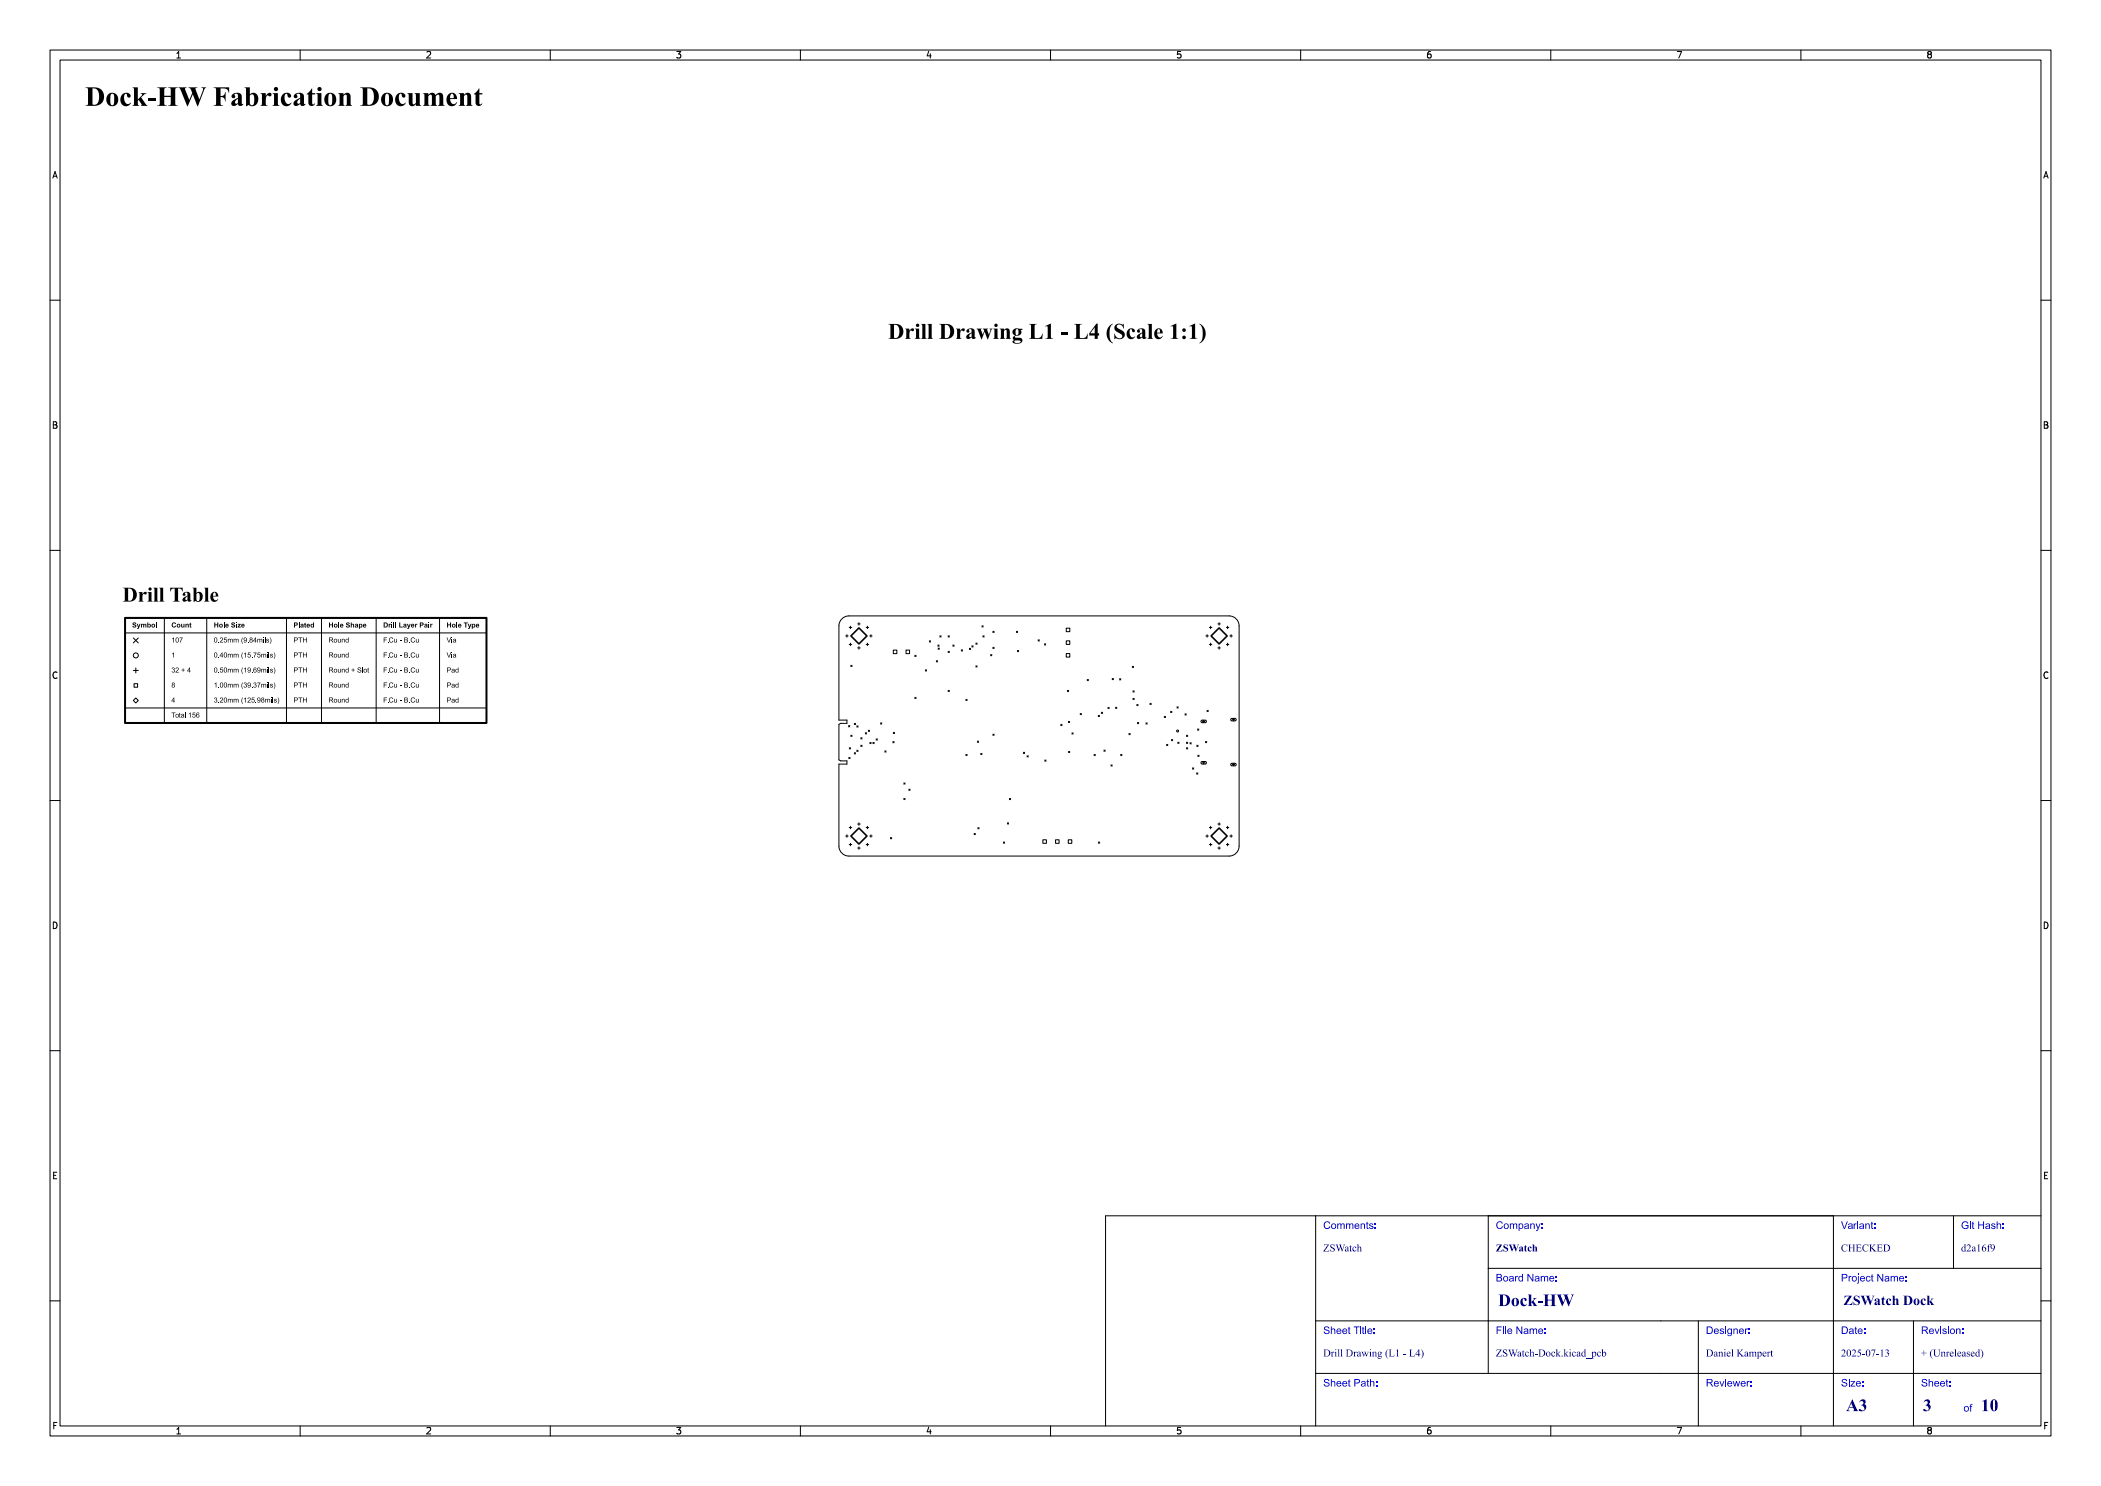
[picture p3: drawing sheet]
<svg xmlns="http://www.w3.org/2000/svg" width="420mm" height="297mm" viewBox="0 0 420 297" stroke-linecap="round" stroke-linejoin="round" font-family="sans-serif">
<defs><g id="words">
<text font-size="5.3" fill="#fff" x="17" y="21.5">Dock-HW Fabrication Document</text>
<text font-size="4.3" fill="#fff" x="166.6" y="68">Drill Drawing L1 - L4 (Scale 1:1)</text>
<g font-size="3.3" fill="#fff">
<text x="299.5" y="261.2">Dock-HW</text>
<text x="369" y="282.2">A3</text>
<text x="384.4" y="282.3">3</text>
<text x="396" y="282.3">10</text>
</g>
<text font-size="2.7" fill="#fff" x="368.5" y="261">ZSWatch Dock</text>
<g font-size="2" fill="#fff">
<text x="264.5" y="245.8">Comments:</text>
<text x="299" y="245.8">Company:</text>
<text x="368" y="245.8">Variant:</text>
<text x="392" y="245.8">Git Hash:</text>
<text x="264.5" y="250.2">ZSWatch</text>
<text x="299" y="250.2">ZSWatch</text>
<text x="368" y="250.2">CHECKED</text>
<text x="392" y="250.2">d2a16f9</text>
<text x="299" y="256.2">Board Name:</text>
<text x="368" y="256.2">Project Name:</text>
<text x="264.5" y="266.8">Sheet Title:</text>
<text x="299" y="266.8">File Name:</text>
<text x="341" y="266.8">Designer:</text>
<text x="368" y="266.8">Date:</text>
<text x="384" y="266.8">Revision:</text>
<text x="264.5" y="271.2">Drill Drawing (L1 - L4)</text>
<text x="299" y="271.2">ZSWatch-Dock.kicad_pcb</text>
<text x="341" y="271.2">Daniel Kampert</text>
<text x="368" y="271.2">2025-07-13</text>
<text x="384" y="271.2">+ (Unreleased)</text>
<text x="264.5" y="277.3">Sheet Path:</text>
<text x="341" y="277.2">Reviewer:</text>
<text x="368" y="277.3">Size:</text>
<text x="384" y="277.2">Sheet:</text>
<text x="392.5" y="282.3">of</text>
</g>
<g font-size="1.7" fill="#fff">
<text x="35" y="11.6">1</text>
<text x="85" y="11.6">2</text>
<text x="135" y="11.6">3</text>
<text x="185" y="11.6">4</text>
<text x="235" y="11.6">5</text>
<text x="285" y="11.6">6</text>
<text x="335" y="11.6">7</text>
<text x="385" y="11.6">8</text>
<text x="10.5" y="35.6">A</text>
<text x="408.5" y="35.6">A</text>
<text x="10.5" y="85.6">B</text>
<text x="408.5" y="85.6">B</text>
<text x="10.5" y="135.7">C</text>
<text x="408.5" y="135.7">C</text>
<text x="10.5" y="185.6">D</text>
<text x="408.5" y="185.6">D</text>
<text x="10.5" y="235.7">E</text>
<text x="408.5" y="235.7">E</text>
<text x="10.5" y="285.6">F</text>
<text x="35" y="286.7">1</text>
<text x="85" y="286.7">2</text>
<text x="135" y="286.7">3</text>
<text x="185" y="286.7">4</text>
<text x="235" y="286.7">5</text>
<text x="285" y="286.7">6</text>
<text x="335" y="286.7">7</text>
<text x="385" y="286.7">8</text>
<text x="408.5" y="285.6">F</text>
</g>
</g></defs>
<path d="M25 123.5h72.2v21h-72.2z" fill="none" stroke="#000" stroke-width=".4"/>
<g fill="none" stroke="#000" stroke-width=".2">
<path d="M10 10h400v277h-400zM12 12h396v273h-396zM35.3 11.6h.8M35.3 10.7l.4-.4v1.3M60 10v2M85.3 10.4l.5-.1 .3 .4-.8 .9h.8M110 10v2M135.3 10.3h.8l-.4 .5 .3 .1v.6l-.2 .1-.5-.1M160 10v2M185.7 10.2l-.4 1h.9M186 10.7v.9M210 10v2"/>
<path d="M236 10.3h-.6l-.1 .6 .2-.1 .5 .1 .1 .1-.1 .5-.2 .1-.5-.1M260 10v2M286 10.3l-.4 .1-.2 .2-.1 .7 .3 .3 .4-.1 .1-.5-.1-.1-.4-.1-.3 .2M310 10v2M335.3 10.3h.9l-.6 1.3M360 10v2M385.6 10.9l-.3 .2 .1 .4 .2 .1 .4-.1 .1-.2-.1-.3-.2-.1M385.6 10.9l-.3-.3 .3-.3h.2l.3 .2-.3 .4M385.6 10.9h.2M10.6 35.6l.4-1.3 .4 1.3M10.7 35.2h.6M408.6 35.6l.4-1.3 .4 1.3"/>
<path d="M408.7 35.2h.6M10 60h2M408 60h2M10.7 84.3h.4l.2 .2-.2 .4 .2 .1 .1 .3-.2 .3h-.5zM10.7 84.9h.4M408.6 84.3h.5l.2 .2-.2 .4 .2 .1 .1 .3-.3 .3h-.5zM408.6 84.9h.5M10 110h2M408 110h2M11.4 134.4a.62 .62 0 0 0-.9 .5 .62 .62 0 0 0 .7 .7l.2-.1M25 123.5h72.2M25 126.5h72.2"/>
<path d="M26.6 134h1.1M26.6 127.5l1.1 1M26.8 136.6h.7v.8h-.7zM27.2 133.5v1M27.7 127.5l-1.1 1M32.9 123.5v21M41.3 123.5v21M57.3 123.5v21M64.3 123.5v21M75.2 123.5v21M87.9 123.5v21M168.3 123.7l.9-.5 .5-.1h76a2 2 0 0 1 2 2v44a2 2 0 0 1-2 2h-76a2 2 0 0 1-2-2v-16.4h1.6v-.6h-1.2l-.4-.2v-7.1l.4-.2h1.2v-.7h-1.6v-18.8l.1-.5z"/>
<path d="M169 127.1h.5M169.3 126.8v.5M169.8 128.8h.5M169.8 125.4h.5M170 125.2v.5M170 128.5v.5M170.1 133l.2 .2M170.3 133l-.2 .2M171.4 129.5h.6M171.4 124.7h.6M171.7 124.5v.4M171.7 129.3v.5"/>
<path d="M173.1 128.8h.5M173.1 125.4h.5M173.4 125.2v.5M173.4 128.5v.5M173.9 127.1h.4M174.1 126.8v.5M178.6 129.9h.7v.7h-.7zM181.1 129.9h.7v.7h-.7zM182.9 139.4l.2 .2M182.9 131l.2 .2M183.1 131l-.2 .2M183.1 139.4l-.2 .2"/>
<path d="M185 133.9l.2 .2M185.2 133.9l-.2 .2M185.8 128.1l.2 .2M186 128.1l-.2 .2M187.2 132.1l.2 .2M187.4 132.1l-.2 .2M187.5 128.9l.2 .3M187.5 129.5l.3 .3M187.7 128.9l-.2 .3M187.8 129.5l-.3 .3M187.9 127.1l.2 .2M188.1 127.1l-.2 .2"/>
<path d="M189.5 138l.3 .2M189.5 130.2l.3 .2M189.5 127.1l.3 .2M189.8 138l-.3 .2M189.8 130.2l-.3 .2M189.8 127.1l-.3 .2M190.5 128.9l.2 .3M190.7 128.9l-.2 .3M192.2 129.9l.2 .2M192.4 129.9l-.2 .2M193.1 139.8l.2 .2M193.3 139.8l-.2 .2"/>
<path d="M193.8 129.6l.2 .2M194 129.6l-.2 .2M194.3 129.1l.2 .2M194.5 129.1l-.2 .2M195.1 133.1l.2 .2M195.1 128.5l.2 .3M195.3 128.5l-.2 .3M195.3 133.1l-.2 .2M196.3 125.1l.2 .2M196.5 127.1l.2 .2M196.5 125.1l-.2 .2M196.7 127.1l-.2 .2"/>
<path d="M198 130.8l.3 .3M198.3 130.8l-.3 .3M198.5 129.4l.2 .2M198.5 126.2l.2 .2M198.7 129.4l-.2 .2M198.7 126.2l-.2 .2M203.2 126.2l.2 .2M203.4 130l.2 .2M203.4 126.2l-.2 .2M203.6 130l-.2 .2M207.5 127.9l.3 .2M207.8 127.9l-.3 .2"/>
<path d="M208.8 128.7l.2 .2M209 128.7l-.2 .2M213.1 130.6h.8v.7h-.8zM213.1 128.1h.8v.7h-.8zM213.1 125.5h.8v.8h-.8zM213.4 138l.2 .2M213.6 138l-.2 .2M217.3 135.8l.3 .2M217.6 135.8l-.3 .2M222.3 135.6l.3 .2M222.6 135.6l-.3 .2M223.8 135.7l.2 .2"/>
<path d="M224 135.7l-.2 .2M226.3 133.2l.3 .2M226.5 139.6l.2 .2M226.5 138.1l.2 .2M226.6 133.2l-.3 .2M226.7 139.6l-.2 .2M226.7 138.1l-.2 .2M241.1 127.1h.4M241.3 126.8v.5M241.8 128.8h.5M241.8 125.4h.5M242 125.2v.5"/>
<path d="M242 128.5v.5M243.4 129.5h.6M243.4 124.7h.6M243.7 124.5v.4M243.7 129.3v.5M245.1 128.8h.5M245.1 125.4h.5M245.4 125.2v.5M245.4 128.5v.5M245.9 127.1h.5M246.1 126.8v.5M409.4 134.4a.62 .62 0 0 0-.9 .5 .62 .62 0 0 0 .6 .7l.3-.1"/>
<path d="M10 160h2M25 144.5h72.2M25 141.5h72.2M26.6 140l.6-.5 .5 .5-.5 .5zM169.6 145l.3 .3M169.7 151.4l.2 .2M169.8 149.4l.2 .3M169.9 145l-.3 .3M169.9 151.4l-.2 .2M170 149.4l-.2 .3M170.1 146.9l.2 .3M170.3 146.9l-.2 .3"/>
<path d="M170.8 150.4l.2 .3M170.8 144.6l.2 .2M171 150.4l-.2 .3M171 144.6l-.2 .2M171.3 149.9l.2 .3M171.3 145.1l.2 .2M171.5 149.9l-.2 .3M171.5 145.1l-.2 .2M172.1 148.9l.2 .3M172.1 147.4l.2 .3M172.3 147.4l-.2 .3M172.3 148.9l-.2 .3"/>
<path d="M173 146.4l.2 .3M173.2 146.4l-.2 .3M173.6 145.9l.2 .3M173.8 145.9l-.2 .3M173.9 148.4l.2 .2M174.1 148.4l-.2 .2M174.5 148.4l.2 .2M174.7 148.4l-.2 .2M175.1 147.7l.3 .2M175.4 147.7l-.3 .2M176 144.5l.3 .2M176.3 144.5l-.3 .2"/>
<path d="M176.9 150.1l.2 .2M177.1 150.1l-.2 .2M178.5 148.2l.2 .3M178.6 146.4l.2 .2M178.7 148.2l-.2 .3M178.8 146.4l-.2 .2M180.7 159.6l.2 .2M180.7 156.5l.2 .2M180.9 159.6l-.2 .2M180.9 156.5l-.2 .2M181.7 157.7l.2 .3M181.9 157.7l-.2 .3"/>
<path d="M193.1 150.8l.2 .2M193.3 150.8l-.2 .2M195.4 148.1l.2 .3M195.6 148.1l-.2 .3M196 150.6l.3 .2M196.3 150.6l-.3 .2M198.5 146.7l.2 .3M198.7 146.7l-.2 .3M201.8 159.6l.2 .2M202 159.6l-.2 .2M204.6 150.3l.2 .3M204.8 150.3l-.2 .3"/>
<path d="M205.3 151l.2 .3M205.5 151l-.2 .3M208.9 151.9l.2 .3M209.1 151.9l-.2 .3M212 144.8l.3 .2M212.3 144.8l-.3 .2M213.6 144.2l.2 .2M213.6 150.2l.2 .2M213.8 144.2l-.2 .2M213.8 150.2l-.2 .2M214.3 146.5l.2 .2M214.5 146.5l-.2 .2"/>
<path d="M215.9 142.6l.3 .3M216.2 142.6l-.3 .3M218.7 150.8l.2 .2M218.9 150.8l-.2 .2M219.5 143l.3 .2M219.8 143l-.3 .2M220.2 142.3l.2 .3M220.4 142.3l-.2 .3M220.7 149.9l.2 .3M220.9 149.9l-.2 .3M221.5 141.4l.2 .2M221.7 141.4l-.2 .2"/>
<path d="M222.1 152.9l.2 .2M222.3 152.9l-.2 .2M223 141.3l.3 .3M223.3 141.3l-.3 .3M224 150.8l.3 .2M224.3 150.8l-.3 .2M225.7 146.6l.2 .3M225.9 146.6l-.2 .3M227.2 140.8l.3 .3M227.4 144.4l.2 .2M227.5 140.8l-.3 .3M227.6 144.4l-.2 .2"/>
<path d="M229.1 144.5l.2 .2M229.3 144.5l-.2 .2M229.9 140.6l.2 .2M230.1 140.6l-.2 .2M232.7 143.2l.3 .2M233 143.2l-.3 .2M233.2 148.8l.2 .2M233.4 148.8l-.2 .2M234 142.2l.3 .2M234.2 147.8l.2 .2M234.3 142.2l-.3 .2M234.4 147.8l-.2 .2"/>
<path d="M235.3 141.3l.2 .2M235.4 148.3l.3 .3M235.5 141.3l-.2 .2M235.7 148.3l-.3 .3M236.9 142.7l.2 .2M237.1 142.7l-.2 .2M237.2 149.4l.2 .3M237.2 148.3l.2 .3M237.2 146.9l.2 .3M237.4 149.4l-.2 .3M237.4 148.3l-.2 .3M237.4 146.9l-.2 .3"/>
<path d="M237.9 148.4l.2 .3M238.1 148.4l-.2 .3M238.4 153.5l.2 .2M238.6 153.5l-.2 .2M239.2 154.5l.3 .2M239.2 148.9l.3 .3M239.4 145.7l.2 .2M239.4 150.9l.3 .3M239.5 154.5l-.3 .2M239.5 148.9l-.3 .3M239.6 145.7l-.2 .2M239.7 150.9l-.3 .3"/>
<path d="M240.1 152.3l.8-.1 .3 .2-.3 .3h-.6l-.2-.1zM240.1 144l.8-.1 .3 .3-.3 .2h-.6h-.2zM240.4 152.4h.5M240.4 144.2h.5M240.6 143.9v.5M240.6 152.2v.5M241 148.2l.2 .2M241.2 148.2l-.2 .2M241.3 142l.2 .2M241.5 142l-.2 .2M246.1 152.6h.8l.2 .2-.2 .3h-.6l-.3-.3zM246.1 143.7l.8-.1 .2 .2-.2 .3h-.6l-.3-.3z"/>
<path d="M246.3 152.8h.5M246.3 143.8h.5M246.6 143.6v.5M246.6 152.6v.5M408 160h2M169 167.1h.5M169.3 166.9v.5M169.8 168.8h.5M169.8 165.4h.5M170 165.2v.5M170 168.5v.5M171.4 169.5h.6"/>
<path d="M171.4 164.7h.6M171.7 164.4v.5M171.7 169.3v.4M173.1 168.8h.5M173.1 165.4h.5M173.4 165.2v.5M173.4 168.5v.5M173.9 167.1h.4M174.1 166.9v.5M178 167.4l.3 .2M178.3 167.4l-.3 .2M194.7 166.6l.3 .2"/>
<path d="M195 166.6l-.3 .2M195.5 165.4l.2 .3M195.7 165.4l-.2 .3M200.6 168.3l.2 .2M200.8 168.3l-.2 .2M201.4 164.4l.2 .3M201.6 164.4l-.2 .3M208.5 167.8h.7v.8h-.7zM211 167.8h.7v.8h-.7zM213.5 167.8h.8v.8h-.8zM219.6 168.3l.2 .2M219.8 168.3l-.2 .2"/>
<path d="M241.1 167.1h.4M241.3 166.9v.5M241.8 168.8h.5M241.8 165.4h.5M242 165.2v.5M242 168.5v.5M243.4 169.5h.6M243.4 164.7h.6M243.7 164.4v.5M243.7 169.3v.4M245.1 168.8h.5M245.1 165.4h.5"/>
<path d="M245.4 165.2v.5M245.4 168.5v.5M245.9 167.1h.5M246.1 166.9v.5M10.7 184.3a.66 .66 0 0 1 .7 .6 .66 .66 0 0 1-.7 .7zM408.6 184.3a.66 .66 0 0 1 .8 .6 .66 .66 0 0 1-.8 .7zM10 210h2M408 210h2M10.7 234.9h.5M11.3 234.3h-.6v1.3h.6M408.7 234.9h.4M409.3 234.3h-.6v1.3h.6"/>
<path d="M10 260h2M408 260h2M10.8 284.9h.4M11.4 284.3h-.6v1.3M35.3 285.7l.4-.4v1.3M35.3 286.6h.8M60 285v2M85.3 285.4l.5-.1 .3 .4-.8 .9h.8M110 285v2M135.3 285.3h.8l-.4 .5 .3 .1v.6l-.2 .1-.5-.1M160 285v2M185.7 285.2l-.4 1h.9"/>
<path d="M186 285.7v.9M210 285v2M236 285.3h-.6l-.1 .6 .2-.1 .5 .1 .1 .1-.1 .5-.2 .1-.5-.1M260 285v2M286 285.3l-.4 .1-.2 .2-.1 .7 .3 .3 .4-.1 .1-.5-.1-.1-.4-.1-.3 .2M310 285v2M335.3 285.3h.9l-.6 1.3M360 285v2M385.6 285.9l-.3-.3 .3-.3h.2l.3 .2-.3 .4M385.6 285.9l-.3 .2v.2l.3 .3 .4-.1 .1-.2v-.2l-.3-.2M385.6 285.9h.2M408.7 284.9h.5"/>
<path d="M409.4 284.3h-.7v1.3"/>
<circle cx="27.2" cy="131" r=".5"/>
<circle cx="235.4" cy="146.1" r=".2"/>
</g>
<g fill="#000">
<path d="M24.6 117.5h1.2a1.4 1.4 0 0 1 1.6 1.4 1.4 1.4 0 0 1-1.6 1.3h-1.2l.3-.1v-.3h.7v.1a.54 .54 0 0 0 .7 .2 .54 .54 0 0 0 .2-.6 1.32 1.32 0 0 0-.7-1.9h-.2v2.2h-.7v-2.1z" fill-rule="evenodd"/>
<path d="M27.7 118.3h.8v.5a.46 .46 0 0 1 .3-.5 .46 .46 0 0 1 .5 .2 .33 .33 0 0 1-.2 .3 .33 .33 0 0 1-.4-.1l-.2 .4v.7v.3l.2 .1h-1l.2-.4v-1.2z" fill-rule="evenodd"/>
<path d="M29.5 118.3h.8v1.7l.2 .2h-1l.2-.4v-1.3z" fill-rule="evenodd"/>
<path d="M30.6 117.5h.9v2.5l.2 .2h-1.1l.3-.4v-2.1z" fill-rule="evenodd"/>
<path d="M31.8 117.5h.8v2.5l.3 .2h-1.1l.2-.4v-2.1z" fill-rule="evenodd"/>
<path d="M34 117.5h2.5v.7a.76 .76 0 0 0-.9-.6v2.4l.4 .2h-1.5l.4-.2v-2.4a.75 .75 0 0 0-.9 .6z" fill-rule="evenodd"/>
<path d="M36.6 118.6a.79 .79 0 0 1 .9-.3 .79 .79 0 0 1 .6 .7v.9h.2a.39 .39 0 0 1-.4 .4 .39 .39 0 0 1-.4-.3 .51 .51 0 0 1-.6 .3 .51 .51 0 0 1-.4-.5l.5-.1 .2 .2 .3-.1v-.6l-.5 .5h-.5l1-.7v-.4a.25 .25 0 0 0-.4-.2 .25 .25 0 0 0 0 .4 .3 .3 0 0 1-.5 .2 .3 .3 0 0 1 0-.4z" fill-rule="evenodd"/>
<path d="M38.5 117.5h.8v1a.78 .78 0 0 1 1 0 .78 .78 0 0 1 .2 .9 .88 .88 0 0 1-.5 .8 .88 .88 0 0 1-.9-.1l-.4 .2v-1.6h.6a1.58 1.58 0 0 0 .1 1.4h.3a1.43 1.43 0 0 0 0-1.6l-.4 .2h-.6v-1z" fill-rule="evenodd"/>
<path d="M40.8 117.5h.8v2.5l.2 .2h-1l.2-.4v-2.1z" fill-rule="evenodd"/>
<path d="M42.3 118.6a.77 .77 0 0 1 .9-.2 .77 .77 0 0 1 .4 .8h-1a.54 .54 0 0 0 .3 .7 .54 .54 0 0 0 .7-.2 .82 .82 0 0 1-1.1 .5 .82 .82 0 0 1-.4-1.1h1l-.1-.6a.37 .37 0 0 0-.4 .1 .37 .37 0 0 0 0 .4h-.5z" fill-rule="evenodd"/>
<path d="M26.6 124.5l.3-.1 .3 .2v.1h-.2l-.3-.1 .1 .2a.38 .38 0 0 1 .4 .3 .38 .38 0 0 1-.2 .4 .38 .38 0 0 1-.5-.3v-.1h.1a.19 .19 0 0 0 .3 .2 .19 .19 0 0 0 .1-.3l-.5-.2z" fill-rule="evenodd"/>
<path d="M27.3 124.7h.2l.2 .5 .2-.5h.2l-.5 1h-.2v-.1l.2-.2z" fill-rule="evenodd"/>
<path d="M28.2 124.7h1l.1 .7h-.2l-.1-.6-.2 .1v.5h-.2l-.1-.6-.1 .1v.5h-.2z" fill-rule="evenodd"/>
<path d="M29.4 124.4h.2v.4a.33 .33 0 0 1 .5 0 .33 .33 0 0 1 0 .5 .33 .33 0 0 1-.5 0l-.2 .1v-.4h.2l.1 .2a.18 .18 0 0 0 .3 0 .18 .18 0 0 0-.1-.3 .18 .18 0 0 0-.3 .1h-.2z" fill-rule="evenodd"/>
<path d="M30.4 124.8a.38 .38 0 0 1 .6 .1 .38 .38 0 0 1-.3 .5 .38 .38 0 0 1-.4-.3h.2a.19 .19 0 0 0 .2 .1 .19 .19 0 0 0 .1-.3 .19 .19 0 0 0-.3 .1l-.2 .1z" fill-rule="evenodd"/>
<path d="M31.2 124.4h.2v1h-.2z" fill-rule="evenodd"/>
<path d="M34.4 133.5a.27 .27 0 0 1 .4-.1 .27 .27 0 0 1 0 .5 .31 .31 0 0 1 0 .5 .31 .31 0 0 1-.5-.3h.1a.2 .2 0 0 0 .3 .2 .2 .2 0 0 0 .1-.2 .2 .2 0 0 0-.2-.2v-.1a.17 .17 0 0 0 .2-.1 .17 .17 0 0 0-.2-.2 .17 .17 0 0 0-.2 .2h-.1z" fill-rule="evenodd"/>
<path d="M34.4 136.5a.27 .27 0 0 1 .4 0 .27 .27 0 0 1 0 .4 .32 .32 0 0 1 0 .5 .32 .32 0 0 1-.5-.3h.1a.21 .21 0 0 0 .3 .2 .21 .21 0 0 0 .1-.3 .21 .21 0 0 0-.4 .1h-.1l.2-.2-.1-.2h.1a.16 .16 0 0 0 .2 .1 .16 .16 0 0 0 0-.3 .16 .16 0 0 0-.2 .1l-.1 .1z" fill-rule="evenodd"/>
<path d="M34.4 130.7l.4-.3v1h-.1v-.8l-.3 .2z" fill-rule="evenodd"/>
<path d="M34.4 127.7l.4-.3v1h-.1v-.8l-.3 .2z" fill-rule="evenodd"/>
<path d="M34.4 124.5l.6-.1 .2 .3h-.2a.27 .27 0 0 0-.4 0 .27 .27 0 0 0 0 .4 .27 .27 0 0 0 .4 0h.2a.49 .49 0 0 1-.8 .2 .49 .49 0 0 1 0-.8z" fill-rule="evenodd"/>
<path d="M35.2 127.5l.1-.1a.49 .49 0 0 1 .5 .5 .49 .49 0 0 1-.5 .5l-.2-.3v-.2h.1a.25 .25 0 0 0 0 .4 .25 .25 0 0 0 .4 0 .25 .25 0 0 0 0-.4 .25 .25 0 0 0 0-.3 .25 .25 0 0 0-.4 0 .25 .25 0 0 0 0 .3h-.1z" fill-rule="evenodd"/>
<path d="M35.2 133.5a.35 .35 0 0 1 .5 .1 .35 .35 0 0 1-.3 .5l-.2 .2h.5v.1h-.6l.3-.4a.21 .21 0 0 0 .3-.3 .21 .21 0 0 0-.2-.2 .21 .21 0 0 0-.3 .2h-.1z" fill-rule="evenodd"/>
<path d="M35.4 124.8a.38 .38 0 0 1 .6 .1 .38 .38 0 0 1-.2 .5 .38 .38 0 0 1-.5-.3h.2a.19 .19 0 0 0 .3 .1 .19 .19 0 0 0 0-.3 .19 .19 0 0 0-.3 .1l-.2 .1z" fill-rule="evenodd"/>
<path d="M35.9 127.4h.6l-.4 1h-.1l.1-.3 .3-.6h-.5z" fill-rule="evenodd"/>
<path d="M36.5 133.6h.2v.3h.2v.1h-.2v.3h-.2v-.3h-.2v-.1h.2z" fill-rule="evenodd"/>
<path d="M36.2 124.7h.2l.1 .6 .2-.1v-.5h.2v.7h-.6z" fill-rule="evenodd"/>
<path d="M37.1 124.7l.6 .1v.6h-.2l-.1-.6-.1 .1v.5h-.2z" fill-rule="evenodd"/>
<path d="M37.9 133.4l.1 .7h.1l-.1 .3h-.1v-.2h-.5v-.1h.5v-.5l-.5 .5z" fill-rule="evenodd"/>
<path d="M37.9 124.5l.2-.1v.3h.2l-.2 .4 .2 .3-.3-.1z" fill-rule="evenodd"/>
<path d="M42.8 124.4h.2v.4h.4v-.4h.2v1h-.2v-.4h-.4v.4h-.2z" fill-rule="evenodd"/>
<path d="M42.9 133.5l.1-.1a.49 .49 0 0 1 .5 .5 .49 .49 0 0 1-.5 .5l-.2-.3v-.2h.1a.25 .25 0 0 0 0 .4 .25 .25 0 0 0 .4 0 .25 .25 0 0 0 0-.4 .25 .25 0 0 0 0-.3 .25 .25 0 0 0-.4 0 .25 .25 0 0 0 0 .3l-.1-.1z" fill-rule="evenodd"/>
<path d="M42.9 130.5l.1-.1a.49 .49 0 0 1 .5 .5 .49 .49 0 0 1-.5 .5l-.2-.3v-.2h.1a.25 .25 0 0 0 0 .4 .25 .25 0 0 0 .4 0 .25 .25 0 0 0 0-.4 .25 .25 0 0 0 0-.3 .25 .25 0 0 0-.4 0 .25 .25 0 0 0 0 .3l-.1-.1z" fill-rule="evenodd"/>
<path d="M42.9 127.5l.1-.1a.49 .49 0 0 1 .5 .5 .49 .49 0 0 1-.5 .5l-.2-.3v-.2h.1a.25 .25 0 0 0 0 .4 .25 .25 0 0 0 .4 0 .25 .25 0 0 0 0-.4 .25 .25 0 0 0 0-.3 .25 .25 0 0 0-.4 0 .25 .25 0 0 0 0 .3l-.1-.1z" fill-rule="evenodd"/>
<path d="M42.9 136.7l.4-.3v1h-.2v-.8l-.2 .2z" fill-rule="evenodd"/>
<path d="M43.6 137.3l.2 .1z" fill-rule="evenodd"/>
<path d="M43.6 134.3l.2 .1z" fill-rule="evenodd"/>
<path d="M43.6 131.3l.2 .1z" fill-rule="evenodd"/>
<path d="M43.6 128.3l.2 .1z" fill-rule="evenodd"/>
<path d="M44.1 133.4h.5v.1h-.4l-.1 .3a.33 .33 0 0 1 .5 .2 .33 .33 0 0 1-.2 .4 .33 .33 0 0 1-.4-.3h.1a.22 .22 0 0 0 .3 .1 .22 .22 0 0 0 0-.3 .22 .22 0 0 0-.3 .1l-.1-.1z" fill-rule="evenodd"/>
<path d="M43.9 124.8a.38 .38 0 0 1 .6 .1 .38 .38 0 0 1-.2 .5 .38 .38 0 0 1-.5-.3h.2a.19 .19 0 0 0 .3 .1 .19 .19 0 0 0 0-.3 .19 .19 0 0 0-.3 .1l-.2 .1z" fill-rule="evenodd"/>
<path d="M44.1 136.5l.1-.1a.49 .49 0 0 1 .4 .5 .49 .49 0 0 1-.4 .5l-.2-.3v-.2h.1a.25 .25 0 0 0 0 .4 .25 .25 0 0 0 .4 0 .25 .25 0 0 0 0-.4 .25 .25 0 0 0 0-.3 .25 .25 0 0 0-.4 0 .25 .25 0 0 0 0 .3h-.1z" fill-rule="evenodd"/>
<path d="M44.4 130.4l.1 .7h.1l-.1 .3h-.2v-.2h-.4v-.1h.4v-.5l-.4 .5z" fill-rule="evenodd"/>
<path d="M44.1 127.5a.35 .35 0 0 1 .5 .1 .35 .35 0 0 1-.3 .5l-.2 .2h.5v.1h-.7l.4-.4a.21 .21 0 0 0 .2-.3 .21 .21 0 0 0-.2-.2 .21 .21 0 0 0-.2 .2h-.1z" fill-rule="evenodd"/>
<path d="M44.7 124.4h.2v1h-.2z" fill-rule="evenodd"/>
<path d="M44.9 127.4h.4v.1h-.4v.3a.33 .33 0 0 1 .5 .2 .33 .33 0 0 1-.2 .4 .33 .33 0 0 1-.5-.3h.2a.22 .22 0 0 0 .3 .1 .22 .22 0 0 0 0-.3 .22 .22 0 0 0-.3 .1l-.1-.1z" fill-rule="evenodd"/>
<path d="M44.8 139.5l.1-.1a.49 .49 0 0 1 .5 .5 .49 .49 0 0 1-.5 .5l-.2-.4 .2-.1a.25 .25 0 0 0 0 .4 .25 .25 0 0 0 .3 0 .25 .25 0 0 0 .1-.4 .25 .25 0 0 0-.1-.3 .25 .25 0 0 0-.3 0 .25 .25 0 0 0 0 .3h-.2z" fill-rule="evenodd"/>
<path d="M44.8 136.5l.1-.1a.49 .49 0 0 1 .5 .5 .49 .49 0 0 1-.5 .5l-.2-.4 .2-.1a.25 .25 0 0 0 0 .4 .25 .25 0 0 0 .3 0 .25 .25 0 0 0 .1-.4 .25 .25 0 0 0-.1-.3 .25 .25 0 0 0-.3 0 .25 .25 0 0 0 0 .3h-.2z" fill-rule="evenodd"/>
<path d="M44.8 133.5l.1-.1a.49 .49 0 0 1 .5 .5 .49 .49 0 0 1-.5 .5l-.2-.4 .2-.1a.25 .25 0 0 0 0 .4 .25 .25 0 0 0 .3 0 .25 .25 0 0 0 .1-.4 .25 .25 0 0 0-.1-.3 .25 .25 0 0 0-.3 0 .25 .25 0 0 0 0 .3h-.2z" fill-rule="evenodd"/>
<path d="M44.8 130.5l.1-.1a.49 .49 0 0 1 .5 .5 .49 .49 0 0 1-.5 .5l-.2-.4 .2-.1a.25 .25 0 0 0 0 .4 .25 .25 0 0 0 .3 0 .25 .25 0 0 0 .1-.4 .25 .25 0 0 0-.1-.3 .25 .25 0 0 0-.3 0 .25 .25 0 0 0 0 .3h-.2z" fill-rule="evenodd"/>
<path d="M45.1 124.8l.5-.1 .1 .4-.5 .1 .2 .1 .3-.1a.35 .35 0 0 1-.4 .2 .35 .35 0 0 1-.3-.4h.5l-.1-.2-.4 .2z" fill-rule="evenodd"/>
<path d="M45.5 136.7h.9l.1 .7h-.1v-.5l-.1-.1-.2 .1v.5h-.1l-.2-.6-.1 .1v.5h-.2z" fill-rule="evenodd"/>
<path d="M45.5 133.7h.9l.1 .7h-.1v-.5l-.1-.1-.2 .1v.5h-.1l-.2-.6-.1 .1v.5h-.2z" fill-rule="evenodd"/>
<path d="M45.5 130.7l.6 .1 .3-.1 .1 .7h-.1v-.5l-.1-.1-.2 .1v.5h-.1l-.2-.6-.1 .1v.5h-.2z" fill-rule="evenodd"/>
<path d="M45.5 127.7l.6 .1 .3-.1 .1 .7h-.1v-.5l-.1-.1-.2 .1v.5h-.1l-.2-.6-.1 .1v.5h-.2z" fill-rule="evenodd"/>
<path d="M46.3 124.5l.4-.1 .3 .2v.1h-.2l-.3-.1v.2a.38 .38 0 0 1 .5 .3 .38 .38 0 0 1-.3 .4 .38 .38 0 0 1-.5-.3v-.1h.2a.19 .19 0 0 0 .2 .2 .19 .19 0 0 0 .1-.3l-.4-.2z" fill-rule="evenodd"/>
<path d="M46.7 136.7h.9l.1 .7h-.1v-.5l-.2-.1-.1 .1v.5h-.2v-.5l-.1-.1-.1 .1-.1 .5h-.1z" fill-rule="evenodd"/>
<path d="M46.7 133.7h.9l.1 .7h-.1v-.5l-.2-.1-.1 .1v.5h-.2v-.5l-.1-.1-.1 .1-.1 .5h-.1z" fill-rule="evenodd"/>
<path d="M46.7 130.7l.5 .1 .4-.1 .1 .7h-.1v-.5l-.2-.1-.1 .1v.5h-.2v-.5l-.1-.1-.1 .1-.1 .5h-.1z" fill-rule="evenodd"/>
<path d="M46.7 127.7l.5 .1 .4-.1 .1 .7h-.1v-.5l-.2-.1-.1 .1v.5h-.2v-.5l-.1-.1-.1 .1-.1 .5h-.1z" fill-rule="evenodd"/>
<path d="M47.2 124.4h.2v.2h-.2z" fill-rule="evenodd"/>
<path d="M47.2 124.7h.2v.7h-.2z" fill-rule="evenodd"/>
<path d="M47.5 124.7h.6l-.4 .6 .4-.1v.2h-.6l.4-.6h-.4z" fill-rule="evenodd"/>
<path d="M48.5 136.4l-.1 .8 .2 .5-.3-.6z" fill-rule="evenodd"/>
<path d="M48.5 133.4l-.1 .8 .2 .5-.3-.6z" fill-rule="evenodd"/>
<path d="M48.5 130.4l-.1 .8 .2 .5-.3-.6z" fill-rule="evenodd"/>
<path d="M48.5 127.4l-.1 .8 .2 .5-.3-.6z" fill-rule="evenodd"/>
<path d="M48.3 124.8l.5-.1 .1 .4-.5 .1 .2 .1 .3-.1a.35 .35 0 0 1-.5 .2 .35 .35 0 0 1-.2-.4h.5l-.1-.2-.4 .2z" fill-rule="evenodd"/>
<path d="M48.8 136.5a.27 .27 0 0 1 .4 0 .27 .27 0 0 1 0 .4 .31 .31 0 0 1 0 .5 .31 .31 0 0 1-.5-.3h.1a.2 .2 0 0 0 .3 .2 .2 .2 0 0 0 .1-.2 .2 .2 0 0 0-.3-.2l.1-.1a.17 .17 0 0 0 .2-.1 .17 .17 0 0 0-.2-.2 .17 .17 0 0 0-.2 .2h-.1z" fill-rule="evenodd"/>
<path d="M48.8 127.5a.46 .46 0 0 1 .6 .4 .46 .46 0 0 1-.6 .5l-.1-.2 .4 .1 .1-.4-.3 .2-.2-.3 .1-.1a.2 .2 0 0 0 .3 .2 .2 .2 0 0 0 0-.3 .2 .2 0 0 0-.3 .1h-.1z" fill-rule="evenodd"/>
<path d="M48.8 133.7l.4-.3v1h-.2v-.8l-.2 .2z" fill-rule="evenodd"/>
<path d="M48.8 130.7l.4-.3v1h-.2v-.8l-.2 .2z" fill-rule="evenodd"/>
<path d="M49.6 130.4h.5v.1h-.4l-.1 .3a.33 .33 0 0 1 .5 .2 .33 .33 0 0 1-.2 .4 .33 .33 0 0 1-.4-.3h.1a.22 .22 0 0 0 .3 .1 .22 .22 0 0 0 .1-.3 .22 .22 0 0 0-.4 .1l-.1-.1z" fill-rule="evenodd"/>
<path d="M49.5 128.3l.2 .1z" fill-rule="evenodd"/>
<path d="M49.6 136.5a.46 .46 0 0 1 .6 .4 .46 .46 0 0 1-.6 .5l-.1-.2 .3 .1 .2-.3-.3 .1-.2-.3 .1-.1a.2 .2 0 0 0 .3 .2 .2 .2 0 0 0 0-.3 .2 .2 0 0 0-.3 .1h-.1z" fill-rule="evenodd"/>
<path d="M49.6 133.5a.46 .46 0 0 1 .6 .4 .46 .46 0 0 1-.6 .5l-.1-.2 .3 .1 .2-.3-.3 .1-.2-.3 .1-.1a.2 .2 0 0 0 .3 .2 .2 .2 0 0 0 0-.3 .2 .2 0 0 0-.3 .1h-.1z" fill-rule="evenodd"/>
<path d="M50 127.5a.27 .27 0 0 1 .4 0 .27 .27 0 0 1-.1 .4 .32 .32 0 0 1 0 .5 .32 .32 0 0 1-.4-.3h.1a.21 .21 0 0 0 .3 .2 .21 .21 0 0 0 0-.3 .21 .21 0 0 0-.3 .1h-.1l.2-.2-.2-.2h.1a.16 .16 0 0 0 .3 .1 .16 .16 0 0 0 0-.3 .16 .16 0 0 0-.3 .1l-.1 .1z" fill-rule="evenodd"/>
<path d="M50.3 137.3l.2 .1z" fill-rule="evenodd"/>
<path d="M50.3 134.3l.2 .1z" fill-rule="evenodd"/>
<path d="M50.3 131.3l.2 .1z" fill-rule="evenodd"/>
<path d="M50.7 136.5a.27 .27 0 0 1 .4-.1 .27 .27 0 0 1 0 .5 .31 .31 0 0 1 0 .5 .31 .31 0 0 1-.5-.3h.2a.2 .2 0 0 0 .2 .2 .2 .2 0 0 0 .2-.2 .2 .2 0 0 0-.3-.2v-.1a.17 .17 0 0 0 .2-.1 .17 .17 0 0 0-.2-.2 .17 .17 0 0 0-.1 .2h-.1z" fill-rule="evenodd"/>
<path d="M50.6 130.4h.7l-.4 1h-.1v-.3l.3-.6h-.5z" fill-rule="evenodd"/>
<path d="M50.8 133.5l.3-.1 .2 .3-.3-.2a.19 .19 0 0 0-.3 .1 .19 .19 0 0 0 .1 .2 .19 .19 0 0 0 .3 0 .33 .33 0 0 1 .2 .3 .33 .33 0 0 1-.4 .3 .33 .33 0 0 1-.3-.3h.2a.2 .2 0 0 0 .3 .2 .2 .2 0 0 0 0-.4 .2 .2 0 0 0-.3 .1l-.2 .1z" fill-rule="evenodd"/>
<path d="M51.1 127.4l.1 .7h.1l-.1 .3h-.2v-.2h-.4v-.1h.4v-.5l-.4 .5z" fill-rule="evenodd"/>
<path d="M51.5 130.4h.5v.1h-.4v.3a.33 .33 0 0 1 .5 .2 .33 .33 0 0 1-.3 .4 .33 .33 0 0 1-.4-.3h.1a.22 .22 0 0 0 .4 .1 .22 .22 0 0 0 0-.3 .22 .22 0 0 0-.3 .1l-.2-.1z" fill-rule="evenodd"/>
<path d="M51.4 136.4h.7l-.4 1h-.1v-.3l.3-.6h-.5z" fill-rule="evenodd"/>
<path d="M51.5 127.7l.5 .1 .3-.1 .1 .7h-.1v-.5l-.1-.1-.2 .1v.5h-.1v-.5l-.1-.1-.2 .1v.5h-.1z" fill-rule="evenodd"/>
<path d="M51.5 139.5a.46 .46 0 0 1 .6 .4 .46 .46 0 0 1-.5 .5l-.2-.2 .4 .1 .2-.4-.4 .2-.2-.3 .1-.1a.2 .2 0 0 0 .3 .2 .2 .2 0 0 0 .1-.3 .2 .2 0 0 0-.3 .1h-.2z" fill-rule="evenodd"/>
<path d="M51.5 133.5a.46 .46 0 0 1 .6 .4 .46 .46 0 0 1-.5 .5l-.2-.2 .4 .1 .2-.4-.4 .2-.2-.3 .1-.1a.2 .2 0 0 0 .3 .2 .2 .2 0 0 0 .1-.3 .2 .2 0 0 0-.3 .1h-.2z" fill-rule="evenodd"/>
<path d="M52.2 136.7h.9l.1 .7h-.1v-.5l-.1-.1-.2 .1v.5h-.1v-.5l-.2-.1-.1 .1v.5h-.2z" fill-rule="evenodd"/>
<path d="M52.2 133.7h.9l.1 .7h-.1v-.5l-.1-.1-.2 .1v.5h-.1v-.5l-.2-.1-.1 .1v.5h-.2z" fill-rule="evenodd"/>
<path d="M52.2 130.7l.6 .1 .3-.1 .1 .7h-.1v-.5l-.1-.1-.2 .1v.5h-.1v-.5l-.2-.1-.1 .1v.5h-.2z" fill-rule="evenodd"/>
<path d="M52.3 139.5a.27 .27 0 0 1 .4 0 .27 .27 0 0 1 0 .4 .32 .32 0 0 1 0 .5 .32 .32 0 0 1-.5-.3h.1a.21 .21 0 0 0 .3 .2 .21 .21 0 0 0 .1-.3 .21 .21 0 0 0-.4 .1h-.1l.2-.2-.2-.2h.2a.16 .16 0 0 0 .2 .1 .16 .16 0 0 0 0-.3 .16 .16 0 0 0-.2 .1l-.2 .1z" fill-rule="evenodd"/>
<path d="M52.6 127.4l.1 .1z" fill-rule="evenodd"/>
<path d="M52.6 127.7h.1v.7h-.1z" fill-rule="evenodd"/>
<path d="M52.9 127.4h.1v1h-.1z" fill-rule="evenodd"/>
<path d="M53.3 127.8l.4-.1 .1 .2-.5-.1 .2 .2a.27 .27 0 0 1 .2 .3 .27 .27 0 0 1-.3 .2 .27 .27 0 0 1-.2-.3h.1a.16 .16 0 0 0 .2 .2 .16 .16 0 0 0 .1-.3l-.3-.1z" fill-rule="evenodd"/>
<path d="M53.4 136.4l.1 .1z" fill-rule="evenodd"/>
<path d="M53.4 136.7h.1v.7h-.1z" fill-rule="evenodd"/>
<path d="M53.4 133.4l.1 .1z" fill-rule="evenodd"/>
<path d="M53.4 133.7h.1v.7h-.1z" fill-rule="evenodd"/>
<path d="M53.4 130.4l.1 .1z" fill-rule="evenodd"/>
<path d="M53.4 130.7h.1v.7h-.1z" fill-rule="evenodd"/>
<path d="M53.7 136.4h.1v1h-.1z" fill-rule="evenodd"/>
<path d="M53.7 133.4h.1v1h-.1z" fill-rule="evenodd"/>
<path d="M53.7 130.4h.1v1h-.1z" fill-rule="evenodd"/>
<path d="M54 136.8l.5-.1v.2l-.4-.1 .2 .2a.27 .27 0 0 1 .2 .3 .27 .27 0 0 1-.3 .2 .27 .27 0 0 1-.2-.3h.1a.16 .16 0 0 0 .2 .2 .16 .16 0 0 0 .1-.3l-.4-.1z" fill-rule="evenodd"/>
<path d="M54 133.8l.5-.1v.2l-.4-.1 .2 .2a.27 .27 0 0 1 .2 .3 .27 .27 0 0 1-.3 .2 .27 .27 0 0 1-.2-.3h.1a.16 .16 0 0 0 .2 .2 .16 .16 0 0 0 .1-.3l-.4-.1z" fill-rule="evenodd"/>
<path d="M54 130.8l.5-.1v.2l-.4-.1 .2 .2a.27 .27 0 0 1 .2 .3 .27 .27 0 0 1-.3 .2 .27 .27 0 0 1-.2-.3h.1a.16 .16 0 0 0 .2 .2 .16 .16 0 0 0 .1-.3l-.4-.1z" fill-rule="evenodd"/>
<path d="M53.9 127.4l.4 .5-.3 .8 .1-.8z" fill-rule="evenodd"/>
<path d="M54.2 139.4l.1 .1z" fill-rule="evenodd"/>
<path d="M54.2 139.7h.1v.7h-.1z" fill-rule="evenodd"/>
<path d="M54.5 139.4h.1v1h-.1z" fill-rule="evenodd"/>
<path d="M54.7 136.4l.3 .5-.2 .8 .1-.8z" fill-rule="evenodd"/>
<path d="M54.7 133.4l.3 .5-.2 .8 .1-.8z" fill-rule="evenodd"/>
<path d="M54.7 130.4l.3 .5-.2 .8 .1-.8z" fill-rule="evenodd"/>
<path d="M58.8 139.4h.4a.31 .31 0 0 1 .3 .3 .31 .31 0 0 1-.3 .3h-.3v.4h-.1v-.5h.5l.1-.2-.1-.2h-.4v.4h-.1z" fill-rule="evenodd"/>
<path d="M58.8 136.4h.4a.31 .31 0 0 1 .3 .3 .31 .31 0 0 1-.3 .3h-.3v.4h-.1v-.5h.5l.1-.2-.1-.2h-.4v.4h-.1z" fill-rule="evenodd"/>
<path d="M58.8 133.4h.4a.31 .31 0 0 1 .3 .3 .31 .31 0 0 1-.3 .3h-.3v.4h-.1v-.5h.5l.1-.2-.1-.2h-.4v.4h-.1z" fill-rule="evenodd"/>
<path d="M58.8 130.4h.4a.31 .31 0 0 1 .3 .3 .31 .31 0 0 1-.3 .3h-.3v.4h-.1v-.5h.5l.1-.2-.1-.2h-.4v.4h-.1z" fill-rule="evenodd"/>
<path d="M58.8 127.4h.4a.31 .31 0 0 1 .3 .3 .31 .31 0 0 1-.3 .3h-.3v.4h-.1v-.5h.5l.1-.2-.1-.2h-.4v.4h-.1z" fill-rule="evenodd"/>
<path d="M58.8 124.4h.5a.35 .35 0 0 1 .2 .5 .35 .35 0 0 1-.5 .1v.4h-.2v-.5h.4l.1-.2-.3-.1v.3h-.2z" fill-rule="evenodd"/>
<path d="M59.7 124.4h.2v1h-.2z" fill-rule="evenodd"/>
<path d="M59.6 136.4h.8v.1h-.3v.9h-.1v-.9h-.4z" fill-rule="evenodd"/>
<path d="M59.6 133.4h.8v.1h-.3v.9h-.1v-.9h-.4z" fill-rule="evenodd"/>
<path d="M59.6 130.4h.8v.1h-.3v.9h-.1v-.9h-.4z" fill-rule="evenodd"/>
<path d="M59.6 127.4h.8v.1h-.3v.9h-.1v-.9h-.4z" fill-rule="evenodd"/>
<path d="M60.1 124.8l.5-.1 .1 .7h-.6l-.1-.2 .4 .1 .1-.2-.5 .1 .5-.3-.1-.1-.3 .1z" fill-rule="evenodd"/>
<path d="M60.6 136.4h.1v.4h.5v-.4h.2v1h-.2v-.5h-.5v.5h-.1z" fill-rule="evenodd"/>
<path d="M60.6 133.4h.1v.4h.5v-.4h.2v1h-.2v-.5h-.5v.5h-.1z" fill-rule="evenodd"/>
<path d="M60.6 130.4h.1v.4h.5v-.4h.2v1h-.2v-.5h-.5v.5h-.1z" fill-rule="evenodd"/>
<path d="M60.6 127.4h.1v.4h.5v-.4h.2v1h-.2v-.5h-.5v.5h-.1z" fill-rule="evenodd"/>
<path d="M60.9 124.5l.2-.1v.3h.1l-.1 .4 .1 .3-.3-.1z" fill-rule="evenodd"/>
<path d="M61.4 124.8l.4-.1 .2 .4-.5 .1 .1 .1 .3-.1a.35 .35 0 0 1-.4 .2 .35 .35 0 0 1-.2-.4h.5l-.2-.2-.3 .2z" fill-rule="evenodd"/>
<path d="M62.2 124.8h.4v-.4h.2v1l-.2-.1-.3 .1-.2-.4h.2v.2a.17 .17 0 0 0 .2 0 .17 .17 0 0 0 0-.3 .17 .17 0 0 0-.2 .1h-.2z" fill-rule="evenodd"/>
<path d="M65.8 124.4h.2v.4h.4v-.4h.2v1h-.2v-.4h-.4v.4h-.2z" fill-rule="evenodd"/>
<path d="M65.8 139.4h.4a.28 .28 0 0 1 .4 .2 .28 .28 0 0 1-.3 .4l.4 .4-.6-.4h-.2v.4h-.1v-.5l.5-.1 .1-.1-.1-.2h-.4v.4h-.1z" fill-rule="evenodd"/>
<path d="M65.8 136.4h.4a.28 .28 0 0 1 .4 .2 .28 .28 0 0 1-.3 .4l.4 .4-.6-.4h-.2v.4h-.1v-.5l.5-.1 .1-.1-.1-.2h-.4v.4h-.1z" fill-rule="evenodd"/>
<path d="M65.8 133.4h.4a.28 .28 0 0 1 .4 .2 .28 .28 0 0 1-.3 .4l.4 .4-.6-.4h-.2v.4h-.1v-.5l.5-.1 .1-.1-.1-.2h-.4v.4h-.1z" fill-rule="evenodd"/>
<path d="M65.8 130.4h.4a.28 .28 0 0 1 .4 .2 .28 .28 0 0 1-.3 .4l.4 .4-.6-.4h-.2v.4h-.1v-.5l.5-.1 .1-.1-.1-.2h-.4v.4h-.1z" fill-rule="evenodd"/>
<path d="M65.8 127.4h.4a.28 .28 0 0 1 .4 .2 .28 .28 0 0 1-.3 .4l.4 .4-.6-.4h-.2v.4h-.1v-.5l.5-.1 .1-.1-.1-.2h-.4v.4h-.1z" fill-rule="evenodd"/>
<path d="M66.8 139.8a.36 .36 0 0 1 .6 0 .36 .36 0 0 1-.2 .6 .36 .36 0 0 1-.5-.3h.1a.22 .22 0 0 0 .4 .1 .22 .22 0 0 0 0-.3 .22 .22 0 0 0-.3 .1l-.2 .1z" fill-rule="evenodd"/>
<path d="M66.8 136.8a.36 .36 0 0 1 .6 0 .36 .36 0 0 1-.2 .6 .36 .36 0 0 1-.5-.3h.1a.22 .22 0 0 0 .4 .1 .22 .22 0 0 0 0-.3 .22 .22 0 0 0-.3 .1l-.2 .1z" fill-rule="evenodd"/>
<path d="M66.8 133.8a.36 .36 0 0 1 .6 0 .36 .36 0 0 1-.2 .6 .36 .36 0 0 1-.5-.3h.1a.22 .22 0 0 0 .4 .1 .22 .22 0 0 0 0-.3 .22 .22 0 0 0-.3 .1l-.2 .1z" fill-rule="evenodd"/>
<path d="M66.8 130.8a.36 .36 0 0 1 .6 0 .36 .36 0 0 1-.2 .6 .36 .36 0 0 1-.5-.3h.1a.22 .22 0 0 0 .4 .1 .22 .22 0 0 0 0-.3 .22 .22 0 0 0-.3 .1l-.2 .1z" fill-rule="evenodd"/>
<path d="M66.8 127.8a.36 .36 0 0 1 .6 0 .36 .36 0 0 1-.2 .6 .36 .36 0 0 1-.5-.3h.1a.22 .22 0 0 0 .4 .1 .22 .22 0 0 0 0-.3 .22 .22 0 0 0-.3 .1l-.2 .1z" fill-rule="evenodd"/>
<path d="M66.9 124.8a.38 .38 0 0 1 .5 .1 .38 .38 0 0 1-.2 .5 .38 .38 0 0 1-.5-.3h.2a.19 .19 0 0 0 .3 .1 .19 .19 0 0 0 0-.3 .19 .19 0 0 0-.3 .1l-.2 .1z" fill-rule="evenodd"/>
<path d="M67.6 124.4h.2v1h-.2z" fill-rule="evenodd"/>
<path d="M67.5 136.7h.2v.5l.1 .1 .2-.1v-.5h.1v.7l-.5-.1z" fill-rule="evenodd"/>
<path d="M67.5 133.7h.2v.5l.1 .1 .2-.1v-.5h.1v.7l-.5-.1z" fill-rule="evenodd"/>
<path d="M67.5 130.7h.2v.5l.1 .1 .2-.1v-.5h.1v.7l-.5-.1z" fill-rule="evenodd"/>
<path d="M67.5 127.7h.2v.5l.1 .1 .2-.1v-.5h.1v.7l-.5-.1z" fill-rule="evenodd"/>
<path d="M68.3 136.7l.6 .1v.6h-.1v-.5l-.2-.1-.1 .1-.1 .5h-.1z" fill-rule="evenodd"/>
<path d="M68.3 133.7l.6 .1v.6h-.1v-.5l-.2-.1-.1 .1-.1 .5h-.1z" fill-rule="evenodd"/>
<path d="M68.3 130.7l.6 .1v.6h-.1v-.5l-.2-.1-.1 .1-.1 .5h-.1z" fill-rule="evenodd"/>
<path d="M68.3 127.7l.6 .1v.6h-.1v-.5l-.2-.1-.1 .1-.1 .5h-.1z" fill-rule="evenodd"/>
<path d="M68.1 124.8l.4-.1 .1 .4-.4 .1 .1 .1 .3-.1a.35 .35 0 0 1-.4 .2 .35 .35 0 0 1-.2-.4h.5l-.2-.2-.3 .2z" fill-rule="evenodd"/>
<path d="M69.2 124.5l.4-.1 .3 .2v.1h-.2l-.3-.1 .1 .2a.38 .38 0 0 1 .4 .3 .38 .38 0 0 1-.3 .4 .38 .38 0 0 1-.4-.3l-.1-.1h.2a.19 .19 0 0 0 .2 .2 .19 .19 0 0 0 .2-.3l-.5-.2z" fill-rule="evenodd"/>
<path d="M69.2 136.8h.4v-.4h.1v1h-.5l-.1-.3h.1a.24 .24 0 0 0 .3 .1 .24 .24 0 0 0 .1-.3 .24 .24 0 0 0-.3-.1l-.2 .3z" fill-rule="evenodd"/>
<path d="M69.2 133.8h.4v-.4h.1v1h-.5l-.1-.3h.1a.24 .24 0 0 0 .3 .1 .24 .24 0 0 0 .1-.3 .24 .24 0 0 0-.3-.1l-.2 .3z" fill-rule="evenodd"/>
<path d="M69.2 130.8h.4v-.4h.1v1h-.5l-.1-.3h.1a.24 .24 0 0 0 .3 .1 .24 .24 0 0 0 .1-.3 .24 .24 0 0 0-.3-.1l-.2 .3z" fill-rule="evenodd"/>
<path d="M69.2 127.8h.4v-.4h.1v1h-.5l-.1-.3h.1a.24 .24 0 0 0 .3 .1 .24 .24 0 0 0 .1-.3 .24 .24 0 0 0-.3-.1l-.2 .3z" fill-rule="evenodd"/>
<path d="M70.1 124.4h.2v.4h.4l.1 .6h-.2l-.1-.6-.2 .1v.5h-.2z" fill-rule="evenodd"/>
<path d="M70.5 133.6h.1v.3h.3v.1h-.3v.3h-.1v-.3h-.2v-.1h.2z" fill-rule="evenodd"/>
<path d="M71 124.8l.5-.1 .1 .7h-.6l-.1-.2 .4 .1 .1-.2-.5 .1 .5-.3-.1-.1-.4 .1z" fill-rule="evenodd"/>
<path d="M71.6 133.5l.4-.1 .2 .2-.1 .1a.21 .21 0 0 0-.3-.3 .21 .21 0 0 0-.1 .4h.1a.36 .36 0 0 1 .4 .6 .35 .35 0 0 1-.7-.1l-.1-.2h.2a.23 .23 0 0 0 .2 .3 .23 .23 0 0 0 .2-.4l-.5-.2z" fill-rule="evenodd"/>
<path d="M71.7 124.7l.2 .1a.33 .33 0 0 1 .5 0 .33 .33 0 0 1 0 .5 .33 .33 0 0 1-.5 0v.4h-.2v-.7h.2l.1 .2a.18 .18 0 0 0 .2 0 .18 .18 0 0 0 0-.3 .18 .18 0 0 0-.3 .1h-.2z" fill-rule="evenodd"/>
<path d="M72.4 133.4h.1v1h-.1z" fill-rule="evenodd"/>
<path d="M72.6 124.8l.5-.1 .1 .4-.4 .1 .1 .1 .3-.1a.35 .35 0 0 1-.4 .2 .35 .35 0 0 1-.2-.4h.4l-.1-.2-.3 .2z" fill-rule="evenodd"/>
<path d="M72.8 133.8a.36 .36 0 0 1 .5 0 .36 .36 0 0 1-.2 .6 .36 .36 0 0 1-.4-.3h.1a.22 .22 0 0 0 .3 .1 .22 .22 0 0 0 0-.3 .22 .22 0 0 0-.3 .1l-.1 .1z" fill-rule="evenodd"/>
<path d="M73.5 133.5l.1-.1v.3h.2l-.2 .5 .2 .2-.3-.1z" fill-rule="evenodd"/>
<path d="M76.7 136.4h.7v.1h-.6v.3h.5v.2h-.5v.4h-.1z" fill-rule="evenodd"/>
<path d="M76.7 133.4h.7v.1h-.6v.3h.5v.2h-.5v.4h-.1z" fill-rule="evenodd"/>
<path d="M76.7 130.4h.7v.1h-.6v.3h.5v.2h-.5v.4h-.1z" fill-rule="evenodd"/>
<path d="M76.7 127.4h.7v.1h-.6v.3h.5v.2h-.5v.4h-.1z" fill-rule="evenodd"/>
<path d="M76.7 124.4h.4a.5 .5 0 0 1 .4 .5 .5 .5 0 0 1-.4 .5h-.4v-.2h.3a.34 .34 0 0 0 .3-.4 .34 .34 0 0 0-.4-.2v.6h-.2z" fill-rule="evenodd"/>
<path d="M77.5 137.3l.1 .1z" fill-rule="evenodd"/>
<path d="M77.5 134.3l.1 .1z" fill-rule="evenodd"/>
<path d="M77.5 131.3l.1 .1z" fill-rule="evenodd"/>
<path d="M77.5 128.3l.1 .1z" fill-rule="evenodd"/>
<path d="M77.7 124.7h.5l-.3 .2v.5h-.2z" fill-rule="evenodd"/>
<path d="M78.2 124.4h.2v.2h-.2z" fill-rule="evenodd"/>
<path d="M78.2 124.7h.2v.7h-.2z" fill-rule="evenodd"/>
<path d="M77.9 136.5l.5-.1 .2 .2-.1 .1a.33 .33 0 0 0-.5 0 .33 .33 0 0 0 0 .5 .33 .33 0 0 0 .5-.1h.1a.49 .49 0 0 1-.7 .2 .49 .49 0 0 1 0-.8z" fill-rule="evenodd"/>
<path d="M77.9 133.5l.5-.1 .2 .2-.1 .1a.33 .33 0 0 0-.5 0 .33 .33 0 0 0 0 .5 .33 .33 0 0 0 .5-.1h.1a.49 .49 0 0 1-.7 .2 .49 .49 0 0 1 0-.8z" fill-rule="evenodd"/>
<path d="M77.9 130.5l.5-.1 .2 .2-.1 .1a.33 .33 0 0 0-.5 0 .33 .33 0 0 0 0 .5 .33 .33 0 0 0 .5-.1h.1a.49 .49 0 0 1-.7 .2 .49 .49 0 0 1 0-.8z" fill-rule="evenodd"/>
<path d="M77.9 127.5l.5-.1 .2 .2-.1 .1a.33 .33 0 0 0-.5 0 .33 .33 0 0 0 0 .5 .33 .33 0 0 0 .5-.1h.1a.49 .49 0 0 1-.7 .2 .49 .49 0 0 1 0-.8z" fill-rule="evenodd"/>
<path d="M78.6 124.4h.2v1h-.2z" fill-rule="evenodd"/>
<path d="M79 124.4h.2v1h-.2z" fill-rule="evenodd"/>
<path d="M78.8 136.7h.1v.5l.1 .1 .2-.1v-.5h.2v.7l-.6-.1z" fill-rule="evenodd"/>
<path d="M78.8 133.7h.1v.5l.1 .1 .2-.1v-.5h.2v.7l-.6-.1z" fill-rule="evenodd"/>
<path d="M78.8 130.7h.1v.5l.1 .1 .2-.1v-.5h.2v.7l-.6-.1z" fill-rule="evenodd"/>
<path d="M78.8 127.7h.1v.5l.1 .1 .2-.1v-.5h.2v.7l-.6-.1z" fill-rule="evenodd"/>
<path d="M79.8 124.4h.2v.8h.5v.2h-.7z" fill-rule="evenodd"/>
<path d="M79.9 140h.4v.1h-.4z" fill-rule="evenodd"/>
<path d="M79.9 137h.4v.1h-.4z" fill-rule="evenodd"/>
<path d="M79.9 134h.4v.1h-.4z" fill-rule="evenodd"/>
<path d="M79.9 131h.4v.1h-.4z" fill-rule="evenodd"/>
<path d="M79.9 128h.4v.1h-.4z" fill-rule="evenodd"/>
<path d="M80.7 124.8l.5-.1 .1 .7h-.6l-.1-.2 .3 .1 .2-.2-.5 .1 .5-.3-.1-.1-.4 .1z" fill-rule="evenodd"/>
<path d="M80.8 139.4l.7 .1v.8l-.7 .1v-.1h.5l.1-.2-.1-.1-.4-.1v.4h-.1v-.5h.5l.1-.1-.1-.2h-.4v.3h-.1z" fill-rule="evenodd"/>
<path d="M80.8 136.4l.7 .1v.8l-.7 .1v-.1h.5l.1-.2-.1-.1-.4-.1v.4h-.1v-.5h.5l.1-.1-.1-.2h-.4v.3h-.1z" fill-rule="evenodd"/>
<path d="M80.8 133.4l.7 .1v.8l-.7 .1v-.1h.5l.1-.2-.1-.1-.4-.1v.4h-.1v-.5h.5l.1-.1-.1-.2h-.4v.3h-.1z" fill-rule="evenodd"/>
<path d="M80.8 130.4l.7 .1v.8l-.7 .1v-.1h.5l.1-.2-.1-.1-.4-.1v.4h-.1v-.5h.5l.1-.1-.1-.2h-.4v.3h-.1z" fill-rule="evenodd"/>
<path d="M80.8 127.4l.7 .1v.8l-.7 .1v-.1h.5l.1-.2-.1-.1-.4-.1v.4h-.1v-.5h.5l.1-.1-.1-.2h-.4v.3h-.1z" fill-rule="evenodd"/>
<path d="M81.3 124.7h.2l.2 .5 .2-.5h.2l-.5 1h-.2v-.1l.2-.2z" fill-rule="evenodd"/>
<path d="M81.8 137.3l.1 .1z" fill-rule="evenodd"/>
<path d="M81.8 134.3l.1 .1z" fill-rule="evenodd"/>
<path d="M81.8 131.3l.1 .1z" fill-rule="evenodd"/>
<path d="M81.8 128.3l.1 .1z" fill-rule="evenodd"/>
<path d="M82.2 124.8l.5-.1 .1 .4-.4 .1 .1 .1 .3-.1a.35 .35 0 0 1-.4 .2 .35 .35 0 0 1-.2-.4h.4l-.1-.2-.3 .2z" fill-rule="evenodd"/>
<path d="M82.2 136.5l.5-.1 .2 .2-.1 .1a.33 .33 0 0 0-.5 0 .33 .33 0 0 0 .1 .5 .33 .33 0 0 0 .5-.1h.1a.49 .49 0 0 1-.8 .2 .49 .49 0 0 1 0-.8z" fill-rule="evenodd"/>
<path d="M82.2 133.5l.5-.1 .2 .2-.1 .1a.33 .33 0 0 0-.5 0 .33 .33 0 0 0 .1 .5 .33 .33 0 0 0 .5-.1h.1a.49 .49 0 0 1-.8 .2 .49 .49 0 0 1 0-.8z" fill-rule="evenodd"/>
<path d="M82.2 130.5l.5-.1 .2 .2-.1 .1a.33 .33 0 0 0-.5 0 .33 .33 0 0 0 .1 .5 .33 .33 0 0 0 .5-.1h.1a.49 .49 0 0 1-.8 .2 .49 .49 0 0 1 0-.8z" fill-rule="evenodd"/>
<path d="M82.2 127.5l.5-.1 .2 .2-.1 .1a.33 .33 0 0 0-.5 0 .33 .33 0 0 0 .1 .5 .33 .33 0 0 0 .5-.1h.1a.49 .49 0 0 1-.8 .2 .49 .49 0 0 1 0-.8z" fill-rule="evenodd"/>
<path d="M83 124.7h.4l-.2 .2v.5h-.2z" fill-rule="evenodd"/>
<path d="M83.1 136.7h.2v.5l.1 .1 .2-.1v-.5h.1v.7l-.5-.1z" fill-rule="evenodd"/>
<path d="M83.1 133.7h.2v.5l.1 .1 .2-.1v-.5h.1v.7l-.5-.1z" fill-rule="evenodd"/>
<path d="M83.1 130.7h.2v.5l.1 .1 .2-.1v-.5h.1v.7l-.5-.1z" fill-rule="evenodd"/>
<path d="M83.1 127.7h.2v.5l.1 .1 .2-.1v-.5h.1v.7l-.5-.1z" fill-rule="evenodd"/>
<path d="M83.9 124.4h.5a.35 .35 0 0 1 .3 .5 .35 .35 0 0 1-.6 .1v.4h-.2v-.5h.5l.1-.2-.4-.1v.3h-.2z" fill-rule="evenodd"/>
<path d="M84.9 124.8l.5-.1 .1 .7h-.6l-.1-.2 .3 .1 .2-.2-.5 .1 .5-.3-.1-.1-.4 .1z" fill-rule="evenodd"/>
<path d="M85.6 124.4h.2v.2h-.2z" fill-rule="evenodd"/>
<path d="M85.6 124.7h.2v.7h-.2z" fill-rule="evenodd"/>
<path d="M86 124.7h.5l-.3 .2v.5h-.2z" fill-rule="evenodd"/>
<path d="M89.4 124.4h.2v.4h.4v-.4h.2v1h-.2v-.4h-.4v.4h-.2z" fill-rule="evenodd"/>
<path d="M89.3 130.4h.1l.3 .9 .4-.9h.1l-.4 1h-.1z" fill-rule="evenodd"/>
<path d="M89.3 127.4h.1l.3 .9 .4-.9h.1l-.4 1h-.1z" fill-rule="evenodd"/>
<path d="M89.4 139.4h.4a.31 .31 0 0 1 .3 .3 .31 .31 0 0 1-.3 .3h-.3v.4h-.1v-.5h.5l.1-.2-.1-.2h-.4v.4h-.1z" fill-rule="evenodd"/>
<path d="M89.4 136.4h.4a.31 .31 0 0 1 .3 .3 .31 .31 0 0 1-.3 .3h-.3v.4h-.1v-.5h.5l.1-.2-.1-.2h-.4v.4h-.1z" fill-rule="evenodd"/>
<path d="M89.4 133.4h.4a.31 .31 0 0 1 .3 .3 .31 .31 0 0 1-.3 .3h-.3v.4h-.1v-.5h.5l.1-.2-.1-.2h-.4v.4h-.1z" fill-rule="evenodd"/>
<path d="M90.3 130.4l.1 .1z" fill-rule="evenodd"/>
<path d="M90.3 130.7h.1v.7h-.1z" fill-rule="evenodd"/>
<path d="M90.3 127.4l.1 .1z" fill-rule="evenodd"/>
<path d="M90.3 127.7h.1v.7h-.1z" fill-rule="evenodd"/>
<path d="M90.3 139.8l.5-.1 .1 .7h-.5l-.2-.2a.27 .27 0 0 0 .4 .1 .27 .27 0 0 0 .2-.2l-.6 .1 .2-.2h.4l-.2-.2-.3 .1z" fill-rule="evenodd"/>
<path d="M90.3 136.8l.5-.1 .1 .7h-.5l-.2-.2a.27 .27 0 0 0 .4 .1 .27 .27 0 0 0 .2-.2l-.6 .1 .2-.2h.4l-.2-.2-.3 .1z" fill-rule="evenodd"/>
<path d="M90.3 133.8l.5-.1 .1 .7h-.5l-.2-.2a.27 .27 0 0 0 .4 .1 .27 .27 0 0 0 .2-.2l-.6 .1 .2-.2h.4l-.2-.2-.3 .1z" fill-rule="evenodd"/>
<path d="M90.5 124.8a.38 .38 0 0 1 .5 .1 .38 .38 0 0 1-.2 .5 .38 .38 0 0 1-.5-.3h.2a.19 .19 0 0 0 .3 .1 .19 .19 0 0 0 0-.3 .19 .19 0 0 0-.3 .1l-.2 .1z" fill-rule="evenodd"/>
<path d="M90.6 130.7h.5l.1 .7h-.5l-.2-.2a.27 .27 0 0 0 .4 .1 .27 .27 0 0 0 .1-.2l-.5 .1 .2-.2h.3l-.1-.2-.3 .1z" fill-rule="evenodd"/>
<path d="M90.6 127.7h.5l.1 .7h-.5l-.2-.2a.27 .27 0 0 0 .4 .1 .27 .27 0 0 0 .1-.2l-.5 .1 .2-.2h.3l-.1-.2-.3 .1z" fill-rule="evenodd"/>
<path d="M91.2 124.4h.2v1h-.2z" fill-rule="evenodd"/>
<path d="M91.1 136.8h.4v-.4h.2v1h-.5l-.2-.3h.2a.24 .24 0 0 0 .3 .1 .24 .24 0 0 0 .1-.3 .24 .24 0 0 0-.4-.1l-.2 .3z" fill-rule="evenodd"/>
<path d="M91.1 133.8h.4v-.4h.2v1h-.5l-.2-.3h.2a.24 .24 0 0 0 .3 .1 .24 .24 0 0 0 .1-.3 .24 .24 0 0 0-.4-.1l-.2 .3z" fill-rule="evenodd"/>
<path d="M91.7 124.8l.4-.1 .1 .4-.4 .1 .1 .1 .3-.1a.35 .35 0 0 1-.4 .2 .35 .35 0 0 1-.2-.4h.5l-.2-.2-.3 .2z" fill-rule="evenodd"/>
<path d="M92.7 124.4h.8v.2h-.3v.8h-.2v-.8h-.3z" fill-rule="evenodd"/>
<path d="M93.5 124.7h.2l.2 .5 .1-.5h.2l-.4 1h-.2l-.1-.1 .3-.2z" fill-rule="evenodd"/>
<path d="M94.3 124.7l.2 .1a.33 .33 0 0 1 .4 0 .33 .33 0 0 1 0 .5 .33 .33 0 0 1-.4 0v.4h-.2v-.7h.2v.2a.18 .18 0 0 0 .3 0 .18 .18 0 0 0 0-.3 .18 .18 0 0 0-.3 .1h-.2z" fill-rule="evenodd"/>
<path d="M95.2 124.8l.5-.1 .1 .4-.5 .1 .2 .1 .3-.1a.35 .35 0 0 1-.5 .2 .35 .35 0 0 1-.2-.4h.5l-.1-.2-.4 .2z" fill-rule="evenodd"/>
<path d="M34.3 142.4h.8v.1h-.4v.9h-.1v-.9h-.3z" fill-rule="evenodd"/>
<path d="M34.7 139.4l.1 .7h.2l-.2 .3h-.1v-.2h-.4v-.1h.4v-.5l-.4 .5z" fill-rule="evenodd"/>
<path d="M35.2 142.8a.36 .36 0 0 1 .5 0 .36 .36 0 0 1-.2 .6 .36 .36 0 0 1-.4-.3h.1a.22 .22 0 0 0 .3 .1 .22 .22 0 0 0 .1-.3 .22 .22 0 0 0-.4 .1l-.1 .1z" fill-rule="evenodd"/>
<path d="M35.8 142.5l.2-.1v.3h.1l-.1 .5 .1 .2-.2-.1z" fill-rule="evenodd"/>
<path d="M36.3 142.7h.5v.7h-.5l-.1-.2a.27 .27 0 0 0 .3 .1 .27 .27 0 0 0 .2-.2l-.5 .1 .1-.2h.4l-.1-.2-.4 .1z" fill-rule="evenodd"/>
<path d="M37 142.4h.1v1h-.1z" fill-rule="evenodd"/>
<path d="M37.8 142.7l.3-.3v1h-.1v-.8l-.2 .2z" fill-rule="evenodd"/>
<path d="M38.6 142.4h.4v.1h-.4v.3a.33 .33 0 0 1 .5 .2 .33 .33 0 0 1-.3 .4 .33 .33 0 0 1-.4-.3h.2a.22 .22 0 0 0 .3 .1 .22 .22 0 0 0 0-.3 .22 .22 0 0 0-.3 .1l-.1-.1z" fill-rule="evenodd"/>
<path d="M39.4 142.5l.3-.1 .1 .3-.2-.2a.19 .19 0 0 0-.3 .1 .19 .19 0 0 0 .1 .2 .19 .19 0 0 0 .2 0 .33 .33 0 0 1 .3 .3 .33 .33 0 0 1-.4 .3 .33 .33 0 0 1-.3-.3h.1a.2 .2 0 0 0 .3 .2 .21 .21 0 0 0 .1-.4 .2 .2 0 0 0-.3 .1l-.2 .1z" fill-rule="evenodd"/>
<path d="M42.9 139.5a.27 .27 0 0 1 .4 0 .27 .27 0 0 1 0 .4 .31 .31 0 0 1 0 .5 .31 .31 0 0 1-.5-.3h.1a.2 .2 0 0 0 .2 .2 .2 .2 0 0 0 .2-.2 .2 .2 0 0 0-.3-.2v-.1a.17 .17 0 0 0 .3-.1 .17 .17 0 0 0-.2-.2 .17 .17 0 0 0-.2 .2h-.1z" fill-rule="evenodd"/>
<path d="M43.6 140.3l.2 .1z" fill-rule="evenodd"/>
<path d="M44.1 139.5a.35 .35 0 0 1 .5 .1 .35 .35 0 0 1-.3 .5l-.2 .2h.5v.1h-.7l.4-.4a.21 .21 0 0 0 .2-.3 .21 .21 0 0 0-.2-.2 .21 .21 0 0 0-.2 .2h-.1z" fill-rule="evenodd"/>
<path d="M45.5 139.7h.9l.1 .7h-.1v-.5l-.1-.1-.2 .1v.5h-.1l-.2-.6-.1 .1v.5h-.2z" fill-rule="evenodd"/>
<path d="M46.7 139.7h.9l.1 .7h-.1v-.5l-.2-.1-.1 .1v.5h-.2v-.5l-.1-.1-.1 .1-.1 .5h-.1z" fill-rule="evenodd"/>
<path d="M48.5 139.4l-.1 .8 .2 .5-.3-.6z" fill-rule="evenodd"/>
<path d="M48.8 139.7l.4-.3v1h-.2v-.8l-.2 .2z" fill-rule="evenodd"/>
<path d="M49.6 139.5a.35 .35 0 0 1 .5 .1 .35 .35 0 0 1-.3 .5l-.2 .2h.5v.1h-.6l.3-.4a.21 .21 0 0 0 .2-.3 .21 .21 0 0 0-.2-.2 .21 .21 0 0 0-.2 .2h-.1z" fill-rule="evenodd"/>
<path d="M50.4 139.4h.5v.1h-.4l-.1 .3a.33 .33 0 0 1 .5 .2 .33 .33 0 0 1-.2 .4 .33 .33 0 0 1-.4-.3h.1a.22 .22 0 0 0 .3 .1 .22 .22 0 0 0 0-.3 .22 .22 0 0 0-.3 .1l-.1-.1z" fill-rule="evenodd"/>
<path d="M51.1 140.3l.1 .1z" fill-rule="evenodd"/>
<path d="M53 139.7h.9l.1 .7h-.1v-.5l-.2-.1-.1 .1v.5h-.2v-.5l-.1-.1-.2 .1v.5h-.1z" fill-rule="evenodd"/>
<path d="M54.8 139.8l.5-.1v.2l-.4-.1 .2 .2a.27 .27 0 0 1 .2 .3 .27 .27 0 0 1-.3 .2 .27 .27 0 0 1-.3-.3h.2a.16 .16 0 0 0 .1 .2 .18 .18 0 0 0 .2-.3l-.4-.1z" fill-rule="evenodd"/>
<path d="M55.5 139.4l.3 .5-.2 .8 .1-.8z" fill-rule="evenodd"/>
<path d="M59.6 139.4h.8v.1h-.3v.9h-.1v-.9h-.4z" fill-rule="evenodd"/>
<path d="M60.6 139.4h.1v.4h.5v-.4h.2v1h-.2v-.5h-.5v.5h-.1z" fill-rule="evenodd"/>
<path d="M67.5 139.7h.2v.5l.1 .1 .2-.1v-.5h.1v.7l-.5-.1z" fill-rule="evenodd"/>
<path d="M68.3 139.7l.6 .1v.6h-.1v-.5l-.2-.1-.1 .1-.1 .5h-.1z" fill-rule="evenodd"/>
<path d="M69.2 139.8h.4v-.4h.1v1h-.5l-.1-.3h.1a.24 .24 0 0 0 .3 .1 .24 .24 0 0 0 .1-.3 .24 .24 0 0 0-.3-.1l-.2 .3z" fill-rule="evenodd"/>
<path d="M76.7 139.4h.7v.1h-.6v.3h.5v.2h-.5v.4h-.1z" fill-rule="evenodd"/>
<path d="M77.5 140.3l.1 .1z" fill-rule="evenodd"/>
<path d="M77.9 139.5l.5-.1 .2 .2-.1 .1a.33 .33 0 0 0-.5 0 .33 .33 0 0 0 0 .5 .33 .33 0 0 0 .5-.1h.1a.49 .49 0 0 1-.7 .2 .49 .49 0 0 1 0-.8z" fill-rule="evenodd"/>
<path d="M78.8 139.7h.1v.5l.1 .1 .2-.1v-.5h.2v.7l-.6-.1z" fill-rule="evenodd"/>
<path d="M81.8 140.3l.1 .1z" fill-rule="evenodd"/>
<path d="M82.2 139.5l.5-.1 .2 .2-.1 .1a.33 .33 0 0 0-.5 0 .33 .33 0 0 0 .1 .5 .33 .33 0 0 0 .5-.1h.1a.49 .49 0 0 1-.8 .2 .49 .49 0 0 1 0-.8z" fill-rule="evenodd"/>
<path d="M83.1 139.7h.2v.5l.1 .1 .2-.1v-.5h.1v.7l-.5-.1z" fill-rule="evenodd"/>
<path d="M91.1 139.8h.4v-.4h.2v1h-.5l-.2-.3h.2a.24 .24 0 0 0 .3 .1 .24 .24 0 0 0 .1-.3 .24 .24 0 0 0-.4-.1l-.2 .3z" fill-rule="evenodd"/>
<circle cx="30" cy="117.7" r=".32"/>
</g>
<path d="M171.7 125.5l1.6 1.6-1.6 1.6-1.6-1.6zM243.7 125.5l1.6 1.6-1.6 1.6-1.6-1.6zM171.7 165.5l1.6 1.6-1.6 1.6-1.6-1.6zM243.7 165.5l1.6 1.6-1.6 1.6-1.6-1.6z" fill="none" stroke="#000" stroke-width=".32"/>
<path d="M384.7 279.9a.55 .55 0 0 1 .9-.2 .55 .55 0 0 1-.1 .9 .81 .81 0 0 1 .2 1.2 .81 .81 0 0 1-1.3 0l.3-.2a.54 .54 0 0 0 .8 .2 .72 .72 0 0 0-.6-1 .41 .41 0 0 0 .5-.3 .41 .41 0 0 0-.3-.5 .41 .41 0 0 0-.5 .3z" fill-rule="evenodd" fill="#00007f"/>
<g fill="#00f">
<path d="M384.3 275.7l.7-.1 .2 .4-.1 .1a.32 .32 0 0 0-.4-.4 .32 .32 0 0 0-.3 .5h.3a.5 .5 0 0 1 .6 .6 .5 .5 0 0 1-.8 .3l-.4-.3v-.2h.2a.39 .39 0 0 0 .4 .4 .39 .39 0 0 0 .4-.4l-.9-.4v-.2z" fill-rule="evenodd"/>
<path d="M385.5 275.6h.2v.6l.3-.2 .4 .2v.9h-.2v-.7a.27 .27 0 0 0-.3-.2 .27 .27 0 0 0-.2 .3v.6h-.2z" fill-rule="evenodd"/>
<path d="M386.8 276.2a.51 .51 0 0 1 .6-.1 .51 .51 0 0 1 .2 .5h-.8l.3 .4 .5-.2a.52 .52 0 0 1-.6 .3 .52 .52 0 0 1-.3-.6h.8l-.3-.3-.4 .3h-.1z" fill-rule="evenodd"/>
<path d="M388 276.2a.51 .51 0 0 1 .6-.1 .51 .51 0 0 1 .2 .5h-.8l.2 .4 .6-.2a.52 .52 0 0 1-.6 .3 .52 .52 0 0 1-.4-.6h.8l-.3-.3-.3 .3h-.2z" fill-rule="evenodd"/>
<path d="M389.1 275.8l.2-.1v.3h.1v.2h-.1v.6l.2 .3a.27 .27 0 0 1-.3 0 .27 .27 0 0 1-.1-.3v-.6h-.2z" fill-rule="evenodd"/>
<path d="M389.7 276h.2v.2h-.2z" fill-rule="evenodd"/>
<path d="M389.7 276.9h.2v.2h-.2z" fill-rule="evenodd"/>
<path d="M392.7 281.1a.54 .54 0 0 1 .9 .1 .54 .54 0 0 1-.3 .8 .54 .54 0 0 1-.7-.4h.2a.37 .37 0 0 0 .5 .4 .37 .37 0 0 0 0-.7l-.3-.1-.2 .4h-.2z" fill-rule="evenodd"/>
<path d="M393.9 280.7l.4-.1v.2l-.3 .1 .2 .3h-.2v.9h-.2v-.9h-.1z" fill-rule="evenodd"/>
</g>
<g fill="#00007f">
<path d="M396.2 280.1l.9-.4v2.1l.4 .2h-1.2l.3-.1v-1.5v-.3z" fill-rule="evenodd"/>
<path d="M398.1 279.9a.73 .73 0 0 1 .9-.1 .73 .73 0 0 1 .3 .8 1.04 1.04 0 0 1-.8 1.5 .95 .95 0 0 1-.6-1h.5v.7a.2 .2 0 0 0 .2 .2 .2 .2 0 0 0 .2-.3v-1.7a.2 .2 0 0 0-.2-.2 .2 .2 0 0 0-.2 .2v1.1h-.5v-.7z" fill-rule="evenodd"/>
</g>
<g fill="#00f">
<path d="M368.3 275.7l.7-.1 .2 .4-.1 .1a.32 .32 0 0 0-.4-.4 .32 .32 0 0 0-.3 .5h.3a.5 .5 0 0 1 .6 .6 .5 .5 0 0 1-.8 .3l-.4-.3v-.2h.2a.39 .39 0 0 0 .4 .4 .39 .39 0 0 0 .4-.4l-.9-.4v-.2z" fill-rule="evenodd"/>
<path d="M369.5 275.6h.2v.2h-.2z" fill-rule="evenodd"/>
<path d="M369.5 276h.2v1.1h-.2z" fill-rule="evenodd"/>
<path d="M369.9 276h.9l-.7 1h.8v.1h-1l.7-.9h-.7z" fill-rule="evenodd"/>
<path d="M371.1 276.2a.51 .51 0 0 1 .6-.1 .51 .51 0 0 1 .3 .5h-.8l.2 .4 .6-.2a.52 .52 0 0 1-.7 .3 .52 .52 0 0 1-.3-.6h.8l-.3-.3-.3 .3h-.2z" fill-rule="evenodd"/>
<path d="M372.3 276h.2v.2h-.2z" fill-rule="evenodd"/>
<path d="M372.3 276.9h.2v.2h-.2z" fill-rule="evenodd"/>
</g>
<g fill="#00007f">
<path d="M370.3 279.7l.9 2.1 .3 .2h-1.1l.2-.1-.1-.5h-.9l-.1 .5 .3 .1h-.8l.6-.8h.8l-.3-.7-.4 .7h-.1z" fill-rule="evenodd"/>
<path d="M371.9 279.9a.55 .55 0 0 1 .8-.2 .55 .55 0 0 1 0 .9 .81 .81 0 0 1 .1 1.2 .81 .81 0 0 1-1.2 0l.2-.2a.54 .54 0 0 0 .8 .2 .72 .72 0 0 0-.6-1 .41 .41 0 0 0 .5-.3 .41 .41 0 0 0-.3-.5 .41 .41 0 0 0-.5 .3z" fill-rule="evenodd"/>
</g>
<path d="M366.5 274.5h41.5M382.5 274.5v10.5M408 264h-41.5v21" fill="none" stroke="#000" stroke-width=".2"/>
<g fill="#00f">
<path d="M384.2 265.1h.6a.42 .42 0 0 1 .6 .4 .42 .42 0 0 1-.5 .4l.6 .7h-.3l-.4-.6h-.2h-.2v.6h-.2v-.8l.9-.1a.25 .25 0 0 0 0-.3 .25 .25 0 0 0-.3-.1h-.4v.5h-.2z" fill-rule="evenodd"/>
<path d="M385.7 265.7l.1-.1a.51 .51 0 0 1 .6 0 .51 .51 0 0 1 .2 .5h-.8l.2 .4 .6-.2a.52 .52 0 0 1-.7 .3 .52 .52 0 0 1-.3-.6h.8l-.3-.3-.3 .3h-.2z" fill-rule="evenodd"/>
<path d="M386.7 265.5h.2l.3 .9 .3-.9h.2l-.4 1.1h-.2z" fill-rule="evenodd"/>
<path d="M387.9 265.1h.2v.2h-.2z" fill-rule="evenodd"/>
<path d="M387.9 265.5h.2v1.1h-.2z" fill-rule="evenodd"/>
<path d="M388.4 265.6l.5-.1 .2 .3h-.2a.21 .21 0 0 0-.2-.2 .21 .21 0 0 0-.1 .3 .43 .43 0 0 1 .4 .1 .43 .43 0 0 1 .1 .4l-.2 .2h-.4l-.2-.3h.1a.24 .24 0 0 0 .3 .3 .24 .24 0 0 0 .2-.4 .43 .43 0 0 1-.6-.5z" fill-rule="evenodd"/>
<path d="M389.4 265.1h.2v.2h-.2z" fill-rule="evenodd"/>
<path d="M389.4 265.5h.2v1.1h-.2z" fill-rule="evenodd"/>
<path d="M390 265.6a.54 .54 0 0 1 .8 .1 .54 .54 0 0 1-.3 .8 .54 .54 0 0 1-.7-.4h.2a.37 .37 0 0 0 .5 .4 .37 .37 0 0 0 .1-.7l-.4-.1-.2 .4h-.2z" fill-rule="evenodd"/>
<path d="M391 265.5h.2v.2l.3-.2a.35 .35 0 0 1 .4 .5v.6h-.2v-.6a.27 .27 0 0 0-.3-.3 .27 .27 0 0 0-.2 .3v.6h-.2z" fill-rule="evenodd"/>
<path d="M392.2 265.5h.2v.2h-.2z" fill-rule="evenodd"/>
<path d="M392.2 266.4h.2v.2h-.2z" fill-rule="evenodd"/>
</g>
<g fill="#00007f">
<path d="M384 270.4h.5l.1-.5v.5l.5 .1h-.5l-.1 .5v-.5z" fill-rule="evenodd"/>
<path d="M386.1 269.8l.3-.1a1.42 1.42 0 0 0 0 1.9l-.5-.6a1.13 1.13 0 0 1 .2-1.2z" fill-rule="evenodd"/>
<path d="M386.4 269.7h.6l-.2 .2v.7a.41 .41 0 0 0 .4 .5 .41 .41 0 0 0 .4-.6v-.7l-.2-.1h.5l-.2 .2v.6a.55 .55 0 0 1-.6 .7 .55 .55 0 0 1-.5-.7v-.7z" fill-rule="evenodd"/>
<path d="M387.9 270.3l.4-.1v.2a.29 .29 0 0 1 .3-.2 .29 .29 0 0 1 .2 .3v.5l.2 .1h-.5l.2-.2-.1-.5-.1-.1-.2 .1v.6l.1 .1h-.4l.1-.1v-.6z" fill-rule="evenodd"/>
<path d="M389 270.3l.3-.1v.2l.2-.2h.2l-.4 .3v.5l.2 .1h-.5l.1-.1v-.6z" fill-rule="evenodd"/>
<path d="M389.9 270.3l.4-.1 .2 .2v.1h-.6l.2 .4 .3 .1 .1-.2a.41 .41 0 0 1-.6 .3 .41 .41 0 0 1-.1-.6h.5l-.2-.3-.3 .3z" fill-rule="evenodd"/>
<path d="M390.7 269.8l.3-.1v1.3l.1 .1h-.4l.1-.1v-.9v-.3z" fill-rule="evenodd"/>
<path d="M391.4 270.3l.4-.1 .2 .2 .1 .1h-.7l.2 .4 .3 .1 .1-.2a.41 .41 0 0 1-.5 .3 .41 .41 0 0 1-.2-.6h.5l-.2-.3-.3 .3z" fill-rule="evenodd"/>
<path d="M392.3 270.2l.5 .1 .1 .7 .1-.1-.1 .2-.2-.1-.2 .1h-.2l-.1-.2 .3 .1 .2-.1v-.3l-.5 .3 .5-.4-.2-.3-.2 .3z" fill-rule="evenodd"/>
<path d="M393.2 270.2h.5v.3l-.2-.3-.2 .1 .1 .2a.34 .34 0 0 1 .4 .5 .34 .34 0 0 1-.6 .1v-.3l.2 .3 .2-.2-.4-.4z" fill-rule="evenodd"/>
<path d="M394.1 270.3l.4-.1 .2 .2v.1h-.6l.1 .4 .3 .1 .2-.2a.41 .41 0 0 1-.6 .3 .41 .41 0 0 1-.1-.6h.5l-.2-.3-.3 .3z" fill-rule="evenodd"/>
<path d="M395.4 269.8l.3-.1v1.3h.2l-.6 .2-.4-.2v-.4h.2l.1 .4 .3-.1-.1-.7-.3 .1v.3h-.2v-.1a.41 .41 0 0 1 .6-.3v-.4z" fill-rule="evenodd"/>
<path d="M395.9 269.7a1.08 1.08 0 0 1 0 1.9 1.42 1.42 0 0 0 0-1.9z" fill-rule="evenodd"/>
</g>
<path d="M382.5 264v10.5" fill="none" stroke="#000" stroke-width=".2"/>
<g fill="#00f">
<path d="M368.2 265.1h.5a.75 .75 0 0 1 .7 .8 .75 .75 0 0 1-.7 .7h-.5v-.2h.5a.58 .58 0 0 0 .5-.5 .58 .58 0 0 0-.5-.6h-.3v1.1h-.2z" fill-rule="evenodd"/>
<path d="M369.7 265.6l.2-.1a.47 .47 0 0 1 .5 .1 .47 .47 0 0 1 .1 .6l.1 .4-.2-.1-.5 .1-.3-.1v-.2l.6 .2 .1-.4-.7 .2a.57 .57 0 0 1 .7-.4l-.1-.2-.6 .1z" fill-rule="evenodd"/>
<path d="M370.9 265.3l.1-.1v.3h.2v.2h-.2v.6l.2 .3a.27 .27 0 0 1-.3 0 .27 .27 0 0 1 0-.3v-.6h-.2z" fill-rule="evenodd"/>
<path d="M371.5 265.7l.1-.1a.51 .51 0 0 1 .5 0 .51 .51 0 0 1 .2 .5h-.8l.3 .4 .5-.2a.52 .52 0 0 1-.6 .3 .52 .52 0 0 1-.4-.6h.9l-.3-.3-.4 .3h-.2z" fill-rule="evenodd"/>
<path d="M372.6 265.5h.2v.2h-.2z" fill-rule="evenodd"/>
<path d="M372.6 266.4h.2v.2h-.2z" fill-rule="evenodd"/>
</g>
<path d="M408 253.5h-41.5v10.5" fill="none" stroke="#000" stroke-width=".2"/>
<g fill="#00f">
<path d="M368.2 254.6h.5a.46 .46 0 0 1 .6 .5 .46 .46 0 0 1-.6 .4h-.3v.6h-.2v-.8h.7l.2-.2-.2-.3h-.5v.5h-.2z" fill-rule="evenodd"/>
<path d="M369.5 255h.2v.2l.4-.2v.2a.24 .24 0 0 0-.3 .1 .24 .24 0 0 0-.1 .3v.5h-.2z" fill-rule="evenodd"/>
<path d="M370.3 255.1a.55 .55 0 0 1 .9 .1 .55 .55 0 0 1-.3 .8 .55 .55 0 0 1-.7-.4h.2a.37 .37 0 0 0 .5 .4 .37 .37 0 0 0 0-.7l-.3-.1-.2 .4h-.2z" fill-rule="evenodd"/>
<path d="M371.4 254.6h.2v.2h-.2z" fill-rule="evenodd"/>
<path d="M371.4 255h.2v1.2a.3 .3 0 0 1-.1 .3 .3 .3 0 0 1-.3 0l.2-.2z" fill-rule="evenodd"/>
<path d="M371.9 255.2a.51 .51 0 0 1 .7-.1 .51 .51 0 0 1 .2 .5h-.8l.2 .4 .6-.2a.52 .52 0 0 1-.6 .3 .52 .52 0 0 1-.4-.6h.8l-.3-.3-.3 .3h-.2z" fill-rule="evenodd"/>
<path d="M373.1 255.1h.6l.2 .3h-.2a.34 .34 0 0 0-.5-.2 .34 .34 0 0 0 0 .6l.3 .2 .2-.3h.2a.53 .53 0 0 1-.8 .3 .53 .53 0 0 1 0-.8z" fill-rule="evenodd"/>
<path d="M374.1 254.8l.2-.1v.3h.2v.2h-.2v.6l.2 .3a.27 .27 0 0 1-.3 0 .27 .27 0 0 1-.1-.3v-.6h-.1z" fill-rule="evenodd"/>
<path d="M375.3 254.6h.2l.8 1.2v-1.2h.2v1.5h-.2l-.8-1.2v1.2h-.2z" fill-rule="evenodd"/>
<path d="M376.9 255.1l.1-.1a.47 .47 0 0 1 .6 .1 .47 .47 0 0 1 0 .6l.1 .4-.2-.1-.5 .1-.3-.1v-.2l.6 .2 .2-.4-.8 .2a.57 .57 0 0 1 .8-.4l-.2-.2-.6 .1z" fill-rule="evenodd"/>
<path d="M377.9 255h.2v.2l.3-.2 .3 .2 .3-.2 .3 .1 .1 1h-.2l-.1-.9a.26 .26 0 0 0-.2 0 .26 .26 0 0 0-.1 .3v.6h-.2v-.8l-.4-.1-.1 .9h-.2z" fill-rule="evenodd"/>
<path d="M379.8 255.2a.51 .51 0 0 1 .6-.1 .51 .51 0 0 1 .2 .5h-.8l.3 .4 .5-.2a.52 .52 0 0 1-.6 .3 .52 .52 0 0 1-.4-.6h.8l-.3-.3-.3 .3h-.2z" fill-rule="evenodd"/>
<path d="M380.9 255h.2v.2h-.2z" fill-rule="evenodd"/>
<path d="M380.9 255.9h.2v.2h-.2z" fill-rule="evenodd"/>
</g>
<g fill="#00007f">
<path d="M368.2 269.8a.42 .42 0 0 1 .6 .1 .42 .42 0 0 1-.1 .6l-.4 .5 .7-.1-.1 .2h-.9a.88 .88 0 0 0 .6-1.2h-.2l-.3 .2z" fill-rule="evenodd"/>
<path d="M369.3 269.8l.2-.1a.7 .7 0 0 1 .5 .7 .7 .7 0 0 1-.6 .7l-.3-.5 .2-.1a.36 .36 0 0 0 0 .4 .36 .36 0 0 0 .4 .1l.1-.8-.2-.4a.42 .42 0 0 0-.3 .7l-.2-.1z" fill-rule="evenodd"/>
<path d="M370.3 269.8a.42 .42 0 0 1 .6 .1 .42 .42 0 0 1-.1 .6l-.4 .5 .7-.1-.1 .2h-.9a.88 .88 0 0 0 .6-1.2h-.2l-.3 .2z" fill-rule="evenodd"/>
<path d="M371.6 269.7h.5l-.1 .2h-.4l-.1 .2a.5 .5 0 0 1 .5 .6 .5 .5 0 0 1-.7 .3 .4 .4 0 0 0 .6-.2 .4 .4 0 0 0-.5-.5h-.1z" fill-rule="evenodd"/>
<path d="M372.3 270.6h.5v.1h-.5z" fill-rule="evenodd"/>
<path d="M373.2 269.8l.1-.1a.7 .7 0 0 1 .6 .7 .7 .7 0 0 1-.6 .7l-.3-.5 .2-.1a.36 .36 0 0 0-.1 .4 .36 .36 0 0 0 .4 .1l.2-.6-.2-.6a.42 .42 0 0 0-.3 .7l-.2-.1z" fill-rule="evenodd"/>
<path d="M374.2 269.7h.7l-.5 1.4h-.1l.4-1.2h-.5l-.1 .2z" fill-rule="evenodd"/>
<path d="M375.1 270.6h.5v.1h-.5z" fill-rule="evenodd"/>
<path d="M375.9 269.9l.4-.2v1.3l.2 .1h-.5l.1-.1v-1z" fill-rule="evenodd"/>
<path d="M377 269.8h.4a.31 .31 0 0 1 0 .5 .44 .44 0 0 1 .1 .7 .44 .44 0 0 1-.6 0 .35 .35 0 0 0 .5-.1 .35 .35 0 0 0-.3-.5 .28 .28 0 0 0 .3-.2 .28 .28 0 0 0-.2-.3 .28 .28 0 0 0-.3 .1z" fill-rule="evenodd"/>
</g>
<g fill="#00f">
<path d="M341.2 275.6h.6a.42 .42 0 0 1 .6 .4 .42 .42 0 0 1-.5 .4l.6 .7h-.3a.74 .74 0 0 0-.8-.6v.6h-.2v-.8l.9-.1a.25 .25 0 0 0 0-.3 .25 .25 0 0 0-.3-.1h-.4v.5h-.2z" fill-rule="evenodd"/>
<path d="M342.7 276.2a.51 .51 0 0 1 .6-.1 .51 .51 0 0 1 .3 .5h-.8l.2 .4 .6-.2a.52 .52 0 0 1-.7 .3 .52 .52 0 0 1-.3-.6h.8l-.3-.3-.3 .3h-.2z" fill-rule="evenodd"/>
<path d="M343.7 276h.2l.3 .9 .3-.9h.2l-.4 1.1h-.2z" fill-rule="evenodd"/>
<path d="M344.9 275.6h.2v.2h-.2z" fill-rule="evenodd"/>
<path d="M344.9 276h.2v1.1h-.2z" fill-rule="evenodd"/>
<path d="M345.4 276.2a.51 .51 0 0 1 .6-.1 .51 .51 0 0 1 .3 .5h-.8l.2 .4 .6-.2a.52 .52 0 0 1-.7 .3 .52 .52 0 0 1-.3-.6h.8l-.3-.3-.3 .3h-.2z" fill-rule="evenodd"/>
<path d="M346.4 276h.2l.2 .9 .2-.9h.2l.2 .9 .3-.9h.2l-.4 1.1h-.2l-.2-.8-.2 .8h-.2z" fill-rule="evenodd"/>
<path d="M348.1 276.2a.51 .51 0 0 1 .6-.1 .51 .51 0 0 1 .3 .5h-.9l.3 .4 .6-.2a.52 .52 0 0 1-.7 .3 .52 .52 0 0 1-.3-.6h.8l-.3-.3-.3 .3h-.2z" fill-rule="evenodd"/>
<path d="M349.2 276h.1v.2l.4-.2v.2a.24 .24 0 0 0-.3 .1 .24 .24 0 0 0 0 .3v.5h-.2z" fill-rule="evenodd"/>
<path d="M349.9 276h.2v.2h-.2z" fill-rule="evenodd"/>
<path d="M349.9 276.9h.2v.2h-.2z" fill-rule="evenodd"/>
</g>
<path d="M332 274.5h34.5M339.5 274.5v10.5" fill="none" stroke="#000" stroke-width=".2"/>
<g fill="#00f">
<path d="M341.2 265.1h.5a.75 .75 0 0 1 .7 .8 .75 .75 0 0 1-.7 .7h-.5v-.2h.5a.58 .58 0 0 0 .5-.5 .58 .58 0 0 0-.5-.6h-.3v1.1h-.2z" fill-rule="evenodd"/>
<path d="M342.7 265.7l.1-.1a.51 .51 0 0 1 .6 0 .51 .51 0 0 1 .2 .5h-.8l.2 .4 .6-.2a.52 .52 0 0 1-.7 .3 .52 .52 0 0 1-.3-.6h.8l-.3-.3-.3 .3h-.2z" fill-rule="evenodd"/>
<path d="M343.8 265.6l.6-.1 .2 .3h-.2a.21 .21 0 0 0-.2-.2 .21 .21 0 0 0-.2 .3 .43 .43 0 0 1 .5 .1 .43 .43 0 0 1 .1 .4l-.2 .2h-.4l-.3-.3h.2a.24 .24 0 0 0 .3 .3 .24 .24 0 0 0 .2-.4 .43 .43 0 0 1-.6-.5z" fill-rule="evenodd"/>
<path d="M344.9 265.1h.2v.2h-.2z" fill-rule="evenodd"/>
<path d="M344.9 265.5h.2v1.1h-.2z" fill-rule="evenodd"/>
<path d="M345.4 265.6l.3-.1 .4 .2v-.2h.1v1a.48 .48 0 0 1-.3 .5 .48 .48 0 0 1-.6-.3l.5 .2 .2-.1v-.3a.47 .47 0 0 1-.5 0 .47 .47 0 0 1-.2-.4h.2a.34 .34 0 0 0 .4 .3 .34 .34 0 0 0 .1-.5 .3 .3 0 0 0-.3-.2 .3 .3 0 0 0-.2 .4h-.2z" fill-rule="evenodd"/>
<path d="M346.5 265.5h.2v.2l.3-.2a.35 .35 0 0 1 .4 .5v.6h-.2v-.6a.27 .27 0 0 0-.3-.3 .27 .27 0 0 0-.2 .3v.6h-.2z" fill-rule="evenodd"/>
<path d="M347.7 265.7l.1-.1a.51 .51 0 0 1 .6 0 .51 .51 0 0 1 .2 .5h-.8l.2 .4 .6-.2a.52 .52 0 0 1-.6 .3 .52 .52 0 0 1-.4-.6h.8l-.3-.3-.3 .3h-.2z" fill-rule="evenodd"/>
<path d="M348.8 265.5h.2v.2l.4-.2v.2a.24 .24 0 0 0-.3 .1 .24 .24 0 0 0-.1 .3v.5h-.2z" fill-rule="evenodd"/>
<path d="M349.6 265.5h.2v.2h-.2z" fill-rule="evenodd"/>
<path d="M349.6 266.4h.2v.2h-.2z" fill-rule="evenodd"/>
</g>
<path d="M332 264h34.5M339.5 264v10.5" fill="none" stroke="#000" stroke-width=".2"/>
<g fill="#00007f">
<path d="M341 269.7h.6a.7 .7 0 0 1 .8 .7 .7 .7 0 0 1-.7 .7h-.7l.2-.1v-1.2h.2v1.2a.65 .65 0 0 0 .8-.7 .65 .65 0 0 0-1-.5z" fill-rule="evenodd"/>
<path d="M342.7 270.2l.5 .1 .1 .7 .1-.1-.1 .2-.7-.1v-.1l.3 .1 .2-.1v-.3l-.5 .3 .5-.4-.2-.3-.3 .3z" fill-rule="evenodd"/>
<path d="M343.5 270.3l.3-.1v.2a.29 .29 0 0 1 .3-.2 .29 .29 0 0 1 .2 .3v.5l.2 .1h-.5l.2-.2v-.5l-.2-.1-.2 .1v.6l.1 .1h-.4l.1-.1v-.6z" fill-rule="evenodd"/>
<path d="M344.6 270.3l.3-.1v.8l.1 .1h-.4l.1-.1v-.5z" fill-rule="evenodd"/>
<path d="M345.3 270.3l.4-.1 .2 .2 .1 .1h-.7l.2 .4 .3 .1 .1-.2a.41 .41 0 0 1-.5 .3 .41 .41 0 0 1-.2-.6h.5l-.2-.3-.3 .3z" fill-rule="evenodd"/>
<path d="M346.1 269.8l.3-.1v1.3l.2 .1h-.5l.1-.1v-1.1z" fill-rule="evenodd"/>
<path d="M347.2 269.7h.5l-.1 .1-.1 .6 .6-.5-.1-.2h.5l-.8 .7 1 .7h-.7l.1-.1-.6-.6 .1 .6 .1 .1h-.5l.2-.2-.1-1z" fill-rule="evenodd"/>
<path d="M348.8 270.2l.6 .1v.7l.2-.1-.2 .2-.7-.1v-.1l.3 .1 .2-.1v-.3l-.5 .3 .5-.4-.1-.3-.3 .3z" fill-rule="evenodd"/>
<path d="M349.6 270.3l.3-.1v.2l.3-.2 .3 .2a.3 .3 0 0 1 .3-.2 .3 .3 0 0 1 .2 .3l.1 .5 .1 .1h-.5l.2-.1v-.5a.2 .2 0 0 0-.2-.2 .2 .2 0 0 0-.2 .2v.5l.1 .1h-.4l.1-.1v-.5l-.1-.2-.3 .1v.6l.2 .1h-.5l.1-.1v-.5z" fill-rule="evenodd"/>
<path d="M351.2 270.3l.3-.1v.2a.39 .39 0 0 1 .6-.1 .39 .39 0 0 1 0 .5l-.2 .3h-.4v.4l.2 .1h-.5l.2-.2v-1h.1l.1 .6a.33 .33 0 0 0 .4-.3 .33 .33 0 0 0-.4-.3h-.2z" fill-rule="evenodd"/>
<path d="M352.4 270.3l.4-.1 .3 .2v.1h-.6l.1 .4 .3 .1 .2-.2a.41 .41 0 0 1-.6 .3 .41 .41 0 0 1-.1-.6h.5l-.2-.3-.3 .3z" fill-rule="evenodd"/>
<path d="M353.2 270.3l.3-.1v.2l.2-.2h.2l-.4 .3v.5l.2 .1h-.5l.1-.1 .1-.5z" fill-rule="evenodd"/>
<path d="M354.2 269.9v.3h.2h-.2v.7h.3l-.3 .2-.1-.1-.1-.8h-.1z" fill-rule="evenodd"/>
<circle cx="344.8" cy="269.8" r=".1"/>
</g>
<path d="M332 264h-34.5v10.5h34.5" fill="none" stroke="#000" stroke-width=".2"/>
<g fill="#00007f">
<path d="M299.2 269.7h1l-.9 1.3h.7l.2-.3v.4h-1.2l.9-1.3h-.6l-.2 .3z" fill-rule="evenodd"/>
<path d="M300.5 269.8l.7-.1v.5a.29 .29 0 0 0-.3-.4 .29 .29 0 0 0-.2 .4h.1a.49 .49 0 0 1 .5 .3 .49 .49 0 0 1-.2 .6l-.7 .1 .1-.5a.33 .33 0 0 0 .3 .4 .33 .33 0 0 0 .3-.4l-.1-.1a.51 .51 0 0 1-.5-.2 .51 .51 0 0 1 0-.6z" fill-rule="evenodd"/>
<path d="M301.5 269.7h.5l-.1 .2 .3 .9 .2-.7-.3-.4h.6l-.2 .2 .3 .9 .3-.9-.1-.2h.4l-.6 1.5-.3-.9-.4 .9z" fill-rule="evenodd"/>
<path d="M303.5 270.2l.5 .1v.7l.2-.1-.1 .2-.7-.1-.1-.1 .4 .1 .2-.1v-.3l-.6 .3 .6-.4-.2-.3-.3 .3z" fill-rule="evenodd"/>
<path d="M304.5 269.9v.3h.3h-.3v.7h.3l-.3 .2-.1-.1v-.8h-.2z" fill-rule="evenodd"/>
<path d="M305 270.3l.4-.1 .2 .1-.1 .2a.28 .28 0 0 0-.4-.3 .28 .28 0 0 0-.1 .5l.3 .3 .3-.2a.43 .43 0 0 1-.6 .3 .43 .43 0 0 1-.1-.7z" fill-rule="evenodd"/>
<path d="M305.7 269.8l.3-.1v.7l.3-.2h.2l.1 .8 .1 .1h-.4l.1-.2v-.5l-.1-.1-.3 .1 .1 .6 .1 .1h-.5l.2-.1v-.9z" fill-rule="evenodd"/>
<path d="M306.8 270.6h.6v.1h-.6z" fill-rule="evenodd"/>
<path d="M307.5 269.7h.6a.7 .7 0 0 1 .8 .7 .7 .7 0 0 1-.8 .7h-.6l.2-.1v-1.2h.2v1.2a.65 .65 0 0 0 .7-.7 .65 .65 0 0 0-.9-.5z" fill-rule="evenodd"/>
<path d="M309.2 270.3a.46 .46 0 0 1 .7 .1 .46 .46 0 0 1-.3 .7 .46 .46 0 0 1-.6-.5h.2a.34 .34 0 0 0 .1 .4 .34 .34 0 0 0 .5-.1 .34 .34 0 0 0-.1-.4l-.2-.3-.3 .4h-.2z" fill-rule="evenodd"/>
<path d="M310.2 270.3l.4-.1 .2 .1v.2a.28 .28 0 0 0-.4-.3 .28 .28 0 0 0-.1 .5l.2 .3 .4-.2a.43 .43 0 0 1-.7 .3 .43 .43 0 0 1 0-.7z" fill-rule="evenodd"/>
<path d="M311 269.8l.3-.1v.9l.3-.3v-.1h.4l-.5 .3 .5 .6h-.4l-.3-.5v.4l.1 .1h-.4l.1-.2v-1z" fill-rule="evenodd"/>
<path d="M312.5 269.8l.4-.1v.9l.3-.3-.1-.1h.4l-.5 .3 .6 .6h-.5l-.2-.5v.4l.1 .1h-.5l.2-.2v-1z" fill-rule="evenodd"/>
<path d="M313.6 270.3l.4-.1v.8l.1 .1h-.4l.1-.1v-.5z" fill-rule="evenodd"/>
<path d="M314.4 270.3l.4-.1 .2 .1-.1 .2a.28 .28 0 0 0-.4-.3 .28 .28 0 0 0-.1 .5l.2 .3 .4-.2a.43 .43 0 0 1-.6 .3 .43 .43 0 0 1-.1-.7z" fill-rule="evenodd"/>
<path d="M315.3 270.2l.5 .1 .1 .7 .1-.1-.1 .2-.7-.1v-.1l.3 .1 .2-.1v-.3l-.5 .3 .5-.4-.2-.3-.3 .3z" fill-rule="evenodd"/>
<path d="M316.6 269.8l.3-.1v1.3h.2l-.6 .2-.3-.2-.1-.4h.2l.2 .4 .3-.1-.2-.7-.2 .1-.1 .3h-.2v-.1a.41 .41 0 0 1 .7-.3l-.1-.4z" fill-rule="evenodd"/>
<path d="M317.1 271.5l1 .1z" fill-rule="evenodd"/>
<path d="M318.1 270.3l.3-.1v.2a.39 .39 0 0 1 .6-.1 .39 .39 0 0 1 .1 .5l-.3 .3h-.4l.1 .4 .1 .1h-.5l.2-.2v-1h.1l.1 .6a.33 .33 0 0 0 .4-.3 .33 .33 0 0 0-.4-.3h-.2z" fill-rule="evenodd"/>
<path d="M319.4 270.3l.4-.1 .2 .1-.1 .2a.28 .28 0 0 0-.4-.3 .28 .28 0 0 0-.1 .5l.2 .3 .4-.2a.43 .43 0 0 1-.6 .3 .43 .43 0 0 1-.1-.7z" fill-rule="evenodd"/>
<path d="M320.1 269.8l.3-.1v.6a.45 .45 0 0 1 .7 .3 .45 .45 0 0 1-.5 .6l-.3-.2v-.6h.1v.6a.32 .32 0 0 0 .5-.3 .32 .32 0 0 0-.5-.3h-.1v-.5z" fill-rule="evenodd"/>
<circle cx="312.3" cy="271" r=".11"/>
<circle cx="313.9" cy="269.8" r=".1"/>
</g>
<path d="M366.5 253.5h-69v10.5" fill="none" stroke="#000" stroke-width=".2"/>
<g fill="#00f">
<path d="M299.2 254.6l.9 .1 .1 .3-.2 .3a.42 .42 0 0 1 .3 .6 .42 .42 0 0 1-.6 .2h-.5v-.2l.9-.1-.1-.3-.6-.1v.5h-.2v-.7h.5a.24 .24 0 0 0 .3-.1 .24 .24 0 0 0-.2-.3h-.4v.4h-.2z" fill-rule="evenodd"/>
<path d="M300.6 255.1a.55 .55 0 0 1 .9 .1 .55 .55 0 0 1-.3 .8 .55 .55 0 0 1-.7-.4h.2a.37 .37 0 0 0 .5 .4 .37 .37 0 0 0 0-.7l-.3-.1-.2 .4h-.2z" fill-rule="evenodd"/>
<path d="M301.8 255.2l.1-.2a.47 .47 0 0 1 .6 .1 .47 .47 0 0 1 .1 .6v.4l-.2-.1-.5 .1-.2-.1-.1-.2 .6 .2 .2-.4-.8 .2a.57 .57 0 0 1 .8-.4l-.2-.2-.5 .1z" fill-rule="evenodd"/>
<path d="M302.9 255h.1v.2l.4-.2v.2a.25 .25 0 0 0-.3 .1 .25 .25 0 0 0 0 .3v.5h-.2z" fill-rule="evenodd"/>
<path d="M303.7 255.1l.3-.1 .3 .2v-.6h.1v1.5h-.1v-.1l-.2 .1h-.4l-.2-.4 .2-.1a.34 .34 0 0 0 .4 .4 .34 .34 0 0 0 .2-.6l-.4-.2-.2 .4h-.2z" fill-rule="evenodd"/>
<path d="M305.3 254.6h.2l.8 1.2v-1.2h.2v1.5h-.2l-.8-1.2v1.2h-.2z" fill-rule="evenodd"/>
<path d="M306.9 255.2l.1-.2a.47 .47 0 0 1 .6 .1 .47 .47 0 0 1 .1 .6l.1 .4-.3-.1-.4 .1-.3-.1v-.2l.6 .2 .1-.4-.7 .2a.57 .57 0 0 1 .7-.4l-.1-.2-.6 .1z" fill-rule="evenodd"/>
<path d="M308 255h.2v.2l.2-.2 .4 .2 .3-.2 .2 .1 .2 1h-.2l-.1-.9a.26 .26 0 0 0-.3 0 .26 .26 0 0 0-.1 .3v.6h-.2v-.8l-.3-.1-.1 .9h-.2z" fill-rule="evenodd"/>
<path d="M309.8 255.2a.51 .51 0 0 1 .6-.1 .51 .51 0 0 1 .3 .5h-.8l.2 .4 .6-.2a.52 .52 0 0 1-.7 .3 .52 .52 0 0 1-.3-.6h.8l-.3-.3-.3 .3h-.2z" fill-rule="evenodd"/>
<path d="M311 255h.2v.2h-.2z" fill-rule="evenodd"/>
<path d="M311 255.9h.2v.2h-.2z" fill-rule="evenodd"/>
<path d="M368 244.1h.2l.5 1.4 .5-1.4h.2l-.6 1.5h-.2z" fill-rule="evenodd"/>
<path d="M369.6 244.6l.1-.1a.47 .47 0 0 1 .5 .1 .47 .47 0 0 1 .1 .6l.1 .4-.2-.1-.5 .1-.3-.1v-.2l.6 .2 .2-.4-.8 .2a.57 .57 0 0 1 .8-.4l-.2-.2-.6 .1z" fill-rule="evenodd"/>
<path d="M370.5 244.5h.2v.2l.4-.2v.2a.25 .25 0 0 0-.3 .1 .25 .25 0 0 0-.1 .3v.5h-.2z" fill-rule="evenodd"/>
<path d="M371.2 244.1h.2v.2h-.2z" fill-rule="evenodd"/>
<path d="M371.2 244.5h.2v1.1h-.2z" fill-rule="evenodd"/>
<path d="M371.8 244.6l.1-.1a.47 .47 0 0 1 .6 .1 .47 .47 0 0 1 .1 .6l.1 .4-.3-.1-.5 .1-.2-.1v-.2l.6 .2 .1-.4-.7 .2a.57 .57 0 0 1 .7-.4l-.2-.2-.5 .1z" fill-rule="evenodd"/>
<path d="M372.9 244.5h.1v.2l.4-.2a.35 .35 0 0 1 .4 .5v.6h-.2v-.6a.27 .27 0 0 0-.3-.3 .27 .27 0 0 0-.2 .3v.6h-.2z" fill-rule="evenodd"/>
<path d="M374.1 244.3l.2-.1v.3h.2v.2h-.2v.6l.2 .3a.27 .27 0 0 1-.3 0 .27 .27 0 0 1-.1-.3v-.6h-.2z" fill-rule="evenodd"/>
<path d="M374.7 244.5h.2v.2h-.2z" fill-rule="evenodd"/>
<path d="M374.7 245.4h.2v.2h-.2z" fill-rule="evenodd"/>
</g>
<path d="M408 243h-41.5v10.5" fill="none" stroke="#000" stroke-width=".2"/>
<g fill="#00007f">
<path d="M368.3 248.9l1-.2v.5a.53 .53 0 0 0-.7-.4 .53 .53 0 0 0-.3 .8l.1 .3 .3 .2 .4-.1 .2-.2a.6 .6 0 0 1-1 .2 .78 .78 0 0 1 0-1.1z" fill-rule="evenodd"/>
<path d="M369.4 248.7h.6l-.2 .1v.6h.7v-.6l-.2-.1h.6l-.2 .3v1l.2 .1h-.6l.2-.1v-.5h-.7v.5l.2 .1h-.6l.2-.2v-1z" fill-rule="evenodd"/>
<path d="M371 248.7h1v.3l-.1-.2h-.5v.6l.4-.1 .1-.1v.4l-.1-.1-.4-.1v.6a.51 .51 0 0 0 .7-.2l-.1 .3h-1l.2-.2v-1z" fill-rule="evenodd"/>
<path d="M372.5 248.9l1-.2v.5a.53 .53 0 0 0-.7-.4 .53 .53 0 0 0-.3 .8l.1 .3 .3 .2 .4-.1 .2-.2a.6 .6 0 0 1-1 .2 .78 .78 0 0 1 0-1.1z" fill-rule="evenodd"/>
<path d="M373.6 248.7h.6l-.2 .1v.6l.5-.5-.1-.2h.5l-.7 .7 .9 .7h-.6l.1-.1-.6-.6v.6l.2 .1h-.6l.2-.2v-1z" fill-rule="evenodd"/>
<path d="M375.2 248.7h1v.3l-.1-.2h-.6v.6l.5-.1 .1-.1v.4l-.1-.1-.5-.1 .1 .6a.51 .51 0 0 0 .7-.2l-.1 .3h-1l.2-.2-.1-1z" fill-rule="evenodd"/>
<path d="M376.4 248.7h.6a.7 .7 0 0 1 .8 .7 .7 .7 0 0 1-.7 .7h-.7l.2-.1v-1.2h.2v1.2a.65 .65 0 0 0 .8-.7 .65 .65 0 0 0-1-.5z" fill-rule="evenodd"/>
</g>
<path d="M366.5 243h-69v10.5" fill="none" stroke="#000" stroke-width=".2"/>
<g fill="#00f">
<path d="M299.3 244.3l.7-.2 .4 .3-.2 .2a.53 .53 0 0 0-.8-.2 .53 .53 0 0 0 0 .8l.4 .3 .3-.1 .1-.3h.2a.74 .74 0 0 1-1.1 .4 .74 .74 0 0 1 0-1.2z" fill-rule="evenodd"/>
<path d="M300.8 244.6a.54 .54 0 0 1 .8 .1 .54 .54 0 0 1-.3 .8 .54 .54 0 0 1-.7-.4h.2a.37 .37 0 0 0 .5 .4 .37 .37 0 0 0 .1-.7l-.4-.1-.2 .4h-.2z" fill-rule="evenodd"/>
<path d="M301.8 244.5h.2v.2l.4-.2 .2 .2 .3-.2 .3 .1 .1 1h-.2l-.1-.9a.26 .26 0 0 0-.3 0 .26 .26 0 0 0 0 .3v.6h-.2l-.1-.8-.3-.1-.1 .9h-.2z" fill-rule="evenodd"/>
<path d="M303.6 244.5h.1v.2a.5 .5 0 0 1 .8 .4 .5 .5 0 0 1-.7 .4v.5h-.2v-.9h.1a.33 .33 0 0 0 .4 .4 .33 .33 0 0 0 .2-.5l-.1-.3h-.2l-.3 .4h-.1z" fill-rule="evenodd"/>
<path d="M304.8 244.6l.1-.1a.47 .47 0 0 1 .6 .1 .47 .47 0 0 1 .1 .6l.1 .4-.3-.1-.4 .1-.3-.1v-.2l.6 .2 .1-.4-.7 .2a.57 .57 0 0 1 .7-.4l-.1-.2-.6 .1z" fill-rule="evenodd"/>
<path d="M305.9 244.5h.2v.2l.3-.2a.35 .35 0 0 1 .4 .5v.6h-.2v-.6a.27 .27 0 0 0-.3-.3 .27 .27 0 0 0-.2 .3v.6h-.2z" fill-rule="evenodd"/>
<path d="M307 244.5h.2l.3 .9 .3-.9h.2l-.6 1.4-.2 .2-.1-.1-.1-.1 .3-.1 .1-.2z" fill-rule="evenodd"/>
<path d="M308.2 244.5h.2v.2h-.2z" fill-rule="evenodd"/>
<path d="M308.2 245.4h.2v.2h-.2z" fill-rule="evenodd"/>
</g>
<g fill="#00007f">
<path d="M299.2 248.7h1.1l-.8 1.3a.68 .68 0 0 0 .9-.4l-.1 .5h-1.3l.9-1.3a.54 .54 0 0 0-.8 .3z" fill-rule="evenodd"/>
<path d="M300.6 248.8l.8-.1v.5l-.4-.4-.3 .2 .2 .2a.52 .52 0 0 1 .5 .7 .52 .52 0 0 1-.8 .2l-.1 .1v-.6a.35 .35 0 0 0 .3 .5 .35 .35 0 0 0 .4-.3l-.6-.5z" fill-rule="evenodd"/>
<path d="M301.6 248.7h.6l-.1 .2 .3 .8 .2-.5-.3-.5h.7l-.2 .1 .3 .8 .3-.7-.1-.2 .3 .1-.6 1.4-.4-.9-.4 .9z" fill-rule="evenodd"/>
<path d="M303.7 249.3l.4-.2 .3 .1v.8h.2l-.1 .1-.4-.1-.2 .1-.2-.1v-.1h.4v-.3l-.2 .3h-.2l.4-.4v-.2h-.2a.15 .15 0 0 1 0 .2 .15 .15 0 0 1-.2 0 .15 .15 0 0 1 0-.2z" fill-rule="evenodd"/>
<path d="M305 248.8v.4h.3l-.3 .1 .1 .7 .2-.1-.3 .2-.2-.1v-.7l-.2-.1z" fill-rule="evenodd"/>
<path d="M305.5 249.3l.5-.1 .1 .3h-.2l-.1-.3a.37 .37 0 0 0-.1 .5 .37 .37 0 0 0 .5 .2 .47 .47 0 0 1-.8 .1 .47 .47 0 0 1 .1-.7z" fill-rule="evenodd"/>
<path d="M306.3 248.7h.4v.6l.2-.2a.29 .29 0 0 1 .3 .4l.1 .6h-.4v-.8l-.2 .1 .1 .7h-.5l.1-.2z" fill-rule="evenodd"/>
<path d="M368.7 259h1.5l-1.1 1.7a.91 .91 0 0 0 1.2-.5l-.1 .6h-1.7l1.1-1.7a.73 .73 0 0 0-.9 .4z" fill-rule="evenodd"/>
<path d="M370.7 259.1l.4-.2 .4 .2 .2-.2-.1 .7a.41 .41 0 0 0-.3-.6 .41 .41 0 0 0-.5 .4l.2 .1a.82 .82 0 0 1 .8 1l-.4 .3h-.7l-.2 .1 .1-.7a.48 .48 0 0 0 .3 .5 .48 .48 0 0 0 .6-.3l-.2-.2a.72 .72 0 0 1-.7-1z" fill-rule="evenodd"/>
<path d="M371.9 259h.8l-.1 .2 .4 1 .3-.7-.4-.5h.9l-.2 .1 .4 1.1 .4-1-.2-.2h.5l-.8 1.9-.5-1.2-.6 1.2z" fill-rule="evenodd"/>
<path d="M374.8 259.7l.2-.1a.47 .47 0 0 1 .5-.1 .47 .47 0 0 1 .2 .5l.1 .6h.1l-.4 .2a.35 .35 0 0 0-.6 0l-.2-.1v-.2h.7v-.4l-.3 .4h-.4l.7-.5-.1-.3h-.3a.2 .2 0 0 1 .1 .3 .2 .2 0 0 1-.3 0 .2 .2 0 0 1 0-.3z" fill-rule="evenodd"/>
<path d="M376.5 259.1l.1 .5h.3v.1h-.3v.9h.3l-.1 .2a.35 .35 0 0 1-.5 0 .35 .35 0 0 1-.1-.4v-.7l-.2-.1z" fill-rule="evenodd"/>
<path d="M377.2 259.7a.4 .4 0 0 1 .5-.2 .4 .4 0 0 1 .2 .5h-.2l-.1-.4a.5 .5 0 0 0-.2 .6 .5 .5 0 0 0 .6 .4v-.1a.58 .58 0 0 1-.8 .2 .58 .58 0 0 1-.1-.8z" fill-rule="evenodd"/>
<path d="M378.2 259h.6v.7a.4 .4 0 0 1 .5-.2 .4 .4 0 0 1 .2 .6v.6l.1 .1h-.6l.1-.2-.1-.9-.2 .2 .1 .9h-.7l.2-.2v-1.5z" fill-rule="evenodd"/>
<path d="M380.4 259h.9a.93 .93 0 0 1 1 .9 .93 .93 0 0 1-1 .9h-.9l.3-.1v-.2h.4l.1 .2a.57 .57 0 0 0 .6-.8 .64 .64 0 0 0-.7-.8v1.4h-.4v-1.3z" fill-rule="evenodd"/>
<path d="M382.8 259.6a.62 .62 0 0 1 .8 .2 .62 .62 0 0 1-.2 .9 .62 .62 0 0 1-.8-.2l-.1-.2h.4v.3a.18 .18 0 0 0 .2 .2 .18 .18 0 0 0 .2-.2v-.8a.19 .19 0 0 0-.3-.2 .19 .19 0 0 0-.1 .3v.4h-.4z" fill-rule="evenodd"/>
<path d="M384.1 259.7a.4 .4 0 0 1 .5-.2 .4 .4 0 0 1 .3 .5h-.2l-.2-.4a.5 .5 0 0 0-.2 .6 .5 .5 0 0 0 .6 .4v-.1a.58 .58 0 0 1-.8 .2 .58 .58 0 0 1-.1-.8z" fill-rule="evenodd"/>
<path d="M385.1 259h.6v1.2l.4-.5-.1-.1h.5l-.5 .4 .6 .8h-.6l.1-.1-.3-.5-.1 .5 .1 .1h-.7l.2-.2v-1.5z" fill-rule="evenodd"/>
<path d="M299.5 258.7h1.1a1.17 1.17 0 0 1 1.3 1.2 1.17 1.17 0 0 1-1.3 1.1h-1.1l.3-.1 .1-.2h.5v.1a.53 .53 0 0 0 .7 0 .53 .53 0 0 0 .1-.6 .93 .93 0 0 0-.8-1.4v1.9h-.5v-1.7z" fill-rule="evenodd"/>
<path d="M302.5 259.5a.79 .79 0 0 1 1.1 .8 .79 .79 0 0 1-1.3 .5l-.1-.4h.5v.3a.22 .22 0 0 0 .2 .3 .22 .22 0 0 0 .2-.2v-1.1a.23 .23 0 0 0-.3-.2 .23 .23 0 0 0-.1 .3v.6h-.5v-.5z" fill-rule="evenodd"/>
<path d="M304.2 259.6a.5 .5 0 0 1 .6-.2 .5 .5 0 0 1 .3 .6 .36 .36 0 0 1-.4-.4l-.1-.1a.42 .42 0 0 0-.2 .7 .51 .51 0 0 0 .3 .6 .51 .51 0 0 0 .5-.1 .77 .77 0 0 1-1.1 .2 .77 .77 0 0 1 0-1.2z" fill-rule="evenodd"/>
<path d="M305.4 258.7h.7v1.5l.5-.5-.1-.3h.7l-.7 .6 .8 1h-.8l.1-.1-.4-.6-.1 .6 .2 .1h-.9l.2-.3v-1.8z" fill-rule="evenodd"/>
<path d="M307.4 260.1h1v.3h-1z" fill-rule="evenodd"/>
<path d="M308.5 258.7h1.2l-.3 .2v.9h.8v-.9l-.3-.2h1.2l-.3 .1v.3v1.7l.3 .2h-1.2l.3-.1v-1h-.8v1l.3 .1h-1.2l.3-.1v-.3v-1.6z" fill-rule="evenodd"/>
<path d="M311.2 258.7h1l-.2 .3 .5 1.3 .4-.9-.2-.5-.3-.2h1.1l-.2 .2 .5 1.3 .4-1.2-.2-.3 .6 .1-.2 .1-.8 2.2-.6-1.5-.7 1.5z" fill-rule="evenodd"/>
</g>
<path d="M263 274.5h34.5M297.5 264h-34.5v21" fill="none" stroke="#000" stroke-width=".2"/>
<g fill="#00f">
<path d="M299.2 265.1h1v.2h-.8v.5h.7v.1h-.7v.7h-.2z" fill-rule="evenodd"/>
<path d="M300.4 265.1h.2v.2h-.2z" fill-rule="evenodd"/>
<path d="M300.4 265.5h.2v1.1h-.2z" fill-rule="evenodd"/>
<path d="M300.9 265.1h.2v1.5h-.2z" fill-rule="evenodd"/>
<path d="M301.4 265.7l.1-.1a.51 .51 0 0 1 .6 0 .51 .51 0 0 1 .2 .5h-.8l.2 .4 .6-.2a.52 .52 0 0 1-.7 .3 .52 .52 0 0 1-.3-.6h.8l-.3-.3-.3 .3h-.2z" fill-rule="evenodd"/>
<path d="M303.1 265.1h.2l.8 1.2v-1.2h.2v1.5h-.2l-.8-1.2v1.2h-.2z" fill-rule="evenodd"/>
<path d="M304.7 265.6l.1-.1a.47 .47 0 0 1 .6 .1 .47 .47 0 0 1 .1 .6l.1 .4-.3-.1-.5 .1-.2-.1v-.2l.6 .2 .1-.4-.7 .2a.57 .57 0 0 1 .7-.4l-.2-.2-.5 .1z" fill-rule="evenodd"/>
<path d="M305.8 265.5h.1v.2l.5-.2 .2 .2 .2-.2 .3 .1 .2 1h-.2l-.1-.9a.26 .26 0 0 0-.3 0 .26 .26 0 0 0-.1 .3v.6h-.2v-.8l-.3-.1-.1 .9h-.2z" fill-rule="evenodd"/>
<path d="M307.6 265.7l.1-.1a.51 .51 0 0 1 .6 0 .51 .51 0 0 1 .2 .5h-.8l.2 .4 .6-.2a.52 .52 0 0 1-.7 .3 .52 .52 0 0 1-.3-.6h.8l-.3-.3-.3 .3h-.2z" fill-rule="evenodd"/>
<path d="M308.8 265.5h.2v.2h-.2z" fill-rule="evenodd"/>
<path d="M308.8 266.4h.2v.2h-.2z" fill-rule="evenodd"/>
<path d="M264.8 265.2l.7-.1 .2 .4-.1 .1a.32 .32 0 0 0-.4-.4 .32 .32 0 0 0-.3 .5h.3a.5 .5 0 0 1 .6 .6 .5 .5 0 0 1-.8 .3l-.4-.3v-.2h.2a.39 .39 0 0 0 .4 .4 .39 .39 0 0 0 .4-.4l-.9-.4v-.2z" fill-rule="evenodd"/>
<path d="M266 265.1h.2v.6l.3-.2 .4 .2v.9h-.2v-.7a.27 .27 0 0 0-.3-.2 .27 .27 0 0 0-.2 .3v.6h-.2z" fill-rule="evenodd"/>
<path d="M267.3 265.7l.1-.1a.51 .51 0 0 1 .5 0 .51 .51 0 0 1 .2 .5h-.8l.3 .4 .5-.2a.52 .52 0 0 1-.6 .3 .52 .52 0 0 1-.3-.6h.8l-.3-.3-.4 .3h-.1z" fill-rule="evenodd"/>
<path d="M268.5 265.7v-.1a.51 .51 0 0 1 .6 0 .51 .51 0 0 1 .2 .5h-.8l.2 .4 .6-.2a.52 .52 0 0 1-.6 .3 .52 .52 0 0 1-.4-.6h.8l-.3-.3-.3 .3h-.2z" fill-rule="evenodd"/>
<path d="M269.6 265.3l.2-.1v.3h.1v.2h-.1v.6l.2 .3a.27 .27 0 0 1-.3 0 .27 .27 0 0 1-.1-.3v-.6h-.2z" fill-rule="evenodd"/>
<path d="M270.6 265.1h1.2v.2h-.5v1.3h-.2v-1.3h-.5z" fill-rule="evenodd"/>
<path d="M271.9 265.1h.2v.2h-.2z" fill-rule="evenodd"/>
<path d="M271.9 265.5h.2v1.1h-.2z" fill-rule="evenodd"/>
<path d="M272.4 265.3l.2-.1v.3h.1v.2h-.1v.6l.2 .3a.27 .27 0 0 1-.3 0 .27 .27 0 0 1-.1-.3v-.6h-.2z" fill-rule="evenodd"/>
<path d="M272.9 265.1h.2v1.5h-.2z" fill-rule="evenodd"/>
<path d="M273.5 265.7v-.1a.51 .51 0 0 1 .6 0 .51 .51 0 0 1 .2 .5h-.8l.3 .4 .5-.2a.52 .52 0 0 1-.6 .3 .52 .52 0 0 1-.4-.6h.8l-.3-.3-.3 .3h-.2z" fill-rule="evenodd"/>
<path d="M274.6 265.5h.2v.2h-.2z" fill-rule="evenodd"/>
<path d="M274.6 266.4h.2v.2h-.2z" fill-rule="evenodd"/>
<path d="M264.8 275.7l.7-.1 .2 .4-.1 .1a.32 .32 0 0 0-.4-.4 .32 .32 0 0 0-.3 .5h.3a.5 .5 0 0 1 .6 .6 .5 .5 0 0 1-.8 .3l-.4-.3v-.2h.2a.39 .39 0 0 0 .4 .4 .39 .39 0 0 0 .4-.4l-.9-.4v-.2z" fill-rule="evenodd"/>
<path d="M266 275.6h.2v.6l.3-.2 .4 .2v.9h-.2v-.7a.27 .27 0 0 0-.3-.2 .27 .27 0 0 0-.2 .3v.6h-.2z" fill-rule="evenodd"/>
<path d="M267.3 276.2a.51 .51 0 0 1 .6-.1 .51 .51 0 0 1 .2 .5h-.8l.3 .4 .5-.2a.52 .52 0 0 1-.6 .3 .52 .52 0 0 1-.3-.6h.8l-.3-.3-.4 .3h-.1z" fill-rule="evenodd"/>
<path d="M268.5 276.2a.51 .51 0 0 1 .6-.1 .51 .51 0 0 1 .2 .5h-.8l.2 .4 .6-.2a.52 .52 0 0 1-.6 .3 .52 .52 0 0 1-.4-.6h.8l-.3-.3-.3 .3h-.2z" fill-rule="evenodd"/>
<path d="M269.6 275.8l.2-.1v.3h.1v.2h-.1v.6l.2 .3a.27 .27 0 0 1-.3 0 .27 .27 0 0 1-.1-.3v-.6h-.2z" fill-rule="evenodd"/>
<path d="M270.7 275.6h.6a.46 .46 0 0 1 .6 .5 .46 .46 0 0 1-.6 .4h-.4v.6h-.2v-.8h.8l.2-.2-.2-.3h-.6v.5h-.2z" fill-rule="evenodd"/>
<path d="M272.2 276.2l.1-.2a.47 .47 0 0 1 .6 .1 .47 .47 0 0 1 .1 .6v.4l-.2-.1-.5 .1-.2-.1-.1-.2 .6 .2 .2-.4-.8 .2a.57 .57 0 0 1 .8-.4l-.2-.2-.5 .1z" fill-rule="evenodd"/>
<path d="M273.3 275.8l.2-.1v.3h.2v.2h-.2v.6l.2 .3a.27 .27 0 0 1-.3 0 .27 .27 0 0 1-.1-.3v-.6h-.1z" fill-rule="evenodd"/>
<path d="M273.9 275.6h.1v.6l.4-.2 .3 .1v1h-.1v-.7a.27 .27 0 0 0-.4-.2 .27 .27 0 0 0-.2 .3v.6h-.1z" fill-rule="evenodd"/>
<path d="M275.1 276h.2v.2h-.2z" fill-rule="evenodd"/>
<path d="M275.1 276.9h.2v.2h-.2z" fill-rule="evenodd"/>
</g>
<g fill="#00007f">
<path d="M264.5 269.7h.6a.7 .7 0 0 1 .8 .7 .7 .7 0 0 1-.7 .7h-.7l.2-.1v-1.2h.2v1.2a.65 .65 0 0 0 .8-.7 .65 .65 0 0 0-1-.5z" fill-rule="evenodd"/>
<path d="M266 270.3l.4-.1v.2l.1-.2h.2l-.3 .3v.5l.1 .1h-.5l.2-.1v-.6z" fill-rule="evenodd"/>
<path d="M266.8 270.3l.3-.1v.8l.1 .1h-.4l.1-.1v-.5z" fill-rule="evenodd"/>
<path d="M267.4 269.8l.3-.1v1.3l.1 .1h-.4l.1-.1v-.9z" fill-rule="evenodd"/>
<path d="M267.9 269.8l.4-.1v1.3l.1 .1h-.4l.1-.1v-.9v-.3z" fill-rule="evenodd"/>
<path d="M269 269.7h.6a.7 .7 0 0 1 .8 .7 .7 .7 0 0 1-.8 .7h-.6l.2-.1v-1.2h.2v1.2a.65 .65 0 0 0 .8-.7 .65 .65 0 0 0-1-.5z" fill-rule="evenodd"/>
<path d="M270.5 270.3l.3-.1v.2l.2-.2h.2l-.4 .3v.5l.2 .1h-.5l.2-.1v-.5z" fill-rule="evenodd"/>
<path d="M271.4 270.2l.5 .1 .1 .7 .1-.1-.1 .2-.7-.1v-.1l.3 .1 .2-.1v-.3l-.5 .3 .5-.4-.2-.3-.3 .3z" fill-rule="evenodd"/>
<path d="M272.1 270.2h.4v.1l.2 .6 .2-.4-.2-.3h.4l-.1 .1 .2 .6 .2-.6-.1-.1h.3l-.4 1-.3-.6-.3 .6z" fill-rule="evenodd"/>
<path d="M273.7 270.3l.3-.1v.8l.2 .1h-.5l.2-.1v-.5v-.2z" fill-rule="evenodd"/>
<path d="M274.2 270.3l.4-.1v.2a.29 .29 0 0 1 .3-.2 .29 .29 0 0 1 .2 .3v.5l.2 .1h-.5l.2-.2-.1-.5-.1-.1-.2 .1v.6l.1 .1h-.4l.1-.1v-.4v-.3z" fill-rule="evenodd"/>
<path d="M275.5 270.3l.8-.1-.2 .1v.4l-.5 .2 .6 .1a.43 .43 0 0 1-.3 .6 .43 .43 0 0 1-.5-.3 .43 .43 0 0 0 .4 .2 .43 .43 0 0 0 .4-.3l-.6-.1-.2 .2 .2-.5-.2-.3h.2l.1 .2a.22 .22 0 0 0 .3-.1 .22 .22 0 0 0-.1-.3 .22 .22 0 0 0-.3 .1l-.2 .1z" fill-rule="evenodd"/>
<path d="M277.3 269.8l.2-.1a1.42 1.42 0 0 0 0 1.9l-.5-.6a1.12 1.12 0 0 1 .3-1.2z" fill-rule="evenodd"/>
<path d="M277.6 269.7h.6l-.2 .2v1a.48 .48 0 0 0 .8-.2l-.1 .4h-1.1l.2-.2v-1z" fill-rule="evenodd"/>
<path d="M279.1 269.9l.4-.2v1.3l.1 .1h-.5l.2-.1v-.9v-.2z" fill-rule="evenodd"/>
<path d="M280.5 270.6h.5v.1h-.5z" fill-rule="evenodd"/>
<path d="M281.7 269.7h.6l-.2 .2v1a.48 .48 0 0 0 .8-.2l-.1 .4h-1.1l.2-.2v-1z" fill-rule="evenodd"/>
<path d="M283.6 269.7h.1v.9h.2v.2h-.2v.3h-.2v-.3h-.5v-.2h.5v-.7l-.5 .7z" fill-rule="evenodd"/>
<path d="M284 269.7a1.08 1.08 0 0 1 0 1.9 1.42 1.42 0 0 0 0-1.9z" fill-rule="evenodd"/>
<circle cx="267" cy="269.8" r=".1"/>
<circle cx="274" cy="269.8" r=".1"/>
</g>
<path d="M297.5 243h-34.5v21" fill="none" stroke="#000" stroke-width=".2"/>
<g fill="#00f">
<path d="M264.8 244.3l.7-.2 .4 .3-.2 .2a.53 .53 0 0 0-.8-.2 .53 .53 0 0 0 0 .8l.4 .3 .3-.1 .1-.3h.2a.74 .74 0 0 1-1.1 .4 .74 .74 0 0 1 0-1.2z" fill-rule="evenodd"/>
<path d="M266.3 244.6a.54 .54 0 0 1 .8 .1 .54 .54 0 0 1-.3 .8 .54 .54 0 0 1-.7-.4h.2a.37 .37 0 0 0 .5 .4 .37 .37 0 0 0 .1-.7l-.4-.1-.2 .4h-.2z" fill-rule="evenodd"/>
<path d="M267.3 244.5h.2v.2l.4-.2 .2 .2 .3-.2 .3 .1 .1 1h-.2l-.1-.9a.26 .26 0 0 0-.3 0 .26 .26 0 0 0 0 .3v.6h-.2l-.1-.8-.3-.1-.1 .9h-.2z" fill-rule="evenodd"/>
<path d="M269.1 244.5h.1v.2l.4-.2 .3 .2 .2-.2 .3 .1 .1 1h-.1l-.1-.9a.26 .26 0 0 0-.3 0 .26 .26 0 0 0-.1 .3v.6h-.2v-.8l-.3-.1-.1 .9h-.2z" fill-rule="evenodd"/>
<path d="M270.9 244.7l.1-.1a.51 .51 0 0 1 .5 0 .51 .51 0 0 1 .3 .5h-.9l.3 .4 .6-.2a.52 .52 0 0 1-.7 .3 .52 .52 0 0 1-.3-.6h.8l-.3-.3-.3 .3h-.2z" fill-rule="evenodd"/>
<path d="M272 244.5h.1v.2l.4-.2a.35 .35 0 0 1 .4 .5v.6h-.2v-.6a.27 .27 0 0 0-.3-.3 .27 .27 0 0 0-.2 .3v.6h-.2z" fill-rule="evenodd"/>
<path d="M273.2 244.3l.2-.1v.3h.2v.2h-.2v.6l.2 .3a.27 .27 0 0 1-.3 0 .27 .27 0 0 1-.1-.3v-.6h-.2z" fill-rule="evenodd"/>
<path d="M273.8 244.6l.5-.1 .2 .3h-.2a.21 .21 0 0 0-.2-.2 .21 .21 0 0 0-.1 .3 .43 .43 0 0 1 .4 .1 .43 .43 0 0 1 .1 .4l-.2 .2h-.4l-.2-.3h.1a.24 .24 0 0 0 .3 .3 .24 .24 0 0 0 .2-.4 .43 .43 0 0 1-.6-.5z" fill-rule="evenodd"/>
<path d="M274.8 244.5h.2v.2h-.2z" fill-rule="evenodd"/>
<path d="M274.8 245.4h.2v.2h-.2z" fill-rule="evenodd"/>
</g>
<g fill="#00007f">
<path d="M264.7 248.7h1l-.9 1.3h.7l.2-.3v.4h-1.2l.9-1.3h-.6l-.1 .3z" fill-rule="evenodd"/>
<path d="M266 248.8l.7-.1v.5a.29 .29 0 0 0-.3-.4 .29 .29 0 0 0-.2 .4h.1a.49 .49 0 0 1 .5 .3 .49 .49 0 0 1-.1 .6l-.8 .1 .1-.5a.33 .33 0 0 0 .3 .4 .33 .33 0 0 0 .2-.4v-.1a.51 .51 0 0 1-.5-.2 .51 .51 0 0 1 0-.6z" fill-rule="evenodd"/>
<path d="M267 248.7h.5l-.1 .1 .3 1 .2-.7-.3-.4h.6l-.2 .2 .3 .9 .3-.9-.1-.2h.4l-.6 1.5-.3-.9-.4 .9z" fill-rule="evenodd"/>
<path d="M269 249.2l.5 .1v.7l.2-.1-.1 .2-.7-.1-.1-.1 .4 .1 .2-.1v-.3l-.6 .3 .6-.4-.2-.3-.3 .3z" fill-rule="evenodd"/>
<path d="M270 248.9v.3h.3h-.3v.7h.3l-.3 .2-.1-.1v-.8h-.2z" fill-rule="evenodd"/>
<path d="M270.5 249.3l.4-.1 .2 .1-.1 .2a.28 .28 0 0 0-.4-.3 .28 .28 0 0 0-.1 .5l.3 .3 .3-.2a.43 .43 0 0 1-.6 .3 .43 .43 0 0 1-.1-.7z" fill-rule="evenodd"/>
<path d="M271.2 248.8l.3-.1v.7l.3-.2h.2l.1 .8 .1 .1h-.4l.1-.2v-.5l-.1-.1-.3 .1 .1 .6 .1 .1h-.5l.2-.1v-.9v-.3z" fill-rule="evenodd"/>
</g>
<path d="M263 243h-42v42M297.5 243h69" fill="none" stroke="#000" stroke-width=".2"/>
<g fill="#000">
<path d="M17.1 17.5a5.9 5.9 0 0 1 2.7 .1 1.87 1.87 0 0 1 .9 2.2 1.87 1.87 0 0 1-2 1.4h-1.6l.4-.2 .1-.4h.9v.2a.65 .65 0 0 0 .7 .2 .65 .65 0 0 0 .4-.6 2.07 2.07 0 0 0-.6-2.7h-.5v2.9h-.9v-2.8z" fill-rule="evenodd"/>
<path d="M21.7 18.8a1.29 1.29 0 0 1 1.9 1.1 1.29 1.29 0 0 1-1.9 1.1l-.4-.9h.7l.1 .6a.35 .35 0 0 0 .3 .3 .35 .35 0 0 0 .4-.3v-1.7a.37 .37 0 0 0-.5-.3 .37 .37 0 0 0-.2 .5l-.1 .9h-.7v-.7z" fill-rule="evenodd"/>
<path d="M26.5 17.5h1.1v2.4l.8-.9v-.2l-.3-.2h1.2l-1.1 .9 1.3 1.7h-1.3l.1-.3-.6-.9-.1 .1v.8l.2 .3h-1.3l.2-.2 .1-.4v-2.9z" fill-rule="evenodd"/>
<path d="M29.6 19.6h1.6v.6h-1.6z" fill-rule="evenodd"/>
<path d="M31.4 17.5h2l-.5 .2-.1 1.4h1.3v-1a.53 .53 0 0 0-.5-.6h2l-.5 .2-.1 .4v2.7l.6 .4h-2l.5-.3v-1.5h-1.3l.1 1.5 .5 .3h-2l.5-.2v-.5v-2.7z" fill-rule="evenodd"/>
<path d="M35.7 17.5h1.6l-.3 .2v.2l.8 2.1 .6-1.4a1.18 1.18 0 0 0-.7-1.1h1.8l-.4 .2 .8 2.2 .7-1.9v-.3l-.4-.2h1l-.3 .3-1.3 3.4-1.1-2.3-1.1 2.3-1.4-3.4z" fill-rule="evenodd"/>
<path d="M42.7 17.5h3.1v1h-.1a.94 .94 0 0 0-1.3-.8h-.3v1.5a.9 .9 0 0 0 1-.8v1.9a.95 .95 0 0 0-1-.9v1.5l.5 .3h-1.9l.4-.2 .1-.5v-2.7z" fill-rule="evenodd"/>
<path d="M46.4 18.9a1.05 1.05 0 0 1 1.2-.4 1.05 1.05 0 0 1 .7 1v1.2h.3a.52 .52 0 0 1-.5 .5 .52 .52 0 0 1-.5-.4 .75 .75 0 0 1-.7 .4 .75 .75 0 0 1-.7-.4l.1-.4h.7l.3 .3 .3-.1v-.9l-.5 .4-.1 .3h-.7l.4-.4 .9-.4v-.6a.33 .33 0 0 0-.5-.3 .33 .33 0 0 0-.1 .6 .39 .39 0 0 1-.6 .3 .39 .39 0 0 1 0-.7z" fill-rule="evenodd"/>
<path d="M48.9 17.5h1v1.4a1.05 1.05 0 0 1 1.4-.1 1.05 1.05 0 0 1 .3 1.3 1.17 1.17 0 0 1-.7 1 1.17 1.17 0 0 1-1.2-.1l-.5 .2v-2.1h.7l.1 1.6a.4 .4 0 0 0 .4 .4 .4 .4 0 0 0 .4-.4v-1.3a.46 .46 0 0 0-.3-.5 .46 .46 0 0 0-.6 .2h-.7v-1.3z" fill-rule="evenodd"/>
<path d="M52.1 18.6h1v.6a.68 .68 0 0 1 .4-.6 .68 .68 0 0 1 .8 .1 .4 .4 0 0 1-.2 .6 .4 .4 0 0 1-.6-.2l-.3 .3-.1 1.2a.46 .46 0 0 0 .4 .6h-1.4l.2-.2 .1-.4v-1.6z" fill-rule="evenodd"/>
<path d="M54.5 18.6h1l.1 2.3 .3 .3h-1.4l.2-.2 .1-.4v-1.7z" fill-rule="evenodd"/>
<path d="M58.9 18.9a1.05 1.05 0 0 1 1.1-.4 1.05 1.05 0 0 1 .8 1v1.2h.2a.52 .52 0 0 1-.5 .5 .52 .52 0 0 1-.5-.4 .75 .75 0 0 1-.6 .4 .75 .75 0 0 1-.7-.4v-.4h.7l.3 .3 .3-.1v-.9l-.5 .4-.1 .3h-.7l.4-.4 .9-.4v-.6a.33 .33 0 0 0-.5-.3 .33 .33 0 0 0 0 .6 .39 .39 0 0 1-.6 .3 .39 .39 0 0 1 0-.7z" fill-rule="evenodd"/>
<path d="M62.3 17.7l.1 .9h.6v.3h-.6v1.8l.2 .2 .3-.3a.68 .68 0 0 1-.8 .6 .68 .68 0 0 1-.5-.9v-1.4l-.3-.1z" fill-rule="evenodd"/>
<path d="M63.2 18.6h1.1v2.3l.3 .3h-1.4l.2-.2 .1-.4v-1.7z" fill-rule="evenodd"/>
<path d="M65.3 18.8a1.29 1.29 0 0 1 1.9 1.1 1.29 1.29 0 0 1-1.9 1.1l-.5-.9h.8l.1 .6a.35 .35 0 0 0 .3 .3 .35 .35 0 0 0 .4-.3v-1.7a.37 .37 0 0 0-.5-.3 .37 .37 0 0 0-.2 .5l-.1 .9h-.8l.1-.7z" fill-rule="evenodd"/>
<path d="M67.6 18.6h1.1v.4a.79 .79 0 0 1 1-.4 .79 .79 0 0 1 .4 1v1.3l.3 .3h-1.3l.2-.3v-1.7a.28 .28 0 0 0-.2-.3 .28 .28 0 0 0-.3 .2l-.1 .2v1.6l.2 .3h-1.3l.2-.2 .1-.4v-1.7z" fill-rule="evenodd"/>
<path d="M72 17.5a5.9 5.9 0 0 1 2.7 .1 1.87 1.87 0 0 1 1 2.2 1.87 1.87 0 0 1-2 1.4h-1.7l.4-.2 .1-.4h.9v.2a.65 .65 0 0 0 .7 .2 .65 .65 0 0 0 .5-.6 2.08 2.08 0 0 0-.7-2.7h-.5v2.9h-.9v-2.8z" fill-rule="evenodd"/>
<path d="M76.7 18.8a1.29 1.29 0 0 1 1.9 1.1 1.29 1.29 0 0 1-1.9 1.1l-.5-.9h.8v.6a.35 .35 0 0 0 .3 .3 .35 .35 0 0 0 .4-.3v-1.7a.37 .37 0 0 0-.5-.3 .37 .37 0 0 0-.2 .5v.9h-.8l.1-.7z" fill-rule="evenodd"/>
<path d="M81.4 18.6h1.1v2a.27 .27 0 0 0 .2 .3 .27 .27 0 0 0 .3-.2l.1-.2v-1.3v-.4l-.2-.2h1v2.3l.3 .3h-1.1v-.4a.79 .79 0 0 1-1 .4 .79 .79 0 0 1-.4-1v-1.3z" fill-rule="evenodd"/>
<path d="M84.6 18.6h1v.4a.79 .79 0 0 1 .8-.5 .79 .79 0 0 1 .7 .5 .82 .82 0 0 1 1-.4 .82 .82 0 0 1 .5 1v1.3l.3 .3h-1.3l.2-.3v-1.7a.31 .31 0 0 0-.2-.3 .31 .31 0 0 0-.4 .2l-.1 .1v1.7l.3 .3h-1.3l.2-.4v-1.6a.3 .3 0 0 0-.2-.3 .3 .3 0 0 0-.3 .2l-.2 .1v1.4l.1 .4 .2 .2h-1.3l.2-.2v-.4v-1.7z" fill-rule="evenodd"/>
<path d="M89.6 18.9a1.03 1.03 0 0 1 1.2-.3 1.03 1.03 0 0 1 .6 1.2h-1.4a.72 .72 0 0 0 .4 .9 .72 .72 0 0 0 .9-.3 .93 .93 0 0 1-1.2 .8 1.26 1.26 0 0 1-.8-1.7l1.4 .1v-.6l-.3-.3-.4 .3v.5h-.7z" fill-rule="evenodd"/>
<path d="M91.7 18.6h1v.4a.79 .79 0 0 1 1.1-.4 .79 .79 0 0 1 .4 1v1.3l.3 .3h-1.3l.2-.3v-1.7a.28 .28 0 0 0-.2-.3 .28 .28 0 0 0-.3 .2l-.2 .2 .1 1.6 .2 .3h-1.3l.2-.2 .1-.4v-1.7z" fill-rule="evenodd"/>
<path d="M95.7 17.7l.1 .9h.6v.3h-.6v1.8l.2 .2 .3-.3a.68 .68 0 0 1-.8 .6 .68 .68 0 0 1-.4-.9v-1.4l-.4-.1z" fill-rule="evenodd"/>
<path d="M24.5 18.8a.84 .84 0 0 1 1-.3 .84 .84 0 0 1 .5 .9 .46 .46 0 0 1-.5 0 .46 .46 0 0 1-.1-.5l-.3-.2a1.36 1.36 0 0 0 .5 2.1l.5-.3a1.02 1.02 0 0 1-1 .7 1.02 1.02 0 0 1-1-.8v-.7z" fill-rule="evenodd"/>
<path d="M56.6 18.8a.84 .84 0 0 1 1-.3 .84 .84 0 0 1 .5 .9 .46 .46 0 0 1-.5 0 .46 .46 0 0 1-.2-.5l-.2-.2a1.29 1.29 0 0 0 .5 2.1l.5-.3a.99 .99 0 0 1-.8 .7 .99 .99 0 0 1-1-.3 1.58 1.58 0 0 1 .2-2.1z" fill-rule="evenodd"/>
<path d="M79.4 18.8a.84 .84 0 0 1 1-.3 .84 .84 0 0 1 .6 .9 .46 .46 0 0 1-.6 0 .46 .46 0 0 1-.1-.5l-.3-.2a1.36 1.36 0 0 0 .5 2.1l.5-.3a.99 .99 0 0 1-.7 .7 .99 .99 0 0 1-1-.3 1.58 1.58 0 0 1 .1-2.1z" fill-rule="evenodd"/>
<path d="M177.6 64.7h1.3a1.5 1.5 0 0 1 1.7 1.5 1.5 1.5 0 0 1-1.7 1.5h-1.3l.3-.1 .1-.4h.7v.2a.58 .58 0 0 0 .7 .1 .58 .58 0 0 0 .3-.6 1.41 1.41 0 0 0-.7-2h-.3v2.3h-.7v-2.2z" fill-rule="evenodd"/>
<path d="M180.9 65.7h.9v.4a.49 .49 0 0 1 .4-.4 .49 .49 0 0 1 .5 .2 .36 .36 0 0 1-.3 .3 .36 .36 0 0 1-.4-.1l-.2 .4v.7v.3l.3 .2h-1.2l.3-.4v-1.3z" fill-rule="evenodd"/>
<path d="M182.9 65.7h.8l.1 1.8 .2 .2h-1.1l.2-.4v-1.4z" fill-rule="evenodd"/>
<path d="M184.1 64.7h.9v2.8l.2 .2h-1.1l.3-.4v-2.3z" fill-rule="evenodd"/>
<path d="M185.4 64.7h.8l.1 2.8 .2 .2h-1.1l.2-.4v-2.3z" fill-rule="evenodd"/>
<path d="M187.7 64.7h1.4a1.5 1.5 0 0 1 1.6 1.5 1.5 1.5 0 0 1-1.6 1.5h-1.4l.4-.1v-.4h.8v.2a.58 .58 0 0 0 .7 .1 .58 .58 0 0 0 .3-.6 1.41 1.41 0 0 0-.8-2h-.2v2.3h-.8v-2.2z" fill-rule="evenodd"/>
<path d="M191.1 65.7h.8v.4a.49 .49 0 0 1 .4-.4 .49 .49 0 0 1 .6 .2 .36 .36 0 0 1-.3 .3 .36 .36 0 0 1-.4-.1l-.2 .4-.1 .7 .1 .3 .2 .2h-1.1l.2-.4v-1.3z" fill-rule="evenodd"/>
<path d="M193.3 65.9a.85 .85 0 0 1 1-.3 .85 .85 0 0 1 .5 .8v1h.2a.42 .42 0 0 1-.4 .4 .42 .42 0 0 1-.4-.4 .56 .56 0 0 1-.5 .4 .56 .56 0 0 1-.6-.4l.1-.2h.5l.3 .2 .2-.1v-.7l-.5 .6h-.5l.3-.4 .7-.4v-.4a.27 .27 0 0 0-.4-.2 .27 .27 0 0 0 0 .4 .32 .32 0 0 1-.5 .2 .32 .32 0 0 1 0-.5z" fill-rule="evenodd"/>
<path d="M195.2 65.7h1.1l-.2 .2 .4 1 .2-.8-.2-.4h1l-.2 .2 .4 1 .3-1-.2-.2 .6 .1-.2 .1-.7 1.9h-.1l-.6-1.5-.5 1.5h-.1l-.7-1.8z" fill-rule="evenodd"/>
<path d="M198.5 65.7h.9v1.8l.3 .2h-1.2l.3-.4v-1.4z" fill-rule="evenodd"/>
<path d="M199.9 65.7h.8v.3a.64 .64 0 0 1 .8-.3 .64 .64 0 0 1 .4 .8v1l.2 .2h-1.1l.2-.2v-1.4a.23 .23 0 0 0-.2-.2 .23 .23 0 0 0-.2 .2l-.1 1.2 .2 .4h-1l.2-.4v-1.4z" fill-rule="evenodd"/>
<path d="M202.6 65.8l.5-.2 1.3 .1v.2h-.4a.79 .79 0 0 1 0 1 .79 .79 0 0 1-1 .2l-.1 .3a1.49 1.49 0 0 1 1.5 .5 .8 .8 0 0 1-1.1 .8 .67 .67 0 0 1-.9-.4h.4a.78 .78 0 0 0 1.2-.1l-.8-.2-.8 .3 .3-.3a.49 .49 0 0 1-.2-.6 .49 .49 0 0 1 .4-.3l-.4-.3-.1-.4h.6v.2a.29 .29 0 0 0 .3 .4 .29 .29 0 0 0 .3-.4v-.6a.26 .26 0 0 0-.3-.2 .26 .26 0 0 0-.3 .2v.4h-.6z" fill-rule="evenodd"/>
<path d="M205.7 64.7h1.6l-.5 .4v2.3a.94 .94 0 0 0 1 .1 .94 .94 0 0 0 .6-.8l-.1 1h-2.6l.3-.1 .1-.4v-2.2z" fill-rule="evenodd"/>
<path d="M208.9 65.2l1.2-.5v2.4a.46 .46 0 0 0 .4 .6h-1.6l.5-.2v-1.9l-.1-.4z" fill-rule="evenodd"/>
<path d="M212.1 66.5h1.3v.4h-1.3z" fill-rule="evenodd"/>
<path d="M214.7 64.7h1.6l-.4 .4v2.3a.94 .94 0 0 0 .9 .1 .94 .94 0 0 0 .6-.8v1h-2.7l.4-.1v-.4v-2.2z" fill-rule="evenodd"/>
<path d="M219.2 64.7h.2v1.9h.3v.5h-.3v.6h-.6v-.6h-1.1v-.5h1.1v-1.2l-.8 1.2h-.3z" fill-rule="evenodd"/>
<path d="M221.8 65.1l.7-.4a3.2 3.2 0 0 0-.2 3.7l.2 .2a2.2 2.2 0 0 1-.7-3.5z" fill-rule="evenodd"/>
<path d="M223 64.9a1.69 1.69 0 0 1 1.5 0l.1-.2 .1 1a.84 .84 0 0 0-.6-.7 .84 .84 0 0 0-.9 .1l.2 .4a2.28 2.28 0 0 1 1.5 1.4 1.2 1.2 0 0 1-1.9 .7l-.2 .2v-1.1a.98 .98 0 0 0 1.5 .7 .62 .62 0 0 0-.6-.8 .99 .99 0 0 1-.8-.6 .99 .99 0 0 1 .1-1.1z" fill-rule="evenodd"/>
<path d="M225.5 65.9a.68 .68 0 0 1 .9-.3 .68 .68 0 0 1 .4 .7 .41 .41 0 0 1-.5 0 .41 .41 0 0 1-.1-.5h-.1a.99 .99 0 0 0 .4 1.6l.4-.2a.89 .89 0 0 1-1.2 .5 .89 .89 0 0 1-.5-1.2z" fill-rule="evenodd"/>
<path d="M227.4 65.9a.85 .85 0 0 1 1-.3 .85 .85 0 0 1 .5 .8v1h.2a.42 .42 0 0 1-.4 .4 .42 .42 0 0 1-.4-.4 .56 .56 0 0 1-.5 .4 .56 .56 0 0 1-.6-.4l.1-.2h.5l.3 .2 .2-.1v-.7l-.5 .6h-.5l.3-.4 .7-.4v-.4a.27 .27 0 0 0-.4-.2 .27 .27 0 0 0 0 .4 .32 .32 0 0 1-.5 .2 .32 .32 0 0 1 0-.5z" fill-rule="evenodd"/>
<path d="M229.4 64.7h.9v2.8l.2 .2h-1.1l.2-.4v-2.3z" fill-rule="evenodd"/>
<path d="M231 65.9a.83 .83 0 0 1 1-.2 .83 .83 0 0 1 .4 .9h-1.1a.58 .58 0 0 0 .3 .8 .58 .58 0 0 0 .8-.3 .85 .85 0 0 1-1 .7 .85 .85 0 0 1-.7-1.1l.1-.3 1.1 .1-.2-.7a.39 .39 0 0 0-.4 .2 .39 .39 0 0 0 0 .4h-.5z" fill-rule="evenodd"/>
<path d="M234 65.2l1.1-.5v2.4a.46 .46 0 0 0 .5 .6h-1.6l.5-.2v-1.9l-.1-.4z" fill-rule="evenodd"/>
<path d="M237.7 65.2l1.2-.5v2.7l.1 .2 .4 .1h-1.6l.4-.2 .1-1.9-.1-.4z" fill-rule="evenodd"/>
<path d="M239.8 64.7a2.18 2.18 0 0 1 1.2 2 2.18 2.18 0 0 1-1.2 1.9 3.2 3.2 0 0 0 .1-3.7z" fill-rule="evenodd"/>
<circle cx="55.2" cy="17.8" r=".42"/>
<circle cx="63.9" cy="17.8" r=".42"/>
<circle cx="183.4" cy="65" r=".34"/>
<circle cx="199.1" cy="65" r=".34"/>
<circle cx="236.7" cy="67.4" r=".36"/>
<circle cx="236.7" cy="66" r=".36"/>
</g>
<g fill="#00007f">
<path d="M392.6 248.8l.3-.1v1.3h.2l-.6 .2-.4-.2v-.4h.2l.1 .4 .3-.1-.1-.7-.2 .1-.1 .3h-.2v-.1a.4 .4 0 0 1 .6-.3v-.4z" fill-rule="evenodd"/>
<path d="M393.3 248.8a.42 .42 0 0 1 .6 .1 .42 .42 0 0 1-.2 .6l-.4 .5 .7-.1-.1 .2h-.8a.87 .87 0 0 0 .6-1.2h-.3l-.3 .2z" fill-rule="evenodd"/>
<path d="M394.3 249.2l.5 .1 .1 .7 .1-.1-.1 .2-.7-.1v-.1l.3 .1 .2-.1v-.3l-.5 .3 .5-.4-.2-.3-.2 .3z" fill-rule="evenodd"/>
<path d="M395.3 248.9l.3-.2 .1 1.3 .1 .1h-.5l.2-.1v-.9v-.2z" fill-rule="evenodd"/>
<path d="M396.5 248.9l.5-.2-.4 .2-.2 .4a.43 .43 0 0 1 .6 .3 .43 .43 0 0 1-.4 .6 .43 .43 0 0 1-.4-.6h.2a.31 .31 0 0 0 .1 .4 .31 .31 0 0 0 .4 0 .31 .31 0 0 0-.1-.5l-.2-.2-.2 .1v.2h-.2z" fill-rule="evenodd"/>
<path d="M397.5 248.8l.3-.1 .2 .1v.1l-.3-.2-.1 .1v.4h.2h-.2v.8l.2 .1h-.6l.2-.1v-.8h-.2h.2z" fill-rule="evenodd"/>
<path d="M398.1 248.8a.61 .61 0 0 1 .7 .4 .61 .61 0 0 1-.3 .8l-.6 .1 .4-.2 .3-.4h-.5a.24 .24 0 0 1-.2-.2 .24 .24 0 0 1 .2-.2l.1 .3a.34 .34 0 0 0 .4-.2 .34 .34 0 0 0-.3-.4l-.2 .3h-.2z" fill-rule="evenodd"/>
</g>
<path d="M390.5 243v10.5" fill="none" stroke="#000" stroke-width=".2"/>
<g fill="#00f">
<path d="M392.3 244.3l.8-.2 .3 .3 .1 .1-.2 .1a.58 .58 0 0 0-.8-.2 .58 .58 0 0 0-.2 .8 .58 .58 0 0 0 .8 .2l.2-.1v-.3h-.4v-.1h.6v.5a.81 .81 0 0 1-1.2 .1 .81 .81 0 0 1 0-1.2z" fill-rule="evenodd"/>
<path d="M393.8 244.1h.2v.2h-.2z" fill-rule="evenodd"/>
<path d="M393.8 244.5h.2v1.1h-.2z" fill-rule="evenodd"/>
<path d="M394.3 244.3l.2-.1v.3h.1v.2h-.1v.6l.2 .3a.27 .27 0 0 1-.3 0 .27 .27 0 0 1-.1-.3v-.6h-.2z" fill-rule="evenodd"/>
<path d="M395.4 244.1h.2v.6h.8v-.6h.2v1.5h-.2v-.7h-.8v.7h-.2z" fill-rule="evenodd"/>
<path d="M397 244.6l.1-.1a.47 .47 0 0 1 .6 .1 .47 .47 0 0 1 .1 .6l.1 .4-.3-.1-.5 .1-.2-.1v-.2l.6 .2 .1-.4-.7 .2a.57 .57 0 0 1 .7-.4l-.2-.2-.5 .1z" fill-rule="evenodd"/>
<path d="M398.1 244.6l.6-.1 .2 .3h-.2a.21 .21 0 0 0-.3-.2 .21 .21 0 0 0-.1 .3 .43 .43 0 0 1 .5 .1 .43 .43 0 0 1 .1 .4l-.3 .2h-.3l-.3-.3h.2a.24 .24 0 0 0 .3 .3 .24 .24 0 0 0 .1-.4 .43 .43 0 0 1-.5-.5z" fill-rule="evenodd"/>
<path d="M399.1 244.1h.2v.6l.3-.2 .4 .1v1h-.2v-.7a.27 .27 0 0 0-.3-.2 .27 .27 0 0 0-.2 .3v.6h-.2z" fill-rule="evenodd"/>
<path d="M400.4 244.5h.2v.2h-.2z" fill-rule="evenodd"/>
<path d="M400.4 245.4h.2v.2h-.2z" fill-rule="evenodd"/>
</g>
<use href="#words"/>
</svg>
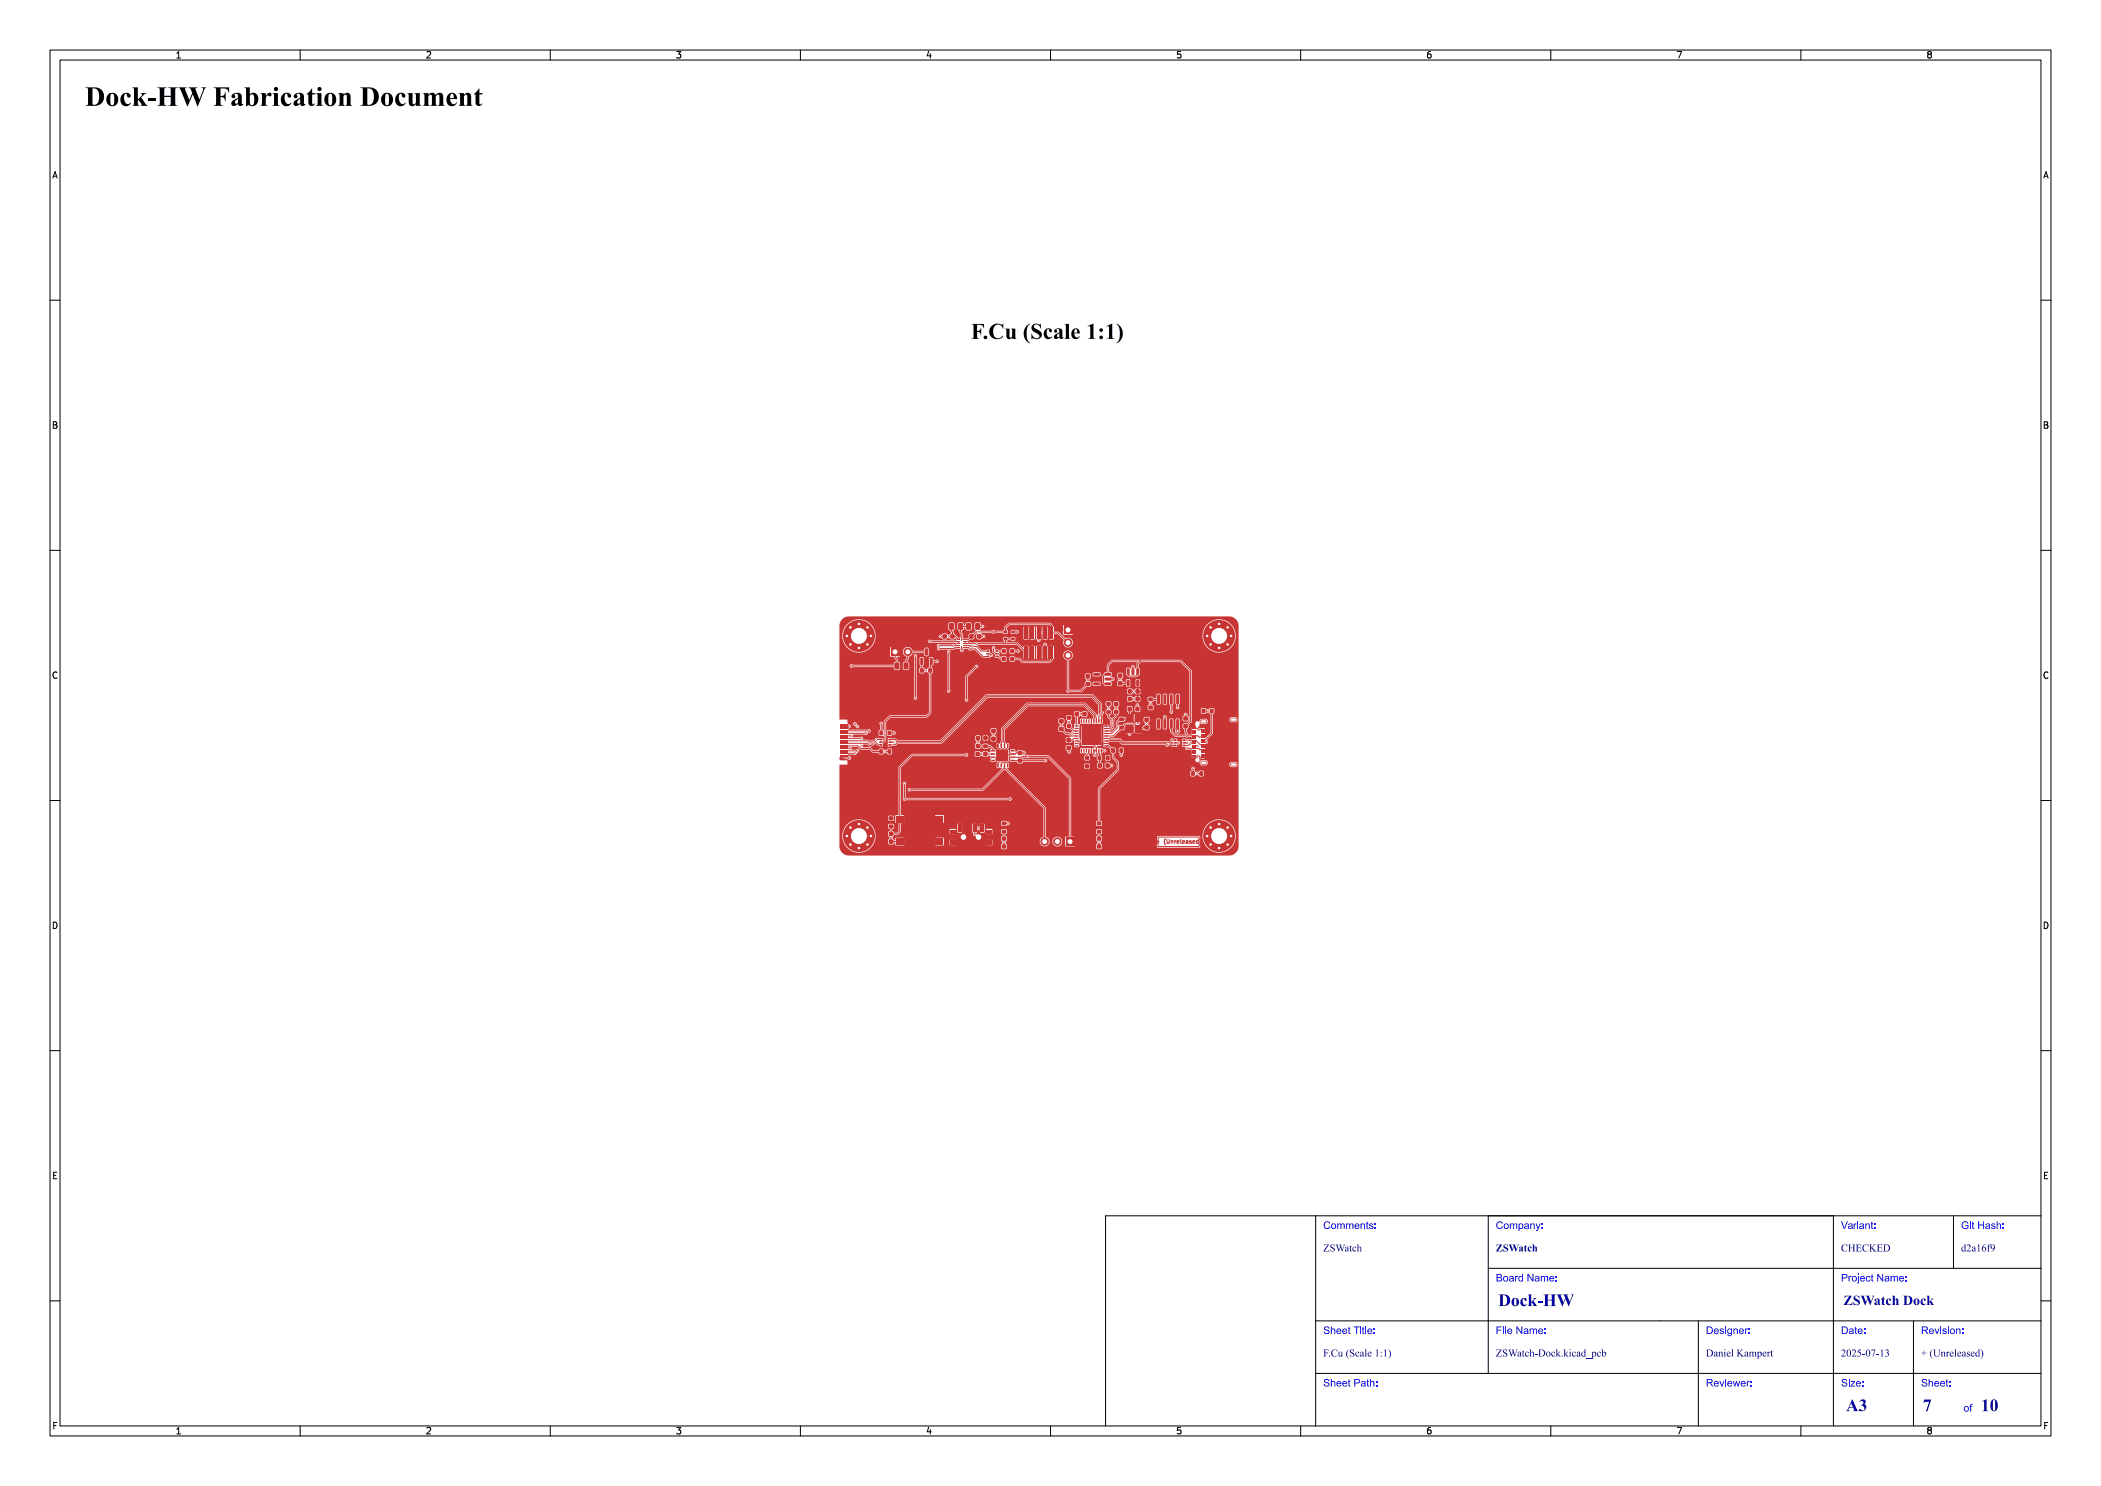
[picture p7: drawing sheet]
<svg xmlns="http://www.w3.org/2000/svg" width="420mm" height="297mm" viewBox="0 0 420 297" stroke-linecap="round" stroke-linejoin="round" font-family="sans-serif">
<defs><g id="words">
<text font-size="5.3" fill="#fff" x="17" y="21.5">Dock-HW Fabrication Document</text>
<text font-size="4.3" fill="#fff" x="188.6" y="68">F.Cu (Scale 1:1)</text>
<g font-size="3.3" fill="#fff">
<text x="299.5" y="261.2">Dock-HW</text>
<text x="369" y="282.2">A3</text>
<text x="384.4" y="282.3">7</text>
<text x="396" y="282.3">10</text>
</g>
<text font-size="2.7" fill="#fff" x="368.5" y="261">ZSWatch Dock</text>
<g font-size="2" fill="#fff">
<text x="264.5" y="245.8">Comments:</text>
<text x="299" y="245.8">Company:</text>
<text x="368" y="245.8">Variant:</text>
<text x="392" y="245.8">Git Hash:</text>
<text x="264.5" y="250.2">ZSWatch</text>
<text x="299" y="250.2">ZSWatch</text>
<text x="368" y="250.2">CHECKED</text>
<text x="392" y="250.2">d2a16f9</text>
<text x="299" y="256.2">Board Name:</text>
<text x="368" y="256.2">Project Name:</text>
<text x="264.5" y="266.8">Sheet Title:</text>
<text x="299" y="266.8">File Name:</text>
<text x="341" y="266.8">Designer:</text>
<text x="368" y="266.8">Date:</text>
<text x="384" y="266.8">Revision:</text>
<text x="264.5" y="271.2">F.Cu (Scale 1:1)</text>
<text x="299" y="271.2">ZSWatch-Dock.kicad_pcb</text>
<text x="341" y="271.2">Daniel Kampert</text>
<text x="368" y="271.2">2025-07-13</text>
<text x="384" y="271.2">+ (Unreleased)</text>
<text x="264.5" y="277.3">Sheet Path:</text>
<text x="341" y="277.2">Reviewer:</text>
<text x="368" y="277.3">Size:</text>
<text x="384" y="277.2">Sheet:</text>
<text x="392.5" y="282.3">of</text>
</g>
<g font-size="1.7" fill="#fff">
<text x="35" y="11.6">1</text>
<text x="85" y="11.6">2</text>
<text x="135" y="11.6">3</text>
<text x="185" y="11.6">4</text>
<text x="235" y="11.6">5</text>
<text x="285" y="11.6">6</text>
<text x="335" y="11.6">7</text>
<text x="385" y="11.6">8</text>
<text x="10.5" y="35.6">A</text>
<text x="408.5" y="35.6">A</text>
<text x="10.5" y="85.6">B</text>
<text x="408.5" y="85.6">B</text>
<text x="10.5" y="135.7">C</text>
<text x="408.5" y="135.7">C</text>
<text x="10.5" y="185.6">D</text>
<text x="408.5" y="185.6">D</text>
<text x="10.5" y="235.7">E</text>
<text x="408.5" y="235.7">E</text>
<text x="10.5" y="285.6">F</text>
<text x="35" y="286.7">1</text>
<text x="85" y="286.7">2</text>
<text x="135" y="286.7">3</text>
<text x="185" y="286.7">4</text>
<text x="235" y="286.7">5</text>
<text x="285" y="286.7">6</text>
<text x="335" y="286.7">7</text>
<text x="385" y="286.7">8</text>
<text x="408.5" y="285.6">F</text>
</g>
<text font-size="1.1" fill="#fff" x="231.1" y="168.6">+ (Unreleased)</text>
</g></defs>
<g fill="none" stroke="#c83434" stroke-width=".2">
<path d="M231.1 168.3h.7M231.4 168v.6M231.5 167.3h8.2v1.9h-8.2zM233 167.6l-.1 .1a.92 .92 0 0 0 .1 1.2M233.3 167.8v.6l.1 .2 .3-.2v-.6M234.1 168v.6M234.1 168.1h.3l.1 .5M234.8 168v.6M235.1 168l-.3 .2M235.3 168.3l.4-.1-.1-.1h-.3v.4h.3M236 167.8l.1 .8M236.4 168.3l.4-.1-.1-.1h-.3v.4h.3"/>
<path d="M237.1 168.1h.3l.1 .5M237.5 168.2l-.4 .2 .1 .2 .3-.1M237.8 168.2l.4 .2-.2 .2-.2-.1M237.8 168.1v.1M238.1 168.1h-.3M238.5 168.3l.3-.1v-.1h-.3v.4h.3M239.5 168.1l-.2-.1-.2 .2 .1 .3h.3M239.5 167.8v.8M239.8 167.6l.1 .1a.93 .93 0 0 1-.1 1.2"/>
</g>
<g fill="#c83434">
<path d="M202 151.9h.8v.2h-.8z" fill-rule="evenodd"/>
<path d="M202 151.2h.8v.3h-.8z" fill-rule="evenodd"/>
<path d="M202 150.6h.8v.2h-.8z" fill-rule="evenodd"/>
<path d="M202 149.9h.8v.3h-.8z" fill-rule="evenodd"/>
<path d="M201.3 148.7h.3v.8h-.3z" fill-rule="evenodd"/>
<path d="M200.7 148.7h.2v.8h-.2z" fill-rule="evenodd"/>
<path d="M200 148.7h.3v.8h-.3z" fill-rule="evenodd"/>
<path d="M199.4 148.7h.2v.8h-.2z" fill-rule="evenodd"/>
<path d="M198.1 149.9h.8v.3h-.8z" fill-rule="evenodd"/>
<path d="M198.1 150.6h.8v.2h-.8z" fill-rule="evenodd"/>
<path d="M198.1 151.2h.8v.3h-.8z" fill-rule="evenodd"/>
<path d="M198.1 151.9h.8v.2h-.8z" fill-rule="evenodd"/>
<path d="M199.4 152.6h.2v.8h-.2z" fill-rule="evenodd"/>
<path d="M200 152.6h.3v.8h-.3z" fill-rule="evenodd"/>
<path d="M200.7 152.6h.2v.8h-.2z" fill-rule="evenodd"/>
<path d="M201.3 152.6h.3v.8h-.3z" fill-rule="evenodd"/>
<path d="M199.4 150h2.1v2.1h-2.1z" fill-rule="evenodd"/>
<path d="M202.2 127.4h.6v.6h-.6z" fill-rule="evenodd"/>
<path d="M202.2 126h.6v.6h-.6z" fill-rule="evenodd"/>
<path d="M219.3 165.9h.8v.7h-.8z" fill-rule="evenodd"/>
<path d="M219.3 164.2h.8v.7h-.8z" fill-rule="evenodd"/>
<path d="M227.2 133.6l.5 .1-.1 1.2-.5-.1z" fill-rule="evenodd"/>
<path d="M226.2 133.6l.6 .1-.1 1.2-.5-.1z" fill-rule="evenodd"/>
<path d="M225.3 133.6l.5 .1-.1 1.2-.5-.1z" fill-rule="evenodd"/>
<path d="M225.3 135.9h.5l-.1 1.3-.5-.1z" fill-rule="evenodd"/>
<path d="M227.2 135.9h.5l-.1 1.3-.5-.1z" fill-rule="evenodd"/>
<path d="M203.5 151.6h.8v.8h-.8z" fill-rule="evenodd"/>
<path d="M203.5 150.1h.8v.8h-.8z" fill-rule="evenodd"/>
<path d="M219.5 152.6h.7v.8h-.7z" fill-rule="evenodd"/>
<path d="M221 152.6h.8v.8h-.8z" fill-rule="evenodd"/>
<path d="M241.9 141.7h.7v.8h-.7z" fill-rule="evenodd"/>
<path d="M240.2 141.7h.7v.8h-.7z" fill-rule="evenodd"/>
<path d="M238.4 150.9h.7v.3h-.7z" fill-rule="evenodd"/>
<path d="M238.4 150.4h.7v.3h-.7z" fill-rule="evenodd"/>
<path d="M238.4 149.9h.7v.3h-.7z" fill-rule="evenodd"/>
<path d="M238.4 149.4h.7v.3h-.7z" fill-rule="evenodd"/>
<path d="M238.4 148.9h.7v.3h-.7z" fill-rule="evenodd"/>
<path d="M238.4 148.4h.7v.3h-.7z" fill-rule="evenodd"/>
<path d="M238.4 147.9h.7v.3h-.7z" fill-rule="evenodd"/>
<path d="M238.4 147.4h.7v.3h-.7z" fill-rule="evenodd"/>
<path d="M238.4 146.9h.7v.3h-.7z" fill-rule="evenodd"/>
<path d="M238.4 146.4h.7v.3h-.7z" fill-rule="evenodd"/>
<path d="M238.4 145.9h.7v.3h-.7z" fill-rule="evenodd"/>
<path d="M238.4 145.4h.7v.3h-.7z" fill-rule="evenodd"/>
<path d="M240.1 145.7h.7v.3h-.7z" fill-rule="evenodd"/>
<path d="M240.1 146.2h.7v.3h-.7z" fill-rule="evenodd"/>
<path d="M240.1 146.7h.7v.3h-.7z" fill-rule="evenodd"/>
<path d="M240.1 147.2h.7v.3h-.7z" fill-rule="evenodd"/>
<path d="M240.1 147.7h.7v.3h-.7z" fill-rule="evenodd"/>
<path d="M240.1 148.2h.7v.3h-.7z" fill-rule="evenodd"/>
<path d="M240.1 148.7h.7v.3h-.7z" fill-rule="evenodd"/>
<path d="M240.1 149.2h.7v.3h-.7z" fill-rule="evenodd"/>
<path d="M240.1 149.7h.7v.3h-.7z" fill-rule="evenodd"/>
<path d="M240.1 150.2h.7v.3h-.7z" fill-rule="evenodd"/>
<path d="M240.1 150.7h.7v.3h-.7z" fill-rule="evenodd"/>
<path d="M240.1 151.2h.7v.3h-.7z" fill-rule="evenodd"/>
</g>
<g fill="#c83434">
<circle cx="241.3" cy="167.1" r=".4"/>
<circle cx="242" cy="165.4" r=".4"/>
<circle cx="242" cy="168.8" r=".4"/>
<circle cx="243.7" cy="164.7" r=".4"/>
<circle cx="243.7" cy="167.1" r="3.2"/>
<circle cx="243.7" cy="169.5" r=".4"/>
<circle cx="245.4" cy="165.4" r=".4"/>
<circle cx="245.4" cy="168.8" r=".4"/>
<circle cx="246.1" cy="167.1" r=".4"/>
</g>
<path d="M240.3 152.4h.6M240.3 144.2h.6M246.3 152.8h.6M246.3 143.8h.6" fill="none" stroke="#c83434" stroke-width=".8"/>
<g fill="#c83434">
<path d="M239.8 154.2h.7v.8h-.7z" fill-rule="evenodd"/>
<path d="M238.1 154.2h.7v.8h-.7z" fill-rule="evenodd"/>
<path d="M200.3 165.9h.8v.7h-.8z" fill-rule="evenodd"/>
<path d="M200.3 164.2h.8v.7h-.8z" fill-rule="evenodd"/>
<path d="M216.9 152.8h.8v.7h-.8z" fill-rule="evenodd"/>
<path d="M216.9 151.1h.8v.7h-.8z" fill-rule="evenodd"/>
<path d="M178.1 129.4h1.7v1.7h-1.7z" fill-rule="evenodd"/>
<path d="M222.7 141.9h.8v.8h-.8z" fill-rule="evenodd"/>
<path d="M222.7 140.3h.8v.8h-.8z" fill-rule="evenodd"/>
<path d="M180.7 132.5l.7-.1 .2 .2v.9l-.1 .3h-.7l-.2-.2z" fill-rule="evenodd"/>
<path d="M178.8 132.5l.8-.1 .2 .2v.9l-.2 .3h-.6l-.2-.2z" fill-rule="evenodd"/>
<path d="M177.5 149.8h.6v.8h-.6z" fill-rule="evenodd"/>
<path d="M175.8 149.8h.7v.8h-.7z" fill-rule="evenodd"/>
<path d="M193.2 124.6l.7-.1 .2 .2v.9l-.1 .3h-.7l-.2-.2z" fill-rule="evenodd"/>
<path d="M195 124.6l.7-.1 .2 .2v.9l-.1 .3h-.6l-.3-.2z" fill-rule="evenodd"/>
<path d="M235.1 138.8l.6 .1-.1 1.8-.5-.1z" fill-rule="evenodd"/>
<path d="M233.9 138.8l.5 .1-.1 1.8-.5-.1z" fill-rule="evenodd"/>
<path d="M232.6 138.8l.6 .1-.1 1.8-.5-.1z" fill-rule="evenodd"/>
<path d="M231.3 138.8l.6 .1-.1 1.8-.5-.1z" fill-rule="evenodd"/>
<path d="M231.3 143.8h.6l-.1 1.9-.5-.1z" fill-rule="evenodd"/>
<path d="M232.6 143.8h.6l-.1 1.9-.5-.1z" fill-rule="evenodd"/>
<path d="M233.9 143.8h.5l-.1 1.9-.5-.1z" fill-rule="evenodd"/>
<path d="M235.1 143.8h.6l-.1 1.9-.5-.1z" fill-rule="evenodd"/>
<path d="M223.5 136.2h.8v.8h-.8z" fill-rule="evenodd"/>
<path d="M223.5 134.6h.8v.8h-.8z" fill-rule="evenodd"/>
<path d="M213.1 167.4h1.6v1.6h-1.6z" fill-rule="evenodd"/>
<path d="M183.9 133.6h.7v.8h-.7z" fill-rule="evenodd"/>
<path d="M185.6 133.6h.7v.8h-.7z" fill-rule="evenodd"/>
<path d="M179.1 163h1.5v1.4h-1.5z" fill-rule="evenodd"/>
<path d="M179.1 167.6h1.5v1.2h-1.5z" fill-rule="evenodd"/>
<path d="M187 163h1.6v1.4h-1.6z" fill-rule="evenodd"/>
<path d="M187 167.6h1.6v1.2h-1.6z" fill-rule="evenodd"/>
<path d="M200.3 129.7h.7v.8h-.7z" fill-rule="evenodd"/>
<path d="M202 129.7h.7v.8h-.7z" fill-rule="evenodd"/>
<path d="M213.2 147.5h.8v.8h-.8z" fill-rule="evenodd"/>
<path d="M213.2 149.1h.8v.8h-.8z" fill-rule="evenodd"/>
<path d="M200.7 126h.6v.6h-.6z" fill-rule="evenodd"/>
<path d="M200.7 127.4h.6v.6h-.6z" fill-rule="evenodd"/>
<path d="M229.6 139.4h.8v.7h-.8z" fill-rule="evenodd"/>
<path d="M229.6 141.1h.8v.7h-.8z" fill-rule="evenodd"/>
<path d="M177.6 148.7h.4l.1 .3-.5 .1z" fill-rule="evenodd"/>
<path d="M177.6 148.2h.6v.2l-.6 .1z" fill-rule="evenodd"/>
<path d="M177.6 147.6h.4l.1 .3-.5 .1z" fill-rule="evenodd"/>
<path d="M175.9 147.6h.5v.4h-.5z" fill-rule="evenodd"/>
<path d="M175.8 148.2h.5l.1 .2-.6 .1z" fill-rule="evenodd"/>
<path d="M175.9 148.7h.5v.3h-.5z" fill-rule="evenodd"/>
<path d="M184 131.5h.5v1.4l-.5-.1z" fill-rule="evenodd"/>
<path d="M185.9 131.5h.5v1.4l-.5-.1z" fill-rule="evenodd"/>
<path d="M184.9 129.6l.6 .1-.1 1.3-.5-.1z" fill-rule="evenodd"/>
<path d="M211.8 145.3h.8v.8h-.8z" fill-rule="evenodd"/>
<path d="M211.8 143.8h.8v.7h-.8z" fill-rule="evenodd"/>
<path d="M197.3 130l.4-.1 .1 .4h-.4z" fill-rule="evenodd"/>
<path d="M197.2 130.5h.6v.3h-.6z" fill-rule="evenodd"/>
<path d="M197.3 131h.4l.1 .3-.4 .1z" fill-rule="evenodd"/>
<path d="M199 131h.4l.1 .3-.4 .1z" fill-rule="evenodd"/>
<path d="M199 130.5h.6v.3h-.6z" fill-rule="evenodd"/>
<path d="M199 130l.4-.1 .1 .4h-.4z" fill-rule="evenodd"/>
<path d="M196.6 147.2h.8v.6h-.8z" fill-rule="evenodd"/>
<path d="M196.6 148.8h.8v.7h-.8z" fill-rule="evenodd"/>
<path d="M213.3 143.1h.8v.7h-.8z" fill-rule="evenodd"/>
<path d="M213.3 144.8h.8v.7h-.8z" fill-rule="evenodd"/>
<path d="M190 126.8h.8v.8h-.8z" fill-rule="evenodd"/>
<path d="M188.5 126.8h.7v.8h-.7z" fill-rule="evenodd"/>
<path d="M234.7 147.8l.4-.1 .1 .4h-.4z" fill-rule="evenodd"/>
<path d="M234.6 148.3h.6v.3h-.6z" fill-rule="evenodd"/>
<path d="M234.7 148.8h.4l.1 .3-.4 .1z" fill-rule="evenodd"/>
<path d="M236.4 148.8h.4l.1 .3-.4 .1z" fill-rule="evenodd"/>
<path d="M236.4 148.3h.6v.3h-.6z" fill-rule="evenodd"/>
<path d="M236.4 147.8l.4-.1 .1 .4h-.4z" fill-rule="evenodd"/>
<path d="M177.7 163.2h.8v.7h-.8z" fill-rule="evenodd"/>
<path d="M177.7 164.8h.8v.7h-.8z" fill-rule="evenodd"/>
<path d="M225.2 142.8h1.2v1.4h-1.2z" fill-rule="evenodd"/>
<path d="M225.2 145h1.2v1.4h-1.2z" fill-rule="evenodd"/>
<path d="M226.9 145h1.2v1.4h-1.2z" fill-rule="evenodd"/>
<path d="M226.9 142.8h1.2v1.4h-1.2z" fill-rule="evenodd"/>
<path d="M236.6 144.8h.8v.7h-.8z" fill-rule="evenodd"/>
<path d="M236.6 143.2h.8v.8h-.8z" fill-rule="evenodd"/>
<path d="M177.7 166.3h.8v.8h-.8z" fill-rule="evenodd"/>
<path d="M177.7 167.8h.8v.8h-.8z" fill-rule="evenodd"/>
<path d="M220.1 143.8h.2l-.1 .8-.2-.1z" fill-rule="evenodd"/>
<path d="M219.6 143.8h.2l-.1 .8-.2-.1z" fill-rule="evenodd"/>
<path d="M219.1 143.8h.2l-.1 .8-.2-.1z" fill-rule="evenodd"/>
<path d="M218.6 143.8h.2l-.1 .8-.2-.1z" fill-rule="evenodd"/>
<path d="M218.1 143.8h.2l-.1 .8-.2-.1z" fill-rule="evenodd"/>
<path d="M217.6 143.8h.2l-.1 .8-.2-.1z" fill-rule="evenodd"/>
<path d="M217.1 143.8h.2l-.1 .8-.2-.1z" fill-rule="evenodd"/>
<path d="M216.6 143.8h.2l-.1 .8-.2-.1z" fill-rule="evenodd"/>
<path d="M216.1 143.8h.2l-.1 .8-.2-.1z" fill-rule="evenodd"/>
<path d="M214.8 145h.8v.2h-.7z" fill-rule="evenodd"/>
<path d="M214.8 145.5h.8v.2h-.7z" fill-rule="evenodd"/>
<path d="M214.8 146h.8v.2h-.7z" fill-rule="evenodd"/>
<path d="M214.8 146.5h.8v.2h-.7z" fill-rule="evenodd"/>
<path d="M214.8 147h.8v.2h-.7z" fill-rule="evenodd"/>
<path d="M214.8 147.5h.8v.2h-.7z" fill-rule="evenodd"/>
<path d="M214.8 148h.8v.2h-.7z" fill-rule="evenodd"/>
<path d="M214.8 148.5h.8v.2h-.7z" fill-rule="evenodd"/>
<path d="M214.8 149h.8v.2h-.7z" fill-rule="evenodd"/>
<path d="M216.1 149.6l.2 .1-.1 .8-.2-.1z" fill-rule="evenodd"/>
<path d="M216.6 149.6l.2 .1-.1 .8-.2-.1z" fill-rule="evenodd"/>
<path d="M217.1 149.6l.2 .1-.1 .8-.2-.1z" fill-rule="evenodd"/>
<path d="M217.6 149.6l.2 .1-.1 .8-.2-.1z" fill-rule="evenodd"/>
<path d="M218.1 149.6l.2 .1-.1 .8-.2-.1z" fill-rule="evenodd"/>
<path d="M218.6 149.6l.2 .1-.1 .8-.2-.1z" fill-rule="evenodd"/>
<path d="M219.1 149.6l.2 .1-.1 .8-.2-.1z" fill-rule="evenodd"/>
<path d="M219.6 149.6l.2 .1-.1 .8-.2-.1z" fill-rule="evenodd"/>
<path d="M220.1 149.6l.2 .1-.1 .8-.2-.1z" fill-rule="evenodd"/>
<path d="M220.7 149h.8v.2h-.8z" fill-rule="evenodd"/>
<path d="M220.7 148.5h.8v.2h-.8z" fill-rule="evenodd"/>
<path d="M220.7 148h.8v.2h-.8z" fill-rule="evenodd"/>
<path d="M220.7 147.5h.8v.2h-.8z" fill-rule="evenodd"/>
<path d="M220.7 147h.8v.2h-.8z" fill-rule="evenodd"/>
<path d="M220.7 146.5h.8v.2h-.8z" fill-rule="evenodd"/>
<path d="M220.7 146h.8v.2h-.8z" fill-rule="evenodd"/>
<path d="M220.7 145.5h.8v.2h-.8z" fill-rule="evenodd"/>
<path d="M220.7 145h.8v.2h-.8z" fill-rule="evenodd"/>
<path d="M216.3 145.2h3.7v3.7h-3.7z" fill-rule="evenodd"/>
<path d="M227 137.8h.8v.8h-.8z" fill-rule="evenodd"/>
<path d="M225.5 137.8h.7v.8h-.7z" fill-rule="evenodd"/>
<path d="M200.3 168.8h.8v.8h-.8z" fill-rule="evenodd"/>
<path d="M200.3 167.2h.8v.8h-.8z" fill-rule="evenodd"/>
<path d="M190 165.8h1v.8h-1z" fill-rule="evenodd"/>
<path d="M190 168h1v.8h-1z" fill-rule="evenodd"/>
<path d="M197.2 165.8h1.1v.8h-1.1z" fill-rule="evenodd"/>
<path d="M197.2 168h1.1v.8h-1.1z" fill-rule="evenodd"/>
<path d="M191.5 164.8h.7v1.5h-.7z" fill-rule="evenodd"/>
<path d="M194.5 164.8h.7v1.5h-.7z" fill-rule="evenodd"/>
<path d="M196 164.8h.7v1.5h-.7z" fill-rule="evenodd"/>
<path d="M222.2 149.6h.6v.8h-.6z" fill-rule="evenodd"/>
<path d="M223.8 149.6h.7v.8h-.7z" fill-rule="evenodd"/>
<path d="M227 139.3h.8v.8h-.8z" fill-rule="evenodd"/>
<path d="M225.5 139.3h.7v.8h-.7z" fill-rule="evenodd"/>
<path d="M167.9 150.9h1.5v.3h-1.5z" fill-rule="evenodd"/>
<path d="M167.9 150.4h1.5v.3h-1.5z" fill-rule="evenodd"/>
<path d="M167.9 149.9h1.5v.3h-1.5z" fill-rule="evenodd"/>
<path d="M167.9 149.4h1.5v.3h-1.5z" fill-rule="evenodd"/>
<path d="M167.9 148.9h1.5v.3h-1.5z" fill-rule="evenodd"/>
<path d="M167.9 148.4h1.5v.3h-1.5z" fill-rule="evenodd"/>
<path d="M167.9 147.9h1.5v.3h-1.5z" fill-rule="evenodd"/>
<path d="M167.9 147.4h1.5v.3h-1.5z" fill-rule="evenodd"/>
<path d="M167.9 146.9h1.5v.3h-1.5z" fill-rule="evenodd"/>
<path d="M167.9 146.4h1.5v.3h-1.5z" fill-rule="evenodd"/>
<path d="M167.9 145.9h1.5v.3h-1.5z" fill-rule="evenodd"/>
<path d="M167.9 145.4h1.5v.3h-1.5z" fill-rule="evenodd"/>
<path d="M167.9 144.7h1.5v.5h-1.5z" fill-rule="evenodd"/>
<path d="M214.9 142.3h.7v.8h-.7z" fill-rule="evenodd"/>
<path d="M216.4 142.3h.8v.8h-.8z" fill-rule="evenodd"/>
<path d="M228.8 143.5h.8v.7h-.8z" fill-rule="evenodd"/>
<path d="M228.8 145h.8v.8h-.8z" fill-rule="evenodd"/>
<path d="M209.8 125.3h.8v2.4h-.8z" fill-rule="evenodd"/>
<path d="M209.8 129.2h.8v2.4h-.8z" fill-rule="evenodd"/>
<path d="M208.5 125.3h.8v2.4h-.8z" fill-rule="evenodd"/>
<path d="M208.5 129.2h.8v2.4h-.8z" fill-rule="evenodd"/>
<path d="M207.3 125.3h.7v2.4h-.7z" fill-rule="evenodd"/>
<path d="M207.3 129.2h.7v2.4h-.7z" fill-rule="evenodd"/>
<path d="M206 125.3h.7v2.4h-.7z" fill-rule="evenodd"/>
<path d="M206 129.2h.7v2.4h-.7z" fill-rule="evenodd"/>
<path d="M204.7 125.3h.8v2.4h-.8z" fill-rule="evenodd"/>
<path d="M204.7 129.2h.8v2.4h-.8z" fill-rule="evenodd"/>
<path d="M221.1 151.1h.7v.8h-.7z" fill-rule="evenodd"/>
<path d="M219.4 151.1h.7v.8h-.7z" fill-rule="evenodd"/>
<path d="M212.7 125.1h1.6v1.7h-1.6z" fill-rule="evenodd"/>
<path d="M189.8 124.6l.7-.1 .2 .2v.9l-.1 .3h-.7l-.2-.2z" fill-rule="evenodd"/>
<path d="M191.6 124.6l.7-.1 .2 .2v.9l-.1 .3h-.6l-.3-.2z" fill-rule="evenodd"/>
<path d="M191.3 127.7h.6v.2h-.6z" fill-rule="evenodd"/>
<path d="M191.8 127.5h.1v.3h-.1z" fill-rule="evenodd"/>
<path d="M191.3 128.1h.6v.2h-.6z" fill-rule="evenodd"/>
<path d="M191.3 128.5h.6v.2h-.6z" fill-rule="evenodd"/>
<path d="M191.3 128.9h.6v.2h-.6z" fill-rule="evenodd"/>
<path d="M191.3 129.3h.6v.2h-.6z" fill-rule="evenodd"/>
<path d="M192.2 129.1h.2v.6h-.2z" fill-rule="evenodd"/>
<path d="M192.6 129.3h.6v.2h-.6z" fill-rule="evenodd"/>
<path d="M192.6 128.9h.6v.2h-.6z" fill-rule="evenodd"/>
<path d="M192.6 128.5h.6v.2h-.6z" fill-rule="evenodd"/>
<path d="M192.6 128.1h.6v.2h-.6z" fill-rule="evenodd"/>
<path d="M192.6 127.7h.6v.2h-.6z" fill-rule="evenodd"/>
<path d="M192.2 127.5h.2v.6h-.2z" fill-rule="evenodd"/>
<path d="M219.3 168.8h.8v.8h-.8z" fill-rule="evenodd"/>
<path d="M219.3 167.2h.8v.8h-.8z" fill-rule="evenodd"/>
<path d="M223.8 143.4h.8v.7h-.8z" fill-rule="evenodd"/>
<path d="M223.8 145.1h.8v.7h-.8z" fill-rule="evenodd"/>
<path d="M175.8 146.1h.7v.8h-.7z" fill-rule="evenodd"/>
<path d="M177.5 146.1h.6v.8h-.6z" fill-rule="evenodd"/>
<path d="M193.8 126.8h.8v.8h-.8z" fill-rule="evenodd"/>
<path d="M195.4 126.8h.7v.8h-.7z" fill-rule="evenodd"/>
<path d="M195.1 148.7h.8v.8h-.8z" fill-rule="evenodd"/>
<path d="M195.1 147.2h.8v.7h-.8z" fill-rule="evenodd"/>
<path d="M221.2 142h.8v.7h-.8z" fill-rule="evenodd"/>
<path d="M221.2 140.3h.8v.7h-.8z" fill-rule="evenodd"/>
<path d="M196.6 150.3h.8v.8h-.8z" fill-rule="evenodd"/>
<path d="M195 150.3h.8v.8h-.8z" fill-rule="evenodd"/>
<path d="M200.3 131.3h.7v.8h-.7z" fill-rule="evenodd"/>
<path d="M202 131.3h.7v.8h-.7z" fill-rule="evenodd"/>
<path d="M198.2 147.3h.8v.7h-.8z" fill-rule="evenodd"/>
<path d="M198.2 145.7h.8v.8h-.8z" fill-rule="evenodd"/>
<path d="M227 141.3h.8v.8h-.8z" fill-rule="evenodd"/>
<path d="M225.4 141.3h.8v.8h-.8z" fill-rule="evenodd"/>
<path d="M217 136.3h.9v.8h-.9z" fill-rule="evenodd"/>
<path d="M217 134.8h.9v.8h-.9z" fill-rule="evenodd"/>
<path d="M220.9 136.4h1.2v.5l-1.2 .1z" fill-rule="evenodd"/>
<path d="M220.9 135.5l1.2-.1v.5l-1.2 .1z" fill-rule="evenodd"/>
<path d="M220.9 134.5h1.2v.5l-1.2 .1z" fill-rule="evenodd"/>
<path d="M218.6 134.5h1.2l.1 .5-1.3 .1z" fill-rule="evenodd"/>
<path d="M218.6 136.4h1.2l.1 .5-1.3 .1z" fill-rule="evenodd"/>
</g>
<g fill="#c83434">
<circle cx="181.5" cy="130.3" r=".85"/>
<circle cx="211.4" cy="168.2" r=".85"/>
<circle cx="208.8" cy="168.2" r=".85"/>
<circle cx="241.3" cy="127.1" r=".4"/>
<circle cx="242" cy="125.4" r=".4"/>
<circle cx="242" cy="128.8" r=".4"/>
<circle cx="243.7" cy="124.7" r=".4"/>
<circle cx="243.7" cy="127.1" r="3.2"/>
<circle cx="243.7" cy="129.5" r=".4"/>
<circle cx="245.4" cy="125.4" r=".4"/>
<circle cx="245.4" cy="128.8" r=".4"/>
<circle cx="246.1" cy="127.1" r=".4"/>
<circle cx="169.3" cy="167.1" r=".4"/>
<circle cx="170" cy="165.4" r=".4"/>
<circle cx="170" cy="168.8" r=".4"/>
<circle cx="171.7" cy="164.7" r=".4"/>
<circle cx="171.7" cy="167.1" r="3.2"/>
<circle cx="171.7" cy="169.5" r=".4"/>
<circle cx="173.4" cy="165.4" r=".4"/>
<circle cx="173.4" cy="168.8" r=".4"/>
<circle cx="174.1" cy="167.1" r=".4"/>
<circle cx="213.5" cy="128.4" r=".85"/>
<circle cx="213.5" cy="131" r=".85"/>
<circle cx="169.3" cy="127.1" r=".4"/>
<circle cx="170" cy="125.4" r=".4"/>
<circle cx="170" cy="128.8" r=".4"/>
<circle cx="171.7" cy="124.7" r=".4"/>
<circle cx="171.7" cy="127.1" r="3.2"/>
<circle cx="171.7" cy="129.5" r=".4"/>
<circle cx="173.4" cy="125.4" r=".4"/>
<circle cx="173.4" cy="128.8" r=".4"/>
<circle cx="174.1" cy="127.1" r=".4"/>
<circle cx="227.4" cy="140.9" r=".22"/>
<circle cx="237" cy="142.8" r=".23"/>
<circle cx="232.9" cy="143.3" r=".23"/>
<circle cx="235.6" cy="148.5" r=".23"/>
<circle cx="196.6" cy="127.2" r=".22"/>
<circle cx="222.2" cy="153" r=".23"/>
<circle cx="178.7" cy="146.5" r=".23"/>
<circle cx="198.6" cy="146.9" r=".22"/>
<circle cx="207.6" cy="128" r=".23"/>
<circle cx="223.9" cy="135.8" r=".23"/>
<circle cx="178.1" cy="167.5" r=".22"/>
<circle cx="225.8" cy="146.7" r=".22"/>
<circle cx="196.2" cy="150.7" r=".23"/>
<circle cx="218.8" cy="150.9" r=".23"/>
<circle cx="196.4" cy="125.2" r=".22"/>
<circle cx="223.1" cy="141.5" r=".22"/>
<circle cx="198.2" cy="131" r=".23"/>
<circle cx="230" cy="140.7" r=".22"/>
<circle cx="217.4" cy="135.9" r=".22"/>
<circle cx="203.3" cy="126.3" r=".22"/>
<circle cx="222.4" cy="135.7" r=".22"/>
<circle cx="226.6" cy="139.7" r=".23"/>
<circle cx="212.2" cy="144.9" r=".22"/>
<circle cx="226.6" cy="138.2" r=".23"/>
<circle cx="192.3" cy="130" r=".22"/>
<circle cx="229.2" cy="144.6" r=".23"/>
<circle cx="216.1" cy="142.7" r=".22"/>
<circle cx="213.7" cy="150.3" r=".23"/>
<circle cx="169.8" cy="145.1" r=".23"/>
<circle cx="224.1" cy="150.9" r=".23"/>
<circle cx="239.5" cy="145.8" r=".23"/>
<circle cx="204.7" cy="150.5" r=".23"/>
<circle cx="221.6" cy="141.5" r=".22"/>
<circle cx="188" cy="127.2" r=".22"/>
<circle cx="219.7" cy="168.4" r=".22"/>
<circle cx="241.4" cy="142.1" r=".23"/>
<circle cx="169.8" cy="151.5" r=".22"/>
<circle cx="226.5" cy="133.3" r=".22"/>
<circle cx="177" cy="150.2" r=".23"/>
<circle cx="178.6" cy="148.3" r=".22"/>
<circle cx="239.3" cy="154.6" r=".22"/>
<circle cx="227.5" cy="144.5" r=".23"/>
<circle cx="195.5" cy="148.2" r=".23"/>
<circle cx="239.6" cy="151.1" r=".22"/>
<circle cx="194.9" cy="166.7" r=".23"/>
<circle cx="189.6" cy="138.1" r=".22"/>
<circle cx="189.6" cy="130.3" r=".22"/>
<circle cx="189.6" cy="127.2" r=".22"/>
<circle cx="213.5" cy="138.1" r=".23"/>
<circle cx="209" cy="152" r=".22"/>
<circle cx="195.2" cy="133.2" r=".22"/>
<circle cx="195.2" cy="128.6" r=".22"/>
<circle cx="193.2" cy="150.9" r=".23"/>
<circle cx="193.2" cy="139.9" r=".22"/>
<circle cx="233.3" cy="148.9" r=".22"/>
<circle cx="234.3" cy="147.9" r=".23"/>
<circle cx="187.7" cy="129.6" r=".22"/>
<circle cx="171.4" cy="145.2" r=".22"/>
<circle cx="171.4" cy="150.1" r=".22"/>
<circle cx="170.9" cy="144.7" r=".22"/>
<circle cx="190.6" cy="129" r=".22"/>
<circle cx="170.9" cy="150.6" r=".22"/>
<circle cx="187.6" cy="129" r=".22"/>
<circle cx="187.3" cy="132.2" r=".23"/>
<circle cx="201.5" cy="164.6" r=".22"/>
<circle cx="235.4" cy="146.1" r=".4"/>
<circle cx="237.3" cy="147.1" r=".23"/>
<circle cx="237.3" cy="148.5" r=".23"/>
<circle cx="220.8" cy="150" r=".22"/>
<circle cx="237.3" cy="149.6" r=".23"/>
<circle cx="172.2" cy="149.1" r=".23"/>
<circle cx="172.2" cy="147.6" r=".23"/>
<circle cx="183" cy="131.1" r=".23"/>
<circle cx="185.9" cy="128.2" r=".22"/>
<circle cx="183" cy="139.5" r=".22"/>
<circle cx="220.3" cy="142.5" r=".22"/>
<circle cx="219.7" cy="143.1" r=".23"/>
<circle cx="213.7" cy="144.3" r=".22"/>
<circle cx="235.4" cy="141.4" r=".23"/>
<circle cx="173.1" cy="146.6" r=".23"/>
<circle cx="181.8" cy="157.8" r=".22"/>
<circle cx="180.8" cy="156.6" r=".22"/>
<circle cx="201.9" cy="159.7" r=".23"/>
<circle cx="180.8" cy="159.7" r=".23"/>
<circle cx="173.7" cy="146.1" r=".23"/>
<circle cx="205.4" cy="151.2" r=".22"/>
<circle cx="198.6" cy="126.3" r=".22"/>
<circle cx="198.6" cy="129.5" r=".22"/>
<circle cx="195.6" cy="165.5" r=".23"/>
<circle cx="185.1" cy="134" r=".23"/>
<circle cx="200.7" cy="168.4" r=".22"/>
<circle cx="194.4" cy="129.2" r=".22"/>
<circle cx="193.9" cy="129.7" r=".23"/>
<circle cx="234.1" cy="142.3" r=".23"/>
<circle cx="214.4" cy="146.6" r=".23"/>
<circle cx="203.5" cy="130.1" r=".22"/>
<circle cx="208.9" cy="128.8" r=".22"/>
<circle cx="238.5" cy="153.6" r=".22"/>
<circle cx="239.4" cy="149.1" r=".23"/>
<circle cx="176.2" cy="144.6" r=".22"/>
<circle cx="170.2" cy="133.1" r=".23"/>
<circle cx="170.2" cy="147.1" r=".22"/>
<circle cx="169.9" cy="149.6" r=".22"/>
<circle cx="238" cy="148.6" r=".23"/>
<circle cx="241.1" cy="148.3" r=".22"/>
<circle cx="174.6" cy="148.5" r=".23"/>
<circle cx="175.3" cy="147.8" r=".22"/>
<circle cx="174" cy="148.5" r=".23"/>
</g>
<g fill="none" stroke="#c83434" stroke-width=".2">
<path d="M170.2 133.1h9.1M178.9 130.3v1.1l.4 .4v1.3M179.3 133.1h.1M181.5 130.3v1.4l-.4 .3v1.1M181.5 130.3h.1M181.5 130.3h3.7M183 131.1v8.4M184.2 132.2l.1 1.8h.8M185.9 128.2h5.7v.4M187.3 132.2h-1.2v.8l-.2 .2v9.3l-.7 .7h-7.3l-1 1v3.8l-.4 .3h-.4M187.6 129h4M188 127.2h.9"/>
<path d="M189.6 127.2h1.4l.6 .6M189.6 130.3v7.8M190.2 125.2l.2 2M191.6 129.4h-.7l-.2 .2-3 .1M192.3 129.4v.6M192.9 127.8h.7l1.5-1.5h5.9v-.9l.7-.7h8.2l.3 .3v1.5h1.4l1.9 1.9M192.9 128.2v.4h10.4l1.8 1.8M192.9 129.4h.7l.3 .3h1.1l1.5 1.5h1M192.9 129l2.3 .2 .9 .9h1.4M193.6 125.2h-1.6v1.2l.3 .3v1.1M195.2 133.2l-2 2v4.7M195.4 125.2h1"/>
<path d="M195.8 127.2h.8M197.5 130.7h.4l.2 .2M198.6 129.5v.7l.5 .5h.2M199.3 131.2h.3l.5 .5h.6l-.2 .2M199.3 130.1h1.4M202.3 130.1h1.2M202.5 126.3h.8M202.5 127.7h-1.5v.6l-.3 .3M208.9 126.5h-1.3v1.5M208.9 128.8v1.6M210.2 130.4v1.5l-.4 .4h-5.4l-.6-.6h-1.5M213.5 131v7.1h2.6l1.4-1.4h1.7"/>
<path d="M217.5 135.2v.7M221.6 135.7h.8M221.6 134.8h-.7l-.3 .3v1.3l.2 .3h.8M223.9 135v.8M225.5 136.5l-1.6 .1M225.8 138.2h.8M225.8 139.7h.8M226.5 133.3v.9M227.4 136.5v3.2M228 132.1l-.6 .6v2.1l-.3 .3h-1.3l-.3-.2v-.7M231.6 139.7l-1.6 .1M234.1 139.7v2.6"/>
<path d="M235.4 139.7v1.7M238 134.1l-2-2h-13.7l-.8 .8v1.9M238 134.2v10M168.6 144.9v.7h.7l.4-.4M168.6 149.1h2.9l.5 .5h1.9l.6 .6h1.7M168.6 151.1l.5 .4h.7M168.6 147.1h1.6M168.6 148.1h5l.4 .4 .3-.4h.5l.8 .8h.5M168.6 147.6h3.6M168.6 150.1h2.8M168.6 150.6h2.3M168.6 149.6h1.3"/>
<path d="M168.6 146.1h5.1M168.6 146.6h4.5M174.6 148.5l-.5 .5h-.3l-.4-.4h-4.8M175.3 147.8h.8M176.2 144.6v1.9M177 150.2h.8M177.8 146.5h.9M177.9 148.3h.7M180.8 156.6v3.1h21.1M193.2 150.9h-10.9l-2.4 2.4v12.9l-.5 .5h-1.3v-1.5M195.4 150.7h.8M195.5 147.6v.6"/>
<path d="M195.5 149.1l2.4 .1 .6 .6v.3M197 150.7h1.5M198.6 146.1v.8M198.6 147.6v1.2l.3 .3h.6M200.8 153.5l-4.4 4.4h-14.6M200.8 153v.5M200.8 153.5l8 8v6.7M202.4 152h.1M202.4 151.3h1.9l.2-.1h5l4.4 4.4v12.6M204.7 150.5h-1.5l-.2 .2h-1.2l-.4 .3h-.9v.6l-1 1v.4M209 152h-6.5M212.2 144.1v.8"/>
<path d="M212.2 145.7l.9 .9h.6l.5 .5h1M213.6 149.5l.1 .8M213.7 144.3v.8l1 1h.5M214.4 146.6h.8M215.2 147.6h-.6l-.3 .3h-.7M215.2 142.5v2.6M215.2 142.7h.1M216.1 142.7h.7M216.7 147.1h1.5M217.7 150v.5l-.4 .3v.7M218.2 147.1l-1 1h-2M218.2 147.1v1.3l1 1v.6h-.5v.7l.1 .2"/>
<path d="M218.7 144.2l.1-1.2-2.1-2.1h-11.2l-4.9 4.9v2.5l.2 .1v.7M219.2 144.2l-.1-1.3-2.2-2.2h-11.6l-5 5v2.6l-.1 .1v.7M219.7 143.1v1.1M219.7 150l.1 3M220.2 144.2v-1.2l-.4-.4v-1.8l-1.6-1.6h-20.8l-9.3 9.3h-8.8l-.4 .4h-1.1M220.2 150h.6M220.3 142.5l-.2-.3v-1.5l-1.7-1.7h-21.2l-9.2 9.2h-8.7l-.4-.4h-1.1M221.1 148.1l2.6-.1 .6 .6h8.8l.2 .3M221.1 149.1h.5l.9 .9v1.4l1 1v1.4l-3.8 3.8v7M221.1 147.6l2.7 .1 .7 .7h9.2l.6 .6h.6M221.4 153h.8M221.6 142.3v1l.5 .5v1.4l-.4 .4h-.6"/>
<path d="M221.6 140.7v.8M223.1 140.7v.8M223.1 142.3v.8l-.6 .6v1.6l-.8 .8h-.6M224.2 150v.9M225.8 145.7v1M225.8 141.7v1.8h-.7l-.2 .3h-1.1l-.5 .5v1.2l-1.1 1.1h-1.1M227.4 140.9v.8M227.5 143.5v1M229.2 145.4h-.6l-.3 .3h-.8v-.3l-.7-.7h-1.9l-2.4 2.4h-1.4M229.2 143.9v.7M230 140.7v.7M232.9 143.3v1.4"/>
<path d="M234.1 144.7v1.5l.9 .9h4.5l.2 .2h.7M234.3 147.9h.6M234.9 148.5h.7M235.4 141.4h.1M236.7 147.9l2.5 .2 .7 .7h.5M236.7 148.5h.6M237 142.8v.8M237 145.2v1.2l.3 .3v.4M237.3 149.6h2.3l.2 .2h.6M238 144.1l-1 1.1M238.5 153.6v1M238.7 151.1h.9l.2 .2h.6"/>
<path d="M238.7 145.6h.6l.2 .2h.9M238.7 148.6h-.7l-.4 .4h-.9M238.7 149.1h.7M239.3 154.6h.8M240.4 148.3h.7M240.6 142.1h.8M242.2 142.1v4.5l-1.2 1.2h-.6M178.1 167.5v.7h1.8M194.9 165.5v1.2M195.6 165.5h.7M200.7 164.6h.8M200.7 166.2v1.4"/>
<path d="M200.7 168.4v.8M219.7 166.2v1.4M219.7 168.4v.8"/>
</g>
<path d="M235.4 144.7v1.4" fill="none" stroke="#c83434" stroke-width=".4"/>
<path d="M168.4 123.8l.6-.5 .7-.1h76.2a1.9 1.9 0 0 1 1.7 1.9v44.2a1.9 1.9 0 0 1-1.9 1.7h-76.2a1.91 1.91 0 0 1-1.7-1.9v-2.2h.6a3.3 3.3 0 0 0 4.4 3.4 3.3 3.3 0 0 0 1.4-5.4h3.3v.6l.4 .3v.3l-.4 .2 .1 .8a.48 .48 0 0 1-.1 .8v.7l.2 .1 .8 .1 .4-.4 .2 .6 1.6-.1v-1.4h6.2v1.4l.1 .1h1.6l.1-1h1.1l.1 .9h1.1l.1-.9h6l.1 .9h1.1l.1-.1-.1-.9-9.6 .1-.1-.6h-1.6l-.1 .1-7.8-.1-.1 .6a.49 .49 0 0 1-.5-.8h13.5v.2a.55 .55 0 0 0 .9 .4 .55 .55 0 0 0 0-1 .55 .55 0 0 0-.9 .4h-13.5l.2-.3h.8l.5-.6 .1-.5h9.7l.1 .9h1.1l.1-.1-.1-.9h-1.1l-.1 .1h-9.7v-1h11.3v1.5l.1 .1 .8-.1v-1.5h2.1v1.5l.1 .1a.42 .42 0 0 0 .1 .5 .42 .42 0 0 0 .5 .1 .57 .57 0 0 0 .4 .9 .57 .57 0 0 0 .6-.8 .57 .57 0 0 0-.9-.2l-.1-.4 .2-.2 .1-.5 .5 .1 .1 .5h.7l.1-.6h.3l.1 .9h1.1l.1-.7h1.7v.5l.4 .3v.2l-.4 .3v.6l.3 .3v.4l-.3 .3v.6l.3 .3 .6-.1 .3-.2v-.6l-.3-.3v-.4l.3-.3v-.6l-.4-.3v-.2l.4-.3-.1-.7-.8-.1-.3 .3h-1.7l-.1-.3-1.5 .1-.1-1.1h-.7l-.1 .5h-.5l-.2-.5-.8 .1h-2.1l-.1-.1-.8 .1h-11.3v-.3l.6-.1v-1.4h6.2v1.4l.1 .1h1.6l.1-.2h11.4l.1 .7 .8 .1 .2-.1a.41 .41 0 0 0 .5-.2 .41 .41 0 0 0-.1-.6l-.3 .1-.2-.2-.7-.1-.3 .3h-11.4v-1.3l-.1-.1h-1.6l-.1 .1h-6.2l-.6-.1v-6.3h.4l.1 .3v2.5a.36 .36 0 0 0 0 .6 .36 .36 0 0 0 .5-.1h20.5a.36 .36 0 0 0 .6 0 .36 .36 0 0 0-.1-.5 .36 .36 0 0 0-.5 .1h-20.5l-.1-1.7h.4a.37 .37 0 0 0 .3 .4 .37 .37 0 0 0 .4-.1h14.3l4.4-4.3 7.8 7.7v5.7a.98 .98 0 0 0-.7 1.2 .98 .98 0 0 0 1.1 .8 .98 .98 0 0 0 .8-1.1h.6v.2a.98 .98 0 0 0 1.5 .7 .98 .98 0 0 0 0-1.6 .98 .98 0 0 0-1.5 .7h-.6l-.2-.5-.6-.4v-5.9l-7.7-7.7 .4-.2v-.9l-.4-.1-.2 .2-.4-.2-.2 .2-.5-.2 .2-.2h1.4l.1-1.1 .2-.2 .1 .1-.1 .3 .1 .4h-.1v.5l1.3 .1 .3 .3h.8l.3-.3h4.1a.36 .36 0 0 0 .5-.1 .36 .36 0 0 0 0-.5 .36 .36 0 0 0-.5 .1h-4.1l-.2-.2 .2-.2 .8 .1 .3-.1h3.7l4.3 4.3v11.5l-.8 .1 .1 1.9 1.9-.1v-1.8l-.8-.1v-1.2h5v.5l.4 .3v.2l-.4 .4v.5l.3 .3v.4l-.3 .3v.5l.3 .4 .6-.1 .3-.2v-.6l-.3-.3v-.4l.3-.3v-.6h11v1.9l.2 .2h8.2l.2-.2v-1.9l-.2-.2h-8.2l-.2 .2h-11l-.4-.4h20.5a3.3 3.3 0 0 0 4.7 3.2 3.3 3.3 0 0 0 .6-5.7 3.3 3.3 0 0 0-5.3 2.2v.3h-20.5l.4-.4v-.6l-.2-.2h-.8l-.2 .3h-5v-1.7h5l.1 .7 .8 .1 .2-.1 .1-.7-.4-.3v-6.3l3.4-3.4h14.7v.7l.2 .2h.6l.3-.3h.5l.2 .3 .8-.1 .1-.8-.2-.2-.7-.1-.2 .3h-.5l-.4-.3a.41 .41 0 0 0 .1-.5 .41 .41 0 0 0-.5-.2l-.2 .3 .2 .3-.3 .4h-14.7l.4-.4v-1.5h16.1l.1 .4 .3 .2h.8l.4-.3h4.3l.1 .4 .3 .2h.8a.53 .53 0 0 0 .5-.5 .53 .53 0 0 0-.5-.5h-.8l-.4 .4h-4.3a.52 .52 0 0 0-.4-.8l-.9 .1-.3 .4h-16.1l-1-1.1v-.6l.3-.3v-.7h.6v.7l.3 .2a.38 .38 0 0 0 0 .5 .38 .38 0 0 0 .5 0 .38 .38 0 0 0 0-.5l.3-.3v-.7l-.2-.1-.6-.1-.3 .3h-.6l-.2-.3h-.6l-.6-.5v-.2h-1v.6l.9 .1 .5 .4v.6l.3 .3v.8l.9 1v1.2l-3.7 3.9v6.4l-.4 .3h-5v-8.8l-2.1-2.1h4.7l.2 .2h.7l.2-.1 .1-.3h-.5v.4h-.2v-.4h-.5v.2h-4.7l-.5-.5h5.2v.2h1.2l-.1-.4-.4-.1v.5h-.2v-.5l-.4 .1-.1 .2h-5.2l-2-2h-5a.39 .39 0 0 0 .5-.3 .39 .39 0 0 0-.3-.5l-.4-.2h-.7l-.3 .3-.3 .1-.1-.5h-.8l-.2 .2 .1 .4-.3 .1-.1-.6h-2.3v2.2l.1 .2-.2 .3v.8l.4 .1 .2-.1 .5 .2-4 4h-14.3a.35 .35 0 0 0-.6 .2h-.4v-.9a.36 .36 0 0 0 0-.6 .36 .36 0 0 0-.5 .3h-.4v-3.1l2.3-2.4h10.5a.36 .36 0 0 0 .5 .1 .36 .36 0 0 0 0-.6 .36 .36 0 0 0-.5 .1h-10.7l-2.6 2.6v9.6l-.6 .1v1.4l.6 .1v1.6l-.3 .3h-.5l-.4-.3v-.4l.3-.3v-.5l-.2-.2h-.7l-.3 .2h-3.3a3.3 3.3 0 0 0-3.6-.9 3.3 3.3 0 0 0-2.2 2.9h-.6v-3.1h9.7l.3 .2h.7l.2-.2v-.2h-.5v.4h-.1v-.4h-.6v.2h-9.7v-.5h9.7v.2h1.2v-.4l-.3-.1h-.2v.5h-.1v-.5l-.4 .1-.2 .2h-9.7v-10.4l1.6-.2v-.7h-1.3l-.3-.2v-.4l.8-.1 .4 .4h.5a.38 .38 0 0 0 .5 0 .38 .38 0 0 0 .1-.5 .38 .38 0 0 0-.6 0v-.4h1.1a.4 .4 0 0 0 .5 .1 .4 .4 0 0 0 .2-.5 .36 .36 0 0 0 .4-.4 .36 .36 0 0 0-.6-.2h-.9v-.5h1.2l.6 .5h1.8l.6 .6h1.2l.3 .4h.5l.3-.3h.5l.3 .3h.6l.2-.4h16.5l.1 .7 .1 .1 .8 .1a.58 .58 0 0 1 .9 0h.2v-1.2h-.3a.5 .5 0 0 1-.4 .3 .5 .5 0 0 1-.4-.3h-.7l-.3 .3h-16.5v-.6l-.2-.2h-.6l-.2 .3h-.6l-.3-.3h-.5l-.3 .4h-1l-.7-.6-1.4-.1v-.5h.8l.4 .4h.5l.8-.6 .5 .5 .9 .1 .1-.2v-.4l.6-.5v-.4h.4v1.3l.2 .2 1.2-.1 .5-.4h8.8l1.4-1.4h5.3v.6a.57 .57 0 0 1 0 .9v.6l.2 .3h.8l.3-.4h.2l.3 .4h.7l.2-.3h.2l.3 .3-.1 .3v.3h-.4l-.3-.2h-.3v1.2h.3l.3-.2h.4v.4l.1 .2-.1 .1v.4h1l.1-.4-.2-.1 .2-.3v-1.4l-.6-.6h.7l.2 .2v-.5h-.2v.3h-.7l-.5-.4-.4-.1-.1-.2h1.7v.3h.2v-.5l-.2 .2-2.5-.1-.3 .3-.3-.1a.58 .58 0 0 1 0-1l.3-.1 .3 .3 1.3-.1 .3 .3h.7l.2-.3v-.2h-.5v.5h-.2v-.5h-.5v.2h-.5l.1-.3h-.5v.4h-.2v-.4h-.5v.1h-.3v-.4h.3v.1h1.2l-.1-.3-.2-.1h-.2v.4h-.2v-.4h-.4l-.1 .3h-.3l-.2-.3h-.7l-.3 .3h-5.3l1.5-1.5h6.9v.6a.56 .56 0 0 1 0 1v.2h1.2l-.1-.4-.2-.2v-.3l.3-.3-.1-.8-.9-.1-.2 .3h-6.9l6.4-6.3h20.7l1.4 1.4v1.8l-.3 .2-2.4-2.5h-11.6l-5.2 5.2v2.5l-.2 .6-.3-.2v1.1l.2-.2 .3 .2 .4-.1 .2 .1 .4-.1 .4 .1 .2-.1v-.3h11.3v.6l.4 .3a.41 .41 0 0 0 .1 .4 .41 .41 0 0 0 .5 0v-.5l.2-.3h1.7l.1 .8h.9l.2 .1v.3l-.4 .3 .1 .7 .1 .1h.8l.2-.2v-.6l-.3-.3 .3-.4 .2 .1v-1.1l-3.9 .2v-.6l-.3-.2h-.6l-.3 .3h-11.3v-.6l-.4-.1-.2 .2-.3-.5h12.2l.2 .2 .4 .1v-.5h-.6v.2l-12.2-.1v-.4h12.2v.2h.6v-.6l-.4 .1-.2 .3h-12.2l.1-1.8 1.9-2h8.8v.5a.66 .66 0 0 1 0 1l.1 .8 .7 .1 .5 .5h.7l.4 .5h-.3v1.2l.4-.1 .6-.5 .1 1.4h.9l.1-1h.4l.1 .8h2.2l.3 .3-.6 .1v1.1l.2-.1v.3a.39 .39 0 0 0 .5 .4 .39 .39 0 0 0 .2-.6l.3-.1 .2 .3-.4 .4 .1 .7 .3 .5-.3 .2v.8l.1 .1h.9l.1-.8h.4v.7l.3 .2h.6l.3-.3a.39 .39 0 0 0 .5-.3 .39 .39 0 0 0-.5-.3l-.3-.3h-.6l-.3 .3h-.4l-.3-.3v-.3l.2-.3h.6l.3 .3h.5l.2-.2v-.3h-.4v.5h-.1v-.5h-.5v.2h-.6v-.6h.6v.2h1v-.3l-.2-.2h-.2v.5h-.1v-.5l-.4 .1-.1 .2h-.6l-.3-.3v-.3l.4-.1 .1-.2a.39 .39 0 0 0 .6 0 .39 .39 0 0 0-.1-.6 .39 .39 0 0 0-.6 .1l-.1-.3h-.9l-.2-.4 .9-.1v-3.5h.5v.3v2.7h1v-.2l.3-.1h1.7l.7 .7h8.6a.4 .4 0 0 0 .5 .3 .4 .4 0 0 0 .3-.4l.5 .4 .6 .1h.5v-.5a.39 .39 0 0 0 .6-.3 .39 .39 0 0 0-.6-.4l-.1-.5-.6 .1a.39 .39 0 0 0-.6 .1 .39 .39 0 0 0 .4 .5v.5l-.7-.7h-9.1l-.7-.6-2.1-.1 .9-.1 1.3-1.3 .7-.1 .1-.8 .2-.1 .1 1.5 .3 .1a.39 .39 0 0 0 .4 .5 .39 .39 0 0 0 .4-.5l.3-.1 .1-1.5h.2l.1 1.5h1.2l.1-.5 .4-.2 .3 .2 .8-.1 .1-.8-.3-.3v-.3l.3-.3v-.4h1.4v1.8l.2 .2h.5l.1-.2v-1.8h.4l.1 1.8 .1 .2h.4l.3-.2v-1.8l-.2-.2 .1-.3h3.2l.1 .8 .8 .1 .3-.3v-.6l-.3-.3a.39 .39 0 0 0-.3-.5 .39 .39 0 0 0-.3 .5l-.3 .3h-3.2a.37 .37 0 0 0-.5-.3 .37 .37 0 0 0-.1 .6l-.2 .2h-.4l-.2-.2h-.5l-.1 .2h-1.4l-.1-.5h-.9l-.2 .2v.6l.3 .3v.4l-.6 .6-.1-.5-.5-.1 .1-.4 .4-.1v-1.5l-1.3-.1-.1 .1v1.4l.3 .2v.3l-.3-.2h-1.9l-.5 .4h-.6l-.2 .2-.1-.7 .2-.2 .9 .1 .4-.3 .2 .3h1.3v-1.5l-.5-.2 .1-.3 .3-.2v-.7h.4l.1 .9h.8l.2-.2 .1-.7-.3-.3a.38 .38 0 0 0-.4-.5 .38 .38 0 0 0-.3 .5l-.2 .3h-.4l-.3-.3-.8 .2v.8l.3 .2v.4h-.5v.5l-.3 .3-.3-.3-.8 .2-.1 .3-.5 .6v1.1l-1 1h-.2v-.1l.8-.9v-1.6l.6-.6 .1-.3 .3-.3v-.8a.44 .44 0 0 1-.3-.4 .44 .44 0 0 1 .3-.3v-.7l-.3-.3-.7 .1-.2 .8a.61 .61 0 0 1 0 1v.6l.4 .4-.6 .6-.5-.4v-.3l.4-.3v-.6l-.3-.3v-.5l.3-.2-.1-.8-.8-.1-.2 .2-.1 .7 .3 .2a.66 .66 0 0 1-.3 .9l.1 .6 .3 .2v.5l.5 .5v1.3l-.2 .1-.1-.1h-1v.3h-.5l-.1-.4h-3.7l-.2 2.8h-.3v-.5l-.1-.1 .1-2.3h5.8l-.1-.2h-.3v.2h-.2v-.2l-.3 .1-.1 .1h-4.8v-.3l-.3-.1v-.8h.4l.1 .9h2.1v-1.1h-2l-.2 .2h-.4l.1-.5a.59 .59 0 0 1 .9 0l.8-.1 .1-.8-.3-.3h-.6a.56 .56 0 0 1-1 0h-.2l-.1 .7h-.5v.4l.3 .2v1.2l-.3 .1v1l-.4-.3v-.6l-.3-.3v-.5l.2-.1 .1-.4h-1.2v.2a.62 .62 0 0 1 .2 .9l-.2 .2 .1 .7 .8 .2 .4 .5-.4 .3-.3-.1h-.5l-.4-.4v-.6l-.3-.3v-.4l.3-.2v-.6l-.3-.3h-.7l-.2 .3h-8.8l.7-.7h9.6v.2h1.2l-.1-.3-.2-.2h-.2v.5h-.2v-.5l-.4 .1-.1 .2h-9.6l.8-.8h10.4v.3h.5v-.6l-.4 .1-.1 .2h-10.4l1.3-1.2h11l1.9 1.8-.1 .7-.2-.1v1.1l2.2-.1v-1.7a.43 .43 0 0 0 .2-.5 .43 .43 0 0 0-.3-.3l-.1-1.6-1.1-1.1h6.2l.1 .8h.9a.46 .46 0 0 1 .8 .1h.6l.3-.2v-.3h-.5v.5h-.2v-.7l2.1-.1 .1 .7 .3 .2-.1 .5-.3 .2v.6l.2 .2h.8l.2-.2v-.5l-.3-.3-.1-.6 .4-.3h.5l.1 .8h.7l.1-.2v-1.7h.4l.1 1.8 .1 .1h.5l.2-.2v-1.7h.4v1.7l.2 .3v1.1a.36 .36 0 0 0 0 .5 .36 .36 0 0 0 .5 0 .36 .36 0 0 0 0-.5v-1.1l.2-.3v-1.7h.4v1.7l.2 .3v.2a.36 .36 0 0 0 0 .6 .36 .36 0 0 0 .5-.1 .36 .36 0 0 0-.1-.5l.2-.5v-1.7l-.1-.2h-.6l-.1 .2h-.4l-.2-.2-.4-.1-.3 .3h-.4l-.2-.2-.4-.1-.3 .3h-.4l-.1-.2-.5-.1-.2 .2v.7h-.5l-.4-.3-.7 .1-.2 .2h-1.4l-.2-.3-.3-.1v.5h-.2v-.5l-.3 .1a.52 .52 0 0 1-.9-.1h-.6l-.2 .3h-6.2l-.7-.7h-21.2l-9.3 9.3h-8.5l-.4-.4-1.3-.1-.2 .2h-.4v-1.5h.2v.7l.2 .2h.6l.2-.4a.39 .39 0 0 0 .6 .1 .39 .39 0 0 0 0-.6 .39 .39 0 0 0-.6 .1l-.3-.4h-.5l-.4 .3v-1.9l.9-.9h7.3l.9-.9v-2.6h6.6a.36 .36 0 0 0 .5 .3 .36 .36 0 0 0 .1-.6v-4.3l1.8-1.8a.36 .36 0 0 0 .3-.3 .36 .36 0 0 0-.4-.4 .36 .36 0 0 0-.3 .4l-1.8 2v4.4l-.2 .3h-6.6v-5.2l.3-.4-.1-.7-.2-.3 .4-.4v-.5h.4a.36 .36 0 0 0 .6 0 .36 .36 0 0 0-.1-.5 .36 .36 0 0 0-.5 0h-.4v-.4l-.2-.2-.6 .1v1.6l-.2 .4a.62 .62 0 0 1-.8 .2l-.3-.3 .2-.5v-1.3l-.2-.2h-.5l-.2 .3v1.2l.2 .5-.2 .3v.8l.2 .2h.5l.3-.3h.2a.54 .54 0 0 1 .7 .4v7.7l-.6 .6h-7.2l-1.2 1.1-.1 1.9-.2-.2v-.9a.36 .36 0 0 0 0-.6 .36 .36 0 0 0-.5 .1 .36 .36 0 0 0 0 .5v.9l-.3 .3v.8l.3 .2 .8-.1v.9l-.2 .1-.1-.5h-.9a.41 .41 0 0 0-.6 .4h-.6l-.4 .2-.3-.2-1.1-.1a.37 .37 0 0 0-.1-.5 .37 .37 0 0 0-.5 0h-1.3l-.1-.5h2.3a.41 .41 0 0 0 .5 .1 .41 .41 0 0 0 .2-.5 .36 .36 0 0 0 .5-.1 .36 .36 0 0 0-.1-.5 .36 .36 0 0 0-.5 0h-3.9l.2-.3a.35 .35 0 0 0 .4-.4 .35 .35 0 0 0-.5-.3l-.1-.1h1.1l.1 .3 .4 .1a.37 .37 0 0 0 .4 .4 .37 .37 0 0 0 .3-.5 .37 .37 0 0 0-.6-.2v-.3a.35 .35 0 0 0-.4-.1 .35 .35 0 0 0-.2 .3h-1.1l-.2-.9h-1.5v-10.7h2.1a.37 .37 0 0 0 .2 .3 .37 .37 0 0 0 .4-.1h8.1l.2 .6h.8l.3-.2v-1.1h.6v1.2l.2 .1h.8l.2-.2 .1-1.1-.5-.5 .4-.3v-.6l.4-.1h.5l.2 .3v7.8a.36 .36 0 0 0-.1 .5 .36 .36 0 0 0 .6 0 .36 .36 0 0 0-.1-.5v-7.8a.35 .35 0 0 0 0-.6 .35 .35 0 0 0-.6 .3h-.5l.4-.6h2.2l.2 .6 .5 .1 .2-.2v-.7h3.7l.1 .3v7.2a.36 .36 0 0 0 0 .5 .36 .36 0 0 0 .5 0 .36 .36 0 0 0 0-.5v-7.2a.35 .35 0 0 0-.1-.6 .35 .35 0 0 0-.5 .3h-3.7v-.7l-.2-.2-.5 .1-.2 .6h-2.3a1 1 0 0 0-1.7-.5 1 1 0 0 0 .5 1.7l-.3 1-.4 .3h-.6l-.3-.3-.1-.6-.3-.4 .7-.1v-1.8l-1.9-.1v1.9l.7 .1 .4 .6-.1 .4a.43 .43 0 0 0-.4 .6l-8.2-.1a.35 .35 0 0 0-.5 .3h-2.1v-6.2h.6v.4a3.3 3.3 0 0 0 2.8 3.1 3.3 3.3 0 0 0 3.7-2.2h10.7v.2l.3 .2 5.3-.1v.3l-.6-.1-.3 .1h-2.4a.39 .39 0 0 0-.6 0 .39 .39 0 0 0 .1 .6 .36 .36 0 0 0 .1 .5 .36 .36 0 0 0 .5-.1h2.8l.2-.1h1a.39 .39 0 0 0 0 .5 .39 .39 0 0 0 .6 0 .39 .39 0 0 0 0-.5h.9l.4 .4 1-.2 1.6 1.5 1.2 .1 .2-.2a.41 .41 0 0 0 .6-.3 .41 .41 0 0 0-.4-.5l-.2-.1v-.4l-.1-.2-1.6 .1-.4-.4h2.5l.1 .8 .5 .6v.6h.6l.9 .8 .7-.1 .1-.8h.6v.7l.2 .2h.6l.3-.4h.8l.7 .6h5.4l.6-.5v-.3l.3-.1v-.7h1.8a1.13 1.13 0 0 0 .8 1.1v5.8a.36 .36 0 0 0 0 .6 .36 .36 0 0 0 .5-.1h2.3l.5-.4h8.7l.1 .8h.9a.46 .46 0 0 1 .8 .1l.7-.1 .2-.4h-.5v.5h-.2v-.7h.7v-.2l-.2-.2-.3-.1v.5h-.2v-.5l-.3 .1a.53 .53 0 0 1-.9-.1h-.6l-.2 .3h-8.7l.6-.6h.6l.3-.3 1.7 .1 .2-.2v-.5l-.2-.1-1.1-.1-.6 .3-.1-.2a.45 .45 0 0 1 0-.8v-.7l-.3-.2-.8 .1v.8a.56 .56 0 0 1-.1 1v.5l-.8 .9h-2.2l-.1-3.3h4.7v.4l.3 .2h1.1l.2-.2h.4v1.5l.5 .6 1.3-.1 .1-.5-.3-.3 .2-.1a.4 .4 0 0 0 .6-.4 .4 .4 0 0 0-.6-.3l-.2-.2 .3-.2v-.2h1v.5a.66 .66 0 0 1 0 1v.6l.3 .2h.7l.2-.3h.5l.3 .5h.5l.1-.3h1.1l.2 .3h.5l.1-.2 .1-.5h-.4v.7h-.1v-.7h-.4v.4h-1.1v-1h1.1v.4h.9l-.1-.5-.1-.2h-.2v.7h-.1v-.7l-.4 .3h-1.1l-.1-.3h-.5l-.2 .2v.4l-.5 .1-.1-.2a.57 .57 0 0 1 0-.9v-.6l-.2-.2h-.7l-.3 .3h-1l-.1-.4-.5-.1v-1.3l.7-.7h5l-.2 .3v.8l-.3 .3-.1-.2a.39 .39 0 0 0-.3-.6 .39 .39 0 0 0-.4 .6l-.1 .2-.3-.3-.4 .1-.2 .1v1.2l.6 .5h1.5l.6-.4 .1-1.2-.2-.3v-.6l.4-.5h7.8l1.9 1.9v9.8l-.5 .6h-.7l-.2 .2v.7l.4 .2v.7l.2 .4h-1.9l-.7-.8h.5v.2a.56 .56 0 0 0 .8 .3 .56 .56 0 0 0 .1-.9v-1.9l-.6-.1-.2 .2v1.9l-.1 .3h-.5l.2-.4-.1-1.8-.2-.2-.5 .1-.1 1.9 .2 .2v.5l.9 1h2.2l.3 .1 .9-.1v.6l-1.4-.3-.5 .1v1.5l.7 .1a.37 .37 0 0 0 .1 .5 .37 .37 0 0 0 .5 0h.6l.1 1.5h1l.1 .1a.46 .46 0 0 0-.5 .6 .46 .46 0 0 0 .7 .3l.2-.3-.1-.5h1.2v-2.8a.4 .4 0 0 0 .5-.3 .4 .4 0 0 0-.2-.5l1.3-1.3v-2.8h3.2l.1 .4 .3 .1 .8 .1a.53 .53 0 0 0 .5-.6 .53 .53 0 0 0-.5-.5h-.8l-.4 .5h-3.2v-1l.3-.4-.1-.8-.8-.1-.2 .3h-.6l-.2-.3h-.6l-.2 .3 .1 .8 .7 .1 .2-.3h.6l.3 .4v3.6l-1.1 1.1-.1-1.9h-1l-.4-.2 .4-.4 .1-.5 .3 .2h.9a.53 .53 0 0 0 .3-.6 .53 .53 0 0 0-.4-.4h-.9l-.4 .6a.43 .43 0 0 0-.5-.1 .43 .43 0 0 0-.3 .3l.2 .8-.9 .1v1.4h-.6l-.4-.5v-.5l.4-.3v-.7l.6-.5v-10.2l-2.1-2.2h-13.8l-1 1-.1 1.4-.4 .1-.4 .6h-.4v-.5l-.2-.2h-1.1l-.3 .3h-4.7v-2.7a.98 .98 0 0 0 .4-1.7 .98 .98 0 0 0-1.6 .7h-1.8v-1.7l-.9-.1-.1 .1v2.4l.3 .2-.3 .3h-5.2l-.6-.6h-1l-.3-.4h-.6l-.2 .3h-.6l-.2-.3h-.6l-.3 .3-.4-.4 .1-.7 .3 .1 .3 .3h.7l.1-.2v-.7h.6v.7l.2 .2h.6l.3-.3h.3a.36 .36 0 0 0 .6-.1 .36 .36 0 0 0-.1-.5 .36 .36 0 0 0-.5 .1h-.3l-.3-.4h-.6l-.2 .3h-.6l-.2-.3h-.6l-.3 .4h-1.3a.38 .38 0 0 0 0-.6 .38 .38 0 0 0-.5 .2h-2.5l-.5-.5 .2-.1h7.7l1.4 1.3v1.4l.1 .1 .9-.1v-2.4h.3v2.5l1-.1v-2.4h.2l.1 2.4 .9 .1v-2.5h.3v2.4l.9 .1 .1-2.5-.2-.2a.38 .38 0 0 0-.4-.5 .38 .38 0 0 0-.2 .6l-.2 .1-.4-.1-.9 .1-2.4-.1-.2 .4-1.1-1.1h-2.2v-.3l.3-.2h.5l.3 .2 .6-.1 .1-.6-.3-.1h-.5l-.2 .2-1.3-.2-.2 .1v.5l.3 .3-.2 .2h-7.2v-.3l.5-.3 .7-.1 .2-.8 .4-.4 .2 .1-.2 .3v.7l.1 .1 .8 .1 .2-.3a.41 .41 0 0 0 .5 0 .41 .41 0 0 0 .1-.5l-.3-.2-.2 .1-.3-.3 2.2-.1 .3 .2 .3-.2h1.6l.2 .2h.5l.3-.1v-.5h.5v.5l.2 .1h.6l.2-.2a.38 .38 0 0 0 .6 0 .38 .38 0 0 0-.1-.5 .38 .38 0 0 0-.5 .1l-.2-.2h-.5l-.3 .2h-.5l-.3-.2v-.4l.2-.2h3.2v2.4l.9 .1 .1-2.5h.3v2.4l.9 .1 .1-.1v-2.4h.2l.1 2.5a.41 .41 0 0 0 .3 .5 .41 .41 0 0 0 .5-.2l.2-1.4 .2 .1v1l1-.1-.1-2.5h-.9v1.1l-.3-.1v-.9l-.1-.1-6.6 .1 .4-.4h8l.2 .2-.3 .2v2.5h.9l.1-1.1h.7l1.2 1.2a1 1 0 0 0 .7 1.5 1 1 0 0 0 1.2-1.2 1 1 0 0 0-1.5-.6l-.7-.7h28.1a3.3 3.3 0 0 0 4.7 3.2 3.3 3.3 0 0 0 .6-5.7 3.3 3.3 0 0 0-5.3 2.2v.3h-28.1l-.6-.6h-1v-1l-.3-.3h2.1v.8h.5v.2h-.5l.1 .8 .8 .1v-.5h.2v.5h.8l.1-.9h-.5v-.2h.5l-.1-.8-.8-.1v.5h-.2v-.5l-3 .1-.5-.5h-8.2l-.9 .8v.5l-.3 .3h-1.6l-.3-.2-.3 .2h-2.4l.2-.6a.39 .39 0 0 0 .5 0 .39 .39 0 0 0 0-.6 .39 .39 0 0 0-.5 0 .45 .45 0 0 0-.4-.5h-.6l-.2 .1-.1 1.2 .2 .4-.5 .5-.7 .1-.3 .9h-1v-1l-.2-.3v-.3a.51 .51 0 0 0 .4-.6h.2l.1 .5 .2 .1h.8l.2-.1v-1.4l-.2-.1h-.7a.45 .45 0 0 0-.4 .6h-.2l-.1-.5-.2-.1h-.7l-.2 .1-.1 1.3 .4 .2v.5l.3 .3-.1 .6-.4 .1-1-1-.1-.4 .3-.4v-1.2l-.3-.1h-.8l-.1 .3v1.1l.6 .6a.52 .52 0 0 1-.4 .5 .52 .52 0 0 1-.6-.3h-.7l-.2 .3a.39 .39 0 0 0-.6 .1 .39 .39 0 0 0 .1 .5 .39 .39 0 0 0 .5 0l.3 .3h.6l.3-.3h.3l.3 .3h.6l.3-.2 .2 .4h-5a.35 .35 0 0 0-.4-.1 .35 .35 0 0 0-.2 .3h-10.7v-.3a3.3 3.3 0 0 0-2.7-4.1 3.3 3.3 0 0 0-3.8 3.1h-.6v-2.1z" fill-rule="evenodd" fill="#c83434"/>
<g fill="#fff">
<circle cx="227.4" cy="140.9" r=".13"/>
<circle cx="237" cy="142.8" r=".12"/>
<circle cx="232.9" cy="143.3" r=".13"/>
<circle cx="235.6" cy="148.5" r=".12"/>
<circle cx="196.6" cy="127.2" r=".13"/>
<circle cx="222.2" cy="153" r=".12"/>
<circle cx="178.7" cy="146.5" r=".13"/>
<circle cx="198.6" cy="146.8" r=".13"/>
<circle cx="207.6" cy="128" r=".12"/>
<circle cx="223.9" cy="135.8" r=".12"/>
<circle cx="178.1" cy="167.5" r=".12"/>
<circle cx="225.8" cy="146.7" r=".13"/>
<circle cx="196.2" cy="150.7" r=".13"/>
<circle cx="218.8" cy="150.9" r=".12"/>
<circle cx="196.4" cy="125.2" r=".13"/>
<circle cx="223.1" cy="141.5" r=".13"/>
<circle cx="198.1" cy="130.9" r=".12"/>
<circle cx="230" cy="140.7" r=".12"/>
<circle cx="217.4" cy="135.9" r=".12"/>
<circle cx="203.3" cy="126.3" r=".13"/>
<circle cx="222.5" cy="135.7" r=".13"/>
<circle cx="226.6" cy="139.7" r=".12"/>
<circle cx="212.2" cy="144.9" r=".13"/>
<circle cx="226.6" cy="138.2" r=".12"/>
<circle cx="192.3" cy="130" r=".13"/>
<circle cx="229.2" cy="144.6" r=".12"/>
<circle cx="216.1" cy="142.7" r=".13"/>
<circle cx="213.7" cy="150.3" r=".12"/>
<circle cx="169.7" cy="145.2" r=".13"/>
<circle cx="224.1" cy="150.9" r=".12"/>
<circle cx="239.5" cy="145.8" r=".13"/>
<circle cx="204.7" cy="150.5" r=".12"/>
<circle cx="221.6" cy="141.5" r=".13"/>
<circle cx="188" cy="127.2" r=".13"/>
<circle cx="219.7" cy="168.4" r=".12"/>
<circle cx="241.4" cy="142.1" r=".12"/>
<circle cx="169.8" cy="151.5" r=".12"/>
<circle cx="226.5" cy="133.3" r=".12"/>
<circle cx="177" cy="150.2" r=".12"/>
<circle cx="178.6" cy="148.3" r=".13"/>
<circle cx="239.3" cy="154.6" r=".13"/>
<circle cx="227.5" cy="144.5" r=".12"/>
<circle cx="195.5" cy="148.2" r=".12"/>
<circle cx="239.6" cy="151.1" r=".12"/>
<circle cx="194.8" cy="166.7" r=".12"/>
<circle cx="189.6" cy="138.1" r=".13"/>
<circle cx="189.7" cy="130.3" r=".12"/>
<circle cx="189.6" cy="127.2" r=".13"/>
<circle cx="213.5" cy="138.1" r=".13"/>
<circle cx="209" cy="152" r=".12"/>
<circle cx="195.2" cy="133.2" r=".12"/>
<circle cx="195.2" cy="128.6" r=".12"/>
<circle cx="193.2" cy="150.9" r=".12"/>
<circle cx="193.2" cy="139.9" r=".13"/>
<circle cx="233.3" cy="148.9" r=".12"/>
<circle cx="234.3" cy="147.9" r=".12"/>
<circle cx="187.7" cy="129.7" r=".13"/>
<circle cx="171.4" cy="145.2" r=".12"/>
<circle cx="171.4" cy="150.1" r=".12"/>
<circle cx="170.9" cy="144.7" r=".13"/>
<circle cx="190.6" cy="129" r=".13"/>
<circle cx="170.9" cy="150.6" r=".13"/>
<circle cx="187.6" cy="129" r=".13"/>
<circle cx="187.3" cy="132.2" r=".13"/>
<circle cx="201.5" cy="164.6" r=".13"/>
<circle cx="235.4" cy="146.1" r=".2"/>
<circle cx="237.3" cy="147.1" r=".13"/>
<circle cx="237.3" cy="148.5" r=".12"/>
<circle cx="220.8" cy="150" r=".12"/>
<circle cx="237.3" cy="149.6" r=".12"/>
<circle cx="172.2" cy="149.1" r=".12"/>
<circle cx="172.2" cy="147.6" r=".13"/>
<circle cx="183" cy="131.1" r=".12"/>
<circle cx="185.9" cy="128.2" r=".13"/>
<circle cx="183" cy="139.5" r=".13"/>
<circle cx="220.3" cy="142.5" r=".12"/>
<circle cx="219.7" cy="143.1" r=".12"/>
<circle cx="213.7" cy="144.3" r=".13"/>
<circle cx="235.4" cy="141.4" r=".12"/>
<circle cx="173.1" cy="146.6" r=".12"/>
<circle cx="181.8" cy="157.9" r=".12"/>
<circle cx="180.8" cy="156.6" r=".13"/>
<circle cx="201.9" cy="159.7" r=".12"/>
<circle cx="180.8" cy="159.7" r=".13"/>
<circle cx="173.7" cy="146.1" r=".12"/>
<circle cx="205.4" cy="151.2" r=".12"/>
<circle cx="198.6" cy="126.3" r=".13"/>
<circle cx="198.6" cy="129.5" r=".13"/>
<circle cx="195.6" cy="165.5" r=".13"/>
<circle cx="185.1" cy="134" r=".12"/>
<circle cx="200.7" cy="168.4" r=".12"/>
<circle cx="194.4" cy="129.2" r=".13"/>
<circle cx="193.9" cy="129.7" r=".12"/>
<circle cx="234.1" cy="142.3" r=".12"/>
<circle cx="214.4" cy="146.6" r=".13"/>
<circle cx="203.5" cy="130.1" r=".12"/>
<circle cx="208.9" cy="128.8" r=".13"/>
<circle cx="238.5" cy="153.6" r=".13"/>
<circle cx="239.4" cy="149.1" r=".12"/>
<circle cx="176.2" cy="144.6" r=".12"/>
<circle cx="170.2" cy="133.1" r=".13"/>
<circle cx="170.2" cy="147.1" r=".13"/>
<circle cx="169.9" cy="149.6" r=".13"/>
<circle cx="238" cy="148.6" r=".12"/>
<circle cx="241.1" cy="148.3" r=".13"/>
<circle cx="174.6" cy="148.5" r=".13"/>
<circle cx="175.3" cy="147.8" r=".12"/>
<circle cx="174" cy="148.5" r=".12"/>
<circle cx="241.3" cy="167.1" r=".25"/>
<circle cx="242" cy="165.4" r=".25"/>
<circle cx="242" cy="168.8" r=".25"/>
<circle cx="243.7" cy="164.7" r=".25"/>
<circle cx="243.7" cy="167.1" r="1.6"/>
<circle cx="243.7" cy="169.5" r=".25"/>
<circle cx="245.4" cy="165.4" r=".25"/>
<circle cx="245.4" cy="168.8" r=".25"/>
<circle cx="246.1" cy="167.1" r=".25"/>
<circle cx="239.4" cy="151.9" r=".33"/>
</g>
<path d="M239.4 144.6v.3" fill="none" stroke="#fff" stroke-width=".65"/>
<path d="M240.3 152.4h.6M240.3 144.2h.6M246.3 152.8h.6M246.3 143.8h.6" fill="none" stroke="#fff" stroke-width=".5"/>
<g fill="#fff">
<circle cx="178.9" cy="130.3" r=".5"/>
<circle cx="181.5" cy="130.3" r=".5"/>
<circle cx="213.9" cy="168.2" r=".5"/>
<circle cx="211.4" cy="168.2" r=".5"/>
<circle cx="208.8" cy="168.2" r=".5"/>
<circle cx="241.3" cy="127.1" r=".25"/>
<circle cx="242" cy="125.4" r=".25"/>
<circle cx="242" cy="128.8" r=".25"/>
<circle cx="243.7" cy="124.7" r=".25"/>
<circle cx="243.7" cy="127.1" r="1.6"/>
<circle cx="243.7" cy="129.5" r=".25"/>
<circle cx="245.4" cy="125.4" r=".25"/>
<circle cx="245.4" cy="128.8" r=".25"/>
<circle cx="246.1" cy="127.1" r=".25"/>
<circle cx="169.3" cy="167.1" r=".25"/>
<circle cx="170" cy="165.4" r=".25"/>
<circle cx="170" cy="168.8" r=".25"/>
<circle cx="171.7" cy="164.7" r=".25"/>
<circle cx="171.7" cy="167.1" r="1.6"/>
<circle cx="171.7" cy="169.5" r=".25"/>
<circle cx="173.4" cy="165.4" r=".25"/>
<circle cx="173.4" cy="168.8" r=".25"/>
<circle cx="174.1" cy="167.1" r=".25"/>
<circle cx="192.6" cy="167.3" r=".45"/>
<circle cx="195.6" cy="167.3" r=".45"/>
<circle cx="213.5" cy="125.9" r=".5"/>
<circle cx="213.5" cy="128.4" r=".5"/>
<circle cx="213.5" cy="131" r=".5"/>
<circle cx="169.3" cy="127.1" r=".25"/>
<circle cx="170" cy="125.4" r=".25"/>
<circle cx="170" cy="128.8" r=".25"/>
<circle cx="171.7" cy="124.7" r=".25"/>
<circle cx="171.7" cy="127.1" r="1.6"/>
<circle cx="171.7" cy="129.5" r=".25"/>
<circle cx="173.4" cy="125.4" r=".25"/>
<circle cx="173.4" cy="128.8" r=".25"/>
<circle cx="174.1" cy="127.1" r=".25"/>
</g>
<g fill="none" stroke="#000" stroke-width=".2">
<path d="M10 10h400v277h-400zM12 12h396v273h-396zM35.3 11.6h.8M35.3 10.7l.4-.4v1.3M60 10v2M85.3 10.4l.5-.1 .3 .4-.8 .9h.8M110 10v2M135.3 10.3h.8l-.4 .5 .3 .1v.6l-.2 .1-.5-.1M160 10v2M185.7 10.2l-.4 1h.9M186 10.7v.9M210 10v2"/>
<path d="M236 10.3h-.6l-.1 .6 .2-.1 .5 .1 .1 .1-.1 .5-.2 .1-.5-.1M260 10v2M286 10.3l-.4 .1-.2 .2-.1 .7 .3 .3 .4-.1 .1-.5-.1-.1-.4-.1-.3 .2M310 10v2M335.3 10.3h.9l-.6 1.3M360 10v2M385.6 10.9l-.3 .2 .1 .4 .2 .1 .4-.1 .1-.2-.1-.3-.2-.1M385.6 10.9l-.3-.3 .3-.3h.2l.3 .2-.3 .4M385.6 10.9h.2M10.6 35.6l.4-1.3 .4 1.3M10.7 35.2h.6M408.6 35.6l.4-1.3 .4 1.3"/>
<path d="M408.7 35.2h.6M10 60h2M408 60h2M10.7 84.3h.4l.2 .2-.2 .4 .2 .1 .1 .3-.2 .3h-.5zM10.7 84.9h.4M408.6 84.3h.5l.2 .2-.2 .4 .2 .1 .1 .3-.3 .3h-.5zM408.6 84.9h.5M10 110h2M408 110h2M11.4 134.4a.62 .62 0 0 0-.9 .5 .62 .62 0 0 0 .7 .7l.2-.1M409.4 134.4a.62 .62 0 0 0-.9 .5 .62 .62 0 0 0 .6 .7l.3-.1M10 160h2"/>
<path d="M408 160h2M10.7 184.3a.66 .66 0 0 1 .7 .6 .66 .66 0 0 1-.7 .7zM408.6 184.3a.66 .66 0 0 1 .8 .6 .66 .66 0 0 1-.8 .7zM10 210h2M408 210h2M10.7 234.9h.5M11.3 234.3h-.6v1.3h.6M408.7 234.9h.4M409.3 234.3h-.6v1.3h.6M10 260h2M408 260h2M10.8 284.9h.4"/>
<path d="M11.4 284.3h-.6v1.3M35.3 285.7l.4-.4v1.3M35.3 286.6h.8M60 285v2M85.3 285.4l.5-.1 .3 .4-.8 .9h.8M110 285v2M135.3 285.3h.8l-.4 .5 .3 .1v.6l-.2 .1-.5-.1M160 285v2M185.7 285.2l-.4 1h.9M186 285.7v.9M210 285v2M236 285.3h-.6l-.1 .6 .2-.1 .5 .1 .1 .1-.1 .5-.2 .1-.5-.1"/>
<path d="M260 285v2M286 285.3l-.4 .1-.2 .2-.1 .7 .3 .3 .4-.1 .1-.5-.1-.1-.4-.1-.3 .2M310 285v2M335.3 285.3h.9l-.6 1.3M360 285v2M385.6 285.9l-.3-.3 .3-.3h.2l.3 .2-.3 .4M385.6 285.9l-.3 .2v.2l.3 .3 .4-.1 .1-.2v-.2l-.3-.2M385.6 285.9h.2M408.7 284.9h.5M409.4 284.3h-.7v1.3"/>
</g>
<path d="M384.7 279.7h1.4l-.8 2.4h-.3l.6-1.9h-.8l-.3 .2z" fill-rule="evenodd" fill="#00007f"/>
<g fill="#00f">
<path d="M384.3 275.7l.7-.1 .2 .4-.1 .1a.32 .32 0 0 0-.4-.4 .32 .32 0 0 0-.3 .5h.3a.5 .5 0 0 1 .6 .6 .5 .5 0 0 1-.8 .3l-.4-.3v-.2h.2a.39 .39 0 0 0 .4 .4 .39 .39 0 0 0 .4-.4l-.9-.4v-.2z" fill-rule="evenodd"/>
<path d="M385.5 275.6h.2v.6l.3-.2 .4 .2v.9h-.2v-.7a.27 .27 0 0 0-.3-.2 .27 .27 0 0 0-.2 .3v.6h-.2z" fill-rule="evenodd"/>
<path d="M386.8 276.2a.51 .51 0 0 1 .6-.1 .51 .51 0 0 1 .2 .5h-.8l.3 .4 .5-.2a.52 .52 0 0 1-.6 .3 .52 .52 0 0 1-.3-.6h.8l-.3-.3-.4 .3h-.1z" fill-rule="evenodd"/>
<path d="M388 276.2a.51 .51 0 0 1 .6-.1 .51 .51 0 0 1 .2 .5h-.8l.2 .4 .6-.2a.52 .52 0 0 1-.6 .3 .52 .52 0 0 1-.4-.6h.8l-.3-.3-.3 .3h-.2z" fill-rule="evenodd"/>
<path d="M389.1 275.8l.2-.1v.3h.1v.2h-.1v.6l.2 .3a.27 .27 0 0 1-.3 0 .27 .27 0 0 1-.1-.3v-.6h-.2z" fill-rule="evenodd"/>
<path d="M389.7 276h.2v.2h-.2z" fill-rule="evenodd"/>
<path d="M389.7 276.9h.2v.2h-.2z" fill-rule="evenodd"/>
<path d="M392.7 281.1a.54 .54 0 0 1 .9 .1 .54 .54 0 0 1-.3 .8 .54 .54 0 0 1-.7-.4h.2a.37 .37 0 0 0 .5 .4 .37 .37 0 0 0 0-.7l-.3-.1-.2 .4h-.2z" fill-rule="evenodd"/>
<path d="M393.9 280.7l.4-.1v.2l-.3 .1 .2 .3h-.2v.9h-.2v-.9h-.1z" fill-rule="evenodd"/>
</g>
<g fill="#00007f">
<path d="M396.2 280.1l.9-.4v2.1l.4 .2h-1.2l.3-.1v-1.5v-.3z" fill-rule="evenodd"/>
<path d="M398.1 279.9a.73 .73 0 0 1 .9-.1 .73 .73 0 0 1 .3 .8 1.04 1.04 0 0 1-.8 1.5 .95 .95 0 0 1-.6-1h.5v.7a.2 .2 0 0 0 .2 .2 .2 .2 0 0 0 .2-.3v-1.7a.2 .2 0 0 0-.2-.2 .2 .2 0 0 0-.2 .2v1.1h-.5v-.7z" fill-rule="evenodd"/>
</g>
<g fill="#00f">
<path d="M368.3 275.7l.7-.1 .2 .4-.1 .1a.32 .32 0 0 0-.4-.4 .32 .32 0 0 0-.3 .5h.3a.5 .5 0 0 1 .6 .6 .5 .5 0 0 1-.8 .3l-.4-.3v-.2h.2a.39 .39 0 0 0 .4 .4 .39 .39 0 0 0 .4-.4l-.9-.4v-.2z" fill-rule="evenodd"/>
<path d="M369.5 275.6h.2v.2h-.2z" fill-rule="evenodd"/>
<path d="M369.5 276h.2v1.1h-.2z" fill-rule="evenodd"/>
<path d="M369.9 276h.9l-.7 1h.8v.1h-1l.7-.9h-.7z" fill-rule="evenodd"/>
<path d="M371.1 276.2a.51 .51 0 0 1 .6-.1 .51 .51 0 0 1 .3 .5h-.8l.2 .4 .6-.2a.52 .52 0 0 1-.7 .3 .52 .52 0 0 1-.3-.6h.8l-.3-.3-.3 .3h-.2z" fill-rule="evenodd"/>
<path d="M372.3 276h.2v.2h-.2z" fill-rule="evenodd"/>
<path d="M372.3 276.9h.2v.2h-.2z" fill-rule="evenodd"/>
</g>
<g fill="#00007f">
<path d="M370.3 279.7l.9 2.1 .3 .2h-1.1l.2-.1-.1-.5h-.9l-.1 .5 .3 .1h-.8l.6-.8h.8l-.3-.7-.4 .7h-.1z" fill-rule="evenodd"/>
<path d="M371.9 279.9a.55 .55 0 0 1 .8-.2 .55 .55 0 0 1 0 .9 .81 .81 0 0 1 .1 1.2 .81 .81 0 0 1-1.2 0l.2-.2a.54 .54 0 0 0 .8 .2 .72 .72 0 0 0-.6-1 .41 .41 0 0 0 .5-.3 .41 .41 0 0 0-.3-.5 .41 .41 0 0 0-.5 .3z" fill-rule="evenodd"/>
</g>
<path d="M366.5 274.5h41.5M382.5 274.5v10.5M408 264h-41.5v21" fill="none" stroke="#000" stroke-width=".2"/>
<g fill="#00f">
<path d="M384.2 265.1h.6a.42 .42 0 0 1 .6 .4 .42 .42 0 0 1-.5 .4l.6 .7h-.3l-.4-.6h-.2h-.2v.6h-.2v-.8l.9-.1a.25 .25 0 0 0 0-.3 .25 .25 0 0 0-.3-.1h-.4v.5h-.2z" fill-rule="evenodd"/>
<path d="M385.7 265.7l.1-.1a.51 .51 0 0 1 .6 0 .51 .51 0 0 1 .2 .5h-.8l.2 .4 .6-.2a.52 .52 0 0 1-.7 .3 .52 .52 0 0 1-.3-.6h.8l-.3-.3-.3 .3h-.2z" fill-rule="evenodd"/>
<path d="M386.7 265.5h.2l.3 .9 .3-.9h.2l-.4 1.1h-.2z" fill-rule="evenodd"/>
<path d="M387.9 265.1h.2v.2h-.2z" fill-rule="evenodd"/>
<path d="M387.9 265.5h.2v1.1h-.2z" fill-rule="evenodd"/>
<path d="M388.4 265.6l.5-.1 .2 .3h-.2a.21 .21 0 0 0-.2-.2 .21 .21 0 0 0-.1 .3 .43 .43 0 0 1 .4 .1 .43 .43 0 0 1 .1 .4l-.2 .2h-.4l-.2-.3h.1a.24 .24 0 0 0 .3 .3 .24 .24 0 0 0 .2-.4 .43 .43 0 0 1-.6-.5z" fill-rule="evenodd"/>
<path d="M389.4 265.1h.2v.2h-.2z" fill-rule="evenodd"/>
<path d="M389.4 265.5h.2v1.1h-.2z" fill-rule="evenodd"/>
<path d="M390 265.6a.54 .54 0 0 1 .8 .1 .54 .54 0 0 1-.3 .8 .54 .54 0 0 1-.7-.4h.2a.37 .37 0 0 0 .5 .4 .37 .37 0 0 0 .1-.7l-.4-.1-.2 .4h-.2z" fill-rule="evenodd"/>
<path d="M391 265.5h.2v.2l.3-.2a.35 .35 0 0 1 .4 .5v.6h-.2v-.6a.27 .27 0 0 0-.3-.3 .27 .27 0 0 0-.2 .3v.6h-.2z" fill-rule="evenodd"/>
<path d="M392.2 265.5h.2v.2h-.2z" fill-rule="evenodd"/>
<path d="M392.2 266.4h.2v.2h-.2z" fill-rule="evenodd"/>
</g>
<g fill="#00007f">
<path d="M384 270.4h.5l.1-.5v.5l.5 .1h-.5l-.1 .5v-.5z" fill-rule="evenodd"/>
<path d="M386.1 269.8l.3-.1a1.42 1.42 0 0 0 0 1.9l-.5-.6a1.13 1.13 0 0 1 .2-1.2z" fill-rule="evenodd"/>
<path d="M386.4 269.7h.6l-.2 .2v.7a.41 .41 0 0 0 .4 .5 .41 .41 0 0 0 .4-.6v-.7l-.2-.1h.5l-.2 .2v.6a.55 .55 0 0 1-.6 .7 .55 .55 0 0 1-.5-.7v-.7z" fill-rule="evenodd"/>
<path d="M387.9 270.3l.4-.1v.2a.29 .29 0 0 1 .3-.2 .29 .29 0 0 1 .2 .3v.5l.2 .1h-.5l.2-.2-.1-.5-.1-.1-.2 .1v.6l.1 .1h-.4l.1-.1v-.6z" fill-rule="evenodd"/>
<path d="M389 270.3l.3-.1v.2l.2-.2h.2l-.4 .3v.5l.2 .1h-.5l.1-.1v-.6z" fill-rule="evenodd"/>
<path d="M389.9 270.3l.4-.1 .2 .2v.1h-.6l.2 .4 .3 .1 .1-.2a.41 .41 0 0 1-.6 .3 .41 .41 0 0 1-.1-.6h.5l-.2-.3-.3 .3z" fill-rule="evenodd"/>
<path d="M390.7 269.8l.3-.1v1.3l.1 .1h-.4l.1-.1v-.9v-.3z" fill-rule="evenodd"/>
<path d="M391.4 270.3l.4-.1 .2 .2 .1 .1h-.7l.2 .4 .3 .1 .1-.2a.41 .41 0 0 1-.5 .3 .41 .41 0 0 1-.2-.6h.5l-.2-.3-.3 .3z" fill-rule="evenodd"/>
<path d="M392.3 270.2l.5 .1 .1 .7 .1-.1-.1 .2-.2-.1-.2 .1h-.2l-.1-.2 .3 .1 .2-.1v-.3l-.5 .3 .5-.4-.2-.3-.2 .3z" fill-rule="evenodd"/>
<path d="M393.2 270.2h.5v.3l-.2-.3-.2 .1 .1 .2a.34 .34 0 0 1 .4 .5 .34 .34 0 0 1-.6 .1v-.3l.2 .3 .2-.2-.4-.4z" fill-rule="evenodd"/>
<path d="M394.1 270.3l.4-.1 .2 .2v.1h-.6l.1 .4 .3 .1 .2-.2a.41 .41 0 0 1-.6 .3 .41 .41 0 0 1-.1-.6h.5l-.2-.3-.3 .3z" fill-rule="evenodd"/>
<path d="M395.4 269.8l.3-.1v1.3h.2l-.6 .2-.4-.2v-.4h.2l.1 .4 .3-.1-.1-.7-.3 .1v.3h-.2v-.1a.41 .41 0 0 1 .6-.3v-.4z" fill-rule="evenodd"/>
<path d="M395.9 269.7a1.08 1.08 0 0 1 0 1.9 1.42 1.42 0 0 0 0-1.9z" fill-rule="evenodd"/>
</g>
<path d="M382.5 264v10.5" fill="none" stroke="#000" stroke-width=".2"/>
<g fill="#00f">
<path d="M368.2 265.1h.5a.75 .75 0 0 1 .7 .8 .75 .75 0 0 1-.7 .7h-.5v-.2h.5a.58 .58 0 0 0 .5-.5 .58 .58 0 0 0-.5-.6h-.3v1.1h-.2z" fill-rule="evenodd"/>
<path d="M369.7 265.6l.2-.1a.47 .47 0 0 1 .5 .1 .47 .47 0 0 1 .1 .6l.1 .4-.2-.1-.5 .1-.3-.1v-.2l.6 .2 .1-.4-.7 .2a.57 .57 0 0 1 .7-.4l-.1-.2-.6 .1z" fill-rule="evenodd"/>
<path d="M370.9 265.3l.1-.1v.3h.2v.2h-.2v.6l.2 .3a.27 .27 0 0 1-.3 0 .27 .27 0 0 1 0-.3v-.6h-.2z" fill-rule="evenodd"/>
<path d="M371.5 265.7l.1-.1a.51 .51 0 0 1 .5 0 .51 .51 0 0 1 .2 .5h-.8l.3 .4 .5-.2a.52 .52 0 0 1-.6 .3 .52 .52 0 0 1-.4-.6h.9l-.3-.3-.4 .3h-.2z" fill-rule="evenodd"/>
<path d="M372.6 265.5h.2v.2h-.2z" fill-rule="evenodd"/>
<path d="M372.6 266.4h.2v.2h-.2z" fill-rule="evenodd"/>
</g>
<path d="M408 253.5h-41.5v10.5" fill="none" stroke="#000" stroke-width=".2"/>
<g fill="#00f">
<path d="M368.2 254.6h.5a.46 .46 0 0 1 .6 .5 .46 .46 0 0 1-.6 .4h-.3v.6h-.2v-.8h.7l.2-.2-.2-.3h-.5v.5h-.2z" fill-rule="evenodd"/>
<path d="M369.5 255h.2v.2l.4-.2v.2a.24 .24 0 0 0-.3 .1 .24 .24 0 0 0-.1 .3v.5h-.2z" fill-rule="evenodd"/>
<path d="M370.3 255.1a.55 .55 0 0 1 .9 .1 .55 .55 0 0 1-.3 .8 .55 .55 0 0 1-.7-.4h.2a.37 .37 0 0 0 .5 .4 .37 .37 0 0 0 0-.7l-.3-.1-.2 .4h-.2z" fill-rule="evenodd"/>
<path d="M371.4 254.6h.2v.2h-.2z" fill-rule="evenodd"/>
<path d="M371.4 255h.2v1.2a.3 .3 0 0 1-.1 .3 .3 .3 0 0 1-.3 0l.2-.2z" fill-rule="evenodd"/>
<path d="M371.9 255.2a.51 .51 0 0 1 .7-.1 .51 .51 0 0 1 .2 .5h-.8l.2 .4 .6-.2a.52 .52 0 0 1-.6 .3 .52 .52 0 0 1-.4-.6h.8l-.3-.3-.3 .3h-.2z" fill-rule="evenodd"/>
<path d="M373.1 255.1h.6l.2 .3h-.2a.34 .34 0 0 0-.5-.2 .34 .34 0 0 0 0 .6l.3 .2 .2-.3h.2a.53 .53 0 0 1-.8 .3 .53 .53 0 0 1 0-.8z" fill-rule="evenodd"/>
<path d="M374.1 254.8l.2-.1v.3h.2v.2h-.2v.6l.2 .3a.27 .27 0 0 1-.3 0 .27 .27 0 0 1-.1-.3v-.6h-.1z" fill-rule="evenodd"/>
<path d="M375.3 254.6h.2l.8 1.2v-1.2h.2v1.5h-.2l-.8-1.2v1.2h-.2z" fill-rule="evenodd"/>
<path d="M376.9 255.1l.1-.1a.47 .47 0 0 1 .6 .1 .47 .47 0 0 1 0 .6l.1 .4-.2-.1-.5 .1-.3-.1v-.2l.6 .2 .2-.4-.8 .2a.57 .57 0 0 1 .8-.4l-.2-.2-.6 .1z" fill-rule="evenodd"/>
<path d="M377.9 255h.2v.2l.3-.2 .3 .2 .3-.2 .3 .1 .1 1h-.2l-.1-.9a.26 .26 0 0 0-.2 0 .26 .26 0 0 0-.1 .3v.6h-.2v-.8l-.4-.1-.1 .9h-.2z" fill-rule="evenodd"/>
<path d="M379.8 255.2a.51 .51 0 0 1 .6-.1 .51 .51 0 0 1 .2 .5h-.8l.3 .4 .5-.2a.52 .52 0 0 1-.6 .3 .52 .52 0 0 1-.4-.6h.8l-.3-.3-.3 .3h-.2z" fill-rule="evenodd"/>
<path d="M380.9 255h.2v.2h-.2z" fill-rule="evenodd"/>
<path d="M380.9 255.9h.2v.2h-.2z" fill-rule="evenodd"/>
</g>
<g fill="#00007f">
<path d="M368.2 269.8a.42 .42 0 0 1 .6 .1 .42 .42 0 0 1-.1 .6l-.4 .5 .7-.1-.1 .2h-.9a.88 .88 0 0 0 .6-1.2h-.2l-.3 .2z" fill-rule="evenodd"/>
<path d="M369.3 269.8l.2-.1a.7 .7 0 0 1 .5 .7 .7 .7 0 0 1-.6 .7l-.3-.5 .2-.1a.36 .36 0 0 0 0 .4 .36 .36 0 0 0 .4 .1l.1-.8-.2-.4a.42 .42 0 0 0-.3 .7l-.2-.1z" fill-rule="evenodd"/>
<path d="M370.3 269.8a.42 .42 0 0 1 .6 .1 .42 .42 0 0 1-.1 .6l-.4 .5 .7-.1-.1 .2h-.9a.88 .88 0 0 0 .6-1.2h-.2l-.3 .2z" fill-rule="evenodd"/>
<path d="M371.6 269.7h.5l-.1 .2h-.4l-.1 .2a.5 .5 0 0 1 .5 .6 .5 .5 0 0 1-.7 .3 .4 .4 0 0 0 .6-.2 .4 .4 0 0 0-.5-.5h-.1z" fill-rule="evenodd"/>
<path d="M372.3 270.6h.5v.1h-.5z" fill-rule="evenodd"/>
<path d="M373.2 269.8l.1-.1a.7 .7 0 0 1 .6 .7 .7 .7 0 0 1-.6 .7l-.3-.5 .2-.1a.36 .36 0 0 0-.1 .4 .36 .36 0 0 0 .4 .1l.2-.6-.2-.6a.42 .42 0 0 0-.3 .7l-.2-.1z" fill-rule="evenodd"/>
<path d="M374.2 269.7h.7l-.5 1.4h-.1l.4-1.2h-.5l-.1 .2z" fill-rule="evenodd"/>
<path d="M375.1 270.6h.5v.1h-.5z" fill-rule="evenodd"/>
<path d="M375.9 269.9l.4-.2v1.3l.2 .1h-.5l.1-.1v-1z" fill-rule="evenodd"/>
<path d="M377 269.8h.4a.31 .31 0 0 1 0 .5 .44 .44 0 0 1 .1 .7 .44 .44 0 0 1-.6 0 .35 .35 0 0 0 .5-.1 .35 .35 0 0 0-.3-.5 .28 .28 0 0 0 .3-.2 .28 .28 0 0 0-.2-.3 .28 .28 0 0 0-.3 .1z" fill-rule="evenodd"/>
</g>
<g fill="#00f">
<path d="M341.2 275.6h.6a.42 .42 0 0 1 .6 .4 .42 .42 0 0 1-.5 .4l.6 .7h-.3a.74 .74 0 0 0-.8-.6v.6h-.2v-.8l.9-.1a.25 .25 0 0 0 0-.3 .25 .25 0 0 0-.3-.1h-.4v.5h-.2z" fill-rule="evenodd"/>
<path d="M342.7 276.2a.51 .51 0 0 1 .6-.1 .51 .51 0 0 1 .3 .5h-.8l.2 .4 .6-.2a.52 .52 0 0 1-.7 .3 .52 .52 0 0 1-.3-.6h.8l-.3-.3-.3 .3h-.2z" fill-rule="evenodd"/>
<path d="M343.7 276h.2l.3 .9 .3-.9h.2l-.4 1.1h-.2z" fill-rule="evenodd"/>
<path d="M344.9 275.6h.2v.2h-.2z" fill-rule="evenodd"/>
<path d="M344.9 276h.2v1.1h-.2z" fill-rule="evenodd"/>
<path d="M345.4 276.2a.51 .51 0 0 1 .6-.1 .51 .51 0 0 1 .3 .5h-.8l.2 .4 .6-.2a.52 .52 0 0 1-.7 .3 .52 .52 0 0 1-.3-.6h.8l-.3-.3-.3 .3h-.2z" fill-rule="evenodd"/>
<path d="M346.4 276h.2l.2 .9 .2-.9h.2l.2 .9 .3-.9h.2l-.4 1.1h-.2l-.2-.8-.2 .8h-.2z" fill-rule="evenodd"/>
<path d="M348.1 276.2a.51 .51 0 0 1 .6-.1 .51 .51 0 0 1 .3 .5h-.9l.3 .4 .6-.2a.52 .52 0 0 1-.7 .3 .52 .52 0 0 1-.3-.6h.8l-.3-.3-.3 .3h-.2z" fill-rule="evenodd"/>
<path d="M349.2 276h.1v.2l.4-.2v.2a.24 .24 0 0 0-.3 .1 .24 .24 0 0 0 0 .3v.5h-.2z" fill-rule="evenodd"/>
<path d="M349.9 276h.2v.2h-.2z" fill-rule="evenodd"/>
<path d="M349.9 276.9h.2v.2h-.2z" fill-rule="evenodd"/>
</g>
<path d="M332 274.5h34.5M339.5 274.5v10.5" fill="none" stroke="#000" stroke-width=".2"/>
<g fill="#00f">
<path d="M341.2 265.1h.5a.75 .75 0 0 1 .7 .8 .75 .75 0 0 1-.7 .7h-.5v-.2h.5a.58 .58 0 0 0 .5-.5 .58 .58 0 0 0-.5-.6h-.3v1.1h-.2z" fill-rule="evenodd"/>
<path d="M342.7 265.7l.1-.1a.51 .51 0 0 1 .6 0 .51 .51 0 0 1 .2 .5h-.8l.2 .4 .6-.2a.52 .52 0 0 1-.7 .3 .52 .52 0 0 1-.3-.6h.8l-.3-.3-.3 .3h-.2z" fill-rule="evenodd"/>
<path d="M343.8 265.6l.6-.1 .2 .3h-.2a.21 .21 0 0 0-.2-.2 .21 .21 0 0 0-.2 .3 .43 .43 0 0 1 .5 .1 .43 .43 0 0 1 .1 .4l-.2 .2h-.4l-.3-.3h.2a.24 .24 0 0 0 .3 .3 .24 .24 0 0 0 .2-.4 .43 .43 0 0 1-.6-.5z" fill-rule="evenodd"/>
<path d="M344.9 265.1h.2v.2h-.2z" fill-rule="evenodd"/>
<path d="M344.9 265.5h.2v1.1h-.2z" fill-rule="evenodd"/>
<path d="M345.4 265.6l.3-.1 .4 .2v-.2h.1v1a.48 .48 0 0 1-.3 .5 .48 .48 0 0 1-.6-.3l.5 .2 .2-.1v-.3a.47 .47 0 0 1-.5 0 .47 .47 0 0 1-.2-.4h.2a.34 .34 0 0 0 .4 .3 .34 .34 0 0 0 .1-.5 .3 .3 0 0 0-.3-.2 .3 .3 0 0 0-.2 .4h-.2z" fill-rule="evenodd"/>
<path d="M346.5 265.5h.2v.2l.3-.2a.35 .35 0 0 1 .4 .5v.6h-.2v-.6a.27 .27 0 0 0-.3-.3 .27 .27 0 0 0-.2 .3v.6h-.2z" fill-rule="evenodd"/>
<path d="M347.7 265.7l.1-.1a.51 .51 0 0 1 .6 0 .51 .51 0 0 1 .2 .5h-.8l.2 .4 .6-.2a.52 .52 0 0 1-.6 .3 .52 .52 0 0 1-.4-.6h.8l-.3-.3-.3 .3h-.2z" fill-rule="evenodd"/>
<path d="M348.8 265.5h.2v.2l.4-.2v.2a.24 .24 0 0 0-.3 .1 .24 .24 0 0 0-.1 .3v.5h-.2z" fill-rule="evenodd"/>
<path d="M349.6 265.5h.2v.2h-.2z" fill-rule="evenodd"/>
<path d="M349.6 266.4h.2v.2h-.2z" fill-rule="evenodd"/>
</g>
<path d="M332 264h34.5M339.5 264v10.5" fill="none" stroke="#000" stroke-width=".2"/>
<g fill="#00007f">
<path d="M341 269.7h.6a.7 .7 0 0 1 .8 .7 .7 .7 0 0 1-.7 .7h-.7l.2-.1v-1.2h.2v1.2a.65 .65 0 0 0 .8-.7 .65 .65 0 0 0-1-.5z" fill-rule="evenodd"/>
<path d="M342.7 270.2l.5 .1 .1 .7 .1-.1-.1 .2-.7-.1v-.1l.3 .1 .2-.1v-.3l-.5 .3 .5-.4-.2-.3-.3 .3z" fill-rule="evenodd"/>
<path d="M343.5 270.3l.3-.1v.2a.29 .29 0 0 1 .3-.2 .29 .29 0 0 1 .2 .3v.5l.2 .1h-.5l.2-.2v-.5l-.2-.1-.2 .1v.6l.1 .1h-.4l.1-.1v-.6z" fill-rule="evenodd"/>
<path d="M344.6 270.3l.3-.1v.8l.1 .1h-.4l.1-.1v-.5z" fill-rule="evenodd"/>
<path d="M345.3 270.3l.4-.1 .2 .2 .1 .1h-.7l.2 .4 .3 .1 .1-.2a.41 .41 0 0 1-.5 .3 .41 .41 0 0 1-.2-.6h.5l-.2-.3-.3 .3z" fill-rule="evenodd"/>
<path d="M346.1 269.8l.3-.1v1.3l.2 .1h-.5l.1-.1v-1.1z" fill-rule="evenodd"/>
<path d="M347.2 269.7h.5l-.1 .1-.1 .6 .6-.5-.1-.2h.5l-.8 .7 1 .7h-.7l.1-.1-.6-.6 .1 .6 .1 .1h-.5l.2-.2-.1-1z" fill-rule="evenodd"/>
<path d="M348.8 270.2l.6 .1v.7l.2-.1-.2 .2-.7-.1v-.1l.3 .1 .2-.1v-.3l-.5 .3 .5-.4-.1-.3-.3 .3z" fill-rule="evenodd"/>
<path d="M349.6 270.3l.3-.1v.2l.3-.2 .3 .2a.3 .3 0 0 1 .3-.2 .3 .3 0 0 1 .2 .3l.1 .5 .1 .1h-.5l.2-.1v-.5a.2 .2 0 0 0-.2-.2 .2 .2 0 0 0-.2 .2v.5l.1 .1h-.4l.1-.1v-.5l-.1-.2-.3 .1v.6l.2 .1h-.5l.1-.1v-.5z" fill-rule="evenodd"/>
<path d="M351.2 270.3l.3-.1v.2a.39 .39 0 0 1 .6-.1 .39 .39 0 0 1 0 .5l-.2 .3h-.4v.4l.2 .1h-.5l.2-.2v-1h.1l.1 .6a.33 .33 0 0 0 .4-.3 .33 .33 0 0 0-.4-.3h-.2z" fill-rule="evenodd"/>
<path d="M352.4 270.3l.4-.1 .3 .2v.1h-.6l.1 .4 .3 .1 .2-.2a.41 .41 0 0 1-.6 .3 .41 .41 0 0 1-.1-.6h.5l-.2-.3-.3 .3z" fill-rule="evenodd"/>
<path d="M353.2 270.3l.3-.1v.2l.2-.2h.2l-.4 .3v.5l.2 .1h-.5l.1-.1 .1-.5z" fill-rule="evenodd"/>
<path d="M354.2 269.9v.3h.2h-.2v.7h.3l-.3 .2-.1-.1-.1-.8h-.1z" fill-rule="evenodd"/>
<circle cx="344.8" cy="269.8" r=".1"/>
</g>
<path d="M332 264h-34.5v10.5h34.5" fill="none" stroke="#000" stroke-width=".2"/>
<g fill="#00007f">
<path d="M299.2 269.7h1l-.9 1.3h.7l.2-.3v.4h-1.2l.9-1.3h-.6l-.2 .3z" fill-rule="evenodd"/>
<path d="M300.5 269.8l.7-.1v.5a.29 .29 0 0 0-.3-.4 .29 .29 0 0 0-.2 .4h.1a.49 .49 0 0 1 .5 .3 .49 .49 0 0 1-.2 .6l-.7 .1 .1-.5a.33 .33 0 0 0 .3 .4 .33 .33 0 0 0 .3-.4l-.1-.1a.51 .51 0 0 1-.5-.2 .51 .51 0 0 1 0-.6z" fill-rule="evenodd"/>
<path d="M301.5 269.7h.5l-.1 .2 .3 .9 .2-.7-.3-.4h.6l-.2 .2 .3 .9 .3-.9-.1-.2h.4l-.6 1.5-.3-.9-.4 .9z" fill-rule="evenodd"/>
<path d="M303.5 270.2l.5 .1v.7l.2-.1-.1 .2-.7-.1-.1-.1 .4 .1 .2-.1v-.3l-.6 .3 .6-.4-.2-.3-.3 .3z" fill-rule="evenodd"/>
<path d="M304.5 269.9v.3h.3h-.3v.7h.3l-.3 .2-.1-.1v-.8h-.2z" fill-rule="evenodd"/>
<path d="M305 270.3l.4-.1 .2 .1-.1 .2a.28 .28 0 0 0-.4-.3 .28 .28 0 0 0-.1 .5l.3 .3 .3-.2a.43 .43 0 0 1-.6 .3 .43 .43 0 0 1-.1-.7z" fill-rule="evenodd"/>
<path d="M305.7 269.8l.3-.1v.7l.3-.2h.2l.1 .8 .1 .1h-.4l.1-.2v-.5l-.1-.1-.3 .1 .1 .6 .1 .1h-.5l.2-.1v-.9z" fill-rule="evenodd"/>
<path d="M306.8 270.6h.6v.1h-.6z" fill-rule="evenodd"/>
<path d="M307.5 269.7h.6a.7 .7 0 0 1 .8 .7 .7 .7 0 0 1-.8 .7h-.6l.2-.1v-1.2h.2v1.2a.65 .65 0 0 0 .7-.7 .65 .65 0 0 0-.9-.5z" fill-rule="evenodd"/>
<path d="M309.2 270.3a.46 .46 0 0 1 .7 .1 .46 .46 0 0 1-.3 .7 .46 .46 0 0 1-.6-.5h.2a.34 .34 0 0 0 .1 .4 .34 .34 0 0 0 .5-.1 .34 .34 0 0 0-.1-.4l-.2-.3-.3 .4h-.2z" fill-rule="evenodd"/>
<path d="M310.2 270.3l.4-.1 .2 .1v.2a.28 .28 0 0 0-.4-.3 .28 .28 0 0 0-.1 .5l.2 .3 .4-.2a.43 .43 0 0 1-.7 .3 .43 .43 0 0 1 0-.7z" fill-rule="evenodd"/>
<path d="M311 269.8l.3-.1v.9l.3-.3v-.1h.4l-.5 .3 .5 .6h-.4l-.3-.5v.4l.1 .1h-.4l.1-.2v-1z" fill-rule="evenodd"/>
<path d="M312.5 269.8l.4-.1v.9l.3-.3-.1-.1h.4l-.5 .3 .6 .6h-.5l-.2-.5v.4l.1 .1h-.5l.2-.2v-1z" fill-rule="evenodd"/>
<path d="M313.6 270.3l.4-.1v.8l.1 .1h-.4l.1-.1v-.5z" fill-rule="evenodd"/>
<path d="M314.4 270.3l.4-.1 .2 .1-.1 .2a.28 .28 0 0 0-.4-.3 .28 .28 0 0 0-.1 .5l.2 .3 .4-.2a.43 .43 0 0 1-.6 .3 .43 .43 0 0 1-.1-.7z" fill-rule="evenodd"/>
<path d="M315.3 270.2l.5 .1 .1 .7 .1-.1-.1 .2-.7-.1v-.1l.3 .1 .2-.1v-.3l-.5 .3 .5-.4-.2-.3-.3 .3z" fill-rule="evenodd"/>
<path d="M316.6 269.8l.3-.1v1.3h.2l-.6 .2-.3-.2-.1-.4h.2l.2 .4 .3-.1-.2-.7-.2 .1-.1 .3h-.2v-.1a.41 .41 0 0 1 .7-.3l-.1-.4z" fill-rule="evenodd"/>
<path d="M317.1 271.5l1 .1z" fill-rule="evenodd"/>
<path d="M318.1 270.3l.3-.1v.2a.39 .39 0 0 1 .6-.1 .39 .39 0 0 1 .1 .5l-.3 .3h-.4l.1 .4 .1 .1h-.5l.2-.2v-1h.1l.1 .6a.33 .33 0 0 0 .4-.3 .33 .33 0 0 0-.4-.3h-.2z" fill-rule="evenodd"/>
<path d="M319.4 270.3l.4-.1 .2 .1-.1 .2a.28 .28 0 0 0-.4-.3 .28 .28 0 0 0-.1 .5l.2 .3 .4-.2a.43 .43 0 0 1-.6 .3 .43 .43 0 0 1-.1-.7z" fill-rule="evenodd"/>
<path d="M320.1 269.8l.3-.1v.6a.45 .45 0 0 1 .7 .3 .45 .45 0 0 1-.5 .6l-.3-.2v-.6h.1v.6a.32 .32 0 0 0 .5-.3 .32 .32 0 0 0-.5-.3h-.1v-.5z" fill-rule="evenodd"/>
<circle cx="312.3" cy="271" r=".11"/>
<circle cx="313.9" cy="269.8" r=".1"/>
</g>
<path d="M366.5 253.5h-69v10.5" fill="none" stroke="#000" stroke-width=".2"/>
<g fill="#00f">
<path d="M299.2 254.6l.9 .1 .1 .3-.2 .3a.42 .42 0 0 1 .3 .6 .42 .42 0 0 1-.6 .2h-.5v-.2l.9-.1-.1-.3-.6-.1v.5h-.2v-.7h.5a.24 .24 0 0 0 .3-.1 .24 .24 0 0 0-.2-.3h-.4v.4h-.2z" fill-rule="evenodd"/>
<path d="M300.6 255.1a.55 .55 0 0 1 .9 .1 .55 .55 0 0 1-.3 .8 .55 .55 0 0 1-.7-.4h.2a.37 .37 0 0 0 .5 .4 .37 .37 0 0 0 0-.7l-.3-.1-.2 .4h-.2z" fill-rule="evenodd"/>
<path d="M301.8 255.2l.1-.2a.47 .47 0 0 1 .6 .1 .47 .47 0 0 1 .1 .6v.4l-.2-.1-.5 .1-.2-.1-.1-.2 .6 .2 .2-.4-.8 .2a.57 .57 0 0 1 .8-.4l-.2-.2-.5 .1z" fill-rule="evenodd"/>
<path d="M302.9 255h.1v.2l.4-.2v.2a.25 .25 0 0 0-.3 .1 .25 .25 0 0 0 0 .3v.5h-.2z" fill-rule="evenodd"/>
<path d="M303.7 255.1l.3-.1 .3 .2v-.6h.1v1.5h-.1v-.1l-.2 .1h-.4l-.2-.4 .2-.1a.34 .34 0 0 0 .4 .4 .34 .34 0 0 0 .2-.6l-.4-.2-.2 .4h-.2z" fill-rule="evenodd"/>
<path d="M305.3 254.6h.2l.8 1.2v-1.2h.2v1.5h-.2l-.8-1.2v1.2h-.2z" fill-rule="evenodd"/>
<path d="M306.9 255.2l.1-.2a.47 .47 0 0 1 .6 .1 .47 .47 0 0 1 .1 .6l.1 .4-.3-.1-.4 .1-.3-.1v-.2l.6 .2 .1-.4-.7 .2a.57 .57 0 0 1 .7-.4l-.1-.2-.6 .1z" fill-rule="evenodd"/>
<path d="M308 255h.2v.2l.2-.2 .4 .2 .3-.2 .2 .1 .2 1h-.2l-.1-.9a.26 .26 0 0 0-.3 0 .26 .26 0 0 0-.1 .3v.6h-.2v-.8l-.3-.1-.1 .9h-.2z" fill-rule="evenodd"/>
<path d="M309.8 255.2a.51 .51 0 0 1 .6-.1 .51 .51 0 0 1 .3 .5h-.8l.2 .4 .6-.2a.52 .52 0 0 1-.7 .3 .52 .52 0 0 1-.3-.6h.8l-.3-.3-.3 .3h-.2z" fill-rule="evenodd"/>
<path d="M311 255h.2v.2h-.2z" fill-rule="evenodd"/>
<path d="M311 255.9h.2v.2h-.2z" fill-rule="evenodd"/>
<path d="M368 244.1h.2l.5 1.4 .5-1.4h.2l-.6 1.5h-.2z" fill-rule="evenodd"/>
<path d="M369.6 244.6l.1-.1a.47 .47 0 0 1 .5 .1 .47 .47 0 0 1 .1 .6l.1 .4-.2-.1-.5 .1-.3-.1v-.2l.6 .2 .2-.4-.8 .2a.57 .57 0 0 1 .8-.4l-.2-.2-.6 .1z" fill-rule="evenodd"/>
<path d="M370.5 244.5h.2v.2l.4-.2v.2a.25 .25 0 0 0-.3 .1 .25 .25 0 0 0-.1 .3v.5h-.2z" fill-rule="evenodd"/>
<path d="M371.2 244.1h.2v.2h-.2z" fill-rule="evenodd"/>
<path d="M371.2 244.5h.2v1.1h-.2z" fill-rule="evenodd"/>
<path d="M371.8 244.6l.1-.1a.47 .47 0 0 1 .6 .1 .47 .47 0 0 1 .1 .6l.1 .4-.3-.1-.5 .1-.2-.1v-.2l.6 .2 .1-.4-.7 .2a.57 .57 0 0 1 .7-.4l-.2-.2-.5 .1z" fill-rule="evenodd"/>
<path d="M372.9 244.5h.1v.2l.4-.2a.35 .35 0 0 1 .4 .5v.6h-.2v-.6a.27 .27 0 0 0-.3-.3 .27 .27 0 0 0-.2 .3v.6h-.2z" fill-rule="evenodd"/>
<path d="M374.1 244.3l.2-.1v.3h.2v.2h-.2v.6l.2 .3a.27 .27 0 0 1-.3 0 .27 .27 0 0 1-.1-.3v-.6h-.2z" fill-rule="evenodd"/>
<path d="M374.7 244.5h.2v.2h-.2z" fill-rule="evenodd"/>
<path d="M374.7 245.4h.2v.2h-.2z" fill-rule="evenodd"/>
</g>
<path d="M408 243h-41.5v10.5" fill="none" stroke="#000" stroke-width=".2"/>
<g fill="#00007f">
<path d="M368.3 248.9l1-.2v.5a.53 .53 0 0 0-.7-.4 .53 .53 0 0 0-.3 .8l.1 .3 .3 .2 .4-.1 .2-.2a.6 .6 0 0 1-1 .2 .78 .78 0 0 1 0-1.1z" fill-rule="evenodd"/>
<path d="M369.4 248.7h.6l-.2 .1v.6h.7v-.6l-.2-.1h.6l-.2 .3v1l.2 .1h-.6l.2-.1v-.5h-.7v.5l.2 .1h-.6l.2-.2v-1z" fill-rule="evenodd"/>
<path d="M371 248.7h1v.3l-.1-.2h-.5v.6l.4-.1 .1-.1v.4l-.1-.1-.4-.1v.6a.51 .51 0 0 0 .7-.2l-.1 .3h-1l.2-.2v-1z" fill-rule="evenodd"/>
<path d="M372.5 248.9l1-.2v.5a.53 .53 0 0 0-.7-.4 .53 .53 0 0 0-.3 .8l.1 .3 .3 .2 .4-.1 .2-.2a.6 .6 0 0 1-1 .2 .78 .78 0 0 1 0-1.1z" fill-rule="evenodd"/>
<path d="M373.6 248.7h.6l-.2 .1v.6l.5-.5-.1-.2h.5l-.7 .7 .9 .7h-.6l.1-.1-.6-.6v.6l.2 .1h-.6l.2-.2v-1z" fill-rule="evenodd"/>
<path d="M375.2 248.7h1v.3l-.1-.2h-.6v.6l.5-.1 .1-.1v.4l-.1-.1-.5-.1 .1 .6a.51 .51 0 0 0 .7-.2l-.1 .3h-1l.2-.2-.1-1z" fill-rule="evenodd"/>
<path d="M376.4 248.7h.6a.7 .7 0 0 1 .8 .7 .7 .7 0 0 1-.7 .7h-.7l.2-.1v-1.2h.2v1.2a.65 .65 0 0 0 .8-.7 .65 .65 0 0 0-1-.5z" fill-rule="evenodd"/>
</g>
<path d="M366.5 243h-69v10.5" fill="none" stroke="#000" stroke-width=".2"/>
<g fill="#00f">
<path d="M299.3 244.3l.7-.2 .4 .3-.2 .2a.53 .53 0 0 0-.8-.2 .53 .53 0 0 0 0 .8l.4 .3 .3-.1 .1-.3h.2a.74 .74 0 0 1-1.1 .4 .74 .74 0 0 1 0-1.2z" fill-rule="evenodd"/>
<path d="M300.8 244.6a.54 .54 0 0 1 .8 .1 .54 .54 0 0 1-.3 .8 .54 .54 0 0 1-.7-.4h.2a.37 .37 0 0 0 .5 .4 .37 .37 0 0 0 .1-.7l-.4-.1-.2 .4h-.2z" fill-rule="evenodd"/>
<path d="M301.8 244.5h.2v.2l.4-.2 .2 .2 .3-.2 .3 .1 .1 1h-.2l-.1-.9a.26 .26 0 0 0-.3 0 .26 .26 0 0 0 0 .3v.6h-.2l-.1-.8-.3-.1-.1 .9h-.2z" fill-rule="evenodd"/>
<path d="M303.6 244.5h.1v.2a.5 .5 0 0 1 .8 .4 .5 .5 0 0 1-.7 .4v.5h-.2v-.9h.1a.33 .33 0 0 0 .4 .4 .33 .33 0 0 0 .2-.5l-.1-.3h-.2l-.3 .4h-.1z" fill-rule="evenodd"/>
<path d="M304.8 244.6l.1-.1a.47 .47 0 0 1 .6 .1 .47 .47 0 0 1 .1 .6l.1 .4-.3-.1-.4 .1-.3-.1v-.2l.6 .2 .1-.4-.7 .2a.57 .57 0 0 1 .7-.4l-.1-.2-.6 .1z" fill-rule="evenodd"/>
<path d="M305.9 244.5h.2v.2l.3-.2a.35 .35 0 0 1 .4 .5v.6h-.2v-.6a.27 .27 0 0 0-.3-.3 .27 .27 0 0 0-.2 .3v.6h-.2z" fill-rule="evenodd"/>
<path d="M307 244.5h.2l.3 .9 .3-.9h.2l-.6 1.4-.2 .2-.1-.1-.1-.1 .3-.1 .1-.2z" fill-rule="evenodd"/>
<path d="M308.2 244.5h.2v.2h-.2z" fill-rule="evenodd"/>
<path d="M308.2 245.4h.2v.2h-.2z" fill-rule="evenodd"/>
</g>
<g fill="#00007f">
<path d="M299.2 248.7h1.1l-.8 1.3a.68 .68 0 0 0 .9-.4l-.1 .5h-1.3l.9-1.3a.54 .54 0 0 0-.8 .3z" fill-rule="evenodd"/>
<path d="M300.6 248.8l.8-.1v.5l-.4-.4-.3 .2 .2 .2a.52 .52 0 0 1 .5 .7 .52 .52 0 0 1-.8 .2l-.1 .1v-.6a.35 .35 0 0 0 .3 .5 .35 .35 0 0 0 .4-.3l-.6-.5z" fill-rule="evenodd"/>
<path d="M301.6 248.7h.6l-.1 .2 .3 .8 .2-.5-.3-.5h.7l-.2 .1 .3 .8 .3-.7-.1-.2 .3 .1-.6 1.4-.4-.9-.4 .9z" fill-rule="evenodd"/>
<path d="M303.7 249.3l.4-.2 .3 .1v.8h.2l-.1 .1-.4-.1-.2 .1-.2-.1v-.1h.4v-.3l-.2 .3h-.2l.4-.4v-.2h-.2a.15 .15 0 0 1 0 .2 .15 .15 0 0 1-.2 0 .15 .15 0 0 1 0-.2z" fill-rule="evenodd"/>
<path d="M305 248.8v.4h.3l-.3 .1 .1 .7 .2-.1-.3 .2-.2-.1v-.7l-.2-.1z" fill-rule="evenodd"/>
<path d="M305.5 249.3l.5-.1 .1 .3h-.2l-.1-.3a.37 .37 0 0 0-.1 .5 .37 .37 0 0 0 .5 .2 .47 .47 0 0 1-.8 .1 .47 .47 0 0 1 .1-.7z" fill-rule="evenodd"/>
<path d="M306.3 248.7h.4v.6l.2-.2a.29 .29 0 0 1 .3 .4l.1 .6h-.4v-.8l-.2 .1 .1 .7h-.5l.1-.2z" fill-rule="evenodd"/>
<path d="M368.7 259h1.5l-1.1 1.7a.91 .91 0 0 0 1.2-.5l-.1 .6h-1.7l1.1-1.7a.73 .73 0 0 0-.9 .4z" fill-rule="evenodd"/>
<path d="M370.7 259.1l.4-.2 .4 .2 .2-.2-.1 .7a.41 .41 0 0 0-.3-.6 .41 .41 0 0 0-.5 .4l.2 .1a.82 .82 0 0 1 .8 1l-.4 .3h-.7l-.2 .1 .1-.7a.48 .48 0 0 0 .3 .5 .48 .48 0 0 0 .6-.3l-.2-.2a.72 .72 0 0 1-.7-1z" fill-rule="evenodd"/>
<path d="M371.9 259h.8l-.1 .2 .4 1 .3-.7-.4-.5h.9l-.2 .1 .4 1.1 .4-1-.2-.2h.5l-.8 1.9-.5-1.2-.6 1.2z" fill-rule="evenodd"/>
<path d="M374.8 259.7l.2-.1a.47 .47 0 0 1 .5-.1 .47 .47 0 0 1 .2 .5l.1 .6h.1l-.4 .2a.35 .35 0 0 0-.6 0l-.2-.1v-.2h.7v-.4l-.3 .4h-.4l.7-.5-.1-.3h-.3a.2 .2 0 0 1 .1 .3 .2 .2 0 0 1-.3 0 .2 .2 0 0 1 0-.3z" fill-rule="evenodd"/>
<path d="M376.5 259.1l.1 .5h.3v.1h-.3v.9h.3l-.1 .2a.35 .35 0 0 1-.5 0 .35 .35 0 0 1-.1-.4v-.7l-.2-.1z" fill-rule="evenodd"/>
<path d="M377.2 259.7a.4 .4 0 0 1 .5-.2 .4 .4 0 0 1 .2 .5h-.2l-.1-.4a.5 .5 0 0 0-.2 .6 .5 .5 0 0 0 .6 .4v-.1a.58 .58 0 0 1-.8 .2 .58 .58 0 0 1-.1-.8z" fill-rule="evenodd"/>
<path d="M378.2 259h.6v.7a.4 .4 0 0 1 .5-.2 .4 .4 0 0 1 .2 .6v.6l.1 .1h-.6l.1-.2-.1-.9-.2 .2 .1 .9h-.7l.2-.2v-1.5z" fill-rule="evenodd"/>
<path d="M380.4 259h.9a.93 .93 0 0 1 1 .9 .93 .93 0 0 1-1 .9h-.9l.3-.1v-.2h.4l.1 .2a.57 .57 0 0 0 .6-.8 .64 .64 0 0 0-.7-.8v1.4h-.4v-1.3z" fill-rule="evenodd"/>
<path d="M382.8 259.6a.62 .62 0 0 1 .8 .2 .62 .62 0 0 1-.2 .9 .62 .62 0 0 1-.8-.2l-.1-.2h.4v.3a.18 .18 0 0 0 .2 .2 .18 .18 0 0 0 .2-.2v-.8a.19 .19 0 0 0-.3-.2 .19 .19 0 0 0-.1 .3v.4h-.4z" fill-rule="evenodd"/>
<path d="M384.1 259.7a.4 .4 0 0 1 .5-.2 .4 .4 0 0 1 .3 .5h-.2l-.2-.4a.5 .5 0 0 0-.2 .6 .5 .5 0 0 0 .6 .4v-.1a.58 .58 0 0 1-.8 .2 .58 .58 0 0 1-.1-.8z" fill-rule="evenodd"/>
<path d="M385.1 259h.6v1.2l.4-.5-.1-.1h.5l-.5 .4 .6 .8h-.6l.1-.1-.3-.5-.1 .5 .1 .1h-.7l.2-.2v-1.5z" fill-rule="evenodd"/>
<path d="M299.5 258.7h1.1a1.17 1.17 0 0 1 1.3 1.2 1.17 1.17 0 0 1-1.3 1.1h-1.1l.3-.1 .1-.2h.5v.1a.53 .53 0 0 0 .7 0 .53 .53 0 0 0 .1-.6 .93 .93 0 0 0-.8-1.4v1.9h-.5v-1.7z" fill-rule="evenodd"/>
<path d="M302.5 259.5a.79 .79 0 0 1 1.1 .8 .79 .79 0 0 1-1.3 .5l-.1-.4h.5v.3a.22 .22 0 0 0 .2 .3 .22 .22 0 0 0 .2-.2v-1.1a.23 .23 0 0 0-.3-.2 .23 .23 0 0 0-.1 .3v.6h-.5v-.5z" fill-rule="evenodd"/>
<path d="M304.2 259.6a.5 .5 0 0 1 .6-.2 .5 .5 0 0 1 .3 .6 .36 .36 0 0 1-.4-.4l-.1-.1a.42 .42 0 0 0-.2 .7 .51 .51 0 0 0 .3 .6 .51 .51 0 0 0 .5-.1 .77 .77 0 0 1-1.1 .2 .77 .77 0 0 1 0-1.2z" fill-rule="evenodd"/>
<path d="M305.4 258.7h.7v1.5l.5-.5-.1-.3h.7l-.7 .6 .8 1h-.8l.1-.1-.4-.6-.1 .6 .2 .1h-.9l.2-.3v-1.8z" fill-rule="evenodd"/>
<path d="M307.4 260.1h1v.3h-1z" fill-rule="evenodd"/>
<path d="M308.5 258.7h1.2l-.3 .2v.9h.8v-.9l-.3-.2h1.2l-.3 .1v.3v1.7l.3 .2h-1.2l.3-.1v-1h-.8v1l.3 .1h-1.2l.3-.1v-.3v-1.6z" fill-rule="evenodd"/>
<path d="M311.2 258.7h1l-.2 .3 .5 1.3 .4-.9-.2-.5-.3-.2h1.1l-.2 .2 .5 1.3 .4-1.2-.2-.3 .6 .1-.2 .1-.8 2.2-.6-1.5-.7 1.5z" fill-rule="evenodd"/>
</g>
<path d="M263 274.5h34.5M297.5 264h-34.5v21" fill="none" stroke="#000" stroke-width=".2"/>
<g fill="#00f">
<path d="M299.2 265.1h1v.2h-.8v.5h.7v.1h-.7v.7h-.2z" fill-rule="evenodd"/>
<path d="M300.4 265.1h.2v.2h-.2z" fill-rule="evenodd"/>
<path d="M300.4 265.5h.2v1.1h-.2z" fill-rule="evenodd"/>
<path d="M300.9 265.1h.2v1.5h-.2z" fill-rule="evenodd"/>
<path d="M301.4 265.7l.1-.1a.51 .51 0 0 1 .6 0 .51 .51 0 0 1 .2 .5h-.8l.2 .4 .6-.2a.52 .52 0 0 1-.7 .3 .52 .52 0 0 1-.3-.6h.8l-.3-.3-.3 .3h-.2z" fill-rule="evenodd"/>
<path d="M303.1 265.1h.2l.8 1.2v-1.2h.2v1.5h-.2l-.8-1.2v1.2h-.2z" fill-rule="evenodd"/>
<path d="M304.7 265.6l.1-.1a.47 .47 0 0 1 .6 .1 .47 .47 0 0 1 .1 .6l.1 .4-.3-.1-.5 .1-.2-.1v-.2l.6 .2 .1-.4-.7 .2a.57 .57 0 0 1 .7-.4l-.2-.2-.5 .1z" fill-rule="evenodd"/>
<path d="M305.8 265.5h.1v.2l.5-.2 .2 .2 .2-.2 .3 .1 .2 1h-.2l-.1-.9a.26 .26 0 0 0-.3 0 .26 .26 0 0 0-.1 .3v.6h-.2v-.8l-.3-.1-.1 .9h-.2z" fill-rule="evenodd"/>
<path d="M307.6 265.7l.1-.1a.51 .51 0 0 1 .6 0 .51 .51 0 0 1 .2 .5h-.8l.2 .4 .6-.2a.52 .52 0 0 1-.7 .3 .52 .52 0 0 1-.3-.6h.8l-.3-.3-.3 .3h-.2z" fill-rule="evenodd"/>
<path d="M308.8 265.5h.2v.2h-.2z" fill-rule="evenodd"/>
<path d="M308.8 266.4h.2v.2h-.2z" fill-rule="evenodd"/>
<path d="M264.8 265.2l.7-.1 .2 .4-.1 .1a.32 .32 0 0 0-.4-.4 .32 .32 0 0 0-.3 .5h.3a.5 .5 0 0 1 .6 .6 .5 .5 0 0 1-.8 .3l-.4-.3v-.2h.2a.39 .39 0 0 0 .4 .4 .39 .39 0 0 0 .4-.4l-.9-.4v-.2z" fill-rule="evenodd"/>
<path d="M266 265.1h.2v.6l.3-.2 .4 .2v.9h-.2v-.7a.27 .27 0 0 0-.3-.2 .27 .27 0 0 0-.2 .3v.6h-.2z" fill-rule="evenodd"/>
<path d="M267.3 265.7l.1-.1a.51 .51 0 0 1 .5 0 .51 .51 0 0 1 .2 .5h-.8l.3 .4 .5-.2a.52 .52 0 0 1-.6 .3 .52 .52 0 0 1-.3-.6h.8l-.3-.3-.4 .3h-.1z" fill-rule="evenodd"/>
<path d="M268.5 265.7v-.1a.51 .51 0 0 1 .6 0 .51 .51 0 0 1 .2 .5h-.8l.2 .4 .6-.2a.52 .52 0 0 1-.6 .3 .52 .52 0 0 1-.4-.6h.8l-.3-.3-.3 .3h-.2z" fill-rule="evenodd"/>
<path d="M269.6 265.3l.2-.1v.3h.1v.2h-.1v.6l.2 .3a.27 .27 0 0 1-.3 0 .27 .27 0 0 1-.1-.3v-.6h-.2z" fill-rule="evenodd"/>
<path d="M270.6 265.1h1.2v.2h-.5v1.3h-.2v-1.3h-.5z" fill-rule="evenodd"/>
<path d="M271.9 265.1h.2v.2h-.2z" fill-rule="evenodd"/>
<path d="M271.9 265.5h.2v1.1h-.2z" fill-rule="evenodd"/>
<path d="M272.4 265.3l.2-.1v.3h.1v.2h-.1v.6l.2 .3a.27 .27 0 0 1-.3 0 .27 .27 0 0 1-.1-.3v-.6h-.2z" fill-rule="evenodd"/>
<path d="M272.9 265.1h.2v1.5h-.2z" fill-rule="evenodd"/>
<path d="M273.5 265.7v-.1a.51 .51 0 0 1 .6 0 .51 .51 0 0 1 .2 .5h-.8l.3 .4 .5-.2a.52 .52 0 0 1-.6 .3 .52 .52 0 0 1-.4-.6h.8l-.3-.3-.3 .3h-.2z" fill-rule="evenodd"/>
<path d="M274.6 265.5h.2v.2h-.2z" fill-rule="evenodd"/>
<path d="M274.6 266.4h.2v.2h-.2z" fill-rule="evenodd"/>
<path d="M264.8 275.7l.7-.1 .2 .4-.1 .1a.32 .32 0 0 0-.4-.4 .32 .32 0 0 0-.3 .5h.3a.5 .5 0 0 1 .6 .6 .5 .5 0 0 1-.8 .3l-.4-.3v-.2h.2a.39 .39 0 0 0 .4 .4 .39 .39 0 0 0 .4-.4l-.9-.4v-.2z" fill-rule="evenodd"/>
<path d="M266 275.6h.2v.6l.3-.2 .4 .2v.9h-.2v-.7a.27 .27 0 0 0-.3-.2 .27 .27 0 0 0-.2 .3v.6h-.2z" fill-rule="evenodd"/>
<path d="M267.3 276.2a.51 .51 0 0 1 .6-.1 .51 .51 0 0 1 .2 .5h-.8l.3 .4 .5-.2a.52 .52 0 0 1-.6 .3 .52 .52 0 0 1-.3-.6h.8l-.3-.3-.4 .3h-.1z" fill-rule="evenodd"/>
<path d="M268.5 276.2a.51 .51 0 0 1 .6-.1 .51 .51 0 0 1 .2 .5h-.8l.2 .4 .6-.2a.52 .52 0 0 1-.6 .3 .52 .52 0 0 1-.4-.6h.8l-.3-.3-.3 .3h-.2z" fill-rule="evenodd"/>
<path d="M269.6 275.8l.2-.1v.3h.1v.2h-.1v.6l.2 .3a.27 .27 0 0 1-.3 0 .27 .27 0 0 1-.1-.3v-.6h-.2z" fill-rule="evenodd"/>
<path d="M270.7 275.6h.6a.46 .46 0 0 1 .6 .5 .46 .46 0 0 1-.6 .4h-.4v.6h-.2v-.8h.8l.2-.2-.2-.3h-.6v.5h-.2z" fill-rule="evenodd"/>
<path d="M272.2 276.2l.1-.2a.47 .47 0 0 1 .6 .1 .47 .47 0 0 1 .1 .6v.4l-.2-.1-.5 .1-.2-.1-.1-.2 .6 .2 .2-.4-.8 .2a.57 .57 0 0 1 .8-.4l-.2-.2-.5 .1z" fill-rule="evenodd"/>
<path d="M273.3 275.8l.2-.1v.3h.2v.2h-.2v.6l.2 .3a.27 .27 0 0 1-.3 0 .27 .27 0 0 1-.1-.3v-.6h-.1z" fill-rule="evenodd"/>
<path d="M273.9 275.6h.1v.6l.4-.2 .3 .1v1h-.1v-.7a.27 .27 0 0 0-.4-.2 .27 .27 0 0 0-.2 .3v.6h-.1z" fill-rule="evenodd"/>
<path d="M275.1 276h.2v.2h-.2z" fill-rule="evenodd"/>
<path d="M275.1 276.9h.2v.2h-.2z" fill-rule="evenodd"/>
</g>
<g fill="#00007f">
<path d="M264.5 269.7h1.1v.3l-.2-.2h-.5v.6l.4-.1 .1-.1v.4l-.1-.1-.4-.1v.6l.2 .1h-.6l.2-.2v-1z" fill-rule="evenodd"/>
<path d="M266.3 269.9l1-.2v.5a.53 .53 0 0 0-.7-.4 .53 .53 0 0 0-.3 .8l.2 .3 .3 .2 .3-.1 .2-.2a.6 .6 0 0 1-1 .2 .78 .78 0 0 1 0-1.1z" fill-rule="evenodd"/>
<path d="M267.4 270.2h.4v.7l.1 .1 .2-.1v-.6l-.1-.1h.3v.8h.2l-.4 .2v-.2l-.2 .1h-.2l-.1-.8z" fill-rule="evenodd"/>
<path d="M269.4 269.8l.2-.1a1.42 1.42 0 0 0 0 1.9l-.4-.6a1.12 1.12 0 0 1 .2-1.2z" fill-rule="evenodd"/>
<path d="M269.9 269.8l.8-.1-.1 .5a.29 .29 0 0 0-.2-.4 .29 .29 0 0 0-.3 .4h.1a.51 .51 0 0 1 .5 .3 .51 .51 0 0 1-.1 .5l-.8 .2 .1-.5a.33 .33 0 0 0 .3 .4 .33 .33 0 0 0 .3-.4l-.1-.1a.51 .51 0 0 1-.5-.2 .51 .51 0 0 1 0-.6z" fill-rule="evenodd"/>
<path d="M271.1 270.3l.4-.1 .2 .1-.1 .2a.28 .28 0 0 0-.4-.3 .28 .28 0 0 0-.1 .5l.2 .3 .4-.2a.43 .43 0 0 1-.6 .3 .43 .43 0 0 1-.1-.7z" fill-rule="evenodd"/>
<path d="M272 270.2l.5 .1 .1 .7 .1-.1-.1 .2-.7-.1v-.1l.3 .1 .2-.1v-.3l-.5 .3 .5-.4-.2-.3-.3 .3z" fill-rule="evenodd"/>
<path d="M272.8 269.8l.3-.1v1.3l.2 .1h-.5l.1-.1v-.9z" fill-rule="evenodd"/>
<path d="M273.5 270.3l.4-.1 .3 .2v.1h-.7l.2 .4 .3 .1 .2-.2a.41 .41 0 0 1-.6 .3 .41 .41 0 0 1-.2-.6h.6l-.2-.3-.4 .3z" fill-rule="evenodd"/>
<path d="M275 269.9l.4-.2v1.3l.2 .1h-.6l.2-.1v-.9v-.2z" fill-rule="evenodd"/>
<path d="M276.6 269.9l.4-.2v1.3l.2 .1h-.5l.1-.1v-.9v-.2z" fill-rule="evenodd"/>
<path d="M277.5 269.7a1.08 1.08 0 0 1 0 1.9 1.42 1.42 0 0 0 0-1.9z" fill-rule="evenodd"/>
<circle cx="265.8" cy="271" r=".11"/>
<circle cx="276.1" cy="270.3" r=".11"/>
<circle cx="276.1" cy="271" r=".11"/>
</g>
<path d="M297.5 243h-34.5v21" fill="none" stroke="#000" stroke-width=".2"/>
<g fill="#00f">
<path d="M264.8 244.3l.7-.2 .4 .3-.2 .2a.53 .53 0 0 0-.8-.2 .53 .53 0 0 0 0 .8l.4 .3 .3-.1 .1-.3h.2a.74 .74 0 0 1-1.1 .4 .74 .74 0 0 1 0-1.2z" fill-rule="evenodd"/>
<path d="M266.3 244.6a.54 .54 0 0 1 .8 .1 .54 .54 0 0 1-.3 .8 .54 .54 0 0 1-.7-.4h.2a.37 .37 0 0 0 .5 .4 .37 .37 0 0 0 .1-.7l-.4-.1-.2 .4h-.2z" fill-rule="evenodd"/>
<path d="M267.3 244.5h.2v.2l.4-.2 .2 .2 .3-.2 .3 .1 .1 1h-.2l-.1-.9a.26 .26 0 0 0-.3 0 .26 .26 0 0 0 0 .3v.6h-.2l-.1-.8-.3-.1-.1 .9h-.2z" fill-rule="evenodd"/>
<path d="M269.1 244.5h.1v.2l.4-.2 .3 .2 .2-.2 .3 .1 .1 1h-.1l-.1-.9a.26 .26 0 0 0-.3 0 .26 .26 0 0 0-.1 .3v.6h-.2v-.8l-.3-.1-.1 .9h-.2z" fill-rule="evenodd"/>
<path d="M270.9 244.7l.1-.1a.51 .51 0 0 1 .5 0 .51 .51 0 0 1 .3 .5h-.9l.3 .4 .6-.2a.52 .52 0 0 1-.7 .3 .52 .52 0 0 1-.3-.6h.8l-.3-.3-.3 .3h-.2z" fill-rule="evenodd"/>
<path d="M272 244.5h.1v.2l.4-.2a.35 .35 0 0 1 .4 .5v.6h-.2v-.6a.27 .27 0 0 0-.3-.3 .27 .27 0 0 0-.2 .3v.6h-.2z" fill-rule="evenodd"/>
<path d="M273.2 244.3l.2-.1v.3h.2v.2h-.2v.6l.2 .3a.27 .27 0 0 1-.3 0 .27 .27 0 0 1-.1-.3v-.6h-.2z" fill-rule="evenodd"/>
<path d="M273.8 244.6l.5-.1 .2 .3h-.2a.21 .21 0 0 0-.2-.2 .21 .21 0 0 0-.1 .3 .43 .43 0 0 1 .4 .1 .43 .43 0 0 1 .1 .4l-.2 .2h-.4l-.2-.3h.1a.24 .24 0 0 0 .3 .3 .24 .24 0 0 0 .2-.4 .43 .43 0 0 1-.6-.5z" fill-rule="evenodd"/>
<path d="M274.8 244.5h.2v.2h-.2z" fill-rule="evenodd"/>
<path d="M274.8 245.4h.2v.2h-.2z" fill-rule="evenodd"/>
</g>
<g fill="#00007f">
<path d="M264.7 248.7h1l-.9 1.3h.7l.2-.3v.4h-1.2l.9-1.3h-.6l-.1 .3z" fill-rule="evenodd"/>
<path d="M266 248.8l.7-.1v.5a.29 .29 0 0 0-.3-.4 .29 .29 0 0 0-.2 .4h.1a.49 .49 0 0 1 .5 .3 .49 .49 0 0 1-.1 .6l-.8 .1 .1-.5a.33 .33 0 0 0 .3 .4 .33 .33 0 0 0 .2-.4v-.1a.51 .51 0 0 1-.5-.2 .51 .51 0 0 1 0-.6z" fill-rule="evenodd"/>
<path d="M267 248.7h.5l-.1 .1 .3 1 .2-.7-.3-.4h.6l-.2 .2 .3 .9 .3-.9-.1-.2h.4l-.6 1.5-.3-.9-.4 .9z" fill-rule="evenodd"/>
<path d="M269 249.2l.5 .1v.7l.2-.1-.1 .2-.7-.1-.1-.1 .4 .1 .2-.1v-.3l-.6 .3 .6-.4-.2-.3-.3 .3z" fill-rule="evenodd"/>
<path d="M270 248.9v.3h.3h-.3v.7h.3l-.3 .2-.1-.1v-.8h-.2z" fill-rule="evenodd"/>
<path d="M270.5 249.3l.4-.1 .2 .1-.1 .2a.28 .28 0 0 0-.4-.3 .28 .28 0 0 0-.1 .5l.3 .3 .3-.2a.43 .43 0 0 1-.6 .3 .43 .43 0 0 1-.1-.7z" fill-rule="evenodd"/>
<path d="M271.2 248.8l.3-.1v.7l.3-.2h.2l.1 .8 .1 .1h-.4l.1-.2v-.5l-.1-.1-.3 .1 .1 .6 .1 .1h-.5l.2-.1v-.9v-.3z" fill-rule="evenodd"/>
</g>
<path d="M263 243h-42v42M297.5 243h69" fill="none" stroke="#000" stroke-width=".2"/>
<g fill="#000">
<path d="M17.1 17.5a5.9 5.9 0 0 1 2.7 .1 1.87 1.87 0 0 1 .9 2.2 1.87 1.87 0 0 1-2 1.4h-1.6l.4-.2 .1-.4h.9v.2a.65 .65 0 0 0 .7 .2 .65 .65 0 0 0 .4-.6 2.07 2.07 0 0 0-.6-2.7h-.5v2.9h-.9v-2.8z" fill-rule="evenodd"/>
<path d="M21.7 18.8a1.29 1.29 0 0 1 1.9 1.1 1.29 1.29 0 0 1-1.9 1.1l-.4-.9h.7l.1 .6a.35 .35 0 0 0 .3 .3 .35 .35 0 0 0 .4-.3v-1.7a.37 .37 0 0 0-.5-.3 .37 .37 0 0 0-.2 .5l-.1 .9h-.7v-.7z" fill-rule="evenodd"/>
<path d="M26.5 17.5h1.1v2.4l.8-.9v-.2l-.3-.2h1.2l-1.1 .9 1.3 1.7h-1.3l.1-.3-.6-.9-.1 .1v.8l.2 .3h-1.3l.2-.2 .1-.4v-2.9z" fill-rule="evenodd"/>
<path d="M29.6 19.6h1.6v.6h-1.6z" fill-rule="evenodd"/>
<path d="M31.4 17.5h2l-.5 .2-.1 1.4h1.3v-1a.53 .53 0 0 0-.5-.6h2l-.5 .2-.1 .4v2.7l.6 .4h-2l.5-.3v-1.5h-1.3l.1 1.5 .5 .3h-2l.5-.2v-.5v-2.7z" fill-rule="evenodd"/>
<path d="M35.7 17.5h1.6l-.3 .2v.2l.8 2.1 .6-1.4a1.18 1.18 0 0 0-.7-1.1h1.8l-.4 .2 .8 2.2 .7-1.9v-.3l-.4-.2h1l-.3 .3-1.3 3.4-1.1-2.3-1.1 2.3-1.4-3.4z" fill-rule="evenodd"/>
<path d="M42.7 17.5h3.1v1h-.1a.94 .94 0 0 0-1.3-.8h-.3v1.5a.9 .9 0 0 0 1-.8v1.9a.95 .95 0 0 0-1-.9v1.5l.5 .3h-1.9l.4-.2 .1-.5v-2.7z" fill-rule="evenodd"/>
<path d="M46.4 18.9a1.05 1.05 0 0 1 1.2-.4 1.05 1.05 0 0 1 .7 1v1.2h.3a.52 .52 0 0 1-.5 .5 .52 .52 0 0 1-.5-.4 .75 .75 0 0 1-.7 .4 .75 .75 0 0 1-.7-.4l.1-.4h.7l.3 .3 .3-.1v-.9l-.5 .4-.1 .3h-.7l.4-.4 .9-.4v-.6a.33 .33 0 0 0-.5-.3 .33 .33 0 0 0-.1 .6 .39 .39 0 0 1-.6 .3 .39 .39 0 0 1 0-.7z" fill-rule="evenodd"/>
<path d="M48.9 17.5h1v1.4a1.05 1.05 0 0 1 1.4-.1 1.05 1.05 0 0 1 .3 1.3 1.17 1.17 0 0 1-.7 1 1.17 1.17 0 0 1-1.2-.1l-.5 .2v-2.1h.7l.1 1.6a.4 .4 0 0 0 .4 .4 .4 .4 0 0 0 .4-.4v-1.3a.46 .46 0 0 0-.3-.5 .46 .46 0 0 0-.6 .2h-.7v-1.3z" fill-rule="evenodd"/>
<path d="M52.1 18.6h1v.6a.68 .68 0 0 1 .4-.6 .68 .68 0 0 1 .8 .1 .4 .4 0 0 1-.2 .6 .4 .4 0 0 1-.6-.2l-.3 .3-.1 1.2a.46 .46 0 0 0 .4 .6h-1.4l.2-.2 .1-.4v-1.6z" fill-rule="evenodd"/>
<path d="M54.5 18.6h1l.1 2.3 .3 .3h-1.4l.2-.2 .1-.4v-1.7z" fill-rule="evenodd"/>
<path d="M58.9 18.9a1.05 1.05 0 0 1 1.1-.4 1.05 1.05 0 0 1 .8 1v1.2h.2a.52 .52 0 0 1-.5 .5 .52 .52 0 0 1-.5-.4 .75 .75 0 0 1-.6 .4 .75 .75 0 0 1-.7-.4v-.4h.7l.3 .3 .3-.1v-.9l-.5 .4-.1 .3h-.7l.4-.4 .9-.4v-.6a.33 .33 0 0 0-.5-.3 .33 .33 0 0 0 0 .6 .39 .39 0 0 1-.6 .3 .39 .39 0 0 1 0-.7z" fill-rule="evenodd"/>
<path d="M62.3 17.7l.1 .9h.6v.3h-.6v1.8l.2 .2 .3-.3a.68 .68 0 0 1-.8 .6 .68 .68 0 0 1-.5-.9v-1.4l-.3-.1z" fill-rule="evenodd"/>
<path d="M63.2 18.6h1.1v2.3l.3 .3h-1.4l.2-.2 .1-.4v-1.7z" fill-rule="evenodd"/>
<path d="M65.3 18.8a1.29 1.29 0 0 1 1.9 1.1 1.29 1.29 0 0 1-1.9 1.1l-.5-.9h.8l.1 .6a.35 .35 0 0 0 .3 .3 .35 .35 0 0 0 .4-.3v-1.7a.37 .37 0 0 0-.5-.3 .37 .37 0 0 0-.2 .5l-.1 .9h-.8l.1-.7z" fill-rule="evenodd"/>
<path d="M67.6 18.6h1.1v.4a.79 .79 0 0 1 1-.4 .79 .79 0 0 1 .4 1v1.3l.3 .3h-1.3l.2-.3v-1.7a.28 .28 0 0 0-.2-.3 .28 .28 0 0 0-.3 .2l-.1 .2v1.6l.2 .3h-1.3l.2-.2 .1-.4v-1.7z" fill-rule="evenodd"/>
<path d="M72 17.5a5.9 5.9 0 0 1 2.7 .1 1.87 1.87 0 0 1 1 2.2 1.87 1.87 0 0 1-2 1.4h-1.7l.4-.2 .1-.4h.9v.2a.65 .65 0 0 0 .7 .2 .65 .65 0 0 0 .5-.6 2.08 2.08 0 0 0-.7-2.7h-.5v2.9h-.9v-2.8z" fill-rule="evenodd"/>
<path d="M76.7 18.8a1.29 1.29 0 0 1 1.9 1.1 1.29 1.29 0 0 1-1.9 1.1l-.5-.9h.8v.6a.35 .35 0 0 0 .3 .3 .35 .35 0 0 0 .4-.3v-1.7a.37 .37 0 0 0-.5-.3 .37 .37 0 0 0-.2 .5v.9h-.8l.1-.7z" fill-rule="evenodd"/>
<path d="M81.4 18.6h1.1v2a.27 .27 0 0 0 .2 .3 .27 .27 0 0 0 .3-.2l.1-.2v-1.3v-.4l-.2-.2h1v2.3l.3 .3h-1.1v-.4a.79 .79 0 0 1-1 .4 .79 .79 0 0 1-.4-1v-1.3z" fill-rule="evenodd"/>
<path d="M84.6 18.6h1v.4a.79 .79 0 0 1 .8-.5 .79 .79 0 0 1 .7 .5 .82 .82 0 0 1 1-.4 .82 .82 0 0 1 .5 1v1.3l.3 .3h-1.3l.2-.3v-1.7a.31 .31 0 0 0-.2-.3 .31 .31 0 0 0-.4 .2l-.1 .1v1.7l.3 .3h-1.3l.2-.4v-1.6a.3 .3 0 0 0-.2-.3 .3 .3 0 0 0-.3 .2l-.2 .1v1.4l.1 .4 .2 .2h-1.3l.2-.2v-.4v-1.7z" fill-rule="evenodd"/>
<path d="M89.6 18.9a1.03 1.03 0 0 1 1.2-.3 1.03 1.03 0 0 1 .6 1.2h-1.4a.72 .72 0 0 0 .4 .9 .72 .72 0 0 0 .9-.3 .93 .93 0 0 1-1.2 .8 1.26 1.26 0 0 1-.8-1.7l1.4 .1v-.6l-.3-.3-.4 .3v.5h-.7z" fill-rule="evenodd"/>
<path d="M91.7 18.6h1v.4a.79 .79 0 0 1 1.1-.4 .79 .79 0 0 1 .4 1v1.3l.3 .3h-1.3l.2-.3v-1.7a.28 .28 0 0 0-.2-.3 .28 .28 0 0 0-.3 .2l-.2 .2 .1 1.6 .2 .3h-1.3l.2-.2 .1-.4v-1.7z" fill-rule="evenodd"/>
<path d="M95.7 17.7l.1 .9h.6v.3h-.6v1.8l.2 .2 .3-.3a.68 .68 0 0 1-.8 .6 .68 .68 0 0 1-.4-.9v-1.4l-.4-.1z" fill-rule="evenodd"/>
<path d="M24.5 18.8a.84 .84 0 0 1 1-.3 .84 .84 0 0 1 .5 .9 .46 .46 0 0 1-.5 0 .46 .46 0 0 1-.1-.5l-.3-.2a1.36 1.36 0 0 0 .5 2.1l.5-.3a1.02 1.02 0 0 1-1 .7 1.02 1.02 0 0 1-1-.8v-.7z" fill-rule="evenodd"/>
<path d="M56.6 18.8a.84 .84 0 0 1 1-.3 .84 .84 0 0 1 .5 .9 .46 .46 0 0 1-.5 0 .46 .46 0 0 1-.2-.5l-.2-.2a1.29 1.29 0 0 0 .5 2.1l.5-.3a.99 .99 0 0 1-.8 .7 .99 .99 0 0 1-1-.3 1.58 1.58 0 0 1 .2-2.1z" fill-rule="evenodd"/>
<path d="M79.4 18.8a.84 .84 0 0 1 1-.3 .84 .84 0 0 1 .6 .9 .46 .46 0 0 1-.6 0 .46 .46 0 0 1-.1-.5l-.3-.2a1.36 1.36 0 0 0 .5 2.1l.5-.3a.99 .99 0 0 1-.7 .7 .99 .99 0 0 1-1-.3 1.58 1.58 0 0 1 .1-2.1z" fill-rule="evenodd"/>
<path d="M194.2 64.7h2.5v.9a1.03 1.03 0 0 0-1.4-.7v1.2a.73 .73 0 0 0 .8-.6v1.5a.76 .76 0 0 0-.8-.7v1.2l.4 .2h-1.5l.3-.1 .1-.4v-2.2z" fill-rule="evenodd"/>
<path d="M198.2 65.1a2.37 2.37 0 0 1 2.2-.3l.2-.1v1a1.05 1.05 0 0 0-1.3-.8 1.05 1.05 0 0 0-.8 1.3 1.09 1.09 0 0 0 .6 1.3 1.09 1.09 0 0 0 1.4-.4v.2a1.58 1.58 0 0 1-2.3 .1 1.58 1.58 0 0 1 0-2.3z" fill-rule="evenodd"/>
<path d="M201 65.7h.8v1.6a.22 .22 0 0 0 .2 .2 .22 .22 0 0 0 .2-.1l.1-.2v-1.1l-.2-.4h.9v1.8l.2 .2h-.9v-.2a.64 .64 0 0 1-.8 .3 .64 .64 0 0 1-.3-.9v-1z" fill-rule="evenodd"/>
<path d="M205.2 65.1l.7-.4a3.2 3.2 0 0 0-.2 3.7l.2 .2a2.2 2.2 0 0 1-.7-3.5z" fill-rule="evenodd"/>
<path d="M206.5 64.9a1.69 1.69 0 0 1 1.4 0l.2-.2v1a.84 .84 0 0 0-.5-.7 .84 .84 0 0 0-.9 .1l.1 .4a2.28 2.28 0 0 1 1.5 1.4 1.2 1.2 0 0 1-1.9 .7l-.2 .2v-1.1a.98 .98 0 0 0 1.5 .7 .62 .62 0 0 0-.6-.8 .99 .99 0 0 1-.8-.6 .99 .99 0 0 1 .2-1.1z" fill-rule="evenodd"/>
<path d="M209 65.9a.68 .68 0 0 1 .8-.3 .68 .68 0 0 1 .4 .7 .41 .41 0 0 1-.4 0 .41 .41 0 0 1-.2-.5h-.1a.99 .99 0 0 0 .5 1.6l.3-.2a.89 .89 0 0 1-1.2 .5 .89 .89 0 0 1-.5-1.2z" fill-rule="evenodd"/>
<path d="M210.8 65.9a.85 .85 0 0 1 1-.3 .85 .85 0 0 1 .6 .8v1h.2a.42 .42 0 0 1-.4 .4 .42 .42 0 0 1-.4-.4 .56 .56 0 0 1-.6 .4 .56 .56 0 0 1-.5-.4v-.2h.6l.2 .2 .3-.1v-.7l-.5 .6h-.6l.3-.4 .8-.4-.1-.4a.27 .27 0 0 0-.3-.2 .27 .27 0 0 0-.1 .4 .32 .32 0 0 1-.5 .2 .32 .32 0 0 1 0-.5z" fill-rule="evenodd"/>
<path d="M212.8 64.7h.9v2.8l.2 .2h-1.1l.3-.4-.1-2.3z" fill-rule="evenodd"/>
<path d="M214.4 65.9a.83 .83 0 0 1 1-.2 .83 .83 0 0 1 .5 .9h-1.2a.58 .58 0 0 0 .3 .8 .58 .58 0 0 0 .8-.3 .85 .85 0 0 1-1 .7 .85 .85 0 0 1-.6-1.1v-.3l1.1 .1-.1-.7a.4 .4 0 0 0-.5 .2 .4 .4 0 0 0 0 .4h-.5z" fill-rule="evenodd"/>
<path d="M217.4 65.2l1.2-.5v2.7l.1 .2 .3 .1h-1.6l.5-.2v-1.9l-.1-.4z" fill-rule="evenodd"/>
<path d="M221.2 65.2l1.1-.5v2.7l.2 .2 .3 .1h-1.6l.5-.2v-1.9l-.1-.4z" fill-rule="evenodd"/>
<path d="M223.2 64.7a2.18 2.18 0 0 1 1.3 2 2.18 2.18 0 0 1-1.3 1.9 3.2 3.2 0 0 0 .2-3.7z" fill-rule="evenodd"/>
<circle cx="55.2" cy="17.8" r=".42"/>
<circle cx="63.9" cy="17.8" r=".42"/>
<circle cx="197" cy="67.4" r=".36"/>
<circle cx="220.1" cy="67.4" r=".36"/>
<circle cx="220.1" cy="66" r=".36"/>
</g>
<g fill="#00007f">
<path d="M392.6 248.8l.3-.1v1.3h.2l-.6 .2-.4-.2v-.4h.2l.1 .4 .3-.1-.1-.7-.2 .1-.1 .3h-.2v-.1a.4 .4 0 0 1 .6-.3v-.4z" fill-rule="evenodd"/>
<path d="M393.3 248.8a.42 .42 0 0 1 .6 .1 .42 .42 0 0 1-.2 .6l-.4 .5 .7-.1-.1 .2h-.8a.87 .87 0 0 0 .6-1.2h-.3l-.3 .2z" fill-rule="evenodd"/>
<path d="M394.3 249.2l.5 .1 .1 .7 .1-.1-.1 .2-.7-.1v-.1l.3 .1 .2-.1v-.3l-.5 .3 .5-.4-.2-.3-.2 .3z" fill-rule="evenodd"/>
<path d="M395.3 248.9l.3-.2 .1 1.3 .1 .1h-.5l.2-.1v-.9v-.2z" fill-rule="evenodd"/>
<path d="M396.5 248.9l.5-.2-.4 .2-.2 .4a.43 .43 0 0 1 .6 .3 .43 .43 0 0 1-.4 .6 .43 .43 0 0 1-.4-.6h.2a.31 .31 0 0 0 .1 .4 .31 .31 0 0 0 .4 0 .31 .31 0 0 0-.1-.5l-.2-.2-.2 .1v.2h-.2z" fill-rule="evenodd"/>
<path d="M397.5 248.8l.3-.1 .2 .1v.1l-.3-.2-.1 .1v.4h.2h-.2v.8l.2 .1h-.6l.2-.1v-.8h-.2h.2z" fill-rule="evenodd"/>
<path d="M398.1 248.8a.61 .61 0 0 1 .7 .4 .61 .61 0 0 1-.3 .8l-.6 .1 .4-.2 .3-.4h-.5a.24 .24 0 0 1-.2-.2 .24 .24 0 0 1 .2-.2l.1 .3a.34 .34 0 0 0 .4-.2 .34 .34 0 0 0-.3-.4l-.2 .3h-.2z" fill-rule="evenodd"/>
</g>
<path d="M390.5 243v10.5" fill="none" stroke="#000" stroke-width=".2"/>
<g fill="#00f">
<path d="M392.3 244.3l.8-.2 .3 .3 .1 .1-.2 .1a.58 .58 0 0 0-.8-.2 .58 .58 0 0 0-.2 .8 .58 .58 0 0 0 .8 .2l.2-.1v-.3h-.4v-.1h.6v.5a.81 .81 0 0 1-1.2 .1 .81 .81 0 0 1 0-1.2z" fill-rule="evenodd"/>
<path d="M393.8 244.1h.2v.2h-.2z" fill-rule="evenodd"/>
<path d="M393.8 244.5h.2v1.1h-.2z" fill-rule="evenodd"/>
<path d="M394.3 244.3l.2-.1v.3h.1v.2h-.1v.6l.2 .3a.27 .27 0 0 1-.3 0 .27 .27 0 0 1-.1-.3v-.6h-.2z" fill-rule="evenodd"/>
<path d="M395.4 244.1h.2v.6h.8v-.6h.2v1.5h-.2v-.7h-.8v.7h-.2z" fill-rule="evenodd"/>
<path d="M397 244.6l.1-.1a.47 .47 0 0 1 .6 .1 .47 .47 0 0 1 .1 .6l.1 .4-.3-.1-.5 .1-.2-.1v-.2l.6 .2 .1-.4-.7 .2a.57 .57 0 0 1 .7-.4l-.2-.2-.5 .1z" fill-rule="evenodd"/>
<path d="M398.1 244.6l.6-.1 .2 .3h-.2a.21 .21 0 0 0-.3-.2 .21 .21 0 0 0-.1 .3 .43 .43 0 0 1 .5 .1 .43 .43 0 0 1 .1 .4l-.3 .2h-.3l-.3-.3h.2a.24 .24 0 0 0 .3 .3 .24 .24 0 0 0 .1-.4 .43 .43 0 0 1-.5-.5z" fill-rule="evenodd"/>
<path d="M399.1 244.1h.2v.6l.3-.2 .4 .1v1h-.2v-.7a.27 .27 0 0 0-.3-.2 .27 .27 0 0 0-.2 .3v.6h-.2z" fill-rule="evenodd"/>
<path d="M400.4 244.5h.2v.2h-.2z" fill-rule="evenodd"/>
<path d="M400.4 245.4h.2v.2h-.2z" fill-rule="evenodd"/>
</g>
<use href="#words"/>
</svg>
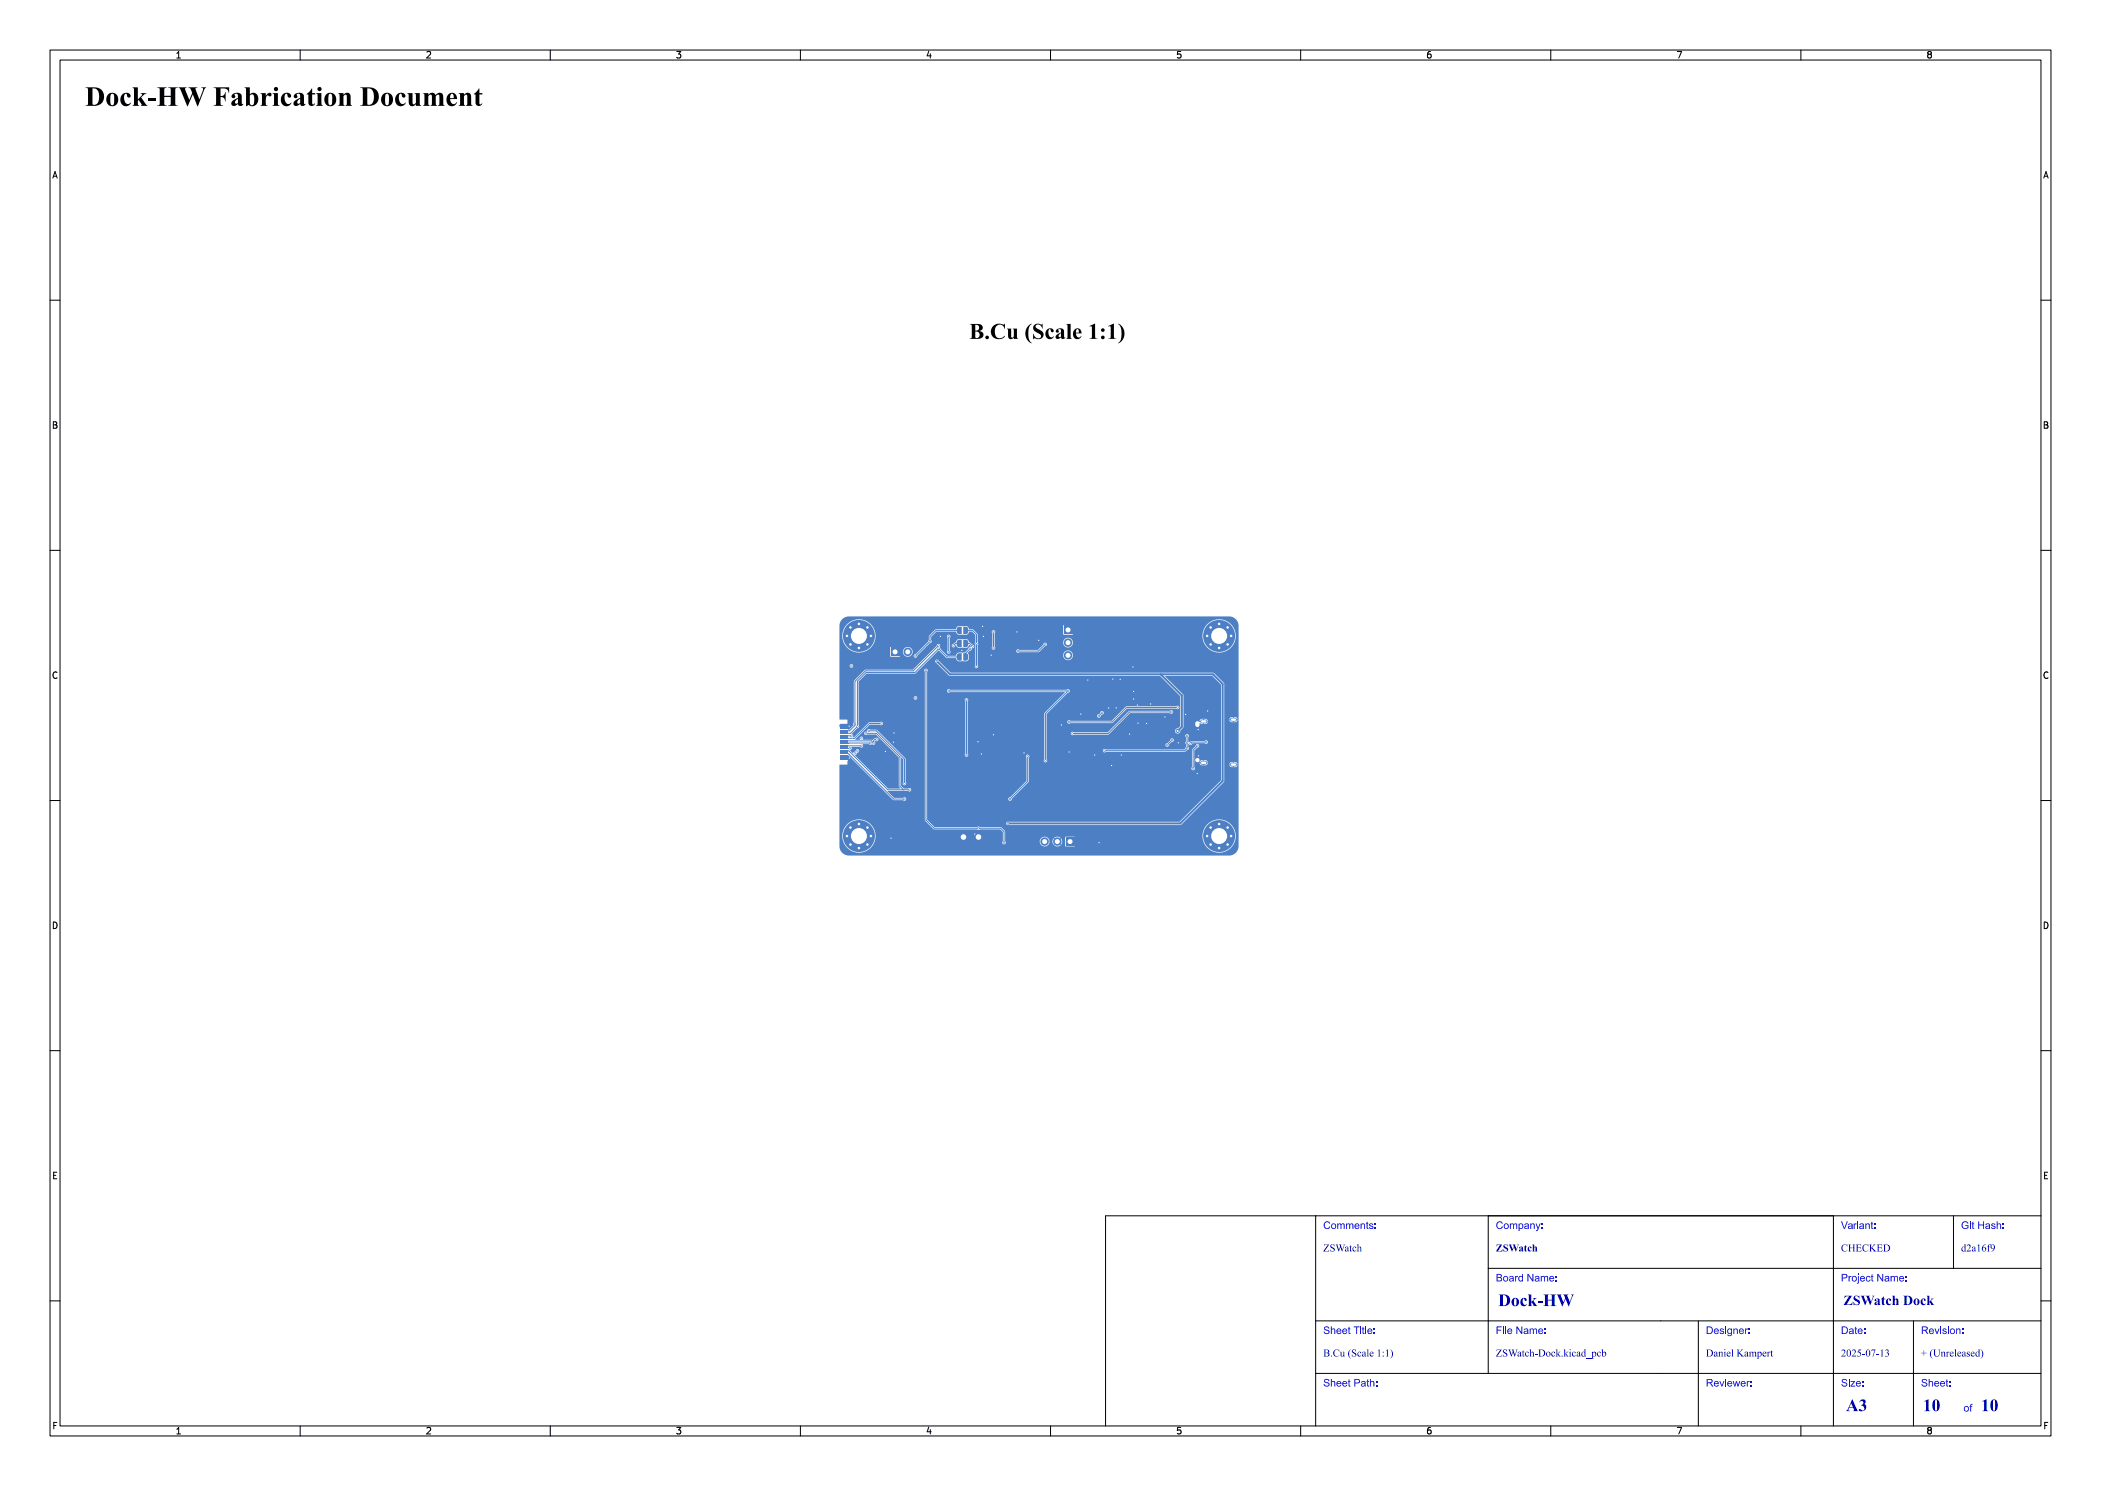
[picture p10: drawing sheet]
<svg xmlns="http://www.w3.org/2000/svg" width="420mm" height="297mm" viewBox="0 0 420 297" stroke-linecap="round" stroke-linejoin="round" font-family="sans-serif">
<defs><g id="words">
<text font-size="5.3" fill="#fff" x="17" y="21.5">Dock-HW Fabrication Document</text>
<text font-size="4.3" fill="#fff" x="188.6" y="68">B.Cu (Scale 1:1)</text>
<g font-size="3.3" fill="#fff">
<text x="299.5" y="261.2">Dock-HW</text>
<text x="369" y="282.2">A3</text>
<text x="384.4" y="282.3">10</text>
<text x="396" y="282.3">10</text>
</g>
<text font-size="2.7" fill="#fff" x="368.5" y="261">ZSWatch Dock</text>
<g font-size="2" fill="#fff">
<text x="264.5" y="245.8">Comments:</text>
<text x="299" y="245.8">Company:</text>
<text x="368" y="245.8">Variant:</text>
<text x="392" y="245.8">Git Hash:</text>
<text x="264.5" y="250.2">ZSWatch</text>
<text x="299" y="250.2">ZSWatch</text>
<text x="368" y="250.2">CHECKED</text>
<text x="392" y="250.2">d2a16f9</text>
<text x="299" y="256.2">Board Name:</text>
<text x="368" y="256.2">Project Name:</text>
<text x="264.5" y="266.8">Sheet Title:</text>
<text x="299" y="266.8">File Name:</text>
<text x="341" y="266.8">Designer:</text>
<text x="368" y="266.8">Date:</text>
<text x="384" y="266.8">Revision:</text>
<text x="264.5" y="271.2">B.Cu (Scale 1:1)</text>
<text x="299" y="271.2">ZSWatch-Dock.kicad_pcb</text>
<text x="341" y="271.2">Daniel Kampert</text>
<text x="368" y="271.2">2025-07-13</text>
<text x="384" y="271.2">+ (Unreleased)</text>
<text x="264.5" y="277.3">Sheet Path:</text>
<text x="341" y="277.2">Reviewer:</text>
<text x="368" y="277.3">Size:</text>
<text x="384" y="277.2">Sheet:</text>
<text x="392.5" y="282.3">of</text>
</g>
<g font-size="1.7" fill="#fff">
<text x="35" y="11.6">1</text>
<text x="85" y="11.6">2</text>
<text x="135" y="11.6">3</text>
<text x="185" y="11.6">4</text>
<text x="235" y="11.6">5</text>
<text x="285" y="11.6">6</text>
<text x="335" y="11.6">7</text>
<text x="385" y="11.6">8</text>
<text x="10.5" y="35.6">A</text>
<text x="408.5" y="35.6">A</text>
<text x="10.5" y="85.6">B</text>
<text x="408.5" y="85.6">B</text>
<text x="10.5" y="135.7">C</text>
<text x="408.5" y="135.7">C</text>
<text x="10.5" y="185.6">D</text>
<text x="408.5" y="185.6">D</text>
<text x="10.5" y="235.7">E</text>
<text x="408.5" y="235.7">E</text>
<text x="10.5" y="285.6">F</text>
<text x="35" y="286.7">1</text>
<text x="85" y="286.7">2</text>
<text x="135" y="286.7">3</text>
<text x="185" y="286.7">4</text>
<text x="235" y="286.7">5</text>
<text x="285" y="286.7">6</text>
<text x="335" y="286.7">7</text>
<text x="385" y="286.7">8</text>
<text x="408.5" y="285.6">F</text>
</g>
</g></defs>
<g fill="#4d7fc4">
<circle cx="241.3" cy="167.1" r=".4"/>
<circle cx="242" cy="165.4" r=".4"/>
<circle cx="242" cy="168.8" r=".4"/>
<circle cx="243.7" cy="164.7" r=".4"/>
<circle cx="243.7" cy="167.1" r="3.2"/>
<circle cx="243.7" cy="169.5" r=".4"/>
<circle cx="245.4" cy="165.4" r=".4"/>
<circle cx="245.4" cy="168.8" r=".4"/>
<circle cx="246.1" cy="167.1" r=".4"/>
</g>
<path d="M240.3 152.4h.6M240.3 144.2h.6M246.3 152.8h.6M246.3 143.8h.6" fill="none" stroke="#4d7fc4" stroke-width=".8"/>
<g fill="#4d7fc4">
<path d="M178.1 129.4h1.7v1.7h-1.7z" fill-rule="evenodd"/>
<path d="M213.1 167.4h1.6v1.6h-1.6z" fill-rule="evenodd"/>
<path d="M167.9 145.4h1.5v.3h-1.5z" fill-rule="evenodd"/>
<path d="M167.9 145.9h1.5v.3h-1.5z" fill-rule="evenodd"/>
<path d="M167.9 146.4h1.5v.3h-1.5z" fill-rule="evenodd"/>
<path d="M167.9 146.9h1.5v.3h-1.5z" fill-rule="evenodd"/>
<path d="M167.9 147.4h1.5v.3h-1.5z" fill-rule="evenodd"/>
<path d="M167.9 147.9h1.5v.3h-1.5z" fill-rule="evenodd"/>
<path d="M167.9 148.4h1.5v.3h-1.5z" fill-rule="evenodd"/>
<path d="M167.9 148.9h1.5v.3h-1.5z" fill-rule="evenodd"/>
<path d="M167.9 149.4h1.5v.3h-1.5z" fill-rule="evenodd"/>
<path d="M167.9 149.9h1.5v.3h-1.5z" fill-rule="evenodd"/>
<path d="M167.9 150.4h1.5v.3h-1.5z" fill-rule="evenodd"/>
<path d="M167.9 150.9h1.5v.3h-1.5z" fill-rule="evenodd"/>
<path d="M167.9 151.4h1.5v.5h-1.5z" fill-rule="evenodd"/>
<path d="M212.7 125.1h1.6v1.7h-1.6z" fill-rule="evenodd"/>
<path d="M192.6 127.9h.6l.3 .3v.7l-.3 .4h-.6z" fill-rule="evenodd"/>
<path d="M191.4 128l.9-.1v1.4h-.6l-.3-.1-.1-.9z" fill-rule="evenodd"/>
<path d="M192.6 130.5l.6 .1 .3 .3v.7l-.3 .4-.6 .1z" fill-rule="evenodd"/>
<path d="M191.4 130.7l.9-.2v1.6l-.6-.1-.3-.1-.1-.9z" fill-rule="evenodd"/>
<path d="M192.6 125.2l.6 .1 .3 .3v.7l-.3 .4-.6 .1z" fill-rule="evenodd"/>
<path d="M191.4 125.4l.9-.2v1.6l-.6-.1-.3-.1-.1-.9z" fill-rule="evenodd"/>
</g>
<g fill="#4d7fc4">
<circle cx="181.5" cy="130.3" r=".85"/>
<circle cx="211.4" cy="168.2" r=".85"/>
<circle cx="208.8" cy="168.2" r=".85"/>
<circle cx="241.3" cy="127.1" r=".4"/>
<circle cx="242" cy="125.4" r=".4"/>
<circle cx="242" cy="128.8" r=".4"/>
<circle cx="243.7" cy="124.7" r=".4"/>
<circle cx="243.7" cy="127.1" r="3.2"/>
<circle cx="243.7" cy="129.5" r=".4"/>
<circle cx="245.4" cy="125.4" r=".4"/>
<circle cx="245.4" cy="128.8" r=".4"/>
<circle cx="246.1" cy="127.1" r=".4"/>
<circle cx="169.3" cy="167.1" r=".4"/>
<circle cx="170" cy="165.4" r=".4"/>
<circle cx="170" cy="168.8" r=".4"/>
<circle cx="171.7" cy="164.7" r=".4"/>
<circle cx="171.7" cy="167.1" r="3.2"/>
<circle cx="171.7" cy="169.5" r=".4"/>
<circle cx="173.4" cy="165.4" r=".4"/>
<circle cx="173.4" cy="168.8" r=".4"/>
<circle cx="174.1" cy="167.1" r=".4"/>
<circle cx="213.5" cy="128.4" r=".85"/>
<circle cx="213.5" cy="131" r=".85"/>
<circle cx="169.3" cy="127.1" r=".4"/>
<circle cx="170" cy="125.4" r=".4"/>
<circle cx="170" cy="128.8" r=".4"/>
<circle cx="171.7" cy="124.7" r=".4"/>
<circle cx="171.7" cy="127.1" r="3.2"/>
<circle cx="171.7" cy="129.5" r=".4"/>
<circle cx="173.4" cy="125.4" r=".4"/>
<circle cx="173.4" cy="128.8" r=".4"/>
<circle cx="174.1" cy="127.1" r=".4"/>
<circle cx="227.4" cy="140.9" r=".22"/>
<circle cx="237" cy="142.8" r=".23"/>
<circle cx="232.9" cy="143.3" r=".23"/>
<circle cx="235.6" cy="148.5" r=".23"/>
<circle cx="196.6" cy="127.2" r=".22"/>
<circle cx="222.2" cy="153" r=".23"/>
<circle cx="178.7" cy="146.5" r=".23"/>
<circle cx="198.6" cy="146.9" r=".22"/>
<circle cx="207.6" cy="128" r=".23"/>
<circle cx="223.9" cy="135.8" r=".23"/>
<circle cx="178.1" cy="167.5" r=".22"/>
<circle cx="225.8" cy="146.7" r=".22"/>
<circle cx="196.2" cy="150.7" r=".23"/>
<circle cx="218.8" cy="150.9" r=".23"/>
<circle cx="196.4" cy="125.2" r=".22"/>
<circle cx="223.1" cy="141.5" r=".22"/>
<circle cx="198.2" cy="131" r=".23"/>
<circle cx="230" cy="140.7" r=".22"/>
<circle cx="217.4" cy="135.9" r=".22"/>
<circle cx="203.3" cy="126.3" r=".22"/>
<circle cx="222.4" cy="135.7" r=".22"/>
<circle cx="226.6" cy="139.7" r=".23"/>
<circle cx="212.2" cy="144.9" r=".22"/>
<circle cx="226.6" cy="138.2" r=".23"/>
<circle cx="192.3" cy="130" r=".22"/>
<circle cx="229.2" cy="144.6" r=".23"/>
<circle cx="216.1" cy="142.7" r=".22"/>
<circle cx="213.7" cy="150.3" r=".23"/>
<circle cx="169.8" cy="145.1" r=".23"/>
<circle cx="224.1" cy="150.9" r=".23"/>
<circle cx="239.5" cy="145.8" r=".23"/>
<circle cx="204.7" cy="150.5" r=".23"/>
<circle cx="221.6" cy="141.5" r=".22"/>
<circle cx="188" cy="127.2" r=".22"/>
<circle cx="219.7" cy="168.4" r=".22"/>
<circle cx="241.4" cy="142.1" r=".23"/>
<circle cx="169.8" cy="151.5" r=".22"/>
<circle cx="226.5" cy="133.3" r=".22"/>
<circle cx="177" cy="150.2" r=".23"/>
<circle cx="178.6" cy="148.3" r=".22"/>
<circle cx="239.3" cy="154.6" r=".22"/>
<circle cx="227.5" cy="144.5" r=".23"/>
<circle cx="195.5" cy="148.2" r=".23"/>
<circle cx="239.6" cy="151.1" r=".22"/>
<circle cx="194.9" cy="166.7" r=".23"/>
<circle cx="189.6" cy="138.1" r=".22"/>
<circle cx="189.6" cy="130.3" r=".22"/>
<circle cx="189.6" cy="127.2" r=".22"/>
<circle cx="213.5" cy="138.1" r=".23"/>
<circle cx="209" cy="152" r=".22"/>
<circle cx="195.2" cy="133.2" r=".22"/>
<circle cx="195.2" cy="128.6" r=".22"/>
<circle cx="193.2" cy="150.9" r=".23"/>
<circle cx="193.2" cy="139.9" r=".22"/>
<circle cx="233.3" cy="148.9" r=".22"/>
<circle cx="234.3" cy="147.9" r=".23"/>
<circle cx="187.7" cy="129.6" r=".22"/>
<circle cx="171.4" cy="145.2" r=".22"/>
<circle cx="171.4" cy="150.1" r=".22"/>
<circle cx="170.9" cy="144.7" r=".22"/>
<circle cx="190.6" cy="129" r=".22"/>
<circle cx="170.9" cy="150.6" r=".22"/>
<circle cx="187.6" cy="129" r=".22"/>
<circle cx="187.3" cy="132.2" r=".23"/>
<circle cx="201.5" cy="164.6" r=".22"/>
<circle cx="235.4" cy="146.1" r=".4"/>
<circle cx="237.3" cy="147.1" r=".23"/>
<circle cx="237.3" cy="148.5" r=".23"/>
<circle cx="220.8" cy="150" r=".22"/>
<circle cx="237.3" cy="149.6" r=".23"/>
<circle cx="172.2" cy="149.1" r=".23"/>
<circle cx="172.2" cy="147.6" r=".23"/>
<circle cx="183" cy="131.1" r=".23"/>
<circle cx="185.9" cy="128.2" r=".22"/>
<circle cx="183" cy="139.5" r=".22"/>
<circle cx="220.3" cy="142.5" r=".22"/>
<circle cx="219.7" cy="143.1" r=".23"/>
<circle cx="213.7" cy="144.3" r=".22"/>
<circle cx="235.4" cy="141.4" r=".23"/>
<circle cx="173.1" cy="146.6" r=".23"/>
<circle cx="181.8" cy="157.8" r=".22"/>
<circle cx="180.8" cy="156.6" r=".22"/>
<circle cx="201.9" cy="159.7" r=".23"/>
<circle cx="180.8" cy="159.7" r=".23"/>
<circle cx="173.7" cy="146.1" r=".23"/>
<circle cx="205.4" cy="151.2" r=".22"/>
<circle cx="198.6" cy="126.3" r=".22"/>
<circle cx="198.6" cy="129.5" r=".22"/>
<circle cx="195.6" cy="165.5" r=".23"/>
<circle cx="185.1" cy="134" r=".23"/>
<circle cx="200.7" cy="168.4" r=".22"/>
<circle cx="194.4" cy="129.2" r=".22"/>
<circle cx="193.9" cy="129.7" r=".23"/>
<circle cx="234.1" cy="142.3" r=".23"/>
<circle cx="214.4" cy="146.6" r=".23"/>
<circle cx="203.5" cy="130.1" r=".22"/>
<circle cx="208.9" cy="128.8" r=".22"/>
<circle cx="238.5" cy="153.6" r=".22"/>
<circle cx="239.4" cy="149.1" r=".23"/>
<circle cx="176.2" cy="144.6" r=".22"/>
<circle cx="170.2" cy="133.1" r=".23"/>
<circle cx="170.2" cy="147.1" r=".22"/>
<circle cx="169.9" cy="149.6" r=".22"/>
<circle cx="238" cy="148.6" r=".23"/>
<circle cx="241.1" cy="148.3" r=".22"/>
<circle cx="174.6" cy="148.5" r=".23"/>
<circle cx="175.3" cy="147.8" r=".22"/>
<circle cx="174" cy="148.5" r=".23"/>
</g>
<g fill="none" stroke="#4d7fc4" stroke-width=".2">
<path d="M185.1 134v29.9l1.6 1.6h13.3l.7 .7v2.2M187.6 129l-5 5.1h-9.6l-2.1 2.1v8.8l-1.1 1.1h-1.2M189.6 138.1h23.9l-4.5 4.5v9.4M189.6 127.2v3.1M191.7 126h-4.6l-1.2 1.2v1l-2.9 2.9M191.7 131.3h-2.4l-1.6-1.6-4.8 4.7h-9.8l-1.7 1.7v9.1l-1.4 1.4h-1.4M191.7 128.6h-.7l-.4 .4M193 126h1.4l.8 .8v6.4M193 128.6h.8l.6 .6M193.2 139.9v11M193.9 129.7l-.9 .8v.8M198.6 126.3v3.2"/>
<path d="M208.9 128.8l-1.3 1.3h-4.1M168.6 149.1h3.6M168.6 150.1h1.1l7.8 7.8h4.3M168.6 150.6h.9l9.1 9.1h2.2M168.6 149.6h1.3M168.6 147.1h1.6M173.1 146.6h2.1l4.7 4.7v5.9l.7 .7M173.7 146.1h1.5l5.6 5.6v4.9M174 148.5l-5.4 .1M175.3 147.8h-.5l-.2 .2v.5l-.4-.4h-5.6M176.2 144.6h-2.4l-3 3h-2.2M205.4 151.2v5l-3.5 3.5"/>
<path d="M220.3 142.5l-.6 .6M234.1 142.3h-8.3l-4.3 4.3h-7.1M234.3 147.9l-1 1M235.4 141.4h-10.2l-2.9 2.9h-8.6M237.3 147.1v2.5l-.5 .4h-16M239.4 149.1l-.9 .8v3.7M241.1 148.3h-2.8l-.3 .3"/>
</g>
<path d="M187.3 132.2l2.6 2.6h52.6l1.9 1.9v19.4l-8.5 8.5h-34.4M232 134.8l4.2 4.2v6.3l-.8 .8" fill="none" stroke="#4d7fc4" stroke-width=".4"/>
<path d="M168.4 123.8l.6-.5 .7-.1h76.2a1.9 1.9 0 0 1 1.7 1.9v44.2a1.9 1.9 0 0 1-1.9 1.7h-76.2a1.91 1.91 0 0 1-1.7-1.9v-2.2h.6a3.3 3.3 0 0 0 3.2 3.5 3.3 3.3 0 0 0 3.4-3.2h17v.2a.56 .56 0 0 0 .7 .4 .56 .56 0 0 0 .5-.6h1.8v.2a.55 .55 0 0 0 .9 .4 .55 .55 0 0 0 0-1 .55 .55 0 0 0-.9 .4h-1.8l-.1-.1a.56 .56 0 0 0-.6-.4 .56 .56 0 0 0-.5 .5h-17v-.3a3.3 3.3 0 0 0-3.3-3.1 3.3 3.3 0 0 0-3.3 3.1h-.6v-14l1.6-.1 .1-.8v-.2h-.8l-.1-.2h.9v-.5h-.8v.5h-.1l.1-.6h.9l8.9 8.9h2a.36 .36 0 0 0 .5 .1 .36 .36 0 0 0 0-.6 .36 .36 0 0 0-.5 .1h-1.8l-1.3-1.4h4.1a.36 .36 0 0 0 .6 0 .36 .36 0 0 0-.1-.5 .36 .36 0 0 0-.5 0h-.8l-.6-.6 .1-5.6 .4 .4v4.5a.36 .36 0 0 0 0 .6 .36 .36 0 0 0 .5-.1 .36 .36 0 0 0-.1-.5v-4.7l-5.7-5.7-1.4-.1a.4 .4 0 0 0-.4 0 .4 .4 0 0 0-.2 .5 .36 .36 0 0 0-.5 0 .36 .36 0 0 0 .1 .6 .36 .36 0 0 0 .5-.1h1.7l4.6 4.6v5.8l.3 .4h-2.5l-6.6-6.6 .4-.6a.38 .38 0 0 0 .4-.4 .38 .38 0 0 0-.5-.3 .38 .38 0 0 0-.2 .5l-.3 .1-.2 .2-.6-.5 .3-.3v-.4h1.7a.39 .39 0 0 0 .6 0 .39 .39 0 0 0-.1-.6h1.3l.4 .2 .2-.2a.4 .4 0 0 0 .6 0 .4 .4 0 0 0-.1-.6l.1-.1a.38 .38 0 0 0 .6 .1 .38 .38 0 0 0 0-.5 .38 .38 0 0 0-.5 0h-.3l-.3 .3-1.9-.1a.38 .38 0 0 0-.1-.5 .38 .38 0 0 0-.5 0 .38 .38 0 0 0 0 .6l-1-.1 3-3h2a.36 .36 0 0 0 .5 .1 .36 .36 0 0 0 0-.6 .36 .36 0 0 0-.5 .1h-2.2l-2.9 2.9h-.3v-.4l-.2-.3 1.5-1.4-.2-.3v-5.4h11a.35 .35 0 0 0 .6 .3 .35 .35 0 0 0 0-.6 .35 .35 0 0 0-.6 .3h-11v-3.2l1.7-1.7h9.6l.8-.6h1l.2 .3v29.7l1.8 1.8h8.6l.3 .1 .3-.1h4l.6 .5v1.8a.36 .36 0 0 0-.1 .6 .36 .36 0 0 0 .6-.1 .36 .36 0 0 0-.1-.5h6.9v.2a.98 .98 0 0 0 1.1 .9 .98 .98 0 0 0 .9-1.1h.6l.2 .7 .4-.3 .1 .1-.4 .4a.98 .98 0 0 0 1.3-.1l-.3-.3 .1-.1 .3 .3a.97 .97 0 0 0 0-1.2l-.3 .3-.1-.1 .3-.3-.2-.2h1.1l.1 1.9 1.9-.1-.1-1.9-3 .1a.97 .97 0 0 0-1.1 .2l.4 .3-.1 .1-.4-.3-.2 .5h-.6a.98 .98 0 0 0-1-.9 .98 .98 0 0 0-1 .9h-6.9v-1.2h39.5v.4a3.3 3.3 0 0 0 5 2.7 3.3 3.3 0 0 0 0-5.8 3.3 3.3 0 0 0-5 2.7h-39.5v-.8l-.8-.8h-4.2l-.3-.1-.3 .1h-8.4l-1.6-1.5v-4.1h16.2a.36 .36 0 0 0 .4 .3 .36 .36 0 0 0 .4-.4l3.3-3.3 .1-2.7h32.4a.36 .36 0 0 0 .6 .3 .36 .36 0 0 0 0-.6v-.9h1.4v.1h-.3v.2l.4 .3h.4v-.3h.1v.3l.4-.1 .3-.4h-.2v-.1h.2v-.2l-.4-.3h-.3v.3h-.1v-.3l-.5 .1-.3 .4h-1.1v-.5l.2 .1a.43 .43 0 0 0 .7 .3 .43 .43 0 0 0 0-.7 .43 .43 0 0 0-.7 .3h-.2v-1.8l.6-.7a.36 .36 0 0 0 .4-.3 .36 .36 0 0 0-.4-.4 .36 .36 0 0 0-.3 .4l-.7 .8v3.4l-.2 .3h-32.4v-2.2a.36 .36 0 0 0-.1-.5 .36 .36 0 0 0-.5 .1 .36 .36 0 0 0 .1 .5v4.6l-3.7 3.6h-16.2v-19.8h7.5l.2 .3v10.4a.36 .36 0 0 0 0 .6 .36 .36 0 0 0 .5-.1 .36 .36 0 0 0-.1-.5v-10.4a.35 .35 0 0 0 0-.6 .35 .35 0 0 0-.6 .3h-7.5v-1.8h4l.1 .2 .2 .2 .3-.2h23l-4.2 4.3v9.2a.36 .36 0 0 0 .1 .5 .36 .36 0 0 0 .5-.1 .36 .36 0 0 0-.1-.5v-1.7h11.2a.37 .37 0 0 0 .3 .4 .37 .37 0 0 0 .4-.1h15.8l.7-.6v-1a.41 .41 0 0 0 .5 .2 .41 .41 0 0 0 .3-.4h2.4a.36 .36 0 0 0 .6 0 .36 .36 0 0 0-.1-.5 .36 .36 0 0 0-.5 .1h-2.6l-.5 .3-.2-.2v-.8a.36 .36 0 0 0 .1-.6 .36 .36 0 0 0-.6 0 .36 .36 0 0 0 .1 .6l-.2 1 .2 .9-.4 .5h-15.7a.35 .35 0 0 0-.6 .2h-11.2v-1.1h23.8l.1 .3 .3 .1 .8-1a.36 .36 0 0 0 .5-.3 .36 .36 0 0 0-.4-.4 .36 .36 0 0 0-.4 .4l-.9 .9h-23.8v-2.3h4.8l.1 .2 .3 .1 .3-.1h6.8l4.4-4.3h8a.36 .36 0 0 0 .5 0 .36 .36 0 0 0 0-.5 .36 .36 0 0 0-.6 .1h-8l-4.4 4.3h-6.7a.35 .35 0 0 0-.4-.1 .35 .35 0 0 0-.3 .3h-4.8v-2.3h4.1l.1 .2 .3 .1 .3-.1h8.3l3-2.9h9.8a.36 .36 0 0 0 .5 .1 .36 .36 0 0 0 0-.6 .36 .36 0 0 0-.5 .1h-9.9l-3 2.9h-8.2a.35 .35 0 0 0-.4-.1 .35 .35 0 0 0-.3 .3h-4.1v-1.2h10.1l.1 .3 .3 .1 .5-.7a.37 .37 0 0 0 .4-.3 .37 .37 0 0 0-.3-.4 .37 .37 0 0 0-.4 .4l-.6 .6h-10.1v-.4l4.2-4.2a.37 .37 0 0 0 .4-.5 .37 .37 0 0 0-.6-.1h-23.3a.35 .35 0 0 0-.4-.1 .35 .35 0 0 0-.2 .3h-4v-3.8a.36 .36 0 0 0 0-.6 .36 .36 0 0 0-.6 .3h-1l1.8-1.9h1.5v.3l2.9 2.7h42l4 4.1v5.9l-.5 .5a.53 .53 0 0 0-.5 .5 .53 .53 0 0 0 .6 .5 .53 .53 0 0 0 .4-.6l.7-.6v-.9h2.3l.1 .5a.43 .43 0 0 0 .4 .3 .43 .43 0 0 0 .4-.4v-.4l.8 .2v-.3h.1v.3h.3l.4-.3v-.1h-.2v-.2h.2l-.3-.4h-.4v.2h-.1v-.2h-.4l-.4 .3v.1h.3v.2h-.4a.45 .45 0 0 0-.4-.1 .45 .45 0 0 0-.4 .3h-2.3v-5.6l-3.7-3.8h9.4l1.8 1.8v19l-8.3 8.3h-34.2a.36 .36 0 0 0-.5 .4 .36 .36 0 0 0 .5 .3l34.5-.1 8.6-8.5v-3.6h1.3v.2h-.3l.1 .1 .4 .3h.3v-.2h.1v.2h.5l.3-.3v-.1h-.3v-.2h.3l-.1-.2-.4-.2h-.3v.3h-.1v-.3h-.3l-.3 .1-.2 .3h-1v-8.9h1.3v.1h-.3l.1 .1 .4 .4h.3v-.3h.1v.3l.5-.1 .3-.4h-.3v-.1h.3l-.1-.3-.4-.2h-.3v.3h-.1v-.3h-.3l-.3 .1-.2 .4h-1v-7.2l-2.2-2.2h-52.4l-2.5-2.4a.35 .35 0 0 0-.4-.2 .35 .35 0 0 0-.2 .3h-1.5l2.2-2.1 1.6 1.5h1.8l.2 .4 .4 .3 1.6-.1 .4-.5v-.6l-.3-.5 .8-.6v-.3a.44 .44 0 0 0 .5-.6l-1-.6-.2-.4-.4-.3-1.6 .1-.3 .2-.1 .4-.4 .3a.38 .38 0 0 0-.4 .4 .38 .38 0 0 0 .4 .3 .38 .38 0 0 0 .3-.5l.4 .4 .3 .2 1.6-.1 .4-.5 .4 .4-.4 .1-.8 1-1.4 .1-.4 .6h-1.7l-1.4-1.4-.1-.3a.37 .37 0 0 0-.1-.6 .37 .37 0 0 0-.6 .3l-4.8 4.7-9.5 .1-2.2 2.2-.1 8.9-.8 .8h-.2l-.1-.2h-.8l-.1-.1h.9l-.1-.2h-.7v.2h-.1v-.2h-.8v-.5l.3-.1h1.3v-.8l-1.6-.1v-10.7h2.1a.35 .35 0 0 0 .4 .3 .35 .35 0 0 0 .2-.5 .35 .35 0 0 0-.6 .1l-2.1 .1v-6.2h.6a3.3 3.3 0 0 0 2 3.3 3.3 3.3 0 0 0 3.7-.8h3.8v1.7l.2 .2h1.7l.1-1.1h.6v.2a.98 .98 0 0 0 1.6 .7h.5a.36 .36 0 0 0 .5 .3 .36 .36 0 0 0 .3-.4l2.5-2.4 .3-.2-.1-1.1 .2-.1h3l.1 .3v2.5a.36 .36 0 0 0 0 .6 .36 .36 0 0 0 .5-.1 .36 .36 0 0 0 0-.5v-2.5a.35 .35 0 0 0-.1-.6 .35 .35 0 0 0-.5 .3h-3l.9-1h3.9l.2 .5 .4 .2h1.5l.3-.2 .2-.5h.6l.7 .7v1.4l-.2 .4 .2 .2v4a.36 .36 0 0 0-.1 .5 .36 .36 0 0 0 .6 0 .36 .36 0 0 0-.1-.5v-2h17.1a.98 .98 0 0 0 1.3 1 .98 .98 0 0 0 .4-1.6 .98 .98 0 0 0-1.6 .4l-.1 .2h-17.1v-.8h7.7a.37 .37 0 0 0 .3 .4 .37 .37 0 0 0 .4-.2h3.8l1.3-1.1a.36 .36 0 0 0 .4-.4 .36 .36 0 0 0-.4-.4 .36 .36 0 0 0-.4 .4l-1 1.1h-3.7a.35 .35 0 0 0-.4-.1 .35 .35 0 0 0-.3 .3h-7.7v-1.2l.2-.2-.2-.4v-1.5l-.4-.5h3.3l.1 .3v2.6a.36 .36 0 0 0-.1 .5 .36 .36 0 0 0 .6 0 .36 .36 0 0 0-.1-.5v-.9h13.7a.98 .98 0 0 0 1.3 1.1 .98 .98 0 0 0 .4-1.7 .98 .98 0 0 0-1.6 .5l-.1 .1h-13.7v-1.4h41.6a3.3 3.3 0 0 0 4.7 3.2 3.3 3.3 0 0 0 .6-5.7 3.3 3.3 0 0 0-5.3 2.2v.3h-41.6v-.3a.35 .35 0 0 0 0-.6 .35 .35 0 0 0-.5 .3h-3.3l-.6-.5h-.7l-.2-.4-.4-.3-1.6 .1-.4 .6h-4l-1.4 1.3-.2 1.1-2.5 2.5-.4 .4-.5-.1a.98 .98 0 0 0-.2-1.6 .98 .98 0 0 0-1.4 .8h-.6l-.1-.9-5.7 .1 .1-.1a3.3 3.3 0 0 0 .1-4.3h38.2l.1 1.8 1.8 .1 .1-.1v-1.8l-.1-.1h-1.8l-.1 .1h-38.2a3.3 3.3 0 0 0-3.6-1.1 3.3 3.3 0 0 0-2.3 3h-.6v-2.1z" fill-rule="evenodd" fill="#4d7fc4"/>
<g fill="#fff">
<circle cx="227.4" cy="140.9" r=".13"/>
<circle cx="237" cy="142.8" r=".12"/>
<circle cx="232.9" cy="143.3" r=".13"/>
<circle cx="235.6" cy="148.5" r=".12"/>
<circle cx="196.6" cy="127.2" r=".13"/>
<circle cx="222.2" cy="153" r=".12"/>
<circle cx="178.7" cy="146.5" r=".13"/>
<circle cx="198.6" cy="146.8" r=".13"/>
<circle cx="207.6" cy="128" r=".12"/>
<circle cx="223.9" cy="135.8" r=".12"/>
<circle cx="178.1" cy="167.5" r=".12"/>
<circle cx="225.8" cy="146.7" r=".13"/>
<circle cx="196.2" cy="150.7" r=".13"/>
<circle cx="218.8" cy="150.9" r=".12"/>
<circle cx="196.4" cy="125.2" r=".13"/>
<circle cx="223.1" cy="141.5" r=".13"/>
<circle cx="198.1" cy="130.9" r=".12"/>
<circle cx="230" cy="140.7" r=".12"/>
<circle cx="217.4" cy="135.9" r=".12"/>
<circle cx="203.3" cy="126.3" r=".13"/>
<circle cx="222.5" cy="135.7" r=".13"/>
<circle cx="226.6" cy="139.7" r=".12"/>
<circle cx="212.2" cy="144.9" r=".13"/>
<circle cx="226.6" cy="138.2" r=".12"/>
<circle cx="192.3" cy="130" r=".13"/>
<circle cx="229.2" cy="144.6" r=".12"/>
<circle cx="216.1" cy="142.7" r=".13"/>
<circle cx="213.7" cy="150.3" r=".12"/>
<circle cx="169.7" cy="145.2" r=".13"/>
<circle cx="224.1" cy="150.9" r=".12"/>
<circle cx="239.5" cy="145.8" r=".13"/>
<circle cx="204.7" cy="150.5" r=".12"/>
<circle cx="221.6" cy="141.5" r=".13"/>
<circle cx="188" cy="127.2" r=".13"/>
<circle cx="219.7" cy="168.4" r=".12"/>
<circle cx="241.4" cy="142.1" r=".12"/>
<circle cx="169.8" cy="151.5" r=".12"/>
<circle cx="226.5" cy="133.3" r=".12"/>
<circle cx="177" cy="150.2" r=".12"/>
<circle cx="178.6" cy="148.3" r=".13"/>
<circle cx="239.3" cy="154.6" r=".13"/>
<circle cx="227.5" cy="144.5" r=".12"/>
<circle cx="195.5" cy="148.2" r=".12"/>
<circle cx="239.6" cy="151.1" r=".12"/>
<circle cx="194.8" cy="166.7" r=".12"/>
<circle cx="189.6" cy="138.1" r=".13"/>
<circle cx="189.7" cy="130.3" r=".12"/>
<circle cx="189.6" cy="127.2" r=".13"/>
<circle cx="213.5" cy="138.1" r=".13"/>
<circle cx="209" cy="152" r=".12"/>
<circle cx="195.2" cy="133.2" r=".12"/>
<circle cx="195.2" cy="128.6" r=".12"/>
<circle cx="193.2" cy="150.9" r=".12"/>
<circle cx="193.2" cy="139.9" r=".13"/>
<circle cx="233.3" cy="148.9" r=".12"/>
<circle cx="234.3" cy="147.9" r=".12"/>
<circle cx="187.7" cy="129.7" r=".13"/>
<circle cx="171.4" cy="145.2" r=".12"/>
<circle cx="171.4" cy="150.1" r=".12"/>
<circle cx="170.9" cy="144.7" r=".13"/>
<circle cx="190.6" cy="129" r=".13"/>
<circle cx="170.9" cy="150.6" r=".13"/>
<circle cx="187.6" cy="129" r=".13"/>
<circle cx="187.3" cy="132.2" r=".13"/>
<circle cx="201.5" cy="164.6" r=".13"/>
<circle cx="235.4" cy="146.1" r=".2"/>
<circle cx="237.3" cy="147.1" r=".13"/>
<circle cx="237.3" cy="148.5" r=".12"/>
<circle cx="220.8" cy="150" r=".12"/>
<circle cx="237.3" cy="149.6" r=".12"/>
<circle cx="172.2" cy="149.1" r=".12"/>
<circle cx="172.2" cy="147.6" r=".13"/>
<circle cx="183" cy="131.1" r=".12"/>
<circle cx="185.9" cy="128.2" r=".13"/>
<circle cx="183" cy="139.5" r=".13"/>
<circle cx="220.3" cy="142.5" r=".12"/>
<circle cx="219.7" cy="143.1" r=".12"/>
<circle cx="213.7" cy="144.3" r=".13"/>
<circle cx="235.4" cy="141.4" r=".12"/>
<circle cx="173.1" cy="146.6" r=".12"/>
<circle cx="181.8" cy="157.9" r=".12"/>
<circle cx="180.8" cy="156.6" r=".13"/>
<circle cx="201.9" cy="159.7" r=".12"/>
<circle cx="180.8" cy="159.7" r=".13"/>
<circle cx="173.7" cy="146.1" r=".12"/>
<circle cx="205.4" cy="151.2" r=".12"/>
<circle cx="198.6" cy="126.3" r=".13"/>
<circle cx="198.6" cy="129.5" r=".13"/>
<circle cx="195.6" cy="165.5" r=".13"/>
<circle cx="185.1" cy="134" r=".12"/>
<circle cx="200.7" cy="168.4" r=".12"/>
<circle cx="194.4" cy="129.2" r=".13"/>
<circle cx="193.9" cy="129.7" r=".12"/>
<circle cx="234.1" cy="142.3" r=".12"/>
<circle cx="214.4" cy="146.6" r=".13"/>
<circle cx="203.5" cy="130.1" r=".12"/>
<circle cx="208.9" cy="128.8" r=".13"/>
<circle cx="238.5" cy="153.6" r=".13"/>
<circle cx="239.4" cy="149.1" r=".12"/>
<circle cx="176.2" cy="144.6" r=".12"/>
<circle cx="170.2" cy="133.1" r=".13"/>
<circle cx="170.2" cy="147.1" r=".13"/>
<circle cx="169.9" cy="149.6" r=".13"/>
<circle cx="238" cy="148.6" r=".12"/>
<circle cx="241.1" cy="148.3" r=".13"/>
<circle cx="174.6" cy="148.5" r=".13"/>
<circle cx="175.3" cy="147.8" r=".12"/>
<circle cx="174" cy="148.5" r=".12"/>
<circle cx="241.3" cy="167.1" r=".25"/>
<circle cx="242" cy="165.4" r=".25"/>
<circle cx="242" cy="168.8" r=".25"/>
<circle cx="243.7" cy="164.7" r=".25"/>
<circle cx="243.7" cy="167.1" r="1.6"/>
<circle cx="243.7" cy="169.5" r=".25"/>
<circle cx="245.4" cy="165.4" r=".25"/>
<circle cx="245.4" cy="168.8" r=".25"/>
<circle cx="246.1" cy="167.1" r=".25"/>
<circle cx="239.4" cy="151.9" r=".33"/>
</g>
<path d="M239.4 144.6v.3" fill="none" stroke="#fff" stroke-width=".65"/>
<path d="M240.3 152.4h.6M240.3 144.2h.6M246.3 152.8h.6M246.3 143.8h.6" fill="none" stroke="#fff" stroke-width=".5"/>
<g fill="#fff">
<circle cx="178.9" cy="130.3" r=".5"/>
<circle cx="181.5" cy="130.3" r=".5"/>
<circle cx="213.9" cy="168.2" r=".5"/>
<circle cx="211.4" cy="168.2" r=".5"/>
<circle cx="208.8" cy="168.2" r=".5"/>
<circle cx="241.3" cy="127.1" r=".25"/>
<circle cx="242" cy="125.4" r=".25"/>
<circle cx="242" cy="128.8" r=".25"/>
<circle cx="243.7" cy="124.7" r=".25"/>
<circle cx="243.7" cy="127.1" r="1.6"/>
<circle cx="243.7" cy="129.5" r=".25"/>
<circle cx="245.4" cy="125.4" r=".25"/>
<circle cx="245.4" cy="128.8" r=".25"/>
<circle cx="246.1" cy="127.1" r=".25"/>
<circle cx="169.3" cy="167.1" r=".25"/>
<circle cx="170" cy="165.4" r=".25"/>
<circle cx="170" cy="168.8" r=".25"/>
<circle cx="171.7" cy="164.7" r=".25"/>
<circle cx="171.7" cy="167.1" r="1.6"/>
<circle cx="171.7" cy="169.5" r=".25"/>
<circle cx="173.4" cy="165.4" r=".25"/>
<circle cx="173.4" cy="168.8" r=".25"/>
<circle cx="174.1" cy="167.1" r=".25"/>
<circle cx="192.6" cy="167.3" r=".45"/>
<circle cx="195.6" cy="167.3" r=".45"/>
<circle cx="213.5" cy="125.9" r=".5"/>
<circle cx="213.5" cy="128.4" r=".5"/>
<circle cx="213.5" cy="131" r=".5"/>
<circle cx="169.3" cy="127.1" r=".25"/>
<circle cx="170" cy="125.4" r=".25"/>
<circle cx="170" cy="128.8" r=".25"/>
<circle cx="171.7" cy="124.7" r=".25"/>
<circle cx="171.7" cy="127.1" r="1.6"/>
<circle cx="171.7" cy="129.5" r=".25"/>
<circle cx="173.4" cy="125.4" r=".25"/>
<circle cx="173.4" cy="128.8" r=".25"/>
<circle cx="174.1" cy="127.1" r=".25"/>
</g>
<g fill="none" stroke="#000" stroke-width=".2">
<path d="M10 10h400v277h-400zM12 12h396v273h-396zM35.3 11.6h.8M35.3 10.7l.4-.4v1.3M60 10v2M85.3 10.4l.5-.1 .3 .4-.8 .9h.8M110 10v2M135.3 10.3h.8l-.4 .5 .3 .1v.6l-.2 .1-.5-.1M160 10v2M185.7 10.2l-.4 1h.9M186 10.7v.9M210 10v2"/>
<path d="M236 10.3h-.6l-.1 .6 .2-.1 .5 .1 .1 .1-.1 .5-.2 .1-.5-.1M260 10v2M286 10.3l-.4 .1-.2 .2-.1 .7 .3 .3 .4-.1 .1-.5-.1-.1-.4-.1-.3 .2M310 10v2M335.3 10.3h.9l-.6 1.3M360 10v2M385.6 10.9l-.3 .2 .1 .4 .2 .1 .4-.1 .1-.2-.1-.3-.2-.1M385.6 10.9l-.3-.3 .3-.3h.2l.3 .2-.3 .4M385.6 10.9h.2M10.6 35.6l.4-1.3 .4 1.3M10.7 35.2h.6M408.6 35.6l.4-1.3 .4 1.3"/>
<path d="M408.7 35.2h.6M10 60h2M408 60h2M10.7 84.3h.4l.2 .2-.2 .4 .2 .1 .1 .3-.2 .3h-.5zM10.7 84.9h.4M408.6 84.3h.5l.2 .2-.2 .4 .2 .1 .1 .3-.3 .3h-.5zM408.6 84.9h.5M10 110h2M408 110h2M11.4 134.4a.62 .62 0 0 0-.9 .5 .62 .62 0 0 0 .7 .7l.2-.1M409.4 134.4a.62 .62 0 0 0-.9 .5 .62 .62 0 0 0 .6 .7l.3-.1M10 160h2"/>
<path d="M408 160h2M10.7 184.3a.66 .66 0 0 1 .7 .6 .66 .66 0 0 1-.7 .7zM408.6 184.3a.66 .66 0 0 1 .8 .6 .66 .66 0 0 1-.8 .7zM10 210h2M408 210h2M10.7 234.9h.5M11.3 234.3h-.6v1.3h.6M408.7 234.9h.4M409.3 234.3h-.6v1.3h.6M10 260h2M408 260h2M10.8 284.9h.4"/>
<path d="M11.4 284.3h-.6v1.3M35.3 285.7l.4-.4v1.3M35.3 286.6h.8M60 285v2M85.3 285.4l.5-.1 .3 .4-.8 .9h.8M110 285v2M135.3 285.3h.8l-.4 .5 .3 .1v.6l-.2 .1-.5-.1M160 285v2M185.7 285.2l-.4 1h.9M186 285.7v.9M210 285v2M236 285.3h-.6l-.1 .6 .2-.1 .5 .1 .1 .1-.1 .5-.2 .1-.5-.1"/>
<path d="M260 285v2M286 285.3l-.4 .1-.2 .2-.1 .7 .3 .3 .4-.1 .1-.5-.1-.1-.4-.1-.3 .2M310 285v2M335.3 285.3h.9l-.6 1.3M360 285v2M385.6 285.9l-.3-.3 .3-.3h.2l.3 .2-.3 .4M385.6 285.9l-.3 .2v.2l.3 .3 .4-.1 .1-.2v-.2l-.3-.2M385.6 285.9h.2M408.7 284.9h.5M409.4 284.3h-.7v1.3"/>
</g>
<g fill="#00007f">
<path d="M384.6 280.1l.9-.4v2.1l.4 .2h-1.2l.3-.1v-1.5v-.3z" fill-rule="evenodd"/>
<path d="M386.5 279.9a.73 .73 0 0 1 .9-.1 .73 .73 0 0 1 .3 .8 1.04 1.04 0 0 1-.8 1.5 .96 .96 0 0 1-.6-1h.5v.7a.2 .2 0 0 0 .2 .2 .2 .2 0 0 0 .2-.3v-1.7a.2 .2 0 0 0-.2-.2 .2 .2 0 0 0-.2 .2v1.1h-.5v-.7z" fill-rule="evenodd"/>
</g>
<g fill="#00f">
<path d="M384.3 275.7l.7-.1 .2 .4-.1 .1a.32 .32 0 0 0-.4-.4 .32 .32 0 0 0-.3 .5h.3a.5 .5 0 0 1 .6 .6 .5 .5 0 0 1-.8 .3l-.4-.3v-.2h.2a.39 .39 0 0 0 .4 .4 .39 .39 0 0 0 .4-.4l-.9-.4v-.2z" fill-rule="evenodd"/>
<path d="M385.5 275.6h.2v.6l.3-.2 .4 .2v.9h-.2v-.7a.27 .27 0 0 0-.3-.2 .27 .27 0 0 0-.2 .3v.6h-.2z" fill-rule="evenodd"/>
<path d="M386.8 276.2a.51 .51 0 0 1 .6-.1 .51 .51 0 0 1 .2 .5h-.8l.3 .4 .5-.2a.52 .52 0 0 1-.6 .3 .52 .52 0 0 1-.3-.6h.8l-.3-.3-.4 .3h-.1z" fill-rule="evenodd"/>
<path d="M388 276.2a.51 .51 0 0 1 .6-.1 .51 .51 0 0 1 .2 .5h-.8l.2 .4 .6-.2a.52 .52 0 0 1-.6 .3 .52 .52 0 0 1-.4-.6h.8l-.3-.3-.3 .3h-.2z" fill-rule="evenodd"/>
<path d="M389.1 275.8l.2-.1v.3h.1v.2h-.1v.6l.2 .3a.27 .27 0 0 1-.3 0 .27 .27 0 0 1-.1-.3v-.6h-.2z" fill-rule="evenodd"/>
<path d="M389.7 276h.2v.2h-.2z" fill-rule="evenodd"/>
<path d="M389.7 276.9h.2v.2h-.2z" fill-rule="evenodd"/>
<path d="M392.7 281.1a.54 .54 0 0 1 .9 .1 .54 .54 0 0 1-.3 .8 .54 .54 0 0 1-.7-.4h.2a.37 .37 0 0 0 .5 .4 .37 .37 0 0 0 0-.7l-.3-.1-.2 .4h-.2z" fill-rule="evenodd"/>
<path d="M393.9 280.7l.4-.1v.2l-.3 .1 .2 .3h-.2v.9h-.2v-.9h-.1z" fill-rule="evenodd"/>
</g>
<g fill="#00007f">
<path d="M396.2 280.1l.9-.4v2.1l.4 .2h-1.2l.3-.1v-1.5v-.3z" fill-rule="evenodd"/>
<path d="M398.1 279.9a.73 .73 0 0 1 .9-.1 .73 .73 0 0 1 .3 .8 1.04 1.04 0 0 1-.8 1.5 .95 .95 0 0 1-.6-1h.5v.7a.2 .2 0 0 0 .2 .2 .2 .2 0 0 0 .2-.3v-1.7a.2 .2 0 0 0-.2-.2 .2 .2 0 0 0-.2 .2v1.1h-.5v-.7z" fill-rule="evenodd"/>
</g>
<g fill="#00f">
<path d="M368.3 275.7l.7-.1 .2 .4-.1 .1a.32 .32 0 0 0-.4-.4 .32 .32 0 0 0-.3 .5h.3a.5 .5 0 0 1 .6 .6 .5 .5 0 0 1-.8 .3l-.4-.3v-.2h.2a.39 .39 0 0 0 .4 .4 .39 .39 0 0 0 .4-.4l-.9-.4v-.2z" fill-rule="evenodd"/>
<path d="M369.5 275.6h.2v.2h-.2z" fill-rule="evenodd"/>
<path d="M369.5 276h.2v1.1h-.2z" fill-rule="evenodd"/>
<path d="M369.9 276h.9l-.7 1h.8v.1h-1l.7-.9h-.7z" fill-rule="evenodd"/>
<path d="M371.1 276.2a.51 .51 0 0 1 .6-.1 .51 .51 0 0 1 .3 .5h-.8l.2 .4 .6-.2a.52 .52 0 0 1-.7 .3 .52 .52 0 0 1-.3-.6h.8l-.3-.3-.3 .3h-.2z" fill-rule="evenodd"/>
<path d="M372.3 276h.2v.2h-.2z" fill-rule="evenodd"/>
<path d="M372.3 276.9h.2v.2h-.2z" fill-rule="evenodd"/>
</g>
<g fill="#00007f">
<path d="M370.3 279.7l.9 2.1 .3 .2h-1.1l.2-.1-.1-.5h-.9l-.1 .5 .3 .1h-.8l.6-.8h.8l-.3-.7-.4 .7h-.1z" fill-rule="evenodd"/>
<path d="M371.9 279.9a.55 .55 0 0 1 .8-.2 .55 .55 0 0 1 0 .9 .81 .81 0 0 1 .1 1.2 .81 .81 0 0 1-1.2 0l.2-.2a.54 .54 0 0 0 .8 .2 .72 .72 0 0 0-.6-1 .41 .41 0 0 0 .5-.3 .41 .41 0 0 0-.3-.5 .41 .41 0 0 0-.5 .3z" fill-rule="evenodd"/>
</g>
<path d="M366.5 274.5h41.5M382.5 274.5v10.5M408 264h-41.5v21" fill="none" stroke="#000" stroke-width=".2"/>
<g fill="#00f">
<path d="M384.2 265.1h.6a.42 .42 0 0 1 .6 .4 .42 .42 0 0 1-.5 .4l.6 .7h-.3l-.4-.6h-.2h-.2v.6h-.2v-.8l.9-.1a.25 .25 0 0 0 0-.3 .25 .25 0 0 0-.3-.1h-.4v.5h-.2z" fill-rule="evenodd"/>
<path d="M385.7 265.7l.1-.1a.51 .51 0 0 1 .6 0 .51 .51 0 0 1 .2 .5h-.8l.2 .4 .6-.2a.52 .52 0 0 1-.7 .3 .52 .52 0 0 1-.3-.6h.8l-.3-.3-.3 .3h-.2z" fill-rule="evenodd"/>
<path d="M386.7 265.5h.2l.3 .9 .3-.9h.2l-.4 1.1h-.2z" fill-rule="evenodd"/>
<path d="M387.9 265.1h.2v.2h-.2z" fill-rule="evenodd"/>
<path d="M387.9 265.5h.2v1.1h-.2z" fill-rule="evenodd"/>
<path d="M388.4 265.6l.5-.1 .2 .3h-.2a.21 .21 0 0 0-.2-.2 .21 .21 0 0 0-.1 .3 .43 .43 0 0 1 .4 .1 .43 .43 0 0 1 .1 .4l-.2 .2h-.4l-.2-.3h.1a.24 .24 0 0 0 .3 .3 .24 .24 0 0 0 .2-.4 .43 .43 0 0 1-.6-.5z" fill-rule="evenodd"/>
<path d="M389.4 265.1h.2v.2h-.2z" fill-rule="evenodd"/>
<path d="M389.4 265.5h.2v1.1h-.2z" fill-rule="evenodd"/>
<path d="M390 265.6a.54 .54 0 0 1 .8 .1 .54 .54 0 0 1-.3 .8 .54 .54 0 0 1-.7-.4h.2a.37 .37 0 0 0 .5 .4 .37 .37 0 0 0 .1-.7l-.4-.1-.2 .4h-.2z" fill-rule="evenodd"/>
<path d="M391 265.5h.2v.2l.3-.2a.35 .35 0 0 1 .4 .5v.6h-.2v-.6a.27 .27 0 0 0-.3-.3 .27 .27 0 0 0-.2 .3v.6h-.2z" fill-rule="evenodd"/>
<path d="M392.2 265.5h.2v.2h-.2z" fill-rule="evenodd"/>
<path d="M392.2 266.4h.2v.2h-.2z" fill-rule="evenodd"/>
</g>
<g fill="#00007f">
<path d="M384 270.4h.5l.1-.5v.5l.5 .1h-.5l-.1 .5v-.5z" fill-rule="evenodd"/>
<path d="M386.1 269.8l.3-.1a1.42 1.42 0 0 0 0 1.9l-.5-.6a1.13 1.13 0 0 1 .2-1.2z" fill-rule="evenodd"/>
<path d="M386.4 269.7h.6l-.2 .2v.7a.41 .41 0 0 0 .4 .5 .41 .41 0 0 0 .4-.6v-.7l-.2-.1h.5l-.2 .2v.6a.55 .55 0 0 1-.6 .7 .55 .55 0 0 1-.5-.7v-.7z" fill-rule="evenodd"/>
<path d="M387.9 270.3l.4-.1v.2a.29 .29 0 0 1 .3-.2 .29 .29 0 0 1 .2 .3v.5l.2 .1h-.5l.2-.2-.1-.5-.1-.1-.2 .1v.6l.1 .1h-.4l.1-.1v-.6z" fill-rule="evenodd"/>
<path d="M389 270.3l.3-.1v.2l.2-.2h.2l-.4 .3v.5l.2 .1h-.5l.1-.1v-.6z" fill-rule="evenodd"/>
<path d="M389.9 270.3l.4-.1 .2 .2v.1h-.6l.2 .4 .3 .1 .1-.2a.41 .41 0 0 1-.6 .3 .41 .41 0 0 1-.1-.6h.5l-.2-.3-.3 .3z" fill-rule="evenodd"/>
<path d="M390.7 269.8l.3-.1v1.3l.1 .1h-.4l.1-.1v-.9v-.3z" fill-rule="evenodd"/>
<path d="M391.4 270.3l.4-.1 .2 .2 .1 .1h-.7l.2 .4 .3 .1 .1-.2a.41 .41 0 0 1-.5 .3 .41 .41 0 0 1-.2-.6h.5l-.2-.3-.3 .3z" fill-rule="evenodd"/>
<path d="M392.3 270.2l.5 .1 .1 .7 .1-.1-.1 .2-.2-.1-.2 .1h-.2l-.1-.2 .3 .1 .2-.1v-.3l-.5 .3 .5-.4-.2-.3-.2 .3z" fill-rule="evenodd"/>
<path d="M393.2 270.2h.5v.3l-.2-.3-.2 .1 .1 .2a.34 .34 0 0 1 .4 .5 .34 .34 0 0 1-.6 .1v-.3l.2 .3 .2-.2-.4-.4z" fill-rule="evenodd"/>
<path d="M394.1 270.3l.4-.1 .2 .2v.1h-.6l.1 .4 .3 .1 .2-.2a.41 .41 0 0 1-.6 .3 .41 .41 0 0 1-.1-.6h.5l-.2-.3-.3 .3z" fill-rule="evenodd"/>
<path d="M395.4 269.8l.3-.1v1.3h.2l-.6 .2-.4-.2v-.4h.2l.1 .4 .3-.1-.1-.7-.3 .1v.3h-.2v-.1a.41 .41 0 0 1 .6-.3v-.4z" fill-rule="evenodd"/>
<path d="M395.9 269.7a1.08 1.08 0 0 1 0 1.9 1.42 1.42 0 0 0 0-1.9z" fill-rule="evenodd"/>
</g>
<path d="M382.5 264v10.5" fill="none" stroke="#000" stroke-width=".2"/>
<g fill="#00f">
<path d="M368.2 265.1h.5a.75 .75 0 0 1 .7 .8 .75 .75 0 0 1-.7 .7h-.5v-.2h.5a.58 .58 0 0 0 .5-.5 .58 .58 0 0 0-.5-.6h-.3v1.1h-.2z" fill-rule="evenodd"/>
<path d="M369.7 265.6l.2-.1a.47 .47 0 0 1 .5 .1 .47 .47 0 0 1 .1 .6l.1 .4-.2-.1-.5 .1-.3-.1v-.2l.6 .2 .1-.4-.7 .2a.57 .57 0 0 1 .7-.4l-.1-.2-.6 .1z" fill-rule="evenodd"/>
<path d="M370.9 265.3l.1-.1v.3h.2v.2h-.2v.6l.2 .3a.27 .27 0 0 1-.3 0 .27 .27 0 0 1 0-.3v-.6h-.2z" fill-rule="evenodd"/>
<path d="M371.5 265.7l.1-.1a.51 .51 0 0 1 .5 0 .51 .51 0 0 1 .2 .5h-.8l.3 .4 .5-.2a.52 .52 0 0 1-.6 .3 .52 .52 0 0 1-.4-.6h.9l-.3-.3-.4 .3h-.2z" fill-rule="evenodd"/>
<path d="M372.6 265.5h.2v.2h-.2z" fill-rule="evenodd"/>
<path d="M372.6 266.4h.2v.2h-.2z" fill-rule="evenodd"/>
</g>
<path d="M408 253.5h-41.5v10.5" fill="none" stroke="#000" stroke-width=".2"/>
<g fill="#00f">
<path d="M368.2 254.6h.5a.46 .46 0 0 1 .6 .5 .46 .46 0 0 1-.6 .4h-.3v.6h-.2v-.8h.7l.2-.2-.2-.3h-.5v.5h-.2z" fill-rule="evenodd"/>
<path d="M369.5 255h.2v.2l.4-.2v.2a.24 .24 0 0 0-.3 .1 .24 .24 0 0 0-.1 .3v.5h-.2z" fill-rule="evenodd"/>
<path d="M370.3 255.1a.55 .55 0 0 1 .9 .1 .55 .55 0 0 1-.3 .8 .55 .55 0 0 1-.7-.4h.2a.37 .37 0 0 0 .5 .4 .37 .37 0 0 0 0-.7l-.3-.1-.2 .4h-.2z" fill-rule="evenodd"/>
<path d="M371.4 254.6h.2v.2h-.2z" fill-rule="evenodd"/>
<path d="M371.4 255h.2v1.2a.3 .3 0 0 1-.1 .3 .3 .3 0 0 1-.3 0l.2-.2z" fill-rule="evenodd"/>
<path d="M371.9 255.2a.51 .51 0 0 1 .7-.1 .51 .51 0 0 1 .2 .5h-.8l.2 .4 .6-.2a.52 .52 0 0 1-.6 .3 .52 .52 0 0 1-.4-.6h.8l-.3-.3-.3 .3h-.2z" fill-rule="evenodd"/>
<path d="M373.1 255.1h.6l.2 .3h-.2a.34 .34 0 0 0-.5-.2 .34 .34 0 0 0 0 .6l.3 .2 .2-.3h.2a.53 .53 0 0 1-.8 .3 .53 .53 0 0 1 0-.8z" fill-rule="evenodd"/>
<path d="M374.1 254.8l.2-.1v.3h.2v.2h-.2v.6l.2 .3a.27 .27 0 0 1-.3 0 .27 .27 0 0 1-.1-.3v-.6h-.1z" fill-rule="evenodd"/>
<path d="M375.3 254.6h.2l.8 1.2v-1.2h.2v1.5h-.2l-.8-1.2v1.2h-.2z" fill-rule="evenodd"/>
<path d="M376.9 255.1l.1-.1a.47 .47 0 0 1 .6 .1 .47 .47 0 0 1 0 .6l.1 .4-.2-.1-.5 .1-.3-.1v-.2l.6 .2 .2-.4-.8 .2a.57 .57 0 0 1 .8-.4l-.2-.2-.6 .1z" fill-rule="evenodd"/>
<path d="M377.9 255h.2v.2l.3-.2 .3 .2 .3-.2 .3 .1 .1 1h-.2l-.1-.9a.26 .26 0 0 0-.2 0 .26 .26 0 0 0-.1 .3v.6h-.2v-.8l-.4-.1-.1 .9h-.2z" fill-rule="evenodd"/>
<path d="M379.8 255.2a.51 .51 0 0 1 .6-.1 .51 .51 0 0 1 .2 .5h-.8l.3 .4 .5-.2a.52 .52 0 0 1-.6 .3 .52 .52 0 0 1-.4-.6h.8l-.3-.3-.3 .3h-.2z" fill-rule="evenodd"/>
<path d="M380.9 255h.2v.2h-.2z" fill-rule="evenodd"/>
<path d="M380.9 255.9h.2v.2h-.2z" fill-rule="evenodd"/>
</g>
<g fill="#00007f">
<path d="M368.2 269.8a.42 .42 0 0 1 .6 .1 .42 .42 0 0 1-.1 .6l-.4 .5 .7-.1-.1 .2h-.9a.88 .88 0 0 0 .6-1.2h-.2l-.3 .2z" fill-rule="evenodd"/>
<path d="M369.3 269.8l.2-.1a.7 .7 0 0 1 .5 .7 .7 .7 0 0 1-.6 .7l-.3-.5 .2-.1a.36 .36 0 0 0 0 .4 .36 .36 0 0 0 .4 .1l.1-.8-.2-.4a.42 .42 0 0 0-.3 .7l-.2-.1z" fill-rule="evenodd"/>
<path d="M370.3 269.8a.42 .42 0 0 1 .6 .1 .42 .42 0 0 1-.1 .6l-.4 .5 .7-.1-.1 .2h-.9a.88 .88 0 0 0 .6-1.2h-.2l-.3 .2z" fill-rule="evenodd"/>
<path d="M371.6 269.7h.5l-.1 .2h-.4l-.1 .2a.5 .5 0 0 1 .5 .6 .5 .5 0 0 1-.7 .3 .4 .4 0 0 0 .6-.2 .4 .4 0 0 0-.5-.5h-.1z" fill-rule="evenodd"/>
<path d="M372.3 270.6h.5v.1h-.5z" fill-rule="evenodd"/>
<path d="M373.2 269.8l.1-.1a.7 .7 0 0 1 .6 .7 .7 .7 0 0 1-.6 .7l-.3-.5 .2-.1a.36 .36 0 0 0-.1 .4 .36 .36 0 0 0 .4 .1l.2-.6-.2-.6a.42 .42 0 0 0-.3 .7l-.2-.1z" fill-rule="evenodd"/>
<path d="M374.2 269.7h.7l-.5 1.4h-.1l.4-1.2h-.5l-.1 .2z" fill-rule="evenodd"/>
<path d="M375.1 270.6h.5v.1h-.5z" fill-rule="evenodd"/>
<path d="M375.9 269.9l.4-.2v1.3l.2 .1h-.5l.1-.1v-1z" fill-rule="evenodd"/>
<path d="M377 269.8h.4a.31 .31 0 0 1 0 .5 .44 .44 0 0 1 .1 .7 .44 .44 0 0 1-.6 0 .35 .35 0 0 0 .5-.1 .35 .35 0 0 0-.3-.5 .28 .28 0 0 0 .3-.2 .28 .28 0 0 0-.2-.3 .28 .28 0 0 0-.3 .1z" fill-rule="evenodd"/>
</g>
<g fill="#00f">
<path d="M341.2 275.6h.6a.42 .42 0 0 1 .6 .4 .42 .42 0 0 1-.5 .4l.6 .7h-.3a.74 .74 0 0 0-.8-.6v.6h-.2v-.8l.9-.1a.25 .25 0 0 0 0-.3 .25 .25 0 0 0-.3-.1h-.4v.5h-.2z" fill-rule="evenodd"/>
<path d="M342.7 276.2a.51 .51 0 0 1 .6-.1 .51 .51 0 0 1 .3 .5h-.8l.2 .4 .6-.2a.52 .52 0 0 1-.7 .3 .52 .52 0 0 1-.3-.6h.8l-.3-.3-.3 .3h-.2z" fill-rule="evenodd"/>
<path d="M343.7 276h.2l.3 .9 .3-.9h.2l-.4 1.1h-.2z" fill-rule="evenodd"/>
<path d="M344.9 275.6h.2v.2h-.2z" fill-rule="evenodd"/>
<path d="M344.9 276h.2v1.1h-.2z" fill-rule="evenodd"/>
<path d="M345.4 276.2a.51 .51 0 0 1 .6-.1 .51 .51 0 0 1 .3 .5h-.8l.2 .4 .6-.2a.52 .52 0 0 1-.7 .3 .52 .52 0 0 1-.3-.6h.8l-.3-.3-.3 .3h-.2z" fill-rule="evenodd"/>
<path d="M346.4 276h.2l.2 .9 .2-.9h.2l.2 .9 .3-.9h.2l-.4 1.1h-.2l-.2-.8-.2 .8h-.2z" fill-rule="evenodd"/>
<path d="M348.1 276.2a.51 .51 0 0 1 .6-.1 .51 .51 0 0 1 .3 .5h-.9l.3 .4 .6-.2a.52 .52 0 0 1-.7 .3 .52 .52 0 0 1-.3-.6h.8l-.3-.3-.3 .3h-.2z" fill-rule="evenodd"/>
<path d="M349.2 276h.1v.2l.4-.2v.2a.24 .24 0 0 0-.3 .1 .24 .24 0 0 0 0 .3v.5h-.2z" fill-rule="evenodd"/>
<path d="M349.9 276h.2v.2h-.2z" fill-rule="evenodd"/>
<path d="M349.9 276.9h.2v.2h-.2z" fill-rule="evenodd"/>
</g>
<path d="M332 274.5h34.5M339.5 274.5v10.5" fill="none" stroke="#000" stroke-width=".2"/>
<g fill="#00f">
<path d="M341.2 265.1h.5a.75 .75 0 0 1 .7 .8 .75 .75 0 0 1-.7 .7h-.5v-.2h.5a.58 .58 0 0 0 .5-.5 .58 .58 0 0 0-.5-.6h-.3v1.1h-.2z" fill-rule="evenodd"/>
<path d="M342.7 265.7l.1-.1a.51 .51 0 0 1 .6 0 .51 .51 0 0 1 .2 .5h-.8l.2 .4 .6-.2a.52 .52 0 0 1-.7 .3 .52 .52 0 0 1-.3-.6h.8l-.3-.3-.3 .3h-.2z" fill-rule="evenodd"/>
<path d="M343.8 265.6l.6-.1 .2 .3h-.2a.21 .21 0 0 0-.2-.2 .21 .21 0 0 0-.2 .3 .43 .43 0 0 1 .5 .1 .43 .43 0 0 1 .1 .4l-.2 .2h-.4l-.3-.3h.2a.24 .24 0 0 0 .3 .3 .24 .24 0 0 0 .2-.4 .43 .43 0 0 1-.6-.5z" fill-rule="evenodd"/>
<path d="M344.9 265.1h.2v.2h-.2z" fill-rule="evenodd"/>
<path d="M344.9 265.5h.2v1.1h-.2z" fill-rule="evenodd"/>
<path d="M345.4 265.6l.3-.1 .4 .2v-.2h.1v1a.48 .48 0 0 1-.3 .5 .48 .48 0 0 1-.6-.3l.5 .2 .2-.1v-.3a.47 .47 0 0 1-.5 0 .47 .47 0 0 1-.2-.4h.2a.34 .34 0 0 0 .4 .3 .34 .34 0 0 0 .1-.5 .3 .3 0 0 0-.3-.2 .3 .3 0 0 0-.2 .4h-.2z" fill-rule="evenodd"/>
<path d="M346.5 265.5h.2v.2l.3-.2a.35 .35 0 0 1 .4 .5v.6h-.2v-.6a.27 .27 0 0 0-.3-.3 .27 .27 0 0 0-.2 .3v.6h-.2z" fill-rule="evenodd"/>
<path d="M347.7 265.7l.1-.1a.51 .51 0 0 1 .6 0 .51 .51 0 0 1 .2 .5h-.8l.2 .4 .6-.2a.52 .52 0 0 1-.6 .3 .52 .52 0 0 1-.4-.6h.8l-.3-.3-.3 .3h-.2z" fill-rule="evenodd"/>
<path d="M348.8 265.5h.2v.2l.4-.2v.2a.24 .24 0 0 0-.3 .1 .24 .24 0 0 0-.1 .3v.5h-.2z" fill-rule="evenodd"/>
<path d="M349.6 265.5h.2v.2h-.2z" fill-rule="evenodd"/>
<path d="M349.6 266.4h.2v.2h-.2z" fill-rule="evenodd"/>
</g>
<path d="M332 264h34.5M339.5 264v10.5" fill="none" stroke="#000" stroke-width=".2"/>
<g fill="#00007f">
<path d="M341 269.7h.6a.7 .7 0 0 1 .8 .7 .7 .7 0 0 1-.7 .7h-.7l.2-.1v-1.2h.2v1.2a.65 .65 0 0 0 .8-.7 .65 .65 0 0 0-1-.5z" fill-rule="evenodd"/>
<path d="M342.7 270.2l.5 .1 .1 .7 .1-.1-.1 .2-.7-.1v-.1l.3 .1 .2-.1v-.3l-.5 .3 .5-.4-.2-.3-.3 .3z" fill-rule="evenodd"/>
<path d="M343.5 270.3l.3-.1v.2a.29 .29 0 0 1 .3-.2 .29 .29 0 0 1 .2 .3v.5l.2 .1h-.5l.2-.2v-.5l-.2-.1-.2 .1v.6l.1 .1h-.4l.1-.1v-.6z" fill-rule="evenodd"/>
<path d="M344.6 270.3l.3-.1v.8l.1 .1h-.4l.1-.1v-.5z" fill-rule="evenodd"/>
<path d="M345.3 270.3l.4-.1 .2 .2 .1 .1h-.7l.2 .4 .3 .1 .1-.2a.41 .41 0 0 1-.5 .3 .41 .41 0 0 1-.2-.6h.5l-.2-.3-.3 .3z" fill-rule="evenodd"/>
<path d="M346.1 269.8l.3-.1v1.3l.2 .1h-.5l.1-.1v-1.1z" fill-rule="evenodd"/>
<path d="M347.2 269.7h.5l-.1 .1-.1 .6 .6-.5-.1-.2h.5l-.8 .7 1 .7h-.7l.1-.1-.6-.6 .1 .6 .1 .1h-.5l.2-.2-.1-1z" fill-rule="evenodd"/>
<path d="M348.8 270.2l.6 .1v.7l.2-.1-.2 .2-.7-.1v-.1l.3 .1 .2-.1v-.3l-.5 .3 .5-.4-.1-.3-.3 .3z" fill-rule="evenodd"/>
<path d="M349.6 270.3l.3-.1v.2l.3-.2 .3 .2a.3 .3 0 0 1 .3-.2 .3 .3 0 0 1 .2 .3l.1 .5 .1 .1h-.5l.2-.1v-.5a.2 .2 0 0 0-.2-.2 .2 .2 0 0 0-.2 .2v.5l.1 .1h-.4l.1-.1v-.5l-.1-.2-.3 .1v.6l.2 .1h-.5l.1-.1v-.5z" fill-rule="evenodd"/>
<path d="M351.2 270.3l.3-.1v.2a.39 .39 0 0 1 .6-.1 .39 .39 0 0 1 0 .5l-.2 .3h-.4v.4l.2 .1h-.5l.2-.2v-1h.1l.1 .6a.33 .33 0 0 0 .4-.3 .33 .33 0 0 0-.4-.3h-.2z" fill-rule="evenodd"/>
<path d="M352.4 270.3l.4-.1 .3 .2v.1h-.6l.1 .4 .3 .1 .2-.2a.41 .41 0 0 1-.6 .3 .41 .41 0 0 1-.1-.6h.5l-.2-.3-.3 .3z" fill-rule="evenodd"/>
<path d="M353.2 270.3l.3-.1v.2l.2-.2h.2l-.4 .3v.5l.2 .1h-.5l.1-.1 .1-.5z" fill-rule="evenodd"/>
<path d="M354.2 269.9v.3h.2h-.2v.7h.3l-.3 .2-.1-.1-.1-.8h-.1z" fill-rule="evenodd"/>
<circle cx="344.8" cy="269.8" r=".1"/>
</g>
<path d="M332 264h-34.5v10.5h34.5" fill="none" stroke="#000" stroke-width=".2"/>
<g fill="#00007f">
<path d="M299.2 269.7h1l-.9 1.3h.7l.2-.3v.4h-1.2l.9-1.3h-.6l-.2 .3z" fill-rule="evenodd"/>
<path d="M300.5 269.8l.7-.1v.5a.29 .29 0 0 0-.3-.4 .29 .29 0 0 0-.2 .4h.1a.49 .49 0 0 1 .5 .3 .49 .49 0 0 1-.2 .6l-.7 .1 .1-.5a.33 .33 0 0 0 .3 .4 .33 .33 0 0 0 .3-.4l-.1-.1a.51 .51 0 0 1-.5-.2 .51 .51 0 0 1 0-.6z" fill-rule="evenodd"/>
<path d="M301.5 269.7h.5l-.1 .2 .3 .9 .2-.7-.3-.4h.6l-.2 .2 .3 .9 .3-.9-.1-.2h.4l-.6 1.5-.3-.9-.4 .9z" fill-rule="evenodd"/>
<path d="M303.5 270.2l.5 .1v.7l.2-.1-.1 .2-.7-.1-.1-.1 .4 .1 .2-.1v-.3l-.6 .3 .6-.4-.2-.3-.3 .3z" fill-rule="evenodd"/>
<path d="M304.5 269.9v.3h.3h-.3v.7h.3l-.3 .2-.1-.1v-.8h-.2z" fill-rule="evenodd"/>
<path d="M305 270.3l.4-.1 .2 .1-.1 .2a.28 .28 0 0 0-.4-.3 .28 .28 0 0 0-.1 .5l.3 .3 .3-.2a.43 .43 0 0 1-.6 .3 .43 .43 0 0 1-.1-.7z" fill-rule="evenodd"/>
<path d="M305.7 269.8l.3-.1v.7l.3-.2h.2l.1 .8 .1 .1h-.4l.1-.2v-.5l-.1-.1-.3 .1 .1 .6 .1 .1h-.5l.2-.1v-.9z" fill-rule="evenodd"/>
<path d="M306.8 270.6h.6v.1h-.6z" fill-rule="evenodd"/>
<path d="M307.5 269.7h.6a.7 .7 0 0 1 .8 .7 .7 .7 0 0 1-.8 .7h-.6l.2-.1v-1.2h.2v1.2a.65 .65 0 0 0 .7-.7 .65 .65 0 0 0-.9-.5z" fill-rule="evenodd"/>
<path d="M309.2 270.3a.46 .46 0 0 1 .7 .1 .46 .46 0 0 1-.3 .7 .46 .46 0 0 1-.6-.5h.2a.34 .34 0 0 0 .1 .4 .34 .34 0 0 0 .5-.1 .34 .34 0 0 0-.1-.4l-.2-.3-.3 .4h-.2z" fill-rule="evenodd"/>
<path d="M310.2 270.3l.4-.1 .2 .1v.2a.28 .28 0 0 0-.4-.3 .28 .28 0 0 0-.1 .5l.2 .3 .4-.2a.43 .43 0 0 1-.7 .3 .43 .43 0 0 1 0-.7z" fill-rule="evenodd"/>
<path d="M311 269.8l.3-.1v.9l.3-.3v-.1h.4l-.5 .3 .5 .6h-.4l-.3-.5v.4l.1 .1h-.4l.1-.2v-1z" fill-rule="evenodd"/>
<path d="M312.5 269.8l.4-.1v.9l.3-.3-.1-.1h.4l-.5 .3 .6 .6h-.5l-.2-.5v.4l.1 .1h-.5l.2-.2v-1z" fill-rule="evenodd"/>
<path d="M313.6 270.3l.4-.1v.8l.1 .1h-.4l.1-.1v-.5z" fill-rule="evenodd"/>
<path d="M314.4 270.3l.4-.1 .2 .1-.1 .2a.28 .28 0 0 0-.4-.3 .28 .28 0 0 0-.1 .5l.2 .3 .4-.2a.43 .43 0 0 1-.6 .3 .43 .43 0 0 1-.1-.7z" fill-rule="evenodd"/>
<path d="M315.3 270.2l.5 .1 .1 .7 .1-.1-.1 .2-.7-.1v-.1l.3 .1 .2-.1v-.3l-.5 .3 .5-.4-.2-.3-.3 .3z" fill-rule="evenodd"/>
<path d="M316.6 269.8l.3-.1v1.3h.2l-.6 .2-.3-.2-.1-.4h.2l.2 .4 .3-.1-.2-.7-.2 .1-.1 .3h-.2v-.1a.41 .41 0 0 1 .7-.3l-.1-.4z" fill-rule="evenodd"/>
<path d="M317.1 271.5l1 .1z" fill-rule="evenodd"/>
<path d="M318.1 270.3l.3-.1v.2a.39 .39 0 0 1 .6-.1 .39 .39 0 0 1 .1 .5l-.3 .3h-.4l.1 .4 .1 .1h-.5l.2-.2v-1h.1l.1 .6a.33 .33 0 0 0 .4-.3 .33 .33 0 0 0-.4-.3h-.2z" fill-rule="evenodd"/>
<path d="M319.4 270.3l.4-.1 .2 .1-.1 .2a.28 .28 0 0 0-.4-.3 .28 .28 0 0 0-.1 .5l.2 .3 .4-.2a.43 .43 0 0 1-.6 .3 .43 .43 0 0 1-.1-.7z" fill-rule="evenodd"/>
<path d="M320.1 269.8l.3-.1v.6a.45 .45 0 0 1 .7 .3 .45 .45 0 0 1-.5 .6l-.3-.2v-.6h.1v.6a.32 .32 0 0 0 .5-.3 .32 .32 0 0 0-.5-.3h-.1v-.5z" fill-rule="evenodd"/>
<circle cx="312.3" cy="271" r=".11"/>
<circle cx="313.9" cy="269.8" r=".1"/>
</g>
<path d="M366.5 253.5h-69v10.5" fill="none" stroke="#000" stroke-width=".2"/>
<g fill="#00f">
<path d="M299.2 254.6l.9 .1 .1 .3-.2 .3a.42 .42 0 0 1 .3 .6 .42 .42 0 0 1-.6 .2h-.5v-.2l.9-.1-.1-.3-.6-.1v.5h-.2v-.7h.5a.24 .24 0 0 0 .3-.1 .24 .24 0 0 0-.2-.3h-.4v.4h-.2z" fill-rule="evenodd"/>
<path d="M300.6 255.1a.55 .55 0 0 1 .9 .1 .55 .55 0 0 1-.3 .8 .55 .55 0 0 1-.7-.4h.2a.37 .37 0 0 0 .5 .4 .37 .37 0 0 0 0-.7l-.3-.1-.2 .4h-.2z" fill-rule="evenodd"/>
<path d="M301.8 255.2l.1-.2a.47 .47 0 0 1 .6 .1 .47 .47 0 0 1 .1 .6v.4l-.2-.1-.5 .1-.2-.1-.1-.2 .6 .2 .2-.4-.8 .2a.57 .57 0 0 1 .8-.4l-.2-.2-.5 .1z" fill-rule="evenodd"/>
<path d="M302.9 255h.1v.2l.4-.2v.2a.25 .25 0 0 0-.3 .1 .25 .25 0 0 0 0 .3v.5h-.2z" fill-rule="evenodd"/>
<path d="M303.7 255.1l.3-.1 .3 .2v-.6h.1v1.5h-.1v-.1l-.2 .1h-.4l-.2-.4 .2-.1a.34 .34 0 0 0 .4 .4 .34 .34 0 0 0 .2-.6l-.4-.2-.2 .4h-.2z" fill-rule="evenodd"/>
<path d="M305.3 254.6h.2l.8 1.2v-1.2h.2v1.5h-.2l-.8-1.2v1.2h-.2z" fill-rule="evenodd"/>
<path d="M306.9 255.2l.1-.2a.47 .47 0 0 1 .6 .1 .47 .47 0 0 1 .1 .6l.1 .4-.3-.1-.4 .1-.3-.1v-.2l.6 .2 .1-.4-.7 .2a.57 .57 0 0 1 .7-.4l-.1-.2-.6 .1z" fill-rule="evenodd"/>
<path d="M308 255h.2v.2l.2-.2 .4 .2 .3-.2 .2 .1 .2 1h-.2l-.1-.9a.26 .26 0 0 0-.3 0 .26 .26 0 0 0-.1 .3v.6h-.2v-.8l-.3-.1-.1 .9h-.2z" fill-rule="evenodd"/>
<path d="M309.8 255.2a.51 .51 0 0 1 .6-.1 .51 .51 0 0 1 .3 .5h-.8l.2 .4 .6-.2a.52 .52 0 0 1-.7 .3 .52 .52 0 0 1-.3-.6h.8l-.3-.3-.3 .3h-.2z" fill-rule="evenodd"/>
<path d="M311 255h.2v.2h-.2z" fill-rule="evenodd"/>
<path d="M311 255.9h.2v.2h-.2z" fill-rule="evenodd"/>
<path d="M368 244.1h.2l.5 1.4 .5-1.4h.2l-.6 1.5h-.2z" fill-rule="evenodd"/>
<path d="M369.6 244.6l.1-.1a.47 .47 0 0 1 .5 .1 .47 .47 0 0 1 .1 .6l.1 .4-.2-.1-.5 .1-.3-.1v-.2l.6 .2 .2-.4-.8 .2a.57 .57 0 0 1 .8-.4l-.2-.2-.6 .1z" fill-rule="evenodd"/>
<path d="M370.5 244.5h.2v.2l.4-.2v.2a.25 .25 0 0 0-.3 .1 .25 .25 0 0 0-.1 .3v.5h-.2z" fill-rule="evenodd"/>
<path d="M371.2 244.1h.2v.2h-.2z" fill-rule="evenodd"/>
<path d="M371.2 244.5h.2v1.1h-.2z" fill-rule="evenodd"/>
<path d="M371.8 244.6l.1-.1a.47 .47 0 0 1 .6 .1 .47 .47 0 0 1 .1 .6l.1 .4-.3-.1-.5 .1-.2-.1v-.2l.6 .2 .1-.4-.7 .2a.57 .57 0 0 1 .7-.4l-.2-.2-.5 .1z" fill-rule="evenodd"/>
<path d="M372.9 244.5h.1v.2l.4-.2a.35 .35 0 0 1 .4 .5v.6h-.2v-.6a.27 .27 0 0 0-.3-.3 .27 .27 0 0 0-.2 .3v.6h-.2z" fill-rule="evenodd"/>
<path d="M374.1 244.3l.2-.1v.3h.2v.2h-.2v.6l.2 .3a.27 .27 0 0 1-.3 0 .27 .27 0 0 1-.1-.3v-.6h-.2z" fill-rule="evenodd"/>
<path d="M374.7 244.5h.2v.2h-.2z" fill-rule="evenodd"/>
<path d="M374.7 245.4h.2v.2h-.2z" fill-rule="evenodd"/>
</g>
<path d="M408 243h-41.5v10.5" fill="none" stroke="#000" stroke-width=".2"/>
<g fill="#00007f">
<path d="M368.3 248.9l1-.2v.5a.53 .53 0 0 0-.7-.4 .53 .53 0 0 0-.3 .8l.1 .3 .3 .2 .4-.1 .2-.2a.6 .6 0 0 1-1 .2 .78 .78 0 0 1 0-1.1z" fill-rule="evenodd"/>
<path d="M369.4 248.7h.6l-.2 .1v.6h.7v-.6l-.2-.1h.6l-.2 .3v1l.2 .1h-.6l.2-.1v-.5h-.7v.5l.2 .1h-.6l.2-.2v-1z" fill-rule="evenodd"/>
<path d="M371 248.7h1v.3l-.1-.2h-.5v.6l.4-.1 .1-.1v.4l-.1-.1-.4-.1v.6a.51 .51 0 0 0 .7-.2l-.1 .3h-1l.2-.2v-1z" fill-rule="evenodd"/>
<path d="M372.5 248.9l1-.2v.5a.53 .53 0 0 0-.7-.4 .53 .53 0 0 0-.3 .8l.1 .3 .3 .2 .4-.1 .2-.2a.6 .6 0 0 1-1 .2 .78 .78 0 0 1 0-1.1z" fill-rule="evenodd"/>
<path d="M373.6 248.7h.6l-.2 .1v.6l.5-.5-.1-.2h.5l-.7 .7 .9 .7h-.6l.1-.1-.6-.6v.6l.2 .1h-.6l.2-.2v-1z" fill-rule="evenodd"/>
<path d="M375.2 248.7h1v.3l-.1-.2h-.6v.6l.5-.1 .1-.1v.4l-.1-.1-.5-.1 .1 .6a.51 .51 0 0 0 .7-.2l-.1 .3h-1l.2-.2-.1-1z" fill-rule="evenodd"/>
<path d="M376.4 248.7h.6a.7 .7 0 0 1 .8 .7 .7 .7 0 0 1-.7 .7h-.7l.2-.1v-1.2h.2v1.2a.65 .65 0 0 0 .8-.7 .65 .65 0 0 0-1-.5z" fill-rule="evenodd"/>
</g>
<path d="M366.5 243h-69v10.5" fill="none" stroke="#000" stroke-width=".2"/>
<g fill="#00f">
<path d="M299.3 244.3l.7-.2 .4 .3-.2 .2a.53 .53 0 0 0-.8-.2 .53 .53 0 0 0 0 .8l.4 .3 .3-.1 .1-.3h.2a.74 .74 0 0 1-1.1 .4 .74 .74 0 0 1 0-1.2z" fill-rule="evenodd"/>
<path d="M300.8 244.6a.54 .54 0 0 1 .8 .1 .54 .54 0 0 1-.3 .8 .54 .54 0 0 1-.7-.4h.2a.37 .37 0 0 0 .5 .4 .37 .37 0 0 0 .1-.7l-.4-.1-.2 .4h-.2z" fill-rule="evenodd"/>
<path d="M301.8 244.5h.2v.2l.4-.2 .2 .2 .3-.2 .3 .1 .1 1h-.2l-.1-.9a.26 .26 0 0 0-.3 0 .26 .26 0 0 0 0 .3v.6h-.2l-.1-.8-.3-.1-.1 .9h-.2z" fill-rule="evenodd"/>
<path d="M303.6 244.5h.1v.2a.5 .5 0 0 1 .8 .4 .5 .5 0 0 1-.7 .4v.5h-.2v-.9h.1a.33 .33 0 0 0 .4 .4 .33 .33 0 0 0 .2-.5l-.1-.3h-.2l-.3 .4h-.1z" fill-rule="evenodd"/>
<path d="M304.8 244.6l.1-.1a.47 .47 0 0 1 .6 .1 .47 .47 0 0 1 .1 .6l.1 .4-.3-.1-.4 .1-.3-.1v-.2l.6 .2 .1-.4-.7 .2a.57 .57 0 0 1 .7-.4l-.1-.2-.6 .1z" fill-rule="evenodd"/>
<path d="M305.9 244.5h.2v.2l.3-.2a.35 .35 0 0 1 .4 .5v.6h-.2v-.6a.27 .27 0 0 0-.3-.3 .27 .27 0 0 0-.2 .3v.6h-.2z" fill-rule="evenodd"/>
<path d="M307 244.5h.2l.3 .9 .3-.9h.2l-.6 1.4-.2 .2-.1-.1-.1-.1 .3-.1 .1-.2z" fill-rule="evenodd"/>
<path d="M308.2 244.5h.2v.2h-.2z" fill-rule="evenodd"/>
<path d="M308.2 245.4h.2v.2h-.2z" fill-rule="evenodd"/>
</g>
<g fill="#00007f">
<path d="M299.2 248.7h1.1l-.8 1.3a.68 .68 0 0 0 .9-.4l-.1 .5h-1.3l.9-1.3a.54 .54 0 0 0-.8 .3z" fill-rule="evenodd"/>
<path d="M300.6 248.8l.8-.1v.5l-.4-.4-.3 .2 .2 .2a.52 .52 0 0 1 .5 .7 .52 .52 0 0 1-.8 .2l-.1 .1v-.6a.35 .35 0 0 0 .3 .5 .35 .35 0 0 0 .4-.3l-.6-.5z" fill-rule="evenodd"/>
<path d="M301.6 248.7h.6l-.1 .2 .3 .8 .2-.5-.3-.5h.7l-.2 .1 .3 .8 .3-.7-.1-.2 .3 .1-.6 1.4-.4-.9-.4 .9z" fill-rule="evenodd"/>
<path d="M303.7 249.3l.4-.2 .3 .1v.8h.2l-.1 .1-.4-.1-.2 .1-.2-.1v-.1h.4v-.3l-.2 .3h-.2l.4-.4v-.2h-.2a.15 .15 0 0 1 0 .2 .15 .15 0 0 1-.2 0 .15 .15 0 0 1 0-.2z" fill-rule="evenodd"/>
<path d="M305 248.8v.4h.3l-.3 .1 .1 .7 .2-.1-.3 .2-.2-.1v-.7l-.2-.1z" fill-rule="evenodd"/>
<path d="M305.5 249.3l.5-.1 .1 .3h-.2l-.1-.3a.37 .37 0 0 0-.1 .5 .37 .37 0 0 0 .5 .2 .47 .47 0 0 1-.8 .1 .47 .47 0 0 1 .1-.7z" fill-rule="evenodd"/>
<path d="M306.3 248.7h.4v.6l.2-.2a.29 .29 0 0 1 .3 .4l.1 .6h-.4v-.8l-.2 .1 .1 .7h-.5l.1-.2z" fill-rule="evenodd"/>
<path d="M368.7 259h1.5l-1.1 1.7a.91 .91 0 0 0 1.2-.5l-.1 .6h-1.7l1.1-1.7a.73 .73 0 0 0-.9 .4z" fill-rule="evenodd"/>
<path d="M370.7 259.1l.4-.2 .4 .2 .2-.2-.1 .7a.41 .41 0 0 0-.3-.6 .41 .41 0 0 0-.5 .4l.2 .1a.82 .82 0 0 1 .8 1l-.4 .3h-.7l-.2 .1 .1-.7a.48 .48 0 0 0 .3 .5 .48 .48 0 0 0 .6-.3l-.2-.2a.72 .72 0 0 1-.7-1z" fill-rule="evenodd"/>
<path d="M371.9 259h.8l-.1 .2 .4 1 .3-.7-.4-.5h.9l-.2 .1 .4 1.1 .4-1-.2-.2h.5l-.8 1.9-.5-1.2-.6 1.2z" fill-rule="evenodd"/>
<path d="M374.8 259.7l.2-.1a.47 .47 0 0 1 .5-.1 .47 .47 0 0 1 .2 .5l.1 .6h.1l-.4 .2a.35 .35 0 0 0-.6 0l-.2-.1v-.2h.7v-.4l-.3 .4h-.4l.7-.5-.1-.3h-.3a.2 .2 0 0 1 .1 .3 .2 .2 0 0 1-.3 0 .2 .2 0 0 1 0-.3z" fill-rule="evenodd"/>
<path d="M376.5 259.1l.1 .5h.3v.1h-.3v.9h.3l-.1 .2a.35 .35 0 0 1-.5 0 .35 .35 0 0 1-.1-.4v-.7l-.2-.1z" fill-rule="evenodd"/>
<path d="M377.2 259.7a.4 .4 0 0 1 .5-.2 .4 .4 0 0 1 .2 .5h-.2l-.1-.4a.5 .5 0 0 0-.2 .6 .5 .5 0 0 0 .6 .4v-.1a.58 .58 0 0 1-.8 .2 .58 .58 0 0 1-.1-.8z" fill-rule="evenodd"/>
<path d="M378.2 259h.6v.7a.4 .4 0 0 1 .5-.2 .4 .4 0 0 1 .2 .6v.6l.1 .1h-.6l.1-.2-.1-.9-.2 .2 .1 .9h-.7l.2-.2v-1.5z" fill-rule="evenodd"/>
<path d="M380.4 259h.9a.93 .93 0 0 1 1 .9 .93 .93 0 0 1-1 .9h-.9l.3-.1v-.2h.4l.1 .2a.57 .57 0 0 0 .6-.8 .64 .64 0 0 0-.7-.8v1.4h-.4v-1.3z" fill-rule="evenodd"/>
<path d="M382.8 259.6a.62 .62 0 0 1 .8 .2 .62 .62 0 0 1-.2 .9 .62 .62 0 0 1-.8-.2l-.1-.2h.4v.3a.18 .18 0 0 0 .2 .2 .18 .18 0 0 0 .2-.2v-.8a.19 .19 0 0 0-.3-.2 .19 .19 0 0 0-.1 .3v.4h-.4z" fill-rule="evenodd"/>
<path d="M384.1 259.7a.4 .4 0 0 1 .5-.2 .4 .4 0 0 1 .3 .5h-.2l-.2-.4a.5 .5 0 0 0-.2 .6 .5 .5 0 0 0 .6 .4v-.1a.58 .58 0 0 1-.8 .2 .58 .58 0 0 1-.1-.8z" fill-rule="evenodd"/>
<path d="M385.1 259h.6v1.2l.4-.5-.1-.1h.5l-.5 .4 .6 .8h-.6l.1-.1-.3-.5-.1 .5 .1 .1h-.7l.2-.2v-1.5z" fill-rule="evenodd"/>
<path d="M299.5 258.7h1.1a1.17 1.17 0 0 1 1.3 1.2 1.17 1.17 0 0 1-1.3 1.1h-1.1l.3-.1 .1-.2h.5v.1a.53 .53 0 0 0 .7 0 .53 .53 0 0 0 .1-.6 .93 .93 0 0 0-.8-1.4v1.9h-.5v-1.7z" fill-rule="evenodd"/>
<path d="M302.5 259.5a.79 .79 0 0 1 1.1 .8 .79 .79 0 0 1-1.3 .5l-.1-.4h.5v.3a.22 .22 0 0 0 .2 .3 .22 .22 0 0 0 .2-.2v-1.1a.23 .23 0 0 0-.3-.2 .23 .23 0 0 0-.1 .3v.6h-.5v-.5z" fill-rule="evenodd"/>
<path d="M304.2 259.6a.5 .5 0 0 1 .6-.2 .5 .5 0 0 1 .3 .6 .36 .36 0 0 1-.4-.4l-.1-.1a.42 .42 0 0 0-.2 .7 .51 .51 0 0 0 .3 .6 .51 .51 0 0 0 .5-.1 .77 .77 0 0 1-1.1 .2 .77 .77 0 0 1 0-1.2z" fill-rule="evenodd"/>
<path d="M305.4 258.7h.7v1.5l.5-.5-.1-.3h.7l-.7 .6 .8 1h-.8l.1-.1-.4-.6-.1 .6 .2 .1h-.9l.2-.3v-1.8z" fill-rule="evenodd"/>
<path d="M307.4 260.1h1v.3h-1z" fill-rule="evenodd"/>
<path d="M308.5 258.7h1.2l-.3 .2v.9h.8v-.9l-.3-.2h1.2l-.3 .1v.3v1.7l.3 .2h-1.2l.3-.1v-1h-.8v1l.3 .1h-1.2l.3-.1v-.3v-1.6z" fill-rule="evenodd"/>
<path d="M311.2 258.7h1l-.2 .3 .5 1.3 .4-.9-.2-.5-.3-.2h1.1l-.2 .2 .5 1.3 .4-1.2-.2-.3 .6 .1-.2 .1-.8 2.2-.6-1.5-.7 1.5z" fill-rule="evenodd"/>
</g>
<path d="M263 274.5h34.5M297.5 264h-34.5v21" fill="none" stroke="#000" stroke-width=".2"/>
<g fill="#00f">
<path d="M299.2 265.1h1v.2h-.8v.5h.7v.1h-.7v.7h-.2z" fill-rule="evenodd"/>
<path d="M300.4 265.1h.2v.2h-.2z" fill-rule="evenodd"/>
<path d="M300.4 265.5h.2v1.1h-.2z" fill-rule="evenodd"/>
<path d="M300.9 265.1h.2v1.5h-.2z" fill-rule="evenodd"/>
<path d="M301.4 265.7l.1-.1a.51 .51 0 0 1 .6 0 .51 .51 0 0 1 .2 .5h-.8l.2 .4 .6-.2a.52 .52 0 0 1-.7 .3 .52 .52 0 0 1-.3-.6h.8l-.3-.3-.3 .3h-.2z" fill-rule="evenodd"/>
<path d="M303.1 265.1h.2l.8 1.2v-1.2h.2v1.5h-.2l-.8-1.2v1.2h-.2z" fill-rule="evenodd"/>
<path d="M304.7 265.6l.1-.1a.47 .47 0 0 1 .6 .1 .47 .47 0 0 1 .1 .6l.1 .4-.3-.1-.5 .1-.2-.1v-.2l.6 .2 .1-.4-.7 .2a.57 .57 0 0 1 .7-.4l-.2-.2-.5 .1z" fill-rule="evenodd"/>
<path d="M305.8 265.5h.1v.2l.5-.2 .2 .2 .2-.2 .3 .1 .2 1h-.2l-.1-.9a.26 .26 0 0 0-.3 0 .26 .26 0 0 0-.1 .3v.6h-.2v-.8l-.3-.1-.1 .9h-.2z" fill-rule="evenodd"/>
<path d="M307.6 265.7l.1-.1a.51 .51 0 0 1 .6 0 .51 .51 0 0 1 .2 .5h-.8l.2 .4 .6-.2a.52 .52 0 0 1-.7 .3 .52 .52 0 0 1-.3-.6h.8l-.3-.3-.3 .3h-.2z" fill-rule="evenodd"/>
<path d="M308.8 265.5h.2v.2h-.2z" fill-rule="evenodd"/>
<path d="M308.8 266.4h.2v.2h-.2z" fill-rule="evenodd"/>
<path d="M264.8 265.2l.7-.1 .2 .4-.1 .1a.32 .32 0 0 0-.4-.4 .32 .32 0 0 0-.3 .5h.3a.5 .5 0 0 1 .6 .6 .5 .5 0 0 1-.8 .3l-.4-.3v-.2h.2a.39 .39 0 0 0 .4 .4 .39 .39 0 0 0 .4-.4l-.9-.4v-.2z" fill-rule="evenodd"/>
<path d="M266 265.1h.2v.6l.3-.2 .4 .2v.9h-.2v-.7a.27 .27 0 0 0-.3-.2 .27 .27 0 0 0-.2 .3v.6h-.2z" fill-rule="evenodd"/>
<path d="M267.3 265.7l.1-.1a.51 .51 0 0 1 .5 0 .51 .51 0 0 1 .2 .5h-.8l.3 .4 .5-.2a.52 .52 0 0 1-.6 .3 .52 .52 0 0 1-.3-.6h.8l-.3-.3-.4 .3h-.1z" fill-rule="evenodd"/>
<path d="M268.5 265.7v-.1a.51 .51 0 0 1 .6 0 .51 .51 0 0 1 .2 .5h-.8l.2 .4 .6-.2a.52 .52 0 0 1-.6 .3 .52 .52 0 0 1-.4-.6h.8l-.3-.3-.3 .3h-.2z" fill-rule="evenodd"/>
<path d="M269.6 265.3l.2-.1v.3h.1v.2h-.1v.6l.2 .3a.27 .27 0 0 1-.3 0 .27 .27 0 0 1-.1-.3v-.6h-.2z" fill-rule="evenodd"/>
<path d="M270.6 265.1h1.2v.2h-.5v1.3h-.2v-1.3h-.5z" fill-rule="evenodd"/>
<path d="M271.9 265.1h.2v.2h-.2z" fill-rule="evenodd"/>
<path d="M271.9 265.5h.2v1.1h-.2z" fill-rule="evenodd"/>
<path d="M272.4 265.3l.2-.1v.3h.1v.2h-.1v.6l.2 .3a.27 .27 0 0 1-.3 0 .27 .27 0 0 1-.1-.3v-.6h-.2z" fill-rule="evenodd"/>
<path d="M272.9 265.1h.2v1.5h-.2z" fill-rule="evenodd"/>
<path d="M273.5 265.7v-.1a.51 .51 0 0 1 .6 0 .51 .51 0 0 1 .2 .5h-.8l.3 .4 .5-.2a.52 .52 0 0 1-.6 .3 .52 .52 0 0 1-.4-.6h.8l-.3-.3-.3 .3h-.2z" fill-rule="evenodd"/>
<path d="M274.6 265.5h.2v.2h-.2z" fill-rule="evenodd"/>
<path d="M274.6 266.4h.2v.2h-.2z" fill-rule="evenodd"/>
<path d="M264.8 275.7l.7-.1 .2 .4-.1 .1a.32 .32 0 0 0-.4-.4 .32 .32 0 0 0-.3 .5h.3a.5 .5 0 0 1 .6 .6 .5 .5 0 0 1-.8 .3l-.4-.3v-.2h.2a.39 .39 0 0 0 .4 .4 .39 .39 0 0 0 .4-.4l-.9-.4v-.2z" fill-rule="evenodd"/>
<path d="M266 275.6h.2v.6l.3-.2 .4 .2v.9h-.2v-.7a.27 .27 0 0 0-.3-.2 .27 .27 0 0 0-.2 .3v.6h-.2z" fill-rule="evenodd"/>
<path d="M267.3 276.2a.51 .51 0 0 1 .6-.1 .51 .51 0 0 1 .2 .5h-.8l.3 .4 .5-.2a.52 .52 0 0 1-.6 .3 .52 .52 0 0 1-.3-.6h.8l-.3-.3-.4 .3h-.1z" fill-rule="evenodd"/>
<path d="M268.5 276.2a.51 .51 0 0 1 .6-.1 .51 .51 0 0 1 .2 .5h-.8l.2 .4 .6-.2a.52 .52 0 0 1-.6 .3 .52 .52 0 0 1-.4-.6h.8l-.3-.3-.3 .3h-.2z" fill-rule="evenodd"/>
<path d="M269.6 275.8l.2-.1v.3h.1v.2h-.1v.6l.2 .3a.27 .27 0 0 1-.3 0 .27 .27 0 0 1-.1-.3v-.6h-.2z" fill-rule="evenodd"/>
<path d="M270.7 275.6h.6a.46 .46 0 0 1 .6 .5 .46 .46 0 0 1-.6 .4h-.4v.6h-.2v-.8h.8l.2-.2-.2-.3h-.6v.5h-.2z" fill-rule="evenodd"/>
<path d="M272.2 276.2l.1-.2a.47 .47 0 0 1 .6 .1 .47 .47 0 0 1 .1 .6v.4l-.2-.1-.5 .1-.2-.1-.1-.2 .6 .2 .2-.4-.8 .2a.57 .57 0 0 1 .8-.4l-.2-.2-.5 .1z" fill-rule="evenodd"/>
<path d="M273.3 275.8l.2-.1v.3h.2v.2h-.2v.6l.2 .3a.27 .27 0 0 1-.3 0 .27 .27 0 0 1-.1-.3v-.6h-.1z" fill-rule="evenodd"/>
<path d="M273.9 275.6h.1v.6l.4-.2 .3 .1v1h-.1v-.7a.27 .27 0 0 0-.4-.2 .27 .27 0 0 0-.2 .3v.6h-.1z" fill-rule="evenodd"/>
<path d="M275.1 276h.2v.2h-.2z" fill-rule="evenodd"/>
<path d="M275.1 276.9h.2v.2h-.2z" fill-rule="evenodd"/>
</g>
<g fill="#00007f">
<path d="M264.5 269.7h.6a.38 .38 0 0 1 .6 .2 .38 .38 0 0 1-.2 .5 .39 .39 0 0 1 .3 .5 .39 .39 0 0 1-.6 .2h-.7l.2-.1v-.5h.2v.5a.37 .37 0 0 0 .5 0 .37 .37 0 0 0 0-.5 .37 .37 0 0 0-.5 0h-.2v-.7h.2v.6a.35 .35 0 0 0 .5-.1 .35 .35 0 0 0 0-.4 .35 .35 0 0 0-.5-.1z" fill-rule="evenodd"/>
<path d="M266.7 269.9l1-.2v.5a.53 .53 0 0 0-.7-.4 .53 .53 0 0 0-.3 .8l.1 .3 .4 .2 .3-.1 .2-.2a.6 .6 0 0 1-1 .2 .78 .78 0 0 1 0-1.1z" fill-rule="evenodd"/>
<path d="M267.8 270.2h.4v.7l.1 .1 .2-.1v-.6l-.1-.1h.3v.8h.2l-.4 .2v-.2l-.2 .1h-.2l-.1-.8z" fill-rule="evenodd"/>
<path d="M269.8 269.8l.2-.1a1.42 1.42 0 0 0 0 1.9l-.4-.6a1.12 1.12 0 0 1 .2-1.2z" fill-rule="evenodd"/>
<path d="M270.3 269.8l.8-.1-.1 .5a.29 .29 0 0 0-.2-.4 .29 .29 0 0 0-.3 .4h.1a.49 .49 0 0 1 .5 .3 .49 .49 0 0 1-.1 .6l-.8 .1 .1-.5a.33 .33 0 0 0 .3 .4 .33 .33 0 0 0 .3-.4l-.1-.1a.51 .51 0 0 1-.5-.2 .51 .51 0 0 1 0-.6z" fill-rule="evenodd"/>
<path d="M271.5 270.3l.4-.1 .2 .1-.1 .2a.28 .28 0 0 0-.4-.3 .28 .28 0 0 0-.1 .5l.2 .3 .4-.2a.43 .43 0 0 1-.6 .3 .43 .43 0 0 1-.1-.7z" fill-rule="evenodd"/>
<path d="M272.4 270.2l.5 .1 .1 .7 .1-.1-.1 .2-.7-.1v-.1l.3 .1 .2-.1v-.3l-.5 .3 .5-.4-.2-.3-.3 .3z" fill-rule="evenodd"/>
<path d="M273.2 269.8l.3-.1v1.3l.2 .1h-.5l.1-.1v-1.1z" fill-rule="evenodd"/>
<path d="M273.9 270.3l.4-.1 .3 .2v.1h-.7l.2 .4 .3 .1 .2-.2a.41 .41 0 0 1-.6 .3 .41 .41 0 0 1-.2-.6h.6l-.2-.3-.4 .3z" fill-rule="evenodd"/>
<path d="M275.4 269.9l.4-.2v1.3l.2 .1h-.6l.2-.1v-1z" fill-rule="evenodd"/>
<path d="M277 269.9l.4-.2v1.3l.2 .1h-.5l.1-.1v-.9v-.2z" fill-rule="evenodd"/>
<path d="M277.9 269.7a1.08 1.08 0 0 1 0 1.9 1.42 1.42 0 0 0 0-1.9z" fill-rule="evenodd"/>
<circle cx="266.2" cy="271" r=".11"/>
<circle cx="276.5" cy="270.3" r=".11"/>
<circle cx="276.5" cy="271" r=".11"/>
</g>
<path d="M297.5 243h-34.5v21" fill="none" stroke="#000" stroke-width=".2"/>
<g fill="#00f">
<path d="M264.8 244.3l.7-.2 .4 .3-.2 .2a.53 .53 0 0 0-.8-.2 .53 .53 0 0 0 0 .8l.4 .3 .3-.1 .1-.3h.2a.74 .74 0 0 1-1.1 .4 .74 .74 0 0 1 0-1.2z" fill-rule="evenodd"/>
<path d="M266.3 244.6a.54 .54 0 0 1 .8 .1 .54 .54 0 0 1-.3 .8 .54 .54 0 0 1-.7-.4h.2a.37 .37 0 0 0 .5 .4 .37 .37 0 0 0 .1-.7l-.4-.1-.2 .4h-.2z" fill-rule="evenodd"/>
<path d="M267.3 244.5h.2v.2l.4-.2 .2 .2 .3-.2 .3 .1 .1 1h-.2l-.1-.9a.26 .26 0 0 0-.3 0 .26 .26 0 0 0 0 .3v.6h-.2l-.1-.8-.3-.1-.1 .9h-.2z" fill-rule="evenodd"/>
<path d="M269.1 244.5h.1v.2l.4-.2 .3 .2 .2-.2 .3 .1 .1 1h-.1l-.1-.9a.26 .26 0 0 0-.3 0 .26 .26 0 0 0-.1 .3v.6h-.2v-.8l-.3-.1-.1 .9h-.2z" fill-rule="evenodd"/>
<path d="M270.9 244.7l.1-.1a.51 .51 0 0 1 .5 0 .51 .51 0 0 1 .3 .5h-.9l.3 .4 .6-.2a.52 .52 0 0 1-.7 .3 .52 .52 0 0 1-.3-.6h.8l-.3-.3-.3 .3h-.2z" fill-rule="evenodd"/>
<path d="M272 244.5h.1v.2l.4-.2a.35 .35 0 0 1 .4 .5v.6h-.2v-.6a.27 .27 0 0 0-.3-.3 .27 .27 0 0 0-.2 .3v.6h-.2z" fill-rule="evenodd"/>
<path d="M273.2 244.3l.2-.1v.3h.2v.2h-.2v.6l.2 .3a.27 .27 0 0 1-.3 0 .27 .27 0 0 1-.1-.3v-.6h-.2z" fill-rule="evenodd"/>
<path d="M273.8 244.6l.5-.1 .2 .3h-.2a.21 .21 0 0 0-.2-.2 .21 .21 0 0 0-.1 .3 .43 .43 0 0 1 .4 .1 .43 .43 0 0 1 .1 .4l-.2 .2h-.4l-.2-.3h.1a.24 .24 0 0 0 .3 .3 .24 .24 0 0 0 .2-.4 .43 .43 0 0 1-.6-.5z" fill-rule="evenodd"/>
<path d="M274.8 244.5h.2v.2h-.2z" fill-rule="evenodd"/>
<path d="M274.8 245.4h.2v.2h-.2z" fill-rule="evenodd"/>
</g>
<g fill="#00007f">
<path d="M264.7 248.7h1l-.9 1.3h.7l.2-.3v.4h-1.2l.9-1.3h-.6l-.1 .3z" fill-rule="evenodd"/>
<path d="M266 248.8l.7-.1v.5a.29 .29 0 0 0-.3-.4 .29 .29 0 0 0-.2 .4h.1a.49 .49 0 0 1 .5 .3 .49 .49 0 0 1-.1 .6l-.8 .1 .1-.5a.33 .33 0 0 0 .3 .4 .33 .33 0 0 0 .2-.4v-.1a.51 .51 0 0 1-.5-.2 .51 .51 0 0 1 0-.6z" fill-rule="evenodd"/>
<path d="M267 248.7h.5l-.1 .1 .3 1 .2-.7-.3-.4h.6l-.2 .2 .3 .9 .3-.9-.1-.2h.4l-.6 1.5-.3-.9-.4 .9z" fill-rule="evenodd"/>
<path d="M269 249.2l.5 .1v.7l.2-.1-.1 .2-.7-.1-.1-.1 .4 .1 .2-.1v-.3l-.6 .3 .6-.4-.2-.3-.3 .3z" fill-rule="evenodd"/>
<path d="M270 248.9v.3h.3h-.3v.7h.3l-.3 .2-.1-.1v-.8h-.2z" fill-rule="evenodd"/>
<path d="M270.5 249.3l.4-.1 .2 .1-.1 .2a.28 .28 0 0 0-.4-.3 .28 .28 0 0 0-.1 .5l.3 .3 .3-.2a.43 .43 0 0 1-.6 .3 .43 .43 0 0 1-.1-.7z" fill-rule="evenodd"/>
<path d="M271.2 248.8l.3-.1v.7l.3-.2h.2l.1 .8 .1 .1h-.4l.1-.2v-.5l-.1-.1-.3 .1 .1 .6 .1 .1h-.5l.2-.1v-.9v-.3z" fill-rule="evenodd"/>
</g>
<path d="M263 243h-42v42M297.5 243h69" fill="none" stroke="#000" stroke-width=".2"/>
<g fill="#000">
<path d="M17.1 17.5a5.9 5.9 0 0 1 2.7 .1 1.87 1.87 0 0 1 .9 2.2 1.87 1.87 0 0 1-2 1.4h-1.6l.4-.2 .1-.4h.9v.2a.65 .65 0 0 0 .7 .2 .65 .65 0 0 0 .4-.6 2.07 2.07 0 0 0-.6-2.7h-.5v2.9h-.9v-2.8z" fill-rule="evenodd"/>
<path d="M21.7 18.8a1.29 1.29 0 0 1 1.9 1.1 1.29 1.29 0 0 1-1.9 1.1l-.4-.9h.7l.1 .6a.35 .35 0 0 0 .3 .3 .35 .35 0 0 0 .4-.3v-1.7a.37 .37 0 0 0-.5-.3 .37 .37 0 0 0-.2 .5l-.1 .9h-.7v-.7z" fill-rule="evenodd"/>
<path d="M26.5 17.5h1.1v2.4l.8-.9v-.2l-.3-.2h1.2l-1.1 .9 1.3 1.7h-1.3l.1-.3-.6-.9-.1 .1v.8l.2 .3h-1.3l.2-.2 .1-.4v-2.9z" fill-rule="evenodd"/>
<path d="M29.6 19.6h1.6v.6h-1.6z" fill-rule="evenodd"/>
<path d="M31.4 17.5h2l-.5 .2-.1 1.4h1.3v-1a.53 .53 0 0 0-.5-.6h2l-.5 .2-.1 .4v2.7l.6 .4h-2l.5-.3v-1.5h-1.3l.1 1.5 .5 .3h-2l.5-.2v-.5v-2.7z" fill-rule="evenodd"/>
<path d="M35.7 17.5h1.6l-.3 .2v.2l.8 2.1 .6-1.4a1.18 1.18 0 0 0-.7-1.1h1.8l-.4 .2 .8 2.2 .7-1.9v-.3l-.4-.2h1l-.3 .3-1.3 3.4-1.1-2.3-1.1 2.3-1.4-3.4z" fill-rule="evenodd"/>
<path d="M42.7 17.5h3.1v1h-.1a.94 .94 0 0 0-1.3-.8h-.3v1.5a.9 .9 0 0 0 1-.8v1.9a.95 .95 0 0 0-1-.9v1.5l.5 .3h-1.9l.4-.2 .1-.5v-2.7z" fill-rule="evenodd"/>
<path d="M46.4 18.9a1.05 1.05 0 0 1 1.2-.4 1.05 1.05 0 0 1 .7 1v1.2h.3a.52 .52 0 0 1-.5 .5 .52 .52 0 0 1-.5-.4 .75 .75 0 0 1-.7 .4 .75 .75 0 0 1-.7-.4l.1-.4h.7l.3 .3 .3-.1v-.9l-.5 .4-.1 .3h-.7l.4-.4 .9-.4v-.6a.33 .33 0 0 0-.5-.3 .33 .33 0 0 0-.1 .6 .39 .39 0 0 1-.6 .3 .39 .39 0 0 1 0-.7z" fill-rule="evenodd"/>
<path d="M48.9 17.5h1v1.4a1.05 1.05 0 0 1 1.4-.1 1.05 1.05 0 0 1 .3 1.3 1.17 1.17 0 0 1-.7 1 1.17 1.17 0 0 1-1.2-.1l-.5 .2v-2.1h.7l.1 1.6a.4 .4 0 0 0 .4 .4 .4 .4 0 0 0 .4-.4v-1.3a.46 .46 0 0 0-.3-.5 .46 .46 0 0 0-.6 .2h-.7v-1.3z" fill-rule="evenodd"/>
<path d="M52.1 18.6h1v.6a.68 .68 0 0 1 .4-.6 .68 .68 0 0 1 .8 .1 .4 .4 0 0 1-.2 .6 .4 .4 0 0 1-.6-.2l-.3 .3-.1 1.2a.46 .46 0 0 0 .4 .6h-1.4l.2-.2 .1-.4v-1.6z" fill-rule="evenodd"/>
<path d="M54.5 18.6h1l.1 2.3 .3 .3h-1.4l.2-.2 .1-.4v-1.7z" fill-rule="evenodd"/>
<path d="M58.9 18.9a1.05 1.05 0 0 1 1.1-.4 1.05 1.05 0 0 1 .8 1v1.2h.2a.52 .52 0 0 1-.5 .5 .52 .52 0 0 1-.5-.4 .75 .75 0 0 1-.6 .4 .75 .75 0 0 1-.7-.4v-.4h.7l.3 .3 .3-.1v-.9l-.5 .4-.1 .3h-.7l.4-.4 .9-.4v-.6a.33 .33 0 0 0-.5-.3 .33 .33 0 0 0 0 .6 .39 .39 0 0 1-.6 .3 .39 .39 0 0 1 0-.7z" fill-rule="evenodd"/>
<path d="M62.3 17.7l.1 .9h.6v.3h-.6v1.8l.2 .2 .3-.3a.68 .68 0 0 1-.8 .6 .68 .68 0 0 1-.5-.9v-1.4l-.3-.1z" fill-rule="evenodd"/>
<path d="M63.2 18.6h1.1v2.3l.3 .3h-1.4l.2-.2 .1-.4v-1.7z" fill-rule="evenodd"/>
<path d="M65.3 18.8a1.29 1.29 0 0 1 1.9 1.1 1.29 1.29 0 0 1-1.9 1.1l-.5-.9h.8l.1 .6a.35 .35 0 0 0 .3 .3 .35 .35 0 0 0 .4-.3v-1.7a.37 .37 0 0 0-.5-.3 .37 .37 0 0 0-.2 .5l-.1 .9h-.8l.1-.7z" fill-rule="evenodd"/>
<path d="M67.6 18.6h1.1v.4a.79 .79 0 0 1 1-.4 .79 .79 0 0 1 .4 1v1.3l.3 .3h-1.3l.2-.3v-1.7a.28 .28 0 0 0-.2-.3 .28 .28 0 0 0-.3 .2l-.1 .2v1.6l.2 .3h-1.3l.2-.2 .1-.4v-1.7z" fill-rule="evenodd"/>
<path d="M72 17.5a5.9 5.9 0 0 1 2.7 .1 1.87 1.87 0 0 1 1 2.2 1.87 1.87 0 0 1-2 1.4h-1.7l.4-.2 .1-.4h.9v.2a.65 .65 0 0 0 .7 .2 .65 .65 0 0 0 .5-.6 2.08 2.08 0 0 0-.7-2.7h-.5v2.9h-.9v-2.8z" fill-rule="evenodd"/>
<path d="M76.7 18.8a1.29 1.29 0 0 1 1.9 1.1 1.29 1.29 0 0 1-1.9 1.1l-.5-.9h.8v.6a.35 .35 0 0 0 .3 .3 .35 .35 0 0 0 .4-.3v-1.7a.37 .37 0 0 0-.5-.3 .37 .37 0 0 0-.2 .5v.9h-.8l.1-.7z" fill-rule="evenodd"/>
<path d="M81.4 18.6h1.1v2a.27 .27 0 0 0 .2 .3 .27 .27 0 0 0 .3-.2l.1-.2v-1.3v-.4l-.2-.2h1v2.3l.3 .3h-1.1v-.4a.79 .79 0 0 1-1 .4 .79 .79 0 0 1-.4-1v-1.3z" fill-rule="evenodd"/>
<path d="M84.6 18.6h1v.4a.79 .79 0 0 1 .8-.5 .79 .79 0 0 1 .7 .5 .82 .82 0 0 1 1-.4 .82 .82 0 0 1 .5 1v1.3l.3 .3h-1.3l.2-.3v-1.7a.31 .31 0 0 0-.2-.3 .31 .31 0 0 0-.4 .2l-.1 .1v1.7l.3 .3h-1.3l.2-.4v-1.6a.3 .3 0 0 0-.2-.3 .3 .3 0 0 0-.3 .2l-.2 .1v1.4l.1 .4 .2 .2h-1.3l.2-.2v-.4v-1.7z" fill-rule="evenodd"/>
<path d="M89.6 18.9a1.03 1.03 0 0 1 1.2-.3 1.03 1.03 0 0 1 .6 1.2h-1.4a.72 .72 0 0 0 .4 .9 .72 .72 0 0 0 .9-.3 .93 .93 0 0 1-1.2 .8 1.26 1.26 0 0 1-.8-1.7l1.4 .1v-.6l-.3-.3-.4 .3v.5h-.7z" fill-rule="evenodd"/>
<path d="M91.7 18.6h1v.4a.79 .79 0 0 1 1.1-.4 .79 .79 0 0 1 .4 1v1.3l.3 .3h-1.3l.2-.3v-1.7a.28 .28 0 0 0-.2-.3 .28 .28 0 0 0-.3 .2l-.2 .2 .1 1.6 .2 .3h-1.3l.2-.2 .1-.4v-1.7z" fill-rule="evenodd"/>
<path d="M95.7 17.7l.1 .9h.6v.3h-.6v1.8l.2 .2 .3-.3a.68 .68 0 0 1-.8 .6 .68 .68 0 0 1-.4-.9v-1.4l-.4-.1z" fill-rule="evenodd"/>
<path d="M24.5 18.8a.84 .84 0 0 1 1-.3 .84 .84 0 0 1 .5 .9 .46 .46 0 0 1-.5 0 .46 .46 0 0 1-.1-.5l-.3-.2a1.36 1.36 0 0 0 .5 2.1l.5-.3a1.02 1.02 0 0 1-1 .7 1.02 1.02 0 0 1-1-.8v-.7z" fill-rule="evenodd"/>
<path d="M56.6 18.8a.84 .84 0 0 1 1-.3 .84 .84 0 0 1 .5 .9 .46 .46 0 0 1-.5 0 .46 .46 0 0 1-.2-.5l-.2-.2a1.29 1.29 0 0 0 .5 2.1l.5-.3a.99 .99 0 0 1-.8 .7 .99 .99 0 0 1-1-.3 1.58 1.58 0 0 1 .2-2.1z" fill-rule="evenodd"/>
<path d="M79.4 18.8a.84 .84 0 0 1 1-.3 .84 .84 0 0 1 .6 .9 .46 .46 0 0 1-.6 0 .46 .46 0 0 1-.1-.5l-.3-.2a1.36 1.36 0 0 0 .5 2.1l.5-.3a.99 .99 0 0 1-.7 .7 .99 .99 0 0 1-1-.3 1.58 1.58 0 0 1 .1-2.1z" fill-rule="evenodd"/>
<path d="M193.8 64.7h1.5a.8 .8 0 0 1 .9 .2 .8 .8 0 0 1 .1 1l-.5 .3a.79 .79 0 0 1 .8 .8 .79 .79 0 0 1-.9 .7h-1.9l.4-.1 .1-.3h.7a.53 .53 0 0 0 .7 .1 .53 .53 0 0 0 .1-.7l-.3-.4h-.5v1h-.7v-1.2h.7a.61 .61 0 0 0 .7-.6 .61 .61 0 0 0-.7-.6v1.2h-.7l-.1-1.1z" fill-rule="evenodd"/>
<path d="M198.6 65.1a2.37 2.37 0 0 1 2.1-.3l.2-.1v1a1.05 1.05 0 0 0-1.3-.8 1.05 1.05 0 0 0-.7 1.3 1.09 1.09 0 0 0 .6 1.3 1.09 1.09 0 0 0 1.3-.4v.2a1.58 1.58 0 0 1-2.2 .1 1.58 1.58 0 0 1 0-2.3z" fill-rule="evenodd"/>
<path d="M201.3 65.7h.8v1.6a.22 .22 0 0 0 .2 .2 .22 .22 0 0 0 .2-.1l.2-.2v-1.1l-.3-.4h.9v1.8l.2 .2h-.8v-.2a.64 .64 0 0 1-.9 .3 .64 .64 0 0 1-.3-.9v-1z" fill-rule="evenodd"/>
<path d="M205.5 65.1l.7-.4a3.2 3.2 0 0 0-.2 3.7l.2 .2a2.2 2.2 0 0 1-.7-3.5z" fill-rule="evenodd"/>
<path d="M206.8 64.9a1.69 1.69 0 0 1 1.5 0l.1-.2v1a.84 .84 0 0 0-.5-.7 .84 .84 0 0 0-.9 .1l.1 .4a2.28 2.28 0 0 1 1.5 1.4 1.2 1.2 0 0 1-1.8 .7l-.3 .2v-1.1a.98 .98 0 0 0 1.5 .7 .62 .62 0 0 0-.5-.8 .99 .99 0 0 1-.9-.6 .99 .99 0 0 1 .2-1.1z" fill-rule="evenodd"/>
<path d="M209.3 65.9a.68 .68 0 0 1 .8-.3 .68 .68 0 0 1 .5 .7 .41 .41 0 0 1-.5 0 .41 .41 0 0 1-.1-.5h-.1a.99 .99 0 0 0 .4 1.6l.3-.2a.89 .89 0 0 1-1.1 .5 .89 .89 0 0 1-.5-1.2z" fill-rule="evenodd"/>
<path d="M211.2 65.9a.85 .85 0 0 1 .9-.3 .85 .85 0 0 1 .6 .8v1h.2a.42 .42 0 0 1-.4 .4 .42 .42 0 0 1-.4-.4 .56 .56 0 0 1-.6 .4 .56 .56 0 0 1-.5-.4v-.2h.6l.2 .2 .3-.1v-.7l-.5 .6h-.6l.4-.4 .7-.4v-.4a.27 .27 0 0 0-.4-.2 .27 .27 0 0 0 0 .4 .32 .32 0 0 1-.5 .2 .32 .32 0 0 1 0-.5z" fill-rule="evenodd"/>
<path d="M213.2 64.7h.8v2.8l.3 .2h-1.1l.2-.4v-2.3z" fill-rule="evenodd"/>
<path d="M214.8 65.9a.83 .83 0 0 1 1-.2 .83 .83 0 0 1 .4 .9h-1.1a.58 .58 0 0 0 .3 .8 .58 .58 0 0 0 .7-.3 .85 .85 0 0 1-1 .7 .85 .85 0 0 1-.6-1.1v-.3l1.2 .1-.2-.7a.39 .39 0 0 0-.4 .2 .39 .39 0 0 0 0 .4h-.6z" fill-rule="evenodd"/>
<path d="M217.7 65.2l1.2-.5v2.7l.1 .2 .4 .1h-1.6l.4-.2 .1-1.9-.1-.4z" fill-rule="evenodd"/>
<path d="M221.5 65.2l1.2-.5v2.4a.46 .46 0 0 0 .4 .6h-1.6l.5-.2v-1.9l-.1-.4z" fill-rule="evenodd"/>
<path d="M223.5 64.7a2.18 2.18 0 0 1 1.3 2 2.18 2.18 0 0 1-1.3 1.9 3.2 3.2 0 0 0 .2-3.7z" fill-rule="evenodd"/>
<circle cx="55.2" cy="17.8" r=".42"/>
<circle cx="63.9" cy="17.8" r=".42"/>
<circle cx="197.3" cy="67.4" r=".36"/>
<circle cx="220.5" cy="67.4" r=".36"/>
<circle cx="220.5" cy="66" r=".36"/>
</g>
<g fill="#00007f">
<path d="M392.6 248.8l.3-.1v1.3h.2l-.6 .2-.4-.2v-.4h.2l.1 .4 .3-.1-.1-.7-.2 .1-.1 .3h-.2v-.1a.4 .4 0 0 1 .6-.3v-.4z" fill-rule="evenodd"/>
<path d="M393.3 248.8a.42 .42 0 0 1 .6 .1 .42 .42 0 0 1-.2 .6l-.4 .5 .7-.1-.1 .2h-.8a.87 .87 0 0 0 .6-1.2h-.3l-.3 .2z" fill-rule="evenodd"/>
<path d="M394.3 249.2l.5 .1 .1 .7 .1-.1-.1 .2-.7-.1v-.1l.3 .1 .2-.1v-.3l-.5 .3 .5-.4-.2-.3-.2 .3z" fill-rule="evenodd"/>
<path d="M395.3 248.9l.3-.2 .1 1.3 .1 .1h-.5l.2-.1v-.9v-.2z" fill-rule="evenodd"/>
<path d="M396.5 248.9l.5-.2-.4 .2-.2 .4a.43 .43 0 0 1 .6 .3 .43 .43 0 0 1-.4 .6 .43 .43 0 0 1-.4-.6h.2a.31 .31 0 0 0 .1 .4 .31 .31 0 0 0 .4 0 .31 .31 0 0 0-.1-.5l-.2-.2-.2 .1v.2h-.2z" fill-rule="evenodd"/>
<path d="M397.5 248.8l.3-.1 .2 .1v.1l-.3-.2-.1 .1v.4h.2h-.2v.8l.2 .1h-.6l.2-.1v-.8h-.2h.2z" fill-rule="evenodd"/>
<path d="M398.1 248.8a.61 .61 0 0 1 .7 .4 .61 .61 0 0 1-.3 .8l-.6 .1 .4-.2 .3-.4h-.5a.24 .24 0 0 1-.2-.2 .24 .24 0 0 1 .2-.2l.1 .3a.34 .34 0 0 0 .4-.2 .34 .34 0 0 0-.3-.4l-.2 .3h-.2z" fill-rule="evenodd"/>
</g>
<path d="M390.5 243v10.5" fill="none" stroke="#000" stroke-width=".2"/>
<g fill="#00f">
<path d="M392.3 244.3l.8-.2 .3 .3 .1 .1-.2 .1a.58 .58 0 0 0-.8-.2 .58 .58 0 0 0-.2 .8 .58 .58 0 0 0 .8 .2l.2-.1v-.3h-.4v-.1h.6v.5a.81 .81 0 0 1-1.2 .1 .81 .81 0 0 1 0-1.2z" fill-rule="evenodd"/>
<path d="M393.8 244.1h.2v.2h-.2z" fill-rule="evenodd"/>
<path d="M393.8 244.5h.2v1.1h-.2z" fill-rule="evenodd"/>
<path d="M394.3 244.3l.2-.1v.3h.1v.2h-.1v.6l.2 .3a.27 .27 0 0 1-.3 0 .27 .27 0 0 1-.1-.3v-.6h-.2z" fill-rule="evenodd"/>
<path d="M395.4 244.1h.2v.6h.8v-.6h.2v1.5h-.2v-.7h-.8v.7h-.2z" fill-rule="evenodd"/>
<path d="M397 244.6l.1-.1a.47 .47 0 0 1 .6 .1 .47 .47 0 0 1 .1 .6l.1 .4-.3-.1-.5 .1-.2-.1v-.2l.6 .2 .1-.4-.7 .2a.57 .57 0 0 1 .7-.4l-.2-.2-.5 .1z" fill-rule="evenodd"/>
<path d="M398.1 244.6l.6-.1 .2 .3h-.2a.21 .21 0 0 0-.3-.2 .21 .21 0 0 0-.1 .3 .43 .43 0 0 1 .5 .1 .43 .43 0 0 1 .1 .4l-.3 .2h-.3l-.3-.3h.2a.24 .24 0 0 0 .3 .3 .24 .24 0 0 0 .1-.4 .43 .43 0 0 1-.5-.5z" fill-rule="evenodd"/>
<path d="M399.1 244.1h.2v.6l.3-.2 .4 .1v1h-.2v-.7a.27 .27 0 0 0-.3-.2 .27 .27 0 0 0-.2 .3v.6h-.2z" fill-rule="evenodd"/>
<path d="M400.4 244.5h.2v.2h-.2z" fill-rule="evenodd"/>
<path d="M400.4 245.4h.2v.2h-.2z" fill-rule="evenodd"/>
</g>
<use href="#words"/>
</svg>
